# Scaled down LEF created by ScaleLEFMacro.pl
# Original LEF: 16nm/HD_1024X96M8B2.lef
# Don't forget to change metal layer LEF separately!

# Copyright (c) 1993 - 2021 ARM Limited. All Rights Reserved.
# Use of this Software is subject to the terms and conditions of the
# applicable license agreement with ARM Limited.

# PhyVGen V 8.22.0
# ARM Version r3p2
# Creation Date: Thu Sep  9 16:14:09 2021


# Memory Configuration:
# ~~~~~~~~~~~~~~~~~~~~~
#  -activity_factor 50 -atf off -back_biasing off -bits 96 -bmux on
# -bus_notation on -check_instname on -compiler_type sp -diodes on -drive 6
# -ema on -flexible_banking 2 -frequency 1000 -instname HD_1024X96M8B2
# -left_bus_delim "[" -lren_bankmask off -metal_stack 2Xa1Xd -mux 8 -mvt LP
# -name_case upper -pipeline off -power_gating off -power_type otc -prefix ""
# -pwr_gnd_rename vddpe:VDDPE,vddce:VDDCE,vsse:VSSE -rcols 2 -redundancy off
# -retention on -right_bus_delim "]" -rows_p_bl 256 -rrows 0 -scan on -ser none
# -site_def off -top_layer m5-m10 -vmin_assist on -words 1024 -write_mask on
# -write_thru off -corners tt_0p80v_0p80v_25c
# 

VERSION 5.7 ;
BUSBITCHARS "[]" ;
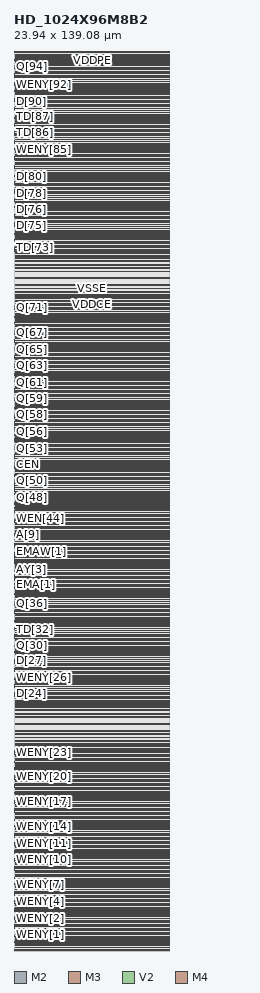
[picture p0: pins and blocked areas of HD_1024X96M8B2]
MACRO HD_1024X96M8B2
	FOREIGN HD_1024X96M8B2 0 0 ;
	SYMMETRY X Y ;
	SIZE 23.94 BY 139.08 ;
	CLASS BLOCK ;
	PIN AY[0]
		USE SIGNAL ;
		DIRECTION OUTPUT ;
		SHAPE ABUTMENT ;
		PORT
			 LAYER M2 ;
			RECT 0.0714 74.6227 0.1097 74.6604 ;
			 LAYER M3 ;
			RECT 0.0714 74.56 0.1097 74.6604 ;
			 LAYER V2 ;
			RECT 0.0831 74.6357 0.098 74.6482 ;
		END

		ANTENNADIFFAREA 0.00194719 ;
		ANTENNAPARTIALMETALAREA 0.00195671 ;
	END AY[0]

	PIN AY[1]
		USE SIGNAL ;
		DIRECTION OUTPUT ;
		SHAPE ABUTMENT ;
		PORT
			 LAYER M2 ;
			RECT 0.0098 73.3553 0.0481 73.3929 ;
			 LAYER M3 ;
			RECT 0.0098 73.3553 0.0481 73.4557 ;
			 LAYER V2 ;
			RECT 0.0215 73.3682 0.0364 73.3808 ;
		END

		ANTENNADIFFAREA 0.00194719 ;
		ANTENNAPARTIALMETALAREA 0.00195671 ;
	END AY[1]

	PIN AY[2]
		USE SIGNAL ;
		DIRECTION OUTPUT ;
		SHAPE ABUTMENT ;
		PORT
			 LAYER M2 ;
			RECT 0.0714 72.2886 0.1097 72.3263 ;
			 LAYER M3 ;
			RECT 0.0714 72.2259 0.1097 72.3263 ;
			 LAYER V2 ;
			RECT 0.0831 72.3016 0.098 72.3141 ;
		END

		ANTENNADIFFAREA 0.00194719 ;
		ANTENNAPARTIALMETALAREA 0.00195671 ;
	END AY[2]

	PIN AY[3]
		USE SIGNAL ;
		DIRECTION OUTPUT ;
		SHAPE ABUTMENT ;
		PORT
			 LAYER M2 ;
			RECT 0.0714 58.9114 0.1097 58.949 ;
			 LAYER M3 ;
			RECT 0.0714 58.9114 0.1097 59.0118 ;
			 LAYER V2 ;
			RECT 0.0831 58.9235 0.098 58.9361 ;
		END

		ANTENNADIFFAREA 0.00194719 ;
		ANTENNAPARTIALMETALAREA 0.00195671 ;
	END AY[3]

	PIN AY[4]
		USE SIGNAL ;
		DIRECTION OUTPUT ;
		SHAPE ABUTMENT ;
		PORT
			 LAYER M2 ;
			RECT 0.0098 68.2353 0.0481 68.2729 ;
			 LAYER M3 ;
			RECT 0.0098 68.1725 0.0481 68.2729 ;
			 LAYER V2 ;
			RECT 0.0215 68.2475 0.0364 68.26 ;
		END

		ANTENNADIFFAREA 0.00194719 ;
		ANTENNAPARTIALMETALAREA 0.00195671 ;
	END AY[4]

	PIN AY[5]
		USE SIGNAL ;
		DIRECTION OUTPUT ;
		SHAPE ABUTMENT ;
		PORT
			 LAYER M2 ;
			RECT 0.0098 61.8478 0.0481 61.9482 ;
			 LAYER M3 ;
			RECT 0.0098 61.8478 0.0481 61.9482 ;
			 LAYER V2 ;
			RECT 0.021 61.8608 0.0359 61.8733 ;
		END

		ANTENNADIFFAREA 0.00194719 ;
		ANTENNAPARTIALMETALAREA 0.00195671 ;
	END AY[5]

	PIN AY[6]
		USE SIGNAL ;
		DIRECTION OUTPUT ;
		SHAPE ABUTMENT ;
		PORT
			 LAYER M2 ;
			RECT 0.0714 59.3631 0.1097 59.4008 ;
			 LAYER M3 ;
			RECT 0.0714 59.3631 0.1097 59.4635 ;
			 LAYER V2 ;
			RECT 0.0831 59.3753 0.098 59.3878 ;
		END

		ANTENNADIFFAREA 0.00194719 ;
		ANTENNAPARTIALMETALAREA 0.00195671 ;
	END AY[6]

	PIN AY[7]
		USE SIGNAL ;
		DIRECTION OUTPUT ;
		SHAPE ABUTMENT ;
		PORT
			 LAYER M2 ;
			RECT 0.0098 60.4925 0.0481 60.5929 ;
			 LAYER M3 ;
			RECT 0.0098 60.4925 0.0481 60.5929 ;
			 LAYER V2 ;
			RECT 0.021 60.5675 0.0359 60.58 ;
		END

		ANTENNADIFFAREA 0.00194719 ;
		ANTENNAPARTIALMETALAREA 0.00195671 ;
	END AY[7]

	PIN AY[8]
		USE SIGNAL ;
		DIRECTION OUTPUT ;
		SHAPE ABUTMENT ;
		PORT
			 LAYER M2 ;
			RECT 0.0098 63.1153 0.0481 63.1529 ;
			 LAYER M3 ;
			RECT 0.0098 63.0525 0.0481 63.1529 ;
			 LAYER V2 ;
			RECT 0.0215 63.1275 0.0364 63.14 ;
		END

		ANTENNADIFFAREA 0.00194719 ;
		ANTENNAPARTIALMETALAREA 0.00195671 ;
	END AY[8]

	PIN AY[9]
		USE SIGNAL ;
		DIRECTION OUTPUT ;
		SHAPE ABUTMENT ;
		PORT
			 LAYER M2 ;
			RECT 0.0714 64.4078 0.1097 64.4455 ;
			 LAYER M3 ;
			RECT 0.0714 64.4078 0.1097 64.5082 ;
			 LAYER V2 ;
			RECT 0.0831 64.42 0.098 64.4325 ;
		END

		ANTENNADIFFAREA 0.00194719 ;
		ANTENNAPARTIALMETALAREA 0.00195671 ;
	END AY[9]

	PIN A[0]
		USE SIGNAL ;
		DIRECTION INPUT ;
		SHAPE ABUTMENT ;
		PORT
			 LAYER M2 ;
			RECT 0.0098 74.7106 0.0481 74.7482 ;
			 LAYER M3 ;
			RECT 0.0098 74.7106 0.0481 74.811 ;
			 LAYER V2 ;
			RECT 0.0215 74.7235 0.0364 74.7361 ;
		END

		ANTENNAGATEAREA 0.00027817 ;
		ANTENNADIFFAREA 0.00194719 ;
		ANTENNAPARTIALMETALAREA 0.00195671 ;
	END A[0]

	PIN A[1]
		USE SIGNAL ;
		DIRECTION INPUT ;
		SHAPE ABUTMENT ;
		PORT
			 LAYER M2 ;
			RECT 0.0714 73.418 0.1097 73.4557 ;
			 LAYER M3 ;
			RECT 0.0714 73.3553 0.1097 73.4557 ;
			 LAYER V2 ;
			RECT 0.0831 73.431 0.098 73.4435 ;
		END

		ANTENNAGATEAREA 0.00027817 ;
		ANTENNADIFFAREA 0.00194719 ;
		ANTENNAPARTIALMETALAREA 0.00195671 ;
	END A[1]

	PIN A[2]
		USE SIGNAL ;
		DIRECTION INPUT ;
		SHAPE ABUTMENT ;
		PORT
			 LAYER M2 ;
			RECT 0.0098 71.7741 0.0481 71.8745 ;
			 LAYER M3 ;
			RECT 0.0098 71.7741 0.0481 71.8745 ;
			 LAYER V2 ;
			RECT 0.021 71.849 0.0359 71.8616 ;
		END

		ANTENNAGATEAREA 0.00027817 ;
		ANTENNADIFFAREA 0.00194719 ;
		ANTENNAPARTIALMETALAREA 0.00195671 ;
	END A[2]

	PIN A[3]
		USE SIGNAL ;
		DIRECTION INPUT ;
		SHAPE ABUTMENT ;
		PORT
			 LAYER M2 ;
			RECT 0.0098 59.1247 0.0481 59.1624 ;
			 LAYER M3 ;
			RECT 0.0098 59.062 0.0481 59.1624 ;
			 LAYER V2 ;
			RECT 0.0215 59.1369 0.0364 59.1494 ;
		END

		ANTENNAGATEAREA 0.00027817 ;
		ANTENNADIFFAREA 0.00194719 ;
		ANTENNAPARTIALMETALAREA 0.00195671 ;
	END A[3]

	PIN A[4]
		USE SIGNAL ;
		DIRECTION INPUT ;
		SHAPE ABUTMENT ;
		PORT
			 LAYER M2 ;
			RECT 0.0098 68.4612 0.0481 68.4988 ;
			 LAYER M3 ;
			RECT 0.0098 68.3984 0.0481 68.4988 ;
			 LAYER V2 ;
			RECT 0.0215 68.4733 0.0364 68.4859 ;
		END

		ANTENNAGATEAREA 0.00027817 ;
		ANTENNADIFFAREA 0.00194719 ;
		ANTENNAPARTIALMETALAREA 0.00195671 ;
	END A[4]

	PIN A[5]
		USE SIGNAL ;
		DIRECTION INPUT ;
		SHAPE ABUTMENT ;
		PORT
			 LAYER M2 ;
			RECT 0.0098 60.1035 0.0481 60.1412 ;
			 LAYER M3 ;
			RECT 0.0098 60.0408 0.0481 60.1412 ;
			 LAYER V2 ;
			RECT 0.0215 60.1157 0.0364 60.1282 ;
		END

		ANTENNAGATEAREA 0.00027817 ;
		ANTENNADIFFAREA 0.00194719 ;
		ANTENNAPARTIALMETALAREA 0.00195671 ;
	END A[5]

	PIN A[6]
		USE SIGNAL ;
		DIRECTION INPUT ;
		SHAPE ABUTMENT ;
		PORT
			 LAYER M2 ;
			RECT 0.0098 59.4259 0.0481 59.4635 ;
			 LAYER M3 ;
			RECT 0.0098 59.3631 0.0481 59.4635 ;
			 LAYER V2 ;
			RECT 0.0215 59.438 0.0364 59.4506 ;
		END

		ANTENNAGATEAREA 0.00027817 ;
		ANTENNADIFFAREA 0.00194719 ;
		ANTENNAPARTIALMETALAREA 0.00195671 ;
	END A[6]

	PIN A[7]
		USE SIGNAL ;
		DIRECTION INPUT ;
		SHAPE ABUTMENT ;
		PORT
			 LAYER M2 ;
			RECT 0.0714 60.342 0.1097 60.3796 ;
			 LAYER M3 ;
			RECT 0.0714 60.342 0.1097 60.4424 ;
			 LAYER V2 ;
			RECT 0.0831 60.3541 0.098 60.3667 ;
		END

		ANTENNAGATEAREA 0.00027817 ;
		ANTENNADIFFAREA 0.00194719 ;
		ANTENNAPARTIALMETALAREA 0.00195671 ;
	END A[7]

	PIN A[8]
		USE SIGNAL ;
		DIRECTION INPUT ;
		SHAPE ABUTMENT ;
		PORT
			 LAYER M2 ;
			RECT 0.0098 62.7388 0.0481 62.7765 ;
			 LAYER M3 ;
			RECT 0.0098 62.6761 0.0481 62.7765 ;
			 LAYER V2 ;
			RECT 0.0215 62.751 0.0364 62.7635 ;
		END

		ANTENNAGATEAREA 0.00027817 ;
		ANTENNADIFFAREA 0.00194719 ;
		ANTENNAPARTIALMETALAREA 0.00195671 ;
	END A[8]

	PIN A[9]
		USE SIGNAL ;
		DIRECTION INPUT ;
		SHAPE ABUTMENT ;
		PORT
			 LAYER M2 ;
			RECT 0.0098 64.32 0.0481 64.3576 ;
			 LAYER M3 ;
			RECT 0.0098 64.2573 0.0481 64.3576 ;
			 LAYER V2 ;
			RECT 0.0215 64.3322 0.0364 64.3447 ;
		END

		ANTENNAGATEAREA 0.00027817 ;
		ANTENNADIFFAREA 0.00194719 ;
		ANTENNAPARTIALMETALAREA 0.00195671 ;
	END A[9]

	PIN CEN
		USE SIGNAL ;
		DIRECTION INPUT ;
		SHAPE ABUTMENT ;
		PORT
			 LAYER M2 ;
			RECT 0.0098 75.1624 0.0481 75.2 ;
			 LAYER M3 ;
			RECT 0.0098 75.1624 0.0481 75.2627 ;
			 LAYER V2 ;
			RECT 0.0215 75.1753 0.0364 75.1878 ;
		END

		ANTENNAGATEAREA 0.00027817 ;
		ANTENNADIFFAREA 0.00194719 ;
		ANTENNAPARTIALMETALAREA 0.00195671 ;
	END CEN

	PIN CENY
		USE SIGNAL ;
		DIRECTION OUTPUT ;
		SHAPE ABUTMENT ;
		PORT
			 LAYER M2 ;
			RECT 0.0098 75.0118 0.0481 75.0494 ;
			 LAYER M3 ;
			RECT 0.0098 75.0118 0.0481 75.1122 ;
			 LAYER V2 ;
			RECT 0.0215 75.0247 0.0364 75.0373 ;
		END

		ANTENNADIFFAREA 0.00194719 ;
		ANTENNAPARTIALMETALAREA 0.00195671 ;
	END CENY

	PIN CLK
		USE SIGNAL ;
		DIRECTION INPUT ;
		SHAPE ABUTMENT ;
		PORT
			 LAYER M2 ;
			RECT 0.0098 77.2706 0.0481 77.371 ;
			 LAYER M3 ;
			RECT 0.0098 77.2706 0.0481 77.371 ;
			 LAYER V2 ;
			RECT 0.021 77.3455 0.0359 77.358 ;
		END

		ANTENNAGATEAREA 0.00027817 ;
		ANTENNADIFFAREA 0.00194719 ;
		ANTENNAPARTIALMETALAREA 0.00195671 ;
	END CLK

	PIN DFTRAMBYP
		USE SIGNAL ;
		DIRECTION INPUT ;
		SHAPE ABUTMENT ;
		PORT
			 LAYER M2 ;
			RECT 0.0098 82.3153 0.0481 82.3529 ;
			 LAYER M3 ;
			RECT 0.0098 82.3153 0.0481 82.4157 ;
			 LAYER V2 ;
			RECT 0.0215 82.3282 0.0364 82.3408 ;
		END

		ANTENNAGATEAREA 0.00027817 ;
		ANTENNADIFFAREA 0.00194719 ;
		ANTENNAPARTIALMETALAREA 0.00195671 ;
	END DFTRAMBYP

	PIN D[0]
		USE SIGNAL ;
		DIRECTION INPUT ;
		SHAPE ABUTMENT ;
		PORT
			 LAYER M2 ;
			RECT 0.0098 1.3678 0.0481 1.4055 ;
			 LAYER M3 ;
			RECT 0.0098 1.3678 0.0481 1.4682 ;
			 LAYER V2 ;
			RECT 0.0215 1.3808 0.0364 1.3933 ;
		END

		ANTENNAGATEAREA 0.00027817 ;
		ANTENNADIFFAREA 0.00194719 ;
		ANTENNAPARTIALMETALAREA 0.00195671 ;
	END D[0]

	PIN D[10]
		USE SIGNAL ;
		DIRECTION INPUT ;
		SHAPE ABUTMENT ;
		PORT
			 LAYER M2 ;
			RECT 0.0098 14.1678 0.0481 14.2055 ;
			 LAYER M3 ;
			RECT 0.0098 14.1678 0.0481 14.2682 ;
			 LAYER V2 ;
			RECT 0.0215 14.1808 0.0364 14.1933 ;
		END

		ANTENNAGATEAREA 0.00027817 ;
		ANTENNADIFFAREA 0.00194719 ;
		ANTENNAPARTIALMETALAREA 0.00195671 ;
	END D[10]

	PIN D[11]
		USE SIGNAL ;
		DIRECTION INPUT ;
		SHAPE ABUTMENT ;
		PORT
			 LAYER M2 ;
			RECT 0.0098 15.4478 0.0481 15.4855 ;
			 LAYER M3 ;
			RECT 0.0098 15.4478 0.0481 15.5482 ;
			 LAYER V2 ;
			RECT 0.0215 15.4608 0.0364 15.4733 ;
		END

		ANTENNAGATEAREA 0.00027817 ;
		ANTENNADIFFAREA 0.00194719 ;
		ANTENNAPARTIALMETALAREA 0.00195671 ;
	END D[11]

	PIN D[12]
		USE SIGNAL ;
		DIRECTION INPUT ;
		SHAPE ABUTMENT ;
		PORT
			 LAYER M2 ;
			RECT 0.0098 16.7278 0.0481 16.7655 ;
			 LAYER M3 ;
			RECT 0.0098 16.7278 0.0481 16.8282 ;
			 LAYER V2 ;
			RECT 0.0215 16.7408 0.0364 16.7533 ;
		END

		ANTENNAGATEAREA 0.00027817 ;
		ANTENNADIFFAREA 0.00194719 ;
		ANTENNAPARTIALMETALAREA 0.00195671 ;
	END D[12]

	PIN D[13]
		USE SIGNAL ;
		DIRECTION INPUT ;
		SHAPE ABUTMENT ;
		PORT
			 LAYER M2 ;
			RECT 0.0098 18.0078 0.0481 18.0455 ;
			 LAYER M3 ;
			RECT 0.0098 18.0078 0.0481 18.1082 ;
			 LAYER V2 ;
			RECT 0.0215 18.0208 0.0364 18.0333 ;
		END

		ANTENNAGATEAREA 0.00027817 ;
		ANTENNADIFFAREA 0.00194719 ;
		ANTENNAPARTIALMETALAREA 0.00195671 ;
	END D[13]

	PIN D[14]
		USE SIGNAL ;
		DIRECTION INPUT ;
		SHAPE ABUTMENT ;
		PORT
			 LAYER M2 ;
			RECT 0.0098 19.2878 0.0481 19.3255 ;
			 LAYER M3 ;
			RECT 0.0098 19.2878 0.0481 19.3882 ;
			 LAYER V2 ;
			RECT 0.0215 19.3008 0.0364 19.3133 ;
		END

		ANTENNAGATEAREA 0.00027817 ;
		ANTENNADIFFAREA 0.00194719 ;
		ANTENNAPARTIALMETALAREA 0.00195671 ;
	END D[14]

	PIN D[15]
		USE SIGNAL ;
		DIRECTION INPUT ;
		SHAPE ABUTMENT ;
		PORT
			 LAYER M2 ;
			RECT 0.0098 20.5678 0.0481 20.6055 ;
			 LAYER M3 ;
			RECT 0.0098 20.5678 0.0481 20.6682 ;
			 LAYER V2 ;
			RECT 0.0215 20.5808 0.0364 20.5933 ;
		END

		ANTENNAGATEAREA 0.00027817 ;
		ANTENNADIFFAREA 0.00194719 ;
		ANTENNAPARTIALMETALAREA 0.00195671 ;
	END D[15]

	PIN D[16]
		USE SIGNAL ;
		DIRECTION INPUT ;
		SHAPE ABUTMENT ;
		PORT
			 LAYER M2 ;
			RECT 0.0098 21.8478 0.0481 21.8855 ;
			 LAYER M3 ;
			RECT 0.0098 21.8478 0.0481 21.9482 ;
			 LAYER V2 ;
			RECT 0.0215 21.8608 0.0364 21.8733 ;
		END

		ANTENNAGATEAREA 0.00027817 ;
		ANTENNADIFFAREA 0.00194719 ;
		ANTENNAPARTIALMETALAREA 0.00195671 ;
	END D[16]

	PIN D[17]
		USE SIGNAL ;
		DIRECTION INPUT ;
		SHAPE ABUTMENT ;
		PORT
			 LAYER M2 ;
			RECT 0.0098 23.1278 0.0481 23.1655 ;
			 LAYER M3 ;
			RECT 0.0098 23.1278 0.0481 23.2282 ;
			 LAYER V2 ;
			RECT 0.0215 23.1408 0.0364 23.1533 ;
		END

		ANTENNAGATEAREA 0.00027817 ;
		ANTENNADIFFAREA 0.00194719 ;
		ANTENNAPARTIALMETALAREA 0.00195671 ;
	END D[17]

	PIN D[18]
		USE SIGNAL ;
		DIRECTION INPUT ;
		SHAPE ABUTMENT ;
		PORT
			 LAYER M2 ;
			RECT 0.0098 24.4078 0.0481 24.4455 ;
			 LAYER M3 ;
			RECT 0.0098 24.4078 0.0481 24.5082 ;
			 LAYER V2 ;
			RECT 0.0215 24.4208 0.0364 24.4333 ;
		END

		ANTENNAGATEAREA 0.00027817 ;
		ANTENNADIFFAREA 0.00194719 ;
		ANTENNAPARTIALMETALAREA 0.00195671 ;
	END D[18]

	PIN D[19]
		USE SIGNAL ;
		DIRECTION INPUT ;
		SHAPE ABUTMENT ;
		PORT
			 LAYER M2 ;
			RECT 0.0098 25.6878 0.0481 25.7255 ;
			 LAYER M3 ;
			RECT 0.0098 25.6878 0.0481 25.7882 ;
			 LAYER V2 ;
			RECT 0.0215 25.7008 0.0364 25.7133 ;
		END

		ANTENNAGATEAREA 0.00027817 ;
		ANTENNADIFFAREA 0.00194719 ;
		ANTENNAPARTIALMETALAREA 0.00195671 ;
	END D[19]

	PIN D[1]
		USE SIGNAL ;
		DIRECTION INPUT ;
		SHAPE ABUTMENT ;
		PORT
			 LAYER M2 ;
			RECT 0.0098 2.6478 0.0481 2.6855 ;
			 LAYER M3 ;
			RECT 0.0098 2.6478 0.0481 2.7482 ;
			 LAYER V2 ;
			RECT 0.0215 2.6608 0.0364 2.6733 ;
		END

		ANTENNAGATEAREA 0.00027817 ;
		ANTENNADIFFAREA 0.00194719 ;
		ANTENNAPARTIALMETALAREA 0.00195671 ;
	END D[1]

	PIN D[20]
		USE SIGNAL ;
		DIRECTION INPUT ;
		SHAPE ABUTMENT ;
		PORT
			 LAYER M2 ;
			RECT 0.0098 26.9678 0.0481 27.0055 ;
			 LAYER M3 ;
			RECT 0.0098 26.9678 0.0481 27.0682 ;
			 LAYER V2 ;
			RECT 0.0215 26.9808 0.0364 26.9933 ;
		END

		ANTENNAGATEAREA 0.00027817 ;
		ANTENNADIFFAREA 0.00194719 ;
		ANTENNAPARTIALMETALAREA 0.00195671 ;
	END D[20]

	PIN D[21]
		USE SIGNAL ;
		DIRECTION INPUT ;
		SHAPE ABUTMENT ;
		PORT
			 LAYER M2 ;
			RECT 0.0098 28.2478 0.0481 28.2855 ;
			 LAYER M3 ;
			RECT 0.0098 28.2478 0.0481 28.3482 ;
			 LAYER V2 ;
			RECT 0.0215 28.2608 0.0364 28.2733 ;
		END

		ANTENNAGATEAREA 0.00027817 ;
		ANTENNADIFFAREA 0.00194719 ;
		ANTENNAPARTIALMETALAREA 0.00195671 ;
	END D[21]

	PIN D[22]
		USE SIGNAL ;
		DIRECTION INPUT ;
		SHAPE ABUTMENT ;
		PORT
			 LAYER M2 ;
			RECT 0.0098 29.5278 0.0481 29.5655 ;
			 LAYER M3 ;
			RECT 0.0098 29.5278 0.0481 29.6282 ;
			 LAYER V2 ;
			RECT 0.0215 29.5408 0.0364 29.5533 ;
		END

		ANTENNAGATEAREA 0.00027817 ;
		ANTENNADIFFAREA 0.00194719 ;
		ANTENNAPARTIALMETALAREA 0.00195671 ;
	END D[22]

	PIN D[23]
		USE SIGNAL ;
		DIRECTION INPUT ;
		SHAPE ABUTMENT ;
		PORT
			 LAYER M2 ;
			RECT 0.0098 30.8078 0.0481 30.8455 ;
			 LAYER M3 ;
			RECT 0.0098 30.8078 0.0481 30.9082 ;
			 LAYER V2 ;
			RECT 0.0215 30.8208 0.0364 30.8333 ;
		END

		ANTENNAGATEAREA 0.00027817 ;
		ANTENNADIFFAREA 0.00194719 ;
		ANTENNAPARTIALMETALAREA 0.00195671 ;
	END D[23]

	PIN D[24]
		USE SIGNAL ;
		DIRECTION INPUT ;
		SHAPE ABUTMENT ;
		PORT
			 LAYER M2 ;
			RECT 0.0098 39.7867 0.0481 39.8243 ;
			 LAYER M3 ;
			RECT 0.0098 39.7867 0.0481 39.8871 ;
			 LAYER V2 ;
			RECT 0.0215 39.7996 0.0364 39.8122 ;
		END

		ANTENNAGATEAREA 0.00027817 ;
		ANTENNADIFFAREA 0.00194719 ;
		ANTENNAPARTIALMETALAREA 0.00195671 ;
	END D[24]

	PIN D[25]
		USE SIGNAL ;
		DIRECTION INPUT ;
		SHAPE ABUTMENT ;
		PORT
			 LAYER M2 ;
			RECT 0.0098 41.0667 0.0481 41.1043 ;
			 LAYER M3 ;
			RECT 0.0098 41.0667 0.0481 41.1671 ;
			 LAYER V2 ;
			RECT 0.0215 41.0796 0.0364 41.0922 ;
		END

		ANTENNAGATEAREA 0.00027817 ;
		ANTENNADIFFAREA 0.00194719 ;
		ANTENNAPARTIALMETALAREA 0.00195671 ;
	END D[25]

	PIN D[26]
		USE SIGNAL ;
		DIRECTION INPUT ;
		SHAPE ABUTMENT ;
		PORT
			 LAYER M2 ;
			RECT 0.0098 42.3467 0.0481 42.3843 ;
			 LAYER M3 ;
			RECT 0.0098 42.3467 0.0481 42.4471 ;
			 LAYER V2 ;
			RECT 0.0215 42.3596 0.0364 42.3722 ;
		END

		ANTENNAGATEAREA 0.00027817 ;
		ANTENNADIFFAREA 0.00194719 ;
		ANTENNAPARTIALMETALAREA 0.00195671 ;
	END D[26]

	PIN D[27]
		USE SIGNAL ;
		DIRECTION INPUT ;
		SHAPE ABUTMENT ;
		PORT
			 LAYER M2 ;
			RECT 0.0098 43.6267 0.0481 43.6643 ;
			 LAYER M3 ;
			RECT 0.0098 43.6267 0.0481 43.7271 ;
			 LAYER V2 ;
			RECT 0.0215 43.6396 0.0364 43.6522 ;
		END

		ANTENNAGATEAREA 0.00027817 ;
		ANTENNADIFFAREA 0.00194719 ;
		ANTENNAPARTIALMETALAREA 0.00195671 ;
	END D[27]

	PIN D[28]
		USE SIGNAL ;
		DIRECTION INPUT ;
		SHAPE ABUTMENT ;
		PORT
			 LAYER M2 ;
			RECT 0.0098 44.9067 0.0481 44.9443 ;
			 LAYER M3 ;
			RECT 0.0098 44.9067 0.0481 45.0071 ;
			 LAYER V2 ;
			RECT 0.0215 44.9196 0.0364 44.9322 ;
		END

		ANTENNAGATEAREA 0.00027817 ;
		ANTENNADIFFAREA 0.00194719 ;
		ANTENNAPARTIALMETALAREA 0.00195671 ;
	END D[28]

	PIN D[29]
		USE SIGNAL ;
		DIRECTION INPUT ;
		SHAPE ABUTMENT ;
		PORT
			 LAYER M2 ;
			RECT 0.0098 46.1867 0.0481 46.2243 ;
			 LAYER M3 ;
			RECT 0.0098 46.1867 0.0481 46.2871 ;
			 LAYER V2 ;
			RECT 0.0215 46.1996 0.0364 46.2122 ;
		END

		ANTENNAGATEAREA 0.00027817 ;
		ANTENNADIFFAREA 0.00194719 ;
		ANTENNAPARTIALMETALAREA 0.00195671 ;
	END D[29]

	PIN D[2]
		USE SIGNAL ;
		DIRECTION INPUT ;
		SHAPE ABUTMENT ;
		PORT
			 LAYER M2 ;
			RECT 0.0098 3.9278 0.0481 3.9655 ;
			 LAYER M3 ;
			RECT 0.0098 3.9278 0.0481 4.0282 ;
			 LAYER V2 ;
			RECT 0.0215 3.9408 0.0364 3.9533 ;
		END

		ANTENNAGATEAREA 0.00027817 ;
		ANTENNADIFFAREA 0.00194719 ;
		ANTENNAPARTIALMETALAREA 0.00195671 ;
	END D[2]

	PIN D[30]
		USE SIGNAL ;
		DIRECTION INPUT ;
		SHAPE ABUTMENT ;
		PORT
			 LAYER M2 ;
			RECT 0.0098 47.4667 0.0481 47.5043 ;
			 LAYER M3 ;
			RECT 0.0098 47.4667 0.0481 47.5671 ;
			 LAYER V2 ;
			RECT 0.0215 47.4796 0.0364 47.4922 ;
		END

		ANTENNAGATEAREA 0.00027817 ;
		ANTENNADIFFAREA 0.00194719 ;
		ANTENNAPARTIALMETALAREA 0.00195671 ;
	END D[30]

	PIN D[31]
		USE SIGNAL ;
		DIRECTION INPUT ;
		SHAPE ABUTMENT ;
		PORT
			 LAYER M2 ;
			RECT 0.0098 48.7467 0.0481 48.7843 ;
			 LAYER M3 ;
			RECT 0.0098 48.7467 0.0481 48.8471 ;
			 LAYER V2 ;
			RECT 0.0215 48.7596 0.0364 48.7722 ;
		END

		ANTENNAGATEAREA 0.00027817 ;
		ANTENNADIFFAREA 0.00194719 ;
		ANTENNAPARTIALMETALAREA 0.00195671 ;
	END D[31]

	PIN D[32]
		USE SIGNAL ;
		DIRECTION INPUT ;
		SHAPE ABUTMENT ;
		PORT
			 LAYER M2 ;
			RECT 0.0098 50.0267 0.0481 50.0643 ;
			 LAYER M3 ;
			RECT 0.0098 50.0267 0.0481 50.1271 ;
			 LAYER V2 ;
			RECT 0.0215 50.0396 0.0364 50.0522 ;
		END

		ANTENNAGATEAREA 0.00027817 ;
		ANTENNADIFFAREA 0.00194719 ;
		ANTENNAPARTIALMETALAREA 0.00195671 ;
	END D[32]

	PIN D[33]
		USE SIGNAL ;
		DIRECTION INPUT ;
		SHAPE ABUTMENT ;
		PORT
			 LAYER M2 ;
			RECT 0.0098 51.3067 0.0481 51.3443 ;
			 LAYER M3 ;
			RECT 0.0098 51.3067 0.0481 51.4071 ;
			 LAYER V2 ;
			RECT 0.0215 51.3196 0.0364 51.3322 ;
		END

		ANTENNAGATEAREA 0.00027817 ;
		ANTENNADIFFAREA 0.00194719 ;
		ANTENNAPARTIALMETALAREA 0.00195671 ;
	END D[33]

	PIN D[34]
		USE SIGNAL ;
		DIRECTION INPUT ;
		SHAPE ABUTMENT ;
		PORT
			 LAYER M2 ;
			RECT 0.0098 52.5867 0.0481 52.6243 ;
			 LAYER M3 ;
			RECT 0.0098 52.5867 0.0481 52.6871 ;
			 LAYER V2 ;
			RECT 0.0215 52.5996 0.0364 52.6122 ;
		END

		ANTENNAGATEAREA 0.00027817 ;
		ANTENNADIFFAREA 0.00194719 ;
		ANTENNAPARTIALMETALAREA 0.00195671 ;
	END D[34]

	PIN D[35]
		USE SIGNAL ;
		DIRECTION INPUT ;
		SHAPE ABUTMENT ;
		PORT
			 LAYER M2 ;
			RECT 0.0098 53.8667 0.0481 53.9043 ;
			 LAYER M3 ;
			RECT 0.0098 53.8667 0.0481 53.9671 ;
			 LAYER V2 ;
			RECT 0.0215 53.8796 0.0364 53.8922 ;
		END

		ANTENNAGATEAREA 0.00027817 ;
		ANTENNADIFFAREA 0.00194719 ;
		ANTENNAPARTIALMETALAREA 0.00195671 ;
	END D[35]

	PIN D[36]
		USE SIGNAL ;
		DIRECTION INPUT ;
		SHAPE ABUTMENT ;
		PORT
			 LAYER M2 ;
			RECT 0.0098 55.1467 0.0481 55.1843 ;
			 LAYER M3 ;
			RECT 0.0098 55.1467 0.0481 55.2471 ;
			 LAYER V2 ;
			RECT 0.0215 55.1596 0.0364 55.1722 ;
		END

		ANTENNAGATEAREA 0.00027817 ;
		ANTENNADIFFAREA 0.00194719 ;
		ANTENNAPARTIALMETALAREA 0.00195671 ;
	END D[36]

	PIN D[37]
		USE SIGNAL ;
		DIRECTION INPUT ;
		SHAPE ABUTMENT ;
		PORT
			 LAYER M2 ;
			RECT 0.0098 56.4267 0.0481 56.4643 ;
			 LAYER M3 ;
			RECT 0.0098 56.4267 0.0481 56.5271 ;
			 LAYER V2 ;
			RECT 0.0215 56.4396 0.0364 56.4522 ;
		END

		ANTENNAGATEAREA 0.00027817 ;
		ANTENNADIFFAREA 0.00194719 ;
		ANTENNAPARTIALMETALAREA 0.00195671 ;
	END D[37]

	PIN D[38]
		USE SIGNAL ;
		DIRECTION INPUT ;
		SHAPE ABUTMENT ;
		PORT
			 LAYER M2 ;
			RECT 0.0098 57.3176 0.0481 57.3553 ;
			 LAYER M3 ;
			RECT 0.0098 57.2549 0.0481 57.3553 ;
			 LAYER V2 ;
			RECT 0.0215 57.3298 0.0364 57.3424 ;
		END

		ANTENNAGATEAREA 0.00027817 ;
		ANTENNADIFFAREA 0.00194719 ;
		ANTENNAPARTIALMETALAREA 0.00195671 ;
	END D[38]

	PIN D[39]
		USE SIGNAL ;
		DIRECTION INPUT ;
		SHAPE ABUTMENT ;
		PORT
			 LAYER M2 ;
			RECT 0.0098 58.5976 0.0481 58.6353 ;
			 LAYER M3 ;
			RECT 0.0098 58.5349 0.0481 58.6353 ;
			 LAYER V2 ;
			RECT 0.0215 58.6098 0.0364 58.6224 ;
		END

		ANTENNAGATEAREA 0.00027817 ;
		ANTENNADIFFAREA 0.00194719 ;
		ANTENNAPARTIALMETALAREA 0.00195671 ;
	END D[39]

	PIN D[3]
		USE SIGNAL ;
		DIRECTION INPUT ;
		SHAPE ABUTMENT ;
		PORT
			 LAYER M2 ;
			RECT 0.0098 5.2078 0.0481 5.2455 ;
			 LAYER M3 ;
			RECT 0.0098 5.2078 0.0481 5.3082 ;
			 LAYER V2 ;
			RECT 0.0215 5.2208 0.0364 5.2333 ;
		END

		ANTENNAGATEAREA 0.00027817 ;
		ANTENNADIFFAREA 0.00194719 ;
		ANTENNAPARTIALMETALAREA 0.00195671 ;
	END D[3]

	PIN D[40]
		USE SIGNAL ;
		DIRECTION INPUT ;
		SHAPE ABUTMENT ;
		PORT
			 LAYER M2 ;
			RECT 0.0098 59.7271 0.0481 59.7647 ;
			 LAYER M3 ;
			RECT 0.0098 59.6643 0.0481 59.7647 ;
			 LAYER V2 ;
			RECT 0.0215 59.7392 0.0364 59.7518 ;
		END

		ANTENNAGATEAREA 0.00027817 ;
		ANTENNADIFFAREA 0.00194719 ;
		ANTENNAPARTIALMETALAREA 0.00195671 ;
	END D[40]

	PIN D[41]
		USE SIGNAL ;
		DIRECTION INPUT ;
		SHAPE ABUTMENT ;
		PORT
			 LAYER M2 ;
			RECT 0.0098 61.1576 0.0481 61.1953 ;
			 LAYER M3 ;
			RECT 0.0098 61.0949 0.0481 61.1953 ;
			 LAYER V2 ;
			RECT 0.0215 61.1698 0.0364 61.1824 ;
		END

		ANTENNAGATEAREA 0.00027817 ;
		ANTENNADIFFAREA 0.00194719 ;
		ANTENNAPARTIALMETALAREA 0.00195671 ;
	END D[41]

	PIN D[42]
		USE SIGNAL ;
		DIRECTION INPUT ;
		SHAPE ABUTMENT ;
		PORT
			 LAYER M2 ;
			RECT 0.0098 62.4376 0.0481 62.4753 ;
			 LAYER M3 ;
			RECT 0.0098 62.3749 0.0481 62.4753 ;
			 LAYER V2 ;
			RECT 0.0215 62.4498 0.0364 62.4624 ;
		END

		ANTENNAGATEAREA 0.00027817 ;
		ANTENNADIFFAREA 0.00194719 ;
		ANTENNAPARTIALMETALAREA 0.00195671 ;
	END D[42]

	PIN D[43]
		USE SIGNAL ;
		DIRECTION INPUT ;
		SHAPE ABUTMENT ;
		PORT
			 LAYER M2 ;
			RECT 0.0098 63.7176 0.0481 63.7553 ;
			 LAYER M3 ;
			RECT 0.0098 63.6549 0.0481 63.7553 ;
			 LAYER V2 ;
			RECT 0.0215 63.7298 0.0364 63.7424 ;
		END

		ANTENNAGATEAREA 0.00027817 ;
		ANTENNADIFFAREA 0.00194719 ;
		ANTENNAPARTIALMETALAREA 0.00195671 ;
	END D[43]

	PIN D[44]
		USE SIGNAL ;
		DIRECTION INPUT ;
		SHAPE ABUTMENT ;
		PORT
			 LAYER M2 ;
			RECT 0.0098 64.9976 0.0481 65.0353 ;
			 LAYER M3 ;
			RECT 0.0098 64.9349 0.0481 65.0353 ;
			 LAYER V2 ;
			RECT 0.0215 65.0098 0.0364 65.0224 ;
		END

		ANTENNAGATEAREA 0.00027817 ;
		ANTENNADIFFAREA 0.00194719 ;
		ANTENNAPARTIALMETALAREA 0.00195671 ;
	END D[44]

	PIN D[45]
		USE SIGNAL ;
		DIRECTION INPUT ;
		SHAPE ABUTMENT ;
		PORT
			 LAYER M2 ;
			RECT 0.0098 66.2776 0.0481 66.3153 ;
			 LAYER M3 ;
			RECT 0.0098 66.2149 0.0481 66.3153 ;
			 LAYER V2 ;
			RECT 0.0215 66.2898 0.0364 66.3024 ;
		END

		ANTENNAGATEAREA 0.00027817 ;
		ANTENNADIFFAREA 0.00194719 ;
		ANTENNAPARTIALMETALAREA 0.00195671 ;
	END D[45]

	PIN D[46]
		USE SIGNAL ;
		DIRECTION INPUT ;
		SHAPE ABUTMENT ;
		PORT
			 LAYER M2 ;
			RECT 0.0098 67.5576 0.0481 67.5953 ;
			 LAYER M3 ;
			RECT 0.0098 67.4949 0.0481 67.5953 ;
			 LAYER V2 ;
			RECT 0.0215 67.5698 0.0364 67.5824 ;
		END

		ANTENNAGATEAREA 0.00027817 ;
		ANTENNADIFFAREA 0.00194719 ;
		ANTENNAPARTIALMETALAREA 0.00195671 ;
	END D[46]

	PIN D[47]
		USE SIGNAL ;
		DIRECTION INPUT ;
		SHAPE ABUTMENT ;
		PORT
			 LAYER M2 ;
			RECT 0.0098 68.8376 0.0481 68.8753 ;
			 LAYER M3 ;
			RECT 0.0098 68.7749 0.0481 68.8753 ;
			 LAYER V2 ;
			RECT 0.0215 68.8498 0.0364 68.8624 ;
		END

		ANTENNAGATEAREA 0.00027817 ;
		ANTENNADIFFAREA 0.00194719 ;
		ANTENNAPARTIALMETALAREA 0.00195671 ;
	END D[47]

	PIN D[48]
		USE SIGNAL ;
		DIRECTION INPUT ;
		SHAPE ABUTMENT ;
		PORT
			 LAYER M2 ;
			RECT 0.0098 70.1929 0.0481 70.2306 ;
			 LAYER M3 ;
			RECT 0.0098 70.1929 0.0481 70.2933 ;
			 LAYER V2 ;
			RECT 0.0215 70.2059 0.0364 70.2184 ;
		END

		ANTENNAGATEAREA 0.00027817 ;
		ANTENNADIFFAREA 0.00194719 ;
		ANTENNAPARTIALMETALAREA 0.00195671 ;
	END D[48]

	PIN D[49]
		USE SIGNAL ;
		DIRECTION INPUT ;
		SHAPE ABUTMENT ;
		PORT
			 LAYER M2 ;
			RECT 0.0098 71.4729 0.0481 71.5106 ;
			 LAYER M3 ;
			RECT 0.0098 71.4729 0.0481 71.5733 ;
			 LAYER V2 ;
			RECT 0.0215 71.4859 0.0364 71.4984 ;
		END

		ANTENNAGATEAREA 0.00027817 ;
		ANTENNADIFFAREA 0.00194719 ;
		ANTENNAPARTIALMETALAREA 0.00195671 ;
	END D[49]

	PIN D[4]
		USE SIGNAL ;
		DIRECTION INPUT ;
		SHAPE ABUTMENT ;
		PORT
			 LAYER M2 ;
			RECT 0.0098 6.4878 0.0481 6.5255 ;
			 LAYER M3 ;
			RECT 0.0098 6.4878 0.0481 6.5882 ;
			 LAYER V2 ;
			RECT 0.0215 6.5008 0.0364 6.5133 ;
		END

		ANTENNAGATEAREA 0.00027817 ;
		ANTENNADIFFAREA 0.00194719 ;
		ANTENNAPARTIALMETALAREA 0.00195671 ;
	END D[4]

	PIN D[50]
		USE SIGNAL ;
		DIRECTION INPUT ;
		SHAPE ABUTMENT ;
		PORT
			 LAYER M2 ;
			RECT 0.0098 72.7529 0.0481 72.7906 ;
			 LAYER M3 ;
			RECT 0.0098 72.7529 0.0481 72.8533 ;
			 LAYER V2 ;
			RECT 0.0215 72.7659 0.0364 72.7784 ;
		END

		ANTENNAGATEAREA 0.00027817 ;
		ANTENNADIFFAREA 0.00194719 ;
		ANTENNAPARTIALMETALAREA 0.00195671 ;
	END D[50]

	PIN D[51]
		USE SIGNAL ;
		DIRECTION INPUT ;
		SHAPE ABUTMENT ;
		PORT
			 LAYER M2 ;
			RECT 0.0098 74.0329 0.0481 74.0706 ;
			 LAYER M3 ;
			RECT 0.0098 74.0329 0.0481 74.1333 ;
			 LAYER V2 ;
			RECT 0.0215 74.0459 0.0364 74.0584 ;
		END

		ANTENNAGATEAREA 0.00027817 ;
		ANTENNADIFFAREA 0.00194719 ;
		ANTENNAPARTIALMETALAREA 0.00195671 ;
	END D[51]

	PIN D[52]
		USE SIGNAL ;
		DIRECTION INPUT ;
		SHAPE ABUTMENT ;
		PORT
			 LAYER M2 ;
			RECT 0.0098 75.3129 0.0481 75.3506 ;
			 LAYER M3 ;
			RECT 0.0098 75.3129 0.0481 75.4133 ;
			 LAYER V2 ;
			RECT 0.0215 75.3259 0.0364 75.3384 ;
		END

		ANTENNAGATEAREA 0.00027817 ;
		ANTENNADIFFAREA 0.00194719 ;
		ANTENNAPARTIALMETALAREA 0.00195671 ;
	END D[52]

	PIN D[53]
		USE SIGNAL ;
		DIRECTION INPUT ;
		SHAPE ABUTMENT ;
		PORT
			 LAYER M2 ;
			RECT 0.0098 76.5929 0.0481 76.6306 ;
			 LAYER M3 ;
			RECT 0.0098 76.5929 0.0481 76.6933 ;
			 LAYER V2 ;
			RECT 0.0215 76.6059 0.0364 76.6184 ;
		END

		ANTENNAGATEAREA 0.00027817 ;
		ANTENNADIFFAREA 0.00194719 ;
		ANTENNAPARTIALMETALAREA 0.00195671 ;
	END D[53]

	PIN D[54]
		USE SIGNAL ;
		DIRECTION INPUT ;
		SHAPE ABUTMENT ;
		PORT
			 LAYER M2 ;
			RECT 0.0098 77.8729 0.0481 77.9106 ;
			 LAYER M3 ;
			RECT 0.0098 77.8729 0.0481 77.9733 ;
			 LAYER V2 ;
			RECT 0.0215 77.8859 0.0364 77.8984 ;
		END

		ANTENNAGATEAREA 0.00027817 ;
		ANTENNADIFFAREA 0.00194719 ;
		ANTENNAPARTIALMETALAREA 0.00195671 ;
	END D[54]

	PIN D[55]
		USE SIGNAL ;
		DIRECTION INPUT ;
		SHAPE ABUTMENT ;
		PORT
			 LAYER M2 ;
			RECT 0.0098 79.3035 0.0481 79.3412 ;
			 LAYER M3 ;
			RECT 0.0098 79.3035 0.0481 79.4039 ;
			 LAYER V2 ;
			RECT 0.0215 79.3165 0.0364 79.329 ;
		END

		ANTENNAGATEAREA 0.00027817 ;
		ANTENNADIFFAREA 0.00194719 ;
		ANTENNAPARTIALMETALAREA 0.00195671 ;
	END D[55]

	PIN D[56]
		USE SIGNAL ;
		DIRECTION INPUT ;
		SHAPE ABUTMENT ;
		PORT
			 LAYER M2 ;
			RECT 0.0098 80.4329 0.0481 80.4706 ;
			 LAYER M3 ;
			RECT 0.0098 80.4329 0.0481 80.5333 ;
			 LAYER V2 ;
			RECT 0.0215 80.4459 0.0364 80.4584 ;
		END

		ANTENNAGATEAREA 0.00027817 ;
		ANTENNADIFFAREA 0.00194719 ;
		ANTENNAPARTIALMETALAREA 0.00195671 ;
	END D[56]

	PIN D[57]
		USE SIGNAL ;
		DIRECTION INPUT ;
		SHAPE ABUTMENT ;
		PORT
			 LAYER M2 ;
			RECT 0.0098 81.4118 0.0481 81.4494 ;
			 LAYER M3 ;
			RECT 0.0098 81.4118 0.0481 81.5122 ;
			 LAYER V2 ;
			RECT 0.0215 81.4247 0.0364 81.4373 ;
		END

		ANTENNAGATEAREA 0.00027817 ;
		ANTENNADIFFAREA 0.00194719 ;
		ANTENNAPARTIALMETALAREA 0.00195671 ;
	END D[57]

	PIN D[58]
		USE SIGNAL ;
		DIRECTION INPUT ;
		SHAPE ABUTMENT ;
		PORT
			 LAYER M2 ;
			RECT 0.0098 82.6039 0.0481 82.6416 ;
			 LAYER M3 ;
			RECT 0.0098 82.5412 0.0481 82.6416 ;
			 LAYER V2 ;
			RECT 0.0215 82.6161 0.0364 82.6286 ;
		END

		ANTENNAGATEAREA 0.00027817 ;
		ANTENNADIFFAREA 0.00194719 ;
		ANTENNAPARTIALMETALAREA 0.00195671 ;
	END D[58]

	PIN D[59]
		USE SIGNAL ;
		DIRECTION INPUT ;
		SHAPE ABUTMENT ;
		PORT
			 LAYER M2 ;
			RECT 0.0098 83.8839 0.0481 83.9216 ;
			 LAYER M3 ;
			RECT 0.0098 83.8212 0.0481 83.9216 ;
			 LAYER V2 ;
			RECT 0.0215 83.8961 0.0364 83.9086 ;
		END

		ANTENNAGATEAREA 0.00027817 ;
		ANTENNADIFFAREA 0.00194719 ;
		ANTENNAPARTIALMETALAREA 0.00195671 ;
	END D[59]

	PIN D[5]
		USE SIGNAL ;
		DIRECTION INPUT ;
		SHAPE ABUTMENT ;
		PORT
			 LAYER M2 ;
			RECT 0.0098 7.7678 0.0481 7.8055 ;
			 LAYER M3 ;
			RECT 0.0098 7.7678 0.0481 7.8682 ;
			 LAYER V2 ;
			RECT 0.0215 7.7808 0.0364 7.7933 ;
		END

		ANTENNAGATEAREA 0.00027817 ;
		ANTENNADIFFAREA 0.00194719 ;
		ANTENNAPARTIALMETALAREA 0.00195671 ;
	END D[5]

	PIN D[60]
		USE SIGNAL ;
		DIRECTION INPUT ;
		SHAPE ABUTMENT ;
		PORT
			 LAYER M2 ;
			RECT 0.0098 85.1639 0.0481 85.2016 ;
			 LAYER M3 ;
			RECT 0.0098 85.1012 0.0481 85.2016 ;
			 LAYER V2 ;
			RECT 0.0215 85.1761 0.0364 85.1886 ;
		END

		ANTENNAGATEAREA 0.00027817 ;
		ANTENNADIFFAREA 0.00194719 ;
		ANTENNAPARTIALMETALAREA 0.00195671 ;
	END D[60]

	PIN D[61]
		USE SIGNAL ;
		DIRECTION INPUT ;
		SHAPE ABUTMENT ;
		PORT
			 LAYER M2 ;
			RECT 0.0098 86.4439 0.0481 86.4816 ;
			 LAYER M3 ;
			RECT 0.0098 86.3812 0.0481 86.4816 ;
			 LAYER V2 ;
			RECT 0.0215 86.4561 0.0364 86.4686 ;
		END

		ANTENNAGATEAREA 0.00027817 ;
		ANTENNADIFFAREA 0.00194719 ;
		ANTENNAPARTIALMETALAREA 0.00195671 ;
	END D[61]

	PIN D[62]
		USE SIGNAL ;
		DIRECTION INPUT ;
		SHAPE ABUTMENT ;
		PORT
			 LAYER M2 ;
			RECT 0.0098 87.7239 0.0481 87.7616 ;
			 LAYER M3 ;
			RECT 0.0098 87.6612 0.0481 87.7616 ;
			 LAYER V2 ;
			RECT 0.0215 87.7361 0.0364 87.7486 ;
		END

		ANTENNAGATEAREA 0.00027817 ;
		ANTENNADIFFAREA 0.00194719 ;
		ANTENNAPARTIALMETALAREA 0.00195671 ;
	END D[62]

	PIN D[63]
		USE SIGNAL ;
		DIRECTION INPUT ;
		SHAPE ABUTMENT ;
		PORT
			 LAYER M2 ;
			RECT 0.0098 89.0039 0.0481 89.0416 ;
			 LAYER M3 ;
			RECT 0.0098 88.9412 0.0481 89.0416 ;
			 LAYER V2 ;
			RECT 0.0215 89.0161 0.0364 89.0286 ;
		END

		ANTENNAGATEAREA 0.00027817 ;
		ANTENNADIFFAREA 0.00194719 ;
		ANTENNAPARTIALMETALAREA 0.00195671 ;
	END D[63]

	PIN D[64]
		USE SIGNAL ;
		DIRECTION INPUT ;
		SHAPE ABUTMENT ;
		PORT
			 LAYER M2 ;
			RECT 0.0098 90.2839 0.0481 90.3216 ;
			 LAYER M3 ;
			RECT 0.0098 90.2212 0.0481 90.3216 ;
			 LAYER V2 ;
			RECT 0.0215 90.2961 0.0364 90.3086 ;
		END

		ANTENNAGATEAREA 0.00027817 ;
		ANTENNADIFFAREA 0.00194719 ;
		ANTENNAPARTIALMETALAREA 0.00195671 ;
	END D[64]

	PIN D[65]
		USE SIGNAL ;
		DIRECTION INPUT ;
		SHAPE ABUTMENT ;
		PORT
			 LAYER M2 ;
			RECT 0.0098 91.5639 0.0481 91.6016 ;
			 LAYER M3 ;
			RECT 0.0098 91.5012 0.0481 91.6016 ;
			 LAYER V2 ;
			RECT 0.0215 91.5761 0.0364 91.5886 ;
		END

		ANTENNAGATEAREA 0.00027817 ;
		ANTENNADIFFAREA 0.00194719 ;
		ANTENNAPARTIALMETALAREA 0.00195671 ;
	END D[65]

	PIN D[66]
		USE SIGNAL ;
		DIRECTION INPUT ;
		SHAPE ABUTMENT ;
		PORT
			 LAYER M2 ;
			RECT 0.0098 92.8439 0.0481 92.8816 ;
			 LAYER M3 ;
			RECT 0.0098 92.7812 0.0481 92.8816 ;
			 LAYER V2 ;
			RECT 0.0215 92.8561 0.0364 92.8686 ;
		END

		ANTENNAGATEAREA 0.00027817 ;
		ANTENNADIFFAREA 0.00194719 ;
		ANTENNAPARTIALMETALAREA 0.00195671 ;
	END D[66]

	PIN D[67]
		USE SIGNAL ;
		DIRECTION INPUT ;
		SHAPE ABUTMENT ;
		PORT
			 LAYER M2 ;
			RECT 0.0098 94.1239 0.0481 94.1616 ;
			 LAYER M3 ;
			RECT 0.0098 94.0612 0.0481 94.1616 ;
			 LAYER V2 ;
			RECT 0.0215 94.1361 0.0364 94.1486 ;
		END

		ANTENNAGATEAREA 0.00027817 ;
		ANTENNADIFFAREA 0.00194719 ;
		ANTENNAPARTIALMETALAREA 0.00195671 ;
	END D[67]

	PIN D[68]
		USE SIGNAL ;
		DIRECTION INPUT ;
		SHAPE ABUTMENT ;
		PORT
			 LAYER M2 ;
			RECT 0.0098 95.4039 0.0481 95.4416 ;
			 LAYER M3 ;
			RECT 0.0098 95.3412 0.0481 95.4416 ;
			 LAYER V2 ;
			RECT 0.0215 95.4161 0.0364 95.4286 ;
		END

		ANTENNAGATEAREA 0.00027817 ;
		ANTENNADIFFAREA 0.00194719 ;
		ANTENNAPARTIALMETALAREA 0.00195671 ;
	END D[68]

	PIN D[69]
		USE SIGNAL ;
		DIRECTION INPUT ;
		SHAPE ABUTMENT ;
		PORT
			 LAYER M2 ;
			RECT 0.0098 96.6839 0.0481 96.7216 ;
			 LAYER M3 ;
			RECT 0.0098 96.6212 0.0481 96.7216 ;
			 LAYER V2 ;
			RECT 0.0215 96.6961 0.0364 96.7086 ;
		END

		ANTENNAGATEAREA 0.00027817 ;
		ANTENNADIFFAREA 0.00194719 ;
		ANTENNAPARTIALMETALAREA 0.00195671 ;
	END D[69]

	PIN D[6]
		USE SIGNAL ;
		DIRECTION INPUT ;
		SHAPE ABUTMENT ;
		PORT
			 LAYER M2 ;
			RECT 0.0098 9.0478 0.0481 9.0855 ;
			 LAYER M3 ;
			RECT 0.0098 9.0478 0.0481 9.1482 ;
			 LAYER V2 ;
			RECT 0.0215 9.0608 0.0364 9.0733 ;
		END

		ANTENNAGATEAREA 0.00027817 ;
		ANTENNADIFFAREA 0.00194719 ;
		ANTENNAPARTIALMETALAREA 0.00195671 ;
	END D[6]

	PIN D[70]
		USE SIGNAL ;
		DIRECTION INPUT ;
		SHAPE ABUTMENT ;
		PORT
			 LAYER M2 ;
			RECT 0.0098 97.9639 0.0481 98.0016 ;
			 LAYER M3 ;
			RECT 0.0098 97.9012 0.0481 98.0016 ;
			 LAYER V2 ;
			RECT 0.0215 97.9761 0.0364 97.9886 ;
		END

		ANTENNAGATEAREA 0.00027817 ;
		ANTENNADIFFAREA 0.00194719 ;
		ANTENNAPARTIALMETALAREA 0.00195671 ;
	END D[70]

	PIN D[71]
		USE SIGNAL ;
		DIRECTION INPUT ;
		SHAPE ABUTMENT ;
		PORT
			 LAYER M2 ;
			RECT 0.0098 99.2439 0.0481 99.2816 ;
			 LAYER M3 ;
			RECT 0.0098 99.1812 0.0481 99.2816 ;
			 LAYER V2 ;
			RECT 0.0215 99.2561 0.0364 99.2686 ;
		END

		ANTENNAGATEAREA 0.00027817 ;
		ANTENNADIFFAREA 0.00194719 ;
		ANTENNAPARTIALMETALAREA 0.00195671 ;
	END D[71]

	PIN D[72]
		USE SIGNAL ;
		DIRECTION INPUT ;
		SHAPE ABUTMENT ;
		PORT
			 LAYER M2 ;
			RECT 0.0098 108.2227 0.0481 108.2604 ;
			 LAYER M3 ;
			RECT 0.0098 108.16 0.0481 108.2604 ;
			 LAYER V2 ;
			RECT 0.0215 108.2349 0.0364 108.2475 ;
		END

		ANTENNAGATEAREA 0.00027817 ;
		ANTENNADIFFAREA 0.00194719 ;
		ANTENNAPARTIALMETALAREA 0.00195671 ;
	END D[72]

	PIN D[73]
		USE SIGNAL ;
		DIRECTION INPUT ;
		SHAPE ABUTMENT ;
		PORT
			 LAYER M2 ;
			RECT 0.0098 109.5027 0.0481 109.5404 ;
			 LAYER M3 ;
			RECT 0.0098 109.44 0.0481 109.5404 ;
			 LAYER V2 ;
			RECT 0.0215 109.5149 0.0364 109.5275 ;
		END

		ANTENNAGATEAREA 0.00027817 ;
		ANTENNADIFFAREA 0.00194719 ;
		ANTENNAPARTIALMETALAREA 0.00195671 ;
	END D[73]

	PIN D[74]
		USE SIGNAL ;
		DIRECTION INPUT ;
		SHAPE ABUTMENT ;
		PORT
			 LAYER M2 ;
			RECT 0.0098 110.7827 0.0481 110.8204 ;
			 LAYER M3 ;
			RECT 0.0098 110.72 0.0481 110.8204 ;
			 LAYER V2 ;
			RECT 0.0215 110.7949 0.0364 110.8075 ;
		END

		ANTENNAGATEAREA 0.00027817 ;
		ANTENNADIFFAREA 0.00194719 ;
		ANTENNAPARTIALMETALAREA 0.00195671 ;
	END D[74]

	PIN D[75]
		USE SIGNAL ;
		DIRECTION INPUT ;
		SHAPE ABUTMENT ;
		PORT
			 LAYER M2 ;
			RECT 0.0098 112.0627 0.0481 112.1004 ;
			 LAYER M3 ;
			RECT 0.0098 112 0.0481 112.1004 ;
			 LAYER V2 ;
			RECT 0.0215 112.0749 0.0364 112.0875 ;
		END

		ANTENNAGATEAREA 0.00027817 ;
		ANTENNADIFFAREA 0.00194719 ;
		ANTENNAPARTIALMETALAREA 0.00195671 ;
	END D[75]

	PIN D[76]
		USE SIGNAL ;
		DIRECTION INPUT ;
		SHAPE ABUTMENT ;
		PORT
			 LAYER M2 ;
			RECT 0.0098 113.3427 0.0481 113.3804 ;
			 LAYER M3 ;
			RECT 0.0098 113.28 0.0481 113.3804 ;
			 LAYER V2 ;
			RECT 0.0215 113.3549 0.0364 113.3675 ;
		END

		ANTENNAGATEAREA 0.00027817 ;
		ANTENNADIFFAREA 0.00194719 ;
		ANTENNAPARTIALMETALAREA 0.00195671 ;
	END D[76]

	PIN D[77]
		USE SIGNAL ;
		DIRECTION INPUT ;
		SHAPE ABUTMENT ;
		PORT
			 LAYER M2 ;
			RECT 0.0098 114.6227 0.0481 114.6604 ;
			 LAYER M3 ;
			RECT 0.0098 114.56 0.0481 114.6604 ;
			 LAYER V2 ;
			RECT 0.0215 114.6349 0.0364 114.6475 ;
		END

		ANTENNAGATEAREA 0.00027817 ;
		ANTENNADIFFAREA 0.00194719 ;
		ANTENNAPARTIALMETALAREA 0.00195671 ;
	END D[77]

	PIN D[78]
		USE SIGNAL ;
		DIRECTION INPUT ;
		SHAPE ABUTMENT ;
		PORT
			 LAYER M2 ;
			RECT 0.0098 115.9027 0.0481 115.9404 ;
			 LAYER M3 ;
			RECT 0.0098 115.84 0.0481 115.9404 ;
			 LAYER V2 ;
			RECT 0.0215 115.9149 0.0364 115.9275 ;
		END

		ANTENNAGATEAREA 0.00027817 ;
		ANTENNADIFFAREA 0.00194719 ;
		ANTENNAPARTIALMETALAREA 0.00195671 ;
	END D[78]

	PIN D[79]
		USE SIGNAL ;
		DIRECTION INPUT ;
		SHAPE ABUTMENT ;
		PORT
			 LAYER M2 ;
			RECT 0.0098 117.1827 0.0481 117.2204 ;
			 LAYER M3 ;
			RECT 0.0098 117.12 0.0481 117.2204 ;
			 LAYER V2 ;
			RECT 0.0215 117.1949 0.0364 117.2075 ;
		END

		ANTENNAGATEAREA 0.00027817 ;
		ANTENNADIFFAREA 0.00194719 ;
		ANTENNAPARTIALMETALAREA 0.00195671 ;
	END D[79]

	PIN D[7]
		USE SIGNAL ;
		DIRECTION INPUT ;
		SHAPE ABUTMENT ;
		PORT
			 LAYER M2 ;
			RECT 0.0098 10.3278 0.0481 10.3655 ;
			 LAYER M3 ;
			RECT 0.0098 10.3278 0.0481 10.4282 ;
			 LAYER V2 ;
			RECT 0.0215 10.3408 0.0364 10.3533 ;
		END

		ANTENNAGATEAREA 0.00027817 ;
		ANTENNADIFFAREA 0.00194719 ;
		ANTENNAPARTIALMETALAREA 0.00195671 ;
	END D[7]

	PIN D[80]
		USE SIGNAL ;
		DIRECTION INPUT ;
		SHAPE ABUTMENT ;
		PORT
			 LAYER M2 ;
			RECT 0.0098 118.4627 0.0481 118.5004 ;
			 LAYER M3 ;
			RECT 0.0098 118.4 0.0481 118.5004 ;
			 LAYER V2 ;
			RECT 0.0215 118.4749 0.0364 118.4875 ;
		END

		ANTENNAGATEAREA 0.00027817 ;
		ANTENNADIFFAREA 0.00194719 ;
		ANTENNAPARTIALMETALAREA 0.00195671 ;
	END D[80]

	PIN D[81]
		USE SIGNAL ;
		DIRECTION INPUT ;
		SHAPE ABUTMENT ;
		PORT
			 LAYER M2 ;
			RECT 0.0098 119.7427 0.0481 119.7804 ;
			 LAYER M3 ;
			RECT 0.0098 119.68 0.0481 119.7804 ;
			 LAYER V2 ;
			RECT 0.0215 119.7549 0.0364 119.7675 ;
		END

		ANTENNAGATEAREA 0.00027817 ;
		ANTENNADIFFAREA 0.00194719 ;
		ANTENNAPARTIALMETALAREA 0.00195671 ;
	END D[81]

	PIN D[82]
		USE SIGNAL ;
		DIRECTION INPUT ;
		SHAPE ABUTMENT ;
		PORT
			 LAYER M2 ;
			RECT 0.0098 121.0227 0.0481 121.0604 ;
			 LAYER M3 ;
			RECT 0.0098 120.96 0.0481 121.0604 ;
			 LAYER V2 ;
			RECT 0.0215 121.0349 0.0364 121.0475 ;
		END

		ANTENNAGATEAREA 0.00027817 ;
		ANTENNADIFFAREA 0.00194719 ;
		ANTENNAPARTIALMETALAREA 0.00195671 ;
	END D[82]

	PIN D[83]
		USE SIGNAL ;
		DIRECTION INPUT ;
		SHAPE ABUTMENT ;
		PORT
			 LAYER M2 ;
			RECT 0.0098 122.3027 0.0481 122.3404 ;
			 LAYER M3 ;
			RECT 0.0098 122.24 0.0481 122.3404 ;
			 LAYER V2 ;
			RECT 0.0215 122.3149 0.0364 122.3275 ;
		END

		ANTENNAGATEAREA 0.00027817 ;
		ANTENNADIFFAREA 0.00194719 ;
		ANTENNAPARTIALMETALAREA 0.00195671 ;
	END D[83]

	PIN D[84]
		USE SIGNAL ;
		DIRECTION INPUT ;
		SHAPE ABUTMENT ;
		PORT
			 LAYER M2 ;
			RECT 0.0098 123.5827 0.0481 123.6204 ;
			 LAYER M3 ;
			RECT 0.0098 123.52 0.0481 123.6204 ;
			 LAYER V2 ;
			RECT 0.0215 123.5949 0.0364 123.6075 ;
		END

		ANTENNAGATEAREA 0.00027817 ;
		ANTENNADIFFAREA 0.00194719 ;
		ANTENNAPARTIALMETALAREA 0.00195671 ;
	END D[84]

	PIN D[85]
		USE SIGNAL ;
		DIRECTION INPUT ;
		SHAPE ABUTMENT ;
		PORT
			 LAYER M2 ;
			RECT 0.0098 124.8627 0.0481 124.9004 ;
			 LAYER M3 ;
			RECT 0.0098 124.8 0.0481 124.9004 ;
			 LAYER V2 ;
			RECT 0.0215 124.8749 0.0364 124.8875 ;
		END

		ANTENNAGATEAREA 0.00027817 ;
		ANTENNADIFFAREA 0.00194719 ;
		ANTENNAPARTIALMETALAREA 0.00195671 ;
	END D[85]

	PIN D[86]
		USE SIGNAL ;
		DIRECTION INPUT ;
		SHAPE ABUTMENT ;
		PORT
			 LAYER M2 ;
			RECT 0.0098 126.1427 0.0481 126.1804 ;
			 LAYER M3 ;
			RECT 0.0098 126.08 0.0481 126.1804 ;
			 LAYER V2 ;
			RECT 0.0215 126.1549 0.0364 126.1675 ;
		END

		ANTENNAGATEAREA 0.00027817 ;
		ANTENNADIFFAREA 0.00194719 ;
		ANTENNAPARTIALMETALAREA 0.00195671 ;
	END D[86]

	PIN D[87]
		USE SIGNAL ;
		DIRECTION INPUT ;
		SHAPE ABUTMENT ;
		PORT
			 LAYER M2 ;
			RECT 0.0098 127.4227 0.0481 127.4604 ;
			 LAYER M3 ;
			RECT 0.0098 127.36 0.0481 127.4604 ;
			 LAYER V2 ;
			RECT 0.0215 127.4349 0.0364 127.4475 ;
		END

		ANTENNAGATEAREA 0.00027817 ;
		ANTENNADIFFAREA 0.00194719 ;
		ANTENNAPARTIALMETALAREA 0.00195671 ;
	END D[87]

	PIN D[88]
		USE SIGNAL ;
		DIRECTION INPUT ;
		SHAPE ABUTMENT ;
		PORT
			 LAYER M2 ;
			RECT 0.0098 128.7027 0.0481 128.7404 ;
			 LAYER M3 ;
			RECT 0.0098 128.64 0.0481 128.7404 ;
			 LAYER V2 ;
			RECT 0.0215 128.7149 0.0364 128.7275 ;
		END

		ANTENNAGATEAREA 0.00027817 ;
		ANTENNADIFFAREA 0.00194719 ;
		ANTENNAPARTIALMETALAREA 0.00195671 ;
	END D[88]

	PIN D[89]
		USE SIGNAL ;
		DIRECTION INPUT ;
		SHAPE ABUTMENT ;
		PORT
			 LAYER M2 ;
			RECT 0.0098 129.9827 0.0481 130.0204 ;
			 LAYER M3 ;
			RECT 0.0098 129.92 0.0481 130.0204 ;
			 LAYER V2 ;
			RECT 0.0215 129.9949 0.0364 130.0075 ;
		END

		ANTENNAGATEAREA 0.00027817 ;
		ANTENNADIFFAREA 0.00194719 ;
		ANTENNAPARTIALMETALAREA 0.00195671 ;
	END D[89]

	PIN D[8]
		USE SIGNAL ;
		DIRECTION INPUT ;
		SHAPE ABUTMENT ;
		PORT
			 LAYER M2 ;
			RECT 0.0098 11.6078 0.0481 11.6455 ;
			 LAYER M3 ;
			RECT 0.0098 11.6078 0.0481 11.7082 ;
			 LAYER V2 ;
			RECT 0.0215 11.6208 0.0364 11.6333 ;
		END

		ANTENNAGATEAREA 0.00027817 ;
		ANTENNADIFFAREA 0.00194719 ;
		ANTENNAPARTIALMETALAREA 0.00195671 ;
	END D[8]

	PIN D[90]
		USE SIGNAL ;
		DIRECTION INPUT ;
		SHAPE ABUTMENT ;
		PORT
			 LAYER M2 ;
			RECT 0.0098 131.2627 0.0481 131.3004 ;
			 LAYER M3 ;
			RECT 0.0098 131.2 0.0481 131.3004 ;
			 LAYER V2 ;
			RECT 0.0215 131.2749 0.0364 131.2875 ;
		END

		ANTENNAGATEAREA 0.00027817 ;
		ANTENNADIFFAREA 0.00194719 ;
		ANTENNAPARTIALMETALAREA 0.00195671 ;
	END D[90]

	PIN D[91]
		USE SIGNAL ;
		DIRECTION INPUT ;
		SHAPE ABUTMENT ;
		PORT
			 LAYER M2 ;
			RECT 0.0098 132.5427 0.0481 132.5804 ;
			 LAYER M3 ;
			RECT 0.0098 132.48 0.0481 132.5804 ;
			 LAYER V2 ;
			RECT 0.0215 132.5549 0.0364 132.5675 ;
		END

		ANTENNAGATEAREA 0.00027817 ;
		ANTENNADIFFAREA 0.00194719 ;
		ANTENNAPARTIALMETALAREA 0.00195671 ;
	END D[91]

	PIN D[92]
		USE SIGNAL ;
		DIRECTION INPUT ;
		SHAPE ABUTMENT ;
		PORT
			 LAYER M2 ;
			RECT 0.0098 133.8227 0.0481 133.8604 ;
			 LAYER M3 ;
			RECT 0.0098 133.76 0.0481 133.8604 ;
			 LAYER V2 ;
			RECT 0.0215 133.8349 0.0364 133.8475 ;
		END

		ANTENNAGATEAREA 0.00027817 ;
		ANTENNADIFFAREA 0.00194719 ;
		ANTENNAPARTIALMETALAREA 0.00195671 ;
	END D[92]

	PIN D[93]
		USE SIGNAL ;
		DIRECTION INPUT ;
		SHAPE ABUTMENT ;
		PORT
			 LAYER M2 ;
			RECT 0.0098 135.1027 0.0481 135.1404 ;
			 LAYER M3 ;
			RECT 0.0098 135.04 0.0481 135.1404 ;
			 LAYER V2 ;
			RECT 0.0215 135.1149 0.0364 135.1275 ;
		END

		ANTENNAGATEAREA 0.00027817 ;
		ANTENNADIFFAREA 0.00194719 ;
		ANTENNAPARTIALMETALAREA 0.00195671 ;
	END D[93]

	PIN D[94]
		USE SIGNAL ;
		DIRECTION INPUT ;
		SHAPE ABUTMENT ;
		PORT
			 LAYER M2 ;
			RECT 0.0098 136.3827 0.0481 136.4204 ;
			 LAYER M3 ;
			RECT 0.0098 136.32 0.0481 136.4204 ;
			 LAYER V2 ;
			RECT 0.0215 136.3949 0.0364 136.4075 ;
		END

		ANTENNAGATEAREA 0.00027817 ;
		ANTENNADIFFAREA 0.00194719 ;
		ANTENNAPARTIALMETALAREA 0.00195671 ;
	END D[94]

	PIN D[95]
		USE SIGNAL ;
		DIRECTION INPUT ;
		SHAPE ABUTMENT ;
		PORT
			 LAYER M2 ;
			RECT 0.0098 137.6627 0.0481 137.7004 ;
			 LAYER M3 ;
			RECT 0.0098 137.6 0.0481 137.7004 ;
			 LAYER V2 ;
			RECT 0.0215 137.6749 0.0364 137.6875 ;
		END

		ANTENNAGATEAREA 0.00027817 ;
		ANTENNADIFFAREA 0.00194719 ;
		ANTENNAPARTIALMETALAREA 0.00195671 ;
	END D[95]

	PIN D[9]
		USE SIGNAL ;
		DIRECTION INPUT ;
		SHAPE ABUTMENT ;
		PORT
			 LAYER M2 ;
			RECT 0.0098 12.8878 0.0481 12.9255 ;
			 LAYER M3 ;
			RECT 0.0098 12.8878 0.0481 12.9882 ;
			 LAYER V2 ;
			RECT 0.0215 12.9008 0.0364 12.9133 ;
		END

		ANTENNAGATEAREA 0.00027817 ;
		ANTENNADIFFAREA 0.00194719 ;
		ANTENNAPARTIALMETALAREA 0.00195671 ;
	END D[9]

	PIN EMAS
		USE SIGNAL ;
		DIRECTION INPUT ;
		SHAPE ABUTMENT ;
		PORT
			 LAYER M2 ;
			RECT 0.0714 62.6761 0.1097 62.7137 ;
			 LAYER M3 ;
			RECT 0.0714 62.6761 0.1097 62.7765 ;
			 LAYER V2 ;
			RECT 0.0831 62.6882 0.098 62.7008 ;
		END

		ANTENNAGATEAREA 0.00027817 ;
		ANTENNADIFFAREA 0.00194719 ;
		ANTENNAPARTIALMETALAREA 0.00195671 ;
	END EMAS

	PIN EMAW[0]
		USE SIGNAL ;
		DIRECTION INPUT ;
		SHAPE ABUTMENT ;
		PORT
			 LAYER M2 ;
			RECT 0.0098 59.9529 0.0481 59.9906 ;
			 LAYER M3 ;
			RECT 0.0098 59.8902 0.0481 59.9906 ;
			 LAYER V2 ;
			RECT 0.0215 59.9651 0.0364 59.9776 ;
		END

		ANTENNAGATEAREA 0.00027817 ;
		ANTENNADIFFAREA 0.00194719 ;
		ANTENNAPARTIALMETALAREA 0.00195671 ;
	END EMAW[0]

	PIN EMAW[1]
		USE SIGNAL ;
		DIRECTION INPUT ;
		SHAPE ABUTMENT ;
		PORT
			 LAYER M2 ;
			RECT 0.0714 61.6973 0.1097 61.7349 ;
			 LAYER M3 ;
			RECT 0.0714 61.6973 0.1097 61.7976 ;
			 LAYER V2 ;
			RECT 0.0831 61.7094 0.098 61.722 ;
		END

		ANTENNAGATEAREA 0.00027817 ;
		ANTENNADIFFAREA 0.00194719 ;
		ANTENNAPARTIALMETALAREA 0.00195671 ;
	END EMAW[1]

	PIN EMA[0]
		USE SIGNAL ;
		DIRECTION INPUT ;
		SHAPE ABUTMENT ;
		PORT
			 LAYER M2 ;
			RECT 0.0098 58.0831 0.0481 58.1835 ;
			 LAYER M3 ;
			RECT 0.0098 58.0831 0.0481 58.1835 ;
			 LAYER V2 ;
			RECT 0.021 58.158 0.0359 58.1706 ;
		END

		ANTENNAGATEAREA 0.00027817 ;
		ANTENNADIFFAREA 0.00194719 ;
		ANTENNAPARTIALMETALAREA 0.00195671 ;
	END EMA[0]

	PIN EMA[1]
		USE SIGNAL ;
		DIRECTION INPUT ;
		SHAPE ABUTMENT ;
		PORT
			 LAYER M2 ;
			RECT 0.0098 56.7153 0.0481 56.7529 ;
			 LAYER M3 ;
			RECT 0.0098 56.6525 0.0481 56.7529 ;
			 LAYER V2 ;
			RECT 0.0215 56.7275 0.0364 56.74 ;
		END

		ANTENNAGATEAREA 0.00027817 ;
		ANTENNADIFFAREA 0.00194719 ;
		ANTENNAPARTIALMETALAREA 0.00195671 ;
	END EMA[1]

	PIN EMA[2]
		USE SIGNAL ;
		DIRECTION INPUT ;
		SHAPE ABUTMENT ;
		PORT
			 LAYER M2 ;
			RECT 0.0714 56.6525 0.1097 56.6902 ;
			 LAYER M3 ;
			RECT 0.0714 56.6525 0.1097 56.7529 ;
			 LAYER V2 ;
			RECT 0.0831 56.6647 0.098 56.6773 ;
		END

		ANTENNAGATEAREA 0.00027817 ;
		ANTENNADIFFAREA 0.00194719 ;
		ANTENNAPARTIALMETALAREA 0.00195671 ;
	END EMA[2]

	PIN GWEN
		USE SIGNAL ;
		DIRECTION INPUT ;
		SHAPE ABUTMENT ;
		PORT
			 LAYER M2 ;
			RECT 0.0098 76.2918 0.0481 76.3922 ;
			 LAYER M3 ;
			RECT 0.0098 76.2918 0.0481 76.3922 ;
			 LAYER V2 ;
			RECT 0.021 76.3667 0.0359 76.3792 ;
		END

		ANTENNAGATEAREA 0.00027817 ;
		ANTENNADIFFAREA 0.00194719 ;
		ANTENNAPARTIALMETALAREA 0.00195671 ;
	END GWEN

	PIN GWENY
		USE SIGNAL ;
		DIRECTION OUTPUT ;
		SHAPE ABUTMENT ;
		PORT
			 LAYER M2 ;
			RECT 0.0098 75.9153 0.0481 75.9529 ;
			 LAYER M3 ;
			RECT 0.0098 75.9153 0.0481 76.0157 ;
			 LAYER V2 ;
			RECT 0.0215 75.9282 0.0364 75.9408 ;
		END

		ANTENNADIFFAREA 0.00194719 ;
		ANTENNAPARTIALMETALAREA 0.00195671 ;
	END GWENY

	PIN Q[0]
		USE SIGNAL ;
		DIRECTION OUTPUT ;
		SHAPE ABUTMENT ;
		PORT
			 LAYER M2 ;
			RECT 0.0098 1.0918 0.0481 1.1922 ;
			 LAYER M3 ;
			RECT 0.0098 1.0918 0.0481 1.1922 ;
			 LAYER V2 ;
			RECT 0.021 1.1667 0.0359 1.1792 ;
		END

		ANTENNADIFFAREA 0.00194719 ;
		ANTENNAPARTIALMETALAREA 0.00195671 ;
	END Q[0]

	PIN Q[10]
		USE SIGNAL ;
		DIRECTION OUTPUT ;
		SHAPE ABUTMENT ;
		PORT
			 LAYER M2 ;
			RECT 0.0098 13.8918 0.0481 13.9922 ;
			 LAYER M3 ;
			RECT 0.0098 13.8918 0.0481 13.9922 ;
			 LAYER V2 ;
			RECT 0.021 13.9667 0.0359 13.9792 ;
		END

		ANTENNADIFFAREA 0.00194719 ;
		ANTENNAPARTIALMETALAREA 0.00195671 ;
	END Q[10]

	PIN Q[11]
		USE SIGNAL ;
		DIRECTION OUTPUT ;
		SHAPE ABUTMENT ;
		PORT
			 LAYER M2 ;
			RECT 0.0098 15.1718 0.0481 15.2722 ;
			 LAYER M3 ;
			RECT 0.0098 15.1718 0.0481 15.2722 ;
			 LAYER V2 ;
			RECT 0.021 15.2467 0.0359 15.2592 ;
		END

		ANTENNADIFFAREA 0.00194719 ;
		ANTENNAPARTIALMETALAREA 0.00195671 ;
	END Q[11]

	PIN Q[12]
		USE SIGNAL ;
		DIRECTION OUTPUT ;
		SHAPE ABUTMENT ;
		PORT
			 LAYER M2 ;
			RECT 0.0098 16.4518 0.0481 16.5522 ;
			 LAYER M3 ;
			RECT 0.0098 16.4518 0.0481 16.5522 ;
			 LAYER V2 ;
			RECT 0.021 16.5267 0.0359 16.5392 ;
		END

		ANTENNADIFFAREA 0.00194719 ;
		ANTENNAPARTIALMETALAREA 0.00195671 ;
	END Q[12]

	PIN Q[13]
		USE SIGNAL ;
		DIRECTION OUTPUT ;
		SHAPE ABUTMENT ;
		PORT
			 LAYER M2 ;
			RECT 0.0098 17.7318 0.0481 17.8322 ;
			 LAYER M3 ;
			RECT 0.0098 17.7318 0.0481 17.8322 ;
			 LAYER V2 ;
			RECT 0.021 17.8067 0.0359 17.8192 ;
		END

		ANTENNADIFFAREA 0.00194719 ;
		ANTENNAPARTIALMETALAREA 0.00195671 ;
	END Q[13]

	PIN Q[14]
		USE SIGNAL ;
		DIRECTION OUTPUT ;
		SHAPE ABUTMENT ;
		PORT
			 LAYER M2 ;
			RECT 0.0098 19.0118 0.0481 19.1122 ;
			 LAYER M3 ;
			RECT 0.0098 19.0118 0.0481 19.1122 ;
			 LAYER V2 ;
			RECT 0.021 19.0867 0.0359 19.0992 ;
		END

		ANTENNADIFFAREA 0.00194719 ;
		ANTENNAPARTIALMETALAREA 0.00195671 ;
	END Q[14]

	PIN Q[15]
		USE SIGNAL ;
		DIRECTION OUTPUT ;
		SHAPE ABUTMENT ;
		PORT
			 LAYER M2 ;
			RECT 0.0098 20.2918 0.0481 20.3922 ;
			 LAYER M3 ;
			RECT 0.0098 20.2918 0.0481 20.3922 ;
			 LAYER V2 ;
			RECT 0.021 20.3667 0.0359 20.3792 ;
		END

		ANTENNADIFFAREA 0.00194719 ;
		ANTENNAPARTIALMETALAREA 0.00195671 ;
	END Q[15]

	PIN Q[16]
		USE SIGNAL ;
		DIRECTION OUTPUT ;
		SHAPE ABUTMENT ;
		PORT
			 LAYER M2 ;
			RECT 0.0098 21.5718 0.0481 21.6722 ;
			 LAYER M3 ;
			RECT 0.0098 21.5718 0.0481 21.6722 ;
			 LAYER V2 ;
			RECT 0.021 21.6467 0.0359 21.6592 ;
		END

		ANTENNADIFFAREA 0.00194719 ;
		ANTENNAPARTIALMETALAREA 0.00195671 ;
	END Q[16]

	PIN Q[17]
		USE SIGNAL ;
		DIRECTION OUTPUT ;
		SHAPE ABUTMENT ;
		PORT
			 LAYER M2 ;
			RECT 0.0098 22.8518 0.0481 22.9522 ;
			 LAYER M3 ;
			RECT 0.0098 22.8518 0.0481 22.9522 ;
			 LAYER V2 ;
			RECT 0.021 22.9267 0.0359 22.9392 ;
		END

		ANTENNADIFFAREA 0.00194719 ;
		ANTENNAPARTIALMETALAREA 0.00195671 ;
	END Q[17]

	PIN Q[18]
		USE SIGNAL ;
		DIRECTION OUTPUT ;
		SHAPE ABUTMENT ;
		PORT
			 LAYER M2 ;
			RECT 0.0098 24.1318 0.0481 24.2322 ;
			 LAYER M3 ;
			RECT 0.0098 24.1318 0.0481 24.2322 ;
			 LAYER V2 ;
			RECT 0.021 24.2067 0.0359 24.2192 ;
		END

		ANTENNADIFFAREA 0.00194719 ;
		ANTENNAPARTIALMETALAREA 0.00195671 ;
	END Q[18]

	PIN Q[19]
		USE SIGNAL ;
		DIRECTION OUTPUT ;
		SHAPE ABUTMENT ;
		PORT
			 LAYER M2 ;
			RECT 0.0098 25.4118 0.0481 25.5122 ;
			 LAYER M3 ;
			RECT 0.0098 25.4118 0.0481 25.5122 ;
			 LAYER V2 ;
			RECT 0.021 25.4867 0.0359 25.4992 ;
		END

		ANTENNADIFFAREA 0.00194719 ;
		ANTENNAPARTIALMETALAREA 0.00195671 ;
	END Q[19]

	PIN Q[1]
		USE SIGNAL ;
		DIRECTION OUTPUT ;
		SHAPE ABUTMENT ;
		PORT
			 LAYER M2 ;
			RECT 0.0098 2.3718 0.0481 2.4722 ;
			 LAYER M3 ;
			RECT 0.0098 2.3718 0.0481 2.4722 ;
			 LAYER V2 ;
			RECT 0.021 2.4467 0.0359 2.4592 ;
		END

		ANTENNADIFFAREA 0.00194719 ;
		ANTENNAPARTIALMETALAREA 0.00195671 ;
	END Q[1]

	PIN Q[20]
		USE SIGNAL ;
		DIRECTION OUTPUT ;
		SHAPE ABUTMENT ;
		PORT
			 LAYER M2 ;
			RECT 0.0098 26.6918 0.0481 26.7922 ;
			 LAYER M3 ;
			RECT 0.0098 26.6918 0.0481 26.7922 ;
			 LAYER V2 ;
			RECT 0.021 26.7667 0.0359 26.7792 ;
		END

		ANTENNADIFFAREA 0.00194719 ;
		ANTENNAPARTIALMETALAREA 0.00195671 ;
	END Q[20]

	PIN Q[21]
		USE SIGNAL ;
		DIRECTION OUTPUT ;
		SHAPE ABUTMENT ;
		PORT
			 LAYER M2 ;
			RECT 0.0098 27.9718 0.0481 28.0722 ;
			 LAYER M3 ;
			RECT 0.0098 27.9718 0.0481 28.0722 ;
			 LAYER V2 ;
			RECT 0.021 28.0467 0.0359 28.0592 ;
		END

		ANTENNADIFFAREA 0.00194719 ;
		ANTENNAPARTIALMETALAREA 0.00195671 ;
	END Q[21]

	PIN Q[22]
		USE SIGNAL ;
		DIRECTION OUTPUT ;
		SHAPE ABUTMENT ;
		PORT
			 LAYER M2 ;
			RECT 0.0098 29.2518 0.0481 29.3522 ;
			 LAYER M3 ;
			RECT 0.0098 29.2518 0.0481 29.3522 ;
			 LAYER V2 ;
			RECT 0.021 29.3267 0.0359 29.3392 ;
		END

		ANTENNADIFFAREA 0.00194719 ;
		ANTENNAPARTIALMETALAREA 0.00195671 ;
	END Q[22]

	PIN Q[23]
		USE SIGNAL ;
		DIRECTION OUTPUT ;
		SHAPE ABUTMENT ;
		PORT
			 LAYER M2 ;
			RECT 0.0098 30.5318 0.0481 30.6322 ;
			 LAYER M3 ;
			RECT 0.0098 30.5318 0.0481 30.6322 ;
			 LAYER V2 ;
			RECT 0.021 30.6067 0.0359 30.6192 ;
		END

		ANTENNADIFFAREA 0.00194719 ;
		ANTENNAPARTIALMETALAREA 0.00195671 ;
	END Q[23]

	PIN Q[24]
		USE SIGNAL ;
		DIRECTION OUTPUT ;
		SHAPE ABUTMENT ;
		PORT
			 LAYER M2 ;
			RECT 0.0098 39.5106 0.0481 39.611 ;
			 LAYER M3 ;
			RECT 0.0098 39.5106 0.0481 39.611 ;
			 LAYER V2 ;
			RECT 0.021 39.5855 0.0359 39.598 ;
		END

		ANTENNADIFFAREA 0.00194719 ;
		ANTENNAPARTIALMETALAREA 0.00195671 ;
	END Q[24]

	PIN Q[25]
		USE SIGNAL ;
		DIRECTION OUTPUT ;
		SHAPE ABUTMENT ;
		PORT
			 LAYER M2 ;
			RECT 0.0098 40.7906 0.0481 40.891 ;
			 LAYER M3 ;
			RECT 0.0098 40.7906 0.0481 40.891 ;
			 LAYER V2 ;
			RECT 0.021 40.8655 0.0359 40.878 ;
		END

		ANTENNADIFFAREA 0.00194719 ;
		ANTENNAPARTIALMETALAREA 0.00195671 ;
	END Q[25]

	PIN Q[26]
		USE SIGNAL ;
		DIRECTION OUTPUT ;
		SHAPE ABUTMENT ;
		PORT
			 LAYER M2 ;
			RECT 0.0098 42.0706 0.0481 42.171 ;
			 LAYER M3 ;
			RECT 0.0098 42.0706 0.0481 42.171 ;
			 LAYER V2 ;
			RECT 0.021 42.1455 0.0359 42.158 ;
		END

		ANTENNADIFFAREA 0.00194719 ;
		ANTENNAPARTIALMETALAREA 0.00195671 ;
	END Q[26]

	PIN Q[27]
		USE SIGNAL ;
		DIRECTION OUTPUT ;
		SHAPE ABUTMENT ;
		PORT
			 LAYER M2 ;
			RECT 0.0098 43.3506 0.0481 43.451 ;
			 LAYER M3 ;
			RECT 0.0098 43.3506 0.0481 43.451 ;
			 LAYER V2 ;
			RECT 0.021 43.4255 0.0359 43.438 ;
		END

		ANTENNADIFFAREA 0.00194719 ;
		ANTENNAPARTIALMETALAREA 0.00195671 ;
	END Q[27]

	PIN Q[28]
		USE SIGNAL ;
		DIRECTION OUTPUT ;
		SHAPE ABUTMENT ;
		PORT
			 LAYER M2 ;
			RECT 0.0098 44.6306 0.0481 44.731 ;
			 LAYER M3 ;
			RECT 0.0098 44.6306 0.0481 44.731 ;
			 LAYER V2 ;
			RECT 0.021 44.7055 0.0359 44.718 ;
		END

		ANTENNADIFFAREA 0.00194719 ;
		ANTENNAPARTIALMETALAREA 0.00195671 ;
	END Q[28]

	PIN Q[29]
		USE SIGNAL ;
		DIRECTION OUTPUT ;
		SHAPE ABUTMENT ;
		PORT
			 LAYER M2 ;
			RECT 0.0098 45.9106 0.0481 46.011 ;
			 LAYER M3 ;
			RECT 0.0098 45.9106 0.0481 46.011 ;
			 LAYER V2 ;
			RECT 0.021 45.9855 0.0359 45.998 ;
		END

		ANTENNADIFFAREA 0.00194719 ;
		ANTENNAPARTIALMETALAREA 0.00195671 ;
	END Q[29]

	PIN Q[2]
		USE SIGNAL ;
		DIRECTION OUTPUT ;
		SHAPE ABUTMENT ;
		PORT
			 LAYER M2 ;
			RECT 0.0098 3.6518 0.0481 3.7522 ;
			 LAYER M3 ;
			RECT 0.0098 3.6518 0.0481 3.7522 ;
			 LAYER V2 ;
			RECT 0.021 3.7267 0.0359 3.7392 ;
		END

		ANTENNADIFFAREA 0.00194719 ;
		ANTENNAPARTIALMETALAREA 0.00195671 ;
	END Q[2]

	PIN Q[30]
		USE SIGNAL ;
		DIRECTION OUTPUT ;
		SHAPE ABUTMENT ;
		PORT
			 LAYER M2 ;
			RECT 0.0098 47.1906 0.0481 47.291 ;
			 LAYER M3 ;
			RECT 0.0098 47.1906 0.0481 47.291 ;
			 LAYER V2 ;
			RECT 0.021 47.2655 0.0359 47.278 ;
		END

		ANTENNADIFFAREA 0.00194719 ;
		ANTENNAPARTIALMETALAREA 0.00195671 ;
	END Q[30]

	PIN Q[31]
		USE SIGNAL ;
		DIRECTION OUTPUT ;
		SHAPE ABUTMENT ;
		PORT
			 LAYER M2 ;
			RECT 0.0098 48.4706 0.0481 48.571 ;
			 LAYER M3 ;
			RECT 0.0098 48.4706 0.0481 48.571 ;
			 LAYER V2 ;
			RECT 0.021 48.5455 0.0359 48.558 ;
		END

		ANTENNADIFFAREA 0.00194719 ;
		ANTENNAPARTIALMETALAREA 0.00195671 ;
	END Q[31]

	PIN Q[32]
		USE SIGNAL ;
		DIRECTION OUTPUT ;
		SHAPE ABUTMENT ;
		PORT
			 LAYER M2 ;
			RECT 0.0098 49.7506 0.0481 49.851 ;
			 LAYER M3 ;
			RECT 0.0098 49.7506 0.0481 49.851 ;
			 LAYER V2 ;
			RECT 0.021 49.8255 0.0359 49.838 ;
		END

		ANTENNADIFFAREA 0.00194719 ;
		ANTENNAPARTIALMETALAREA 0.00195671 ;
	END Q[32]

	PIN Q[33]
		USE SIGNAL ;
		DIRECTION OUTPUT ;
		SHAPE ABUTMENT ;
		PORT
			 LAYER M2 ;
			RECT 0.0098 51.0306 0.0481 51.131 ;
			 LAYER M3 ;
			RECT 0.0098 51.0306 0.0481 51.131 ;
			 LAYER V2 ;
			RECT 0.021 51.1055 0.0359 51.118 ;
		END

		ANTENNADIFFAREA 0.00194719 ;
		ANTENNAPARTIALMETALAREA 0.00195671 ;
	END Q[33]

	PIN Q[34]
		USE SIGNAL ;
		DIRECTION OUTPUT ;
		SHAPE ABUTMENT ;
		PORT
			 LAYER M2 ;
			RECT 0.0098 52.3106 0.0481 52.411 ;
			 LAYER M3 ;
			RECT 0.0098 52.3106 0.0481 52.411 ;
			 LAYER V2 ;
			RECT 0.021 52.3855 0.0359 52.398 ;
		END

		ANTENNADIFFAREA 0.00194719 ;
		ANTENNAPARTIALMETALAREA 0.00195671 ;
	END Q[34]

	PIN Q[35]
		USE SIGNAL ;
		DIRECTION OUTPUT ;
		SHAPE ABUTMENT ;
		PORT
			 LAYER M2 ;
			RECT 0.0098 53.5906 0.0481 53.691 ;
			 LAYER M3 ;
			RECT 0.0098 53.5906 0.0481 53.691 ;
			 LAYER V2 ;
			RECT 0.021 53.6655 0.0359 53.678 ;
		END

		ANTENNADIFFAREA 0.00194719 ;
		ANTENNAPARTIALMETALAREA 0.00195671 ;
	END Q[35]

	PIN Q[36]
		USE SIGNAL ;
		DIRECTION OUTPUT ;
		SHAPE ABUTMENT ;
		PORT
			 LAYER M2 ;
			RECT 0.0098 54.8706 0.0481 54.971 ;
			 LAYER M3 ;
			RECT 0.0098 54.8706 0.0481 54.971 ;
			 LAYER V2 ;
			RECT 0.021 54.9455 0.0359 54.958 ;
		END

		ANTENNADIFFAREA 0.00194719 ;
		ANTENNAPARTIALMETALAREA 0.00195671 ;
	END Q[36]

	PIN Q[37]
		USE SIGNAL ;
		DIRECTION OUTPUT ;
		SHAPE ABUTMENT ;
		PORT
			 LAYER M2 ;
			RECT 0.0098 56.1506 0.0481 56.251 ;
			 LAYER M3 ;
			RECT 0.0098 56.1506 0.0481 56.251 ;
			 LAYER V2 ;
			RECT 0.021 56.2255 0.0359 56.238 ;
		END

		ANTENNADIFFAREA 0.00194719 ;
		ANTENNAPARTIALMETALAREA 0.00195671 ;
	END Q[37]

	PIN Q[38]
		USE SIGNAL ;
		DIRECTION OUTPUT ;
		SHAPE ABUTMENT ;
		PORT
			 LAYER M2 ;
			RECT 0.0714 57.4055 0.1097 57.4431 ;
			 LAYER M3 ;
			RECT 0.0714 57.4055 0.1097 57.5059 ;
			 LAYER V2 ;
			RECT 0.0831 57.4176 0.098 57.4302 ;
		END

		ANTENNADIFFAREA 0.00194719 ;
		ANTENNAPARTIALMETALAREA 0.00195671 ;
	END Q[38]

	PIN Q[39]
		USE SIGNAL ;
		DIRECTION OUTPUT ;
		SHAPE ABUTMENT ;
		PORT
			 LAYER M2 ;
			RECT 0.0714 58.6855 0.1097 58.7231 ;
			 LAYER M3 ;
			RECT 0.0714 58.6855 0.1097 58.7859 ;
			 LAYER V2 ;
			RECT 0.0831 58.6976 0.098 58.7102 ;
		END

		ANTENNADIFFAREA 0.00194719 ;
		ANTENNAPARTIALMETALAREA 0.00195671 ;
	END Q[39]

	PIN Q[3]
		USE SIGNAL ;
		DIRECTION OUTPUT ;
		SHAPE ABUTMENT ;
		PORT
			 LAYER M2 ;
			RECT 0.0098 4.9318 0.0481 5.0322 ;
			 LAYER M3 ;
			RECT 0.0098 4.9318 0.0481 5.0322 ;
			 LAYER V2 ;
			RECT 0.021 5.0067 0.0359 5.0192 ;
		END

		ANTENNADIFFAREA 0.00194719 ;
		ANTENNAPARTIALMETALAREA 0.00195671 ;
	END Q[3]

	PIN Q[40]
		USE SIGNAL ;
		DIRECTION OUTPUT ;
		SHAPE ABUTMENT ;
		PORT
			 LAYER M2 ;
			RECT 0.0714 59.8902 0.1097 59.9278 ;
			 LAYER M3 ;
			RECT 0.0714 59.8902 0.1097 59.9906 ;
			 LAYER V2 ;
			RECT 0.0831 59.9024 0.098 59.9149 ;
		END

		ANTENNADIFFAREA 0.00194719 ;
		ANTENNAPARTIALMETALAREA 0.00195671 ;
	END Q[40]

	PIN Q[41]
		USE SIGNAL ;
		DIRECTION OUTPUT ;
		SHAPE ABUTMENT ;
		PORT
			 LAYER M2 ;
			RECT 0.0714 61.2455 0.1097 61.2831 ;
			 LAYER M3 ;
			RECT 0.0714 61.2455 0.1097 61.3459 ;
			 LAYER V2 ;
			RECT 0.0831 61.2576 0.098 61.2702 ;
		END

		ANTENNADIFFAREA 0.00194719 ;
		ANTENNAPARTIALMETALAREA 0.00195671 ;
	END Q[41]

	PIN Q[42]
		USE SIGNAL ;
		DIRECTION OUTPUT ;
		SHAPE ABUTMENT ;
		PORT
			 LAYER M2 ;
			RECT 0.0714 62.5255 0.1097 62.5631 ;
			 LAYER M3 ;
			RECT 0.0714 62.5255 0.1097 62.6259 ;
			 LAYER V2 ;
			RECT 0.0831 62.5376 0.098 62.5502 ;
		END

		ANTENNADIFFAREA 0.00194719 ;
		ANTENNAPARTIALMETALAREA 0.00195671 ;
	END Q[42]

	PIN Q[43]
		USE SIGNAL ;
		DIRECTION OUTPUT ;
		SHAPE ABUTMENT ;
		PORT
			 LAYER M2 ;
			RECT 0.0714 63.8055 0.1097 63.8431 ;
			 LAYER M3 ;
			RECT 0.0714 63.8055 0.1097 63.9059 ;
			 LAYER V2 ;
			RECT 0.0831 63.8176 0.098 63.8302 ;
		END

		ANTENNADIFFAREA 0.00194719 ;
		ANTENNAPARTIALMETALAREA 0.00195671 ;
	END Q[43]

	PIN Q[44]
		USE SIGNAL ;
		DIRECTION OUTPUT ;
		SHAPE ABUTMENT ;
		PORT
			 LAYER M2 ;
			RECT 0.0714 65.0855 0.1097 65.1231 ;
			 LAYER M3 ;
			RECT 0.0714 65.0855 0.1097 65.1859 ;
			 LAYER V2 ;
			RECT 0.0831 65.0976 0.098 65.1102 ;
		END

		ANTENNADIFFAREA 0.00194719 ;
		ANTENNAPARTIALMETALAREA 0.00195671 ;
	END Q[44]

	PIN Q[45]
		USE SIGNAL ;
		DIRECTION OUTPUT ;
		SHAPE ABUTMENT ;
		PORT
			 LAYER M2 ;
			RECT 0.0714 66.3655 0.1097 66.4031 ;
			 LAYER M3 ;
			RECT 0.0714 66.3655 0.1097 66.4659 ;
			 LAYER V2 ;
			RECT 0.0831 66.3776 0.098 66.3902 ;
		END

		ANTENNADIFFAREA 0.00194719 ;
		ANTENNAPARTIALMETALAREA 0.00195671 ;
	END Q[45]

	PIN Q[46]
		USE SIGNAL ;
		DIRECTION OUTPUT ;
		SHAPE ABUTMENT ;
		PORT
			 LAYER M2 ;
			RECT 0.0714 67.6455 0.1097 67.6831 ;
			 LAYER M3 ;
			RECT 0.0714 67.6455 0.1097 67.7459 ;
			 LAYER V2 ;
			RECT 0.0831 67.6576 0.098 67.6702 ;
		END

		ANTENNADIFFAREA 0.00194719 ;
		ANTENNAPARTIALMETALAREA 0.00195671 ;
	END Q[46]

	PIN Q[47]
		USE SIGNAL ;
		DIRECTION OUTPUT ;
		SHAPE ABUTMENT ;
		PORT
			 LAYER M2 ;
			RECT 0.0714 68.9255 0.1097 68.9631 ;
			 LAYER M3 ;
			RECT 0.0714 68.9255 0.1097 69.0259 ;
			 LAYER V2 ;
			RECT 0.0831 68.9376 0.098 68.9502 ;
		END

		ANTENNADIFFAREA 0.00194719 ;
		ANTENNAPARTIALMETALAREA 0.00195671 ;
	END Q[47]

	PIN Q[48]
		USE SIGNAL ;
		DIRECTION OUTPUT ;
		SHAPE ABUTMENT ;
		PORT
			 LAYER M2 ;
			RECT 0.0714 70.1051 0.1097 70.1427 ;
			 LAYER M3 ;
			RECT 0.0714 70.0424 0.1097 70.1427 ;
			 LAYER V2 ;
			RECT 0.0831 70.118 0.098 70.1306 ;
		END

		ANTENNADIFFAREA 0.00194719 ;
		ANTENNAPARTIALMETALAREA 0.00195671 ;
	END Q[48]

	PIN Q[49]
		USE SIGNAL ;
		DIRECTION OUTPUT ;
		SHAPE ABUTMENT ;
		PORT
			 LAYER M2 ;
			RECT 0.0714 71.3851 0.1097 71.4227 ;
			 LAYER M3 ;
			RECT 0.0714 71.3224 0.1097 71.4227 ;
			 LAYER V2 ;
			RECT 0.0831 71.398 0.098 71.4106 ;
		END

		ANTENNADIFFAREA 0.00194719 ;
		ANTENNAPARTIALMETALAREA 0.00195671 ;
	END Q[49]

	PIN Q[4]
		USE SIGNAL ;
		DIRECTION OUTPUT ;
		SHAPE ABUTMENT ;
		PORT
			 LAYER M2 ;
			RECT 0.0098 6.2118 0.0481 6.3122 ;
			 LAYER M3 ;
			RECT 0.0098 6.2118 0.0481 6.3122 ;
			 LAYER V2 ;
			RECT 0.021 6.2867 0.0359 6.2992 ;
		END

		ANTENNADIFFAREA 0.00194719 ;
		ANTENNAPARTIALMETALAREA 0.00195671 ;
	END Q[4]

	PIN Q[50]
		USE SIGNAL ;
		DIRECTION OUTPUT ;
		SHAPE ABUTMENT ;
		PORT
			 LAYER M2 ;
			RECT 0.0714 72.6651 0.1097 72.7027 ;
			 LAYER M3 ;
			RECT 0.0714 72.6024 0.1097 72.7027 ;
			 LAYER V2 ;
			RECT 0.0831 72.678 0.098 72.6906 ;
		END

		ANTENNADIFFAREA 0.00194719 ;
		ANTENNAPARTIALMETALAREA 0.00195671 ;
	END Q[50]

	PIN Q[51]
		USE SIGNAL ;
		DIRECTION OUTPUT ;
		SHAPE ABUTMENT ;
		PORT
			 LAYER M2 ;
			RECT 0.0098 73.8824 0.0481 73.9827 ;
			 LAYER M3 ;
			RECT 0.0098 73.8824 0.0481 73.9827 ;
			 LAYER V2 ;
			RECT 0.021 73.9573 0.0359 73.9698 ;
		END

		ANTENNADIFFAREA 0.00194719 ;
		ANTENNAPARTIALMETALAREA 0.00195671 ;
	END Q[51]

	PIN Q[52]
		USE SIGNAL ;
		DIRECTION OUTPUT ;
		SHAPE ABUTMENT ;
		PORT
			 LAYER M2 ;
			RECT 0.0714 75.2251 0.1097 75.2627 ;
			 LAYER M3 ;
			RECT 0.0714 75.1624 0.1097 75.2627 ;
			 LAYER V2 ;
			RECT 0.0831 75.238 0.098 75.2506 ;
		END

		ANTENNADIFFAREA 0.00194719 ;
		ANTENNAPARTIALMETALAREA 0.00195671 ;
	END Q[52]

	PIN Q[53]
		USE SIGNAL ;
		DIRECTION OUTPUT ;
		SHAPE ABUTMENT ;
		PORT
			 LAYER M2 ;
			RECT 0.0714 76.5051 0.1097 76.5427 ;
			 LAYER M3 ;
			RECT 0.0714 76.4424 0.1097 76.5427 ;
			 LAYER V2 ;
			RECT 0.0831 76.518 0.098 76.5306 ;
		END

		ANTENNADIFFAREA 0.00194719 ;
		ANTENNAPARTIALMETALAREA 0.00195671 ;
	END Q[53]

	PIN Q[54]
		USE SIGNAL ;
		DIRECTION OUTPUT ;
		SHAPE ABUTMENT ;
		PORT
			 LAYER M2 ;
			RECT 0.0714 77.7851 0.1097 77.8227 ;
			 LAYER M3 ;
			RECT 0.0714 77.7224 0.1097 77.8227 ;
			 LAYER V2 ;
			RECT 0.0831 77.798 0.098 77.8106 ;
		END

		ANTENNADIFFAREA 0.00194719 ;
		ANTENNAPARTIALMETALAREA 0.00195671 ;
	END Q[54]

	PIN Q[55]
		USE SIGNAL ;
		DIRECTION OUTPUT ;
		SHAPE ABUTMENT ;
		PORT
			 LAYER M2 ;
			RECT 0.0714 79.1404 0.1097 79.178 ;
			 LAYER M3 ;
			RECT 0.0714 79.0776 0.1097 79.178 ;
			 LAYER V2 ;
			RECT 0.0831 79.1533 0.098 79.1659 ;
		END

		ANTENNADIFFAREA 0.00194719 ;
		ANTENNAPARTIALMETALAREA 0.00195671 ;
	END Q[55]

	PIN Q[56]
		USE SIGNAL ;
		DIRECTION OUTPUT ;
		SHAPE ABUTMENT ;
		PORT
			 LAYER M2 ;
			RECT 0.0714 80.3451 0.1097 80.3827 ;
			 LAYER M3 ;
			RECT 0.0714 80.2824 0.1097 80.3827 ;
			 LAYER V2 ;
			RECT 0.0831 80.358 0.098 80.3706 ;
		END

		ANTENNADIFFAREA 0.00194719 ;
		ANTENNAPARTIALMETALAREA 0.00195671 ;
	END Q[56]

	PIN Q[57]
		USE SIGNAL ;
		DIRECTION OUTPUT ;
		SHAPE ABUTMENT ;
		PORT
			 LAYER M2 ;
			RECT 0.0714 81.6251 0.1097 81.6627 ;
			 LAYER M3 ;
			RECT 0.0714 81.5624 0.1097 81.6627 ;
			 LAYER V2 ;
			RECT 0.0831 81.638 0.098 81.6506 ;
		END

		ANTENNADIFFAREA 0.00194719 ;
		ANTENNAPARTIALMETALAREA 0.00195671 ;
	END Q[57]

	PIN Q[58]
		USE SIGNAL ;
		DIRECTION OUTPUT ;
		SHAPE ABUTMENT ;
		PORT
			 LAYER M2 ;
			RECT 0.0098 82.8173 0.0481 82.9176 ;
			 LAYER M3 ;
			RECT 0.0098 82.8173 0.0481 82.9176 ;
			 LAYER V2 ;
			RECT 0.021 82.8302 0.0359 82.8427 ;
		END

		ANTENNADIFFAREA 0.00194719 ;
		ANTENNAPARTIALMETALAREA 0.00195671 ;
	END Q[58]

	PIN Q[59]
		USE SIGNAL ;
		DIRECTION OUTPUT ;
		SHAPE ABUTMENT ;
		PORT
			 LAYER M2 ;
			RECT 0.0098 84.0973 0.0481 84.1976 ;
			 LAYER M3 ;
			RECT 0.0098 84.0973 0.0481 84.1976 ;
			 LAYER V2 ;
			RECT 0.021 84.1102 0.0359 84.1227 ;
		END

		ANTENNADIFFAREA 0.00194719 ;
		ANTENNAPARTIALMETALAREA 0.00195671 ;
	END Q[59]

	PIN Q[5]
		USE SIGNAL ;
		DIRECTION OUTPUT ;
		SHAPE ABUTMENT ;
		PORT
			 LAYER M2 ;
			RECT 0.0098 7.4918 0.0481 7.5922 ;
			 LAYER M3 ;
			RECT 0.0098 7.4918 0.0481 7.5922 ;
			 LAYER V2 ;
			RECT 0.021 7.5667 0.0359 7.5792 ;
		END

		ANTENNADIFFAREA 0.00194719 ;
		ANTENNAPARTIALMETALAREA 0.00195671 ;
	END Q[5]

	PIN Q[60]
		USE SIGNAL ;
		DIRECTION OUTPUT ;
		SHAPE ABUTMENT ;
		PORT
			 LAYER M2 ;
			RECT 0.0098 85.3773 0.0481 85.4776 ;
			 LAYER M3 ;
			RECT 0.0098 85.3773 0.0481 85.4776 ;
			 LAYER V2 ;
			RECT 0.021 85.3902 0.0359 85.4027 ;
		END

		ANTENNADIFFAREA 0.00194719 ;
		ANTENNAPARTIALMETALAREA 0.00195671 ;
	END Q[60]

	PIN Q[61]
		USE SIGNAL ;
		DIRECTION OUTPUT ;
		SHAPE ABUTMENT ;
		PORT
			 LAYER M2 ;
			RECT 0.0098 86.6573 0.0481 86.7576 ;
			 LAYER M3 ;
			RECT 0.0098 86.6573 0.0481 86.7576 ;
			 LAYER V2 ;
			RECT 0.021 86.6702 0.0359 86.6827 ;
		END

		ANTENNADIFFAREA 0.00194719 ;
		ANTENNAPARTIALMETALAREA 0.00195671 ;
	END Q[61]

	PIN Q[62]
		USE SIGNAL ;
		DIRECTION OUTPUT ;
		SHAPE ABUTMENT ;
		PORT
			 LAYER M2 ;
			RECT 0.0098 87.9373 0.0481 88.0376 ;
			 LAYER M3 ;
			RECT 0.0098 87.9373 0.0481 88.0376 ;
			 LAYER V2 ;
			RECT 0.021 87.9502 0.0359 87.9627 ;
		END

		ANTENNADIFFAREA 0.00194719 ;
		ANTENNAPARTIALMETALAREA 0.00195671 ;
	END Q[62]

	PIN Q[63]
		USE SIGNAL ;
		DIRECTION OUTPUT ;
		SHAPE ABUTMENT ;
		PORT
			 LAYER M2 ;
			RECT 0.0098 89.2173 0.0481 89.3176 ;
			 LAYER M3 ;
			RECT 0.0098 89.2173 0.0481 89.3176 ;
			 LAYER V2 ;
			RECT 0.021 89.2302 0.0359 89.2427 ;
		END

		ANTENNADIFFAREA 0.00194719 ;
		ANTENNAPARTIALMETALAREA 0.00195671 ;
	END Q[63]

	PIN Q[64]
		USE SIGNAL ;
		DIRECTION OUTPUT ;
		SHAPE ABUTMENT ;
		PORT
			 LAYER M2 ;
			RECT 0.0098 90.4973 0.0481 90.5976 ;
			 LAYER M3 ;
			RECT 0.0098 90.4973 0.0481 90.5976 ;
			 LAYER V2 ;
			RECT 0.021 90.5102 0.0359 90.5227 ;
		END

		ANTENNADIFFAREA 0.00194719 ;
		ANTENNAPARTIALMETALAREA 0.00195671 ;
	END Q[64]

	PIN Q[65]
		USE SIGNAL ;
		DIRECTION OUTPUT ;
		SHAPE ABUTMENT ;
		PORT
			 LAYER M2 ;
			RECT 0.0098 91.7773 0.0481 91.8776 ;
			 LAYER M3 ;
			RECT 0.0098 91.7773 0.0481 91.8776 ;
			 LAYER V2 ;
			RECT 0.021 91.7902 0.0359 91.8027 ;
		END

		ANTENNADIFFAREA 0.00194719 ;
		ANTENNAPARTIALMETALAREA 0.00195671 ;
	END Q[65]

	PIN Q[66]
		USE SIGNAL ;
		DIRECTION OUTPUT ;
		SHAPE ABUTMENT ;
		PORT
			 LAYER M2 ;
			RECT 0.0098 93.0573 0.0481 93.1576 ;
			 LAYER M3 ;
			RECT 0.0098 93.0573 0.0481 93.1576 ;
			 LAYER V2 ;
			RECT 0.021 93.0702 0.0359 93.0827 ;
		END

		ANTENNADIFFAREA 0.00194719 ;
		ANTENNAPARTIALMETALAREA 0.00195671 ;
	END Q[66]

	PIN Q[67]
		USE SIGNAL ;
		DIRECTION OUTPUT ;
		SHAPE ABUTMENT ;
		PORT
			 LAYER M2 ;
			RECT 0.0098 94.3373 0.0481 94.4376 ;
			 LAYER M3 ;
			RECT 0.0098 94.3373 0.0481 94.4376 ;
			 LAYER V2 ;
			RECT 0.021 94.3502 0.0359 94.3627 ;
		END

		ANTENNADIFFAREA 0.00194719 ;
		ANTENNAPARTIALMETALAREA 0.00195671 ;
	END Q[67]

	PIN Q[68]
		USE SIGNAL ;
		DIRECTION OUTPUT ;
		SHAPE ABUTMENT ;
		PORT
			 LAYER M2 ;
			RECT 0.0098 95.6173 0.0481 95.7176 ;
			 LAYER M3 ;
			RECT 0.0098 95.6173 0.0481 95.7176 ;
			 LAYER V2 ;
			RECT 0.021 95.6302 0.0359 95.6427 ;
		END

		ANTENNADIFFAREA 0.00194719 ;
		ANTENNAPARTIALMETALAREA 0.00195671 ;
	END Q[68]

	PIN Q[69]
		USE SIGNAL ;
		DIRECTION OUTPUT ;
		SHAPE ABUTMENT ;
		PORT
			 LAYER M2 ;
			RECT 0.0098 96.8973 0.0481 96.9976 ;
			 LAYER M3 ;
			RECT 0.0098 96.8973 0.0481 96.9976 ;
			 LAYER V2 ;
			RECT 0.021 96.9102 0.0359 96.9227 ;
		END

		ANTENNADIFFAREA 0.00194719 ;
		ANTENNAPARTIALMETALAREA 0.00195671 ;
	END Q[69]

	PIN Q[6]
		USE SIGNAL ;
		DIRECTION OUTPUT ;
		SHAPE ABUTMENT ;
		PORT
			 LAYER M2 ;
			RECT 0.0098 8.7718 0.0481 8.8722 ;
			 LAYER M3 ;
			RECT 0.0098 8.7718 0.0481 8.8722 ;
			 LAYER V2 ;
			RECT 0.021 8.8467 0.0359 8.8592 ;
		END

		ANTENNADIFFAREA 0.00194719 ;
		ANTENNAPARTIALMETALAREA 0.00195671 ;
	END Q[6]

	PIN Q[70]
		USE SIGNAL ;
		DIRECTION OUTPUT ;
		SHAPE ABUTMENT ;
		PORT
			 LAYER M2 ;
			RECT 0.0098 98.1773 0.0481 98.2776 ;
			 LAYER M3 ;
			RECT 0.0098 98.1773 0.0481 98.2776 ;
			 LAYER V2 ;
			RECT 0.021 98.1902 0.0359 98.2027 ;
		END

		ANTENNADIFFAREA 0.00194719 ;
		ANTENNAPARTIALMETALAREA 0.00195671 ;
	END Q[70]

	PIN Q[71]
		USE SIGNAL ;
		DIRECTION OUTPUT ;
		SHAPE ABUTMENT ;
		PORT
			 LAYER M2 ;
			RECT 0.0098 99.4573 0.0481 99.5576 ;
			 LAYER M3 ;
			RECT 0.0098 99.4573 0.0481 99.5576 ;
			 LAYER V2 ;
			RECT 0.021 99.4702 0.0359 99.4827 ;
		END

		ANTENNADIFFAREA 0.00194719 ;
		ANTENNAPARTIALMETALAREA 0.00195671 ;
	END Q[71]

	PIN Q[72]
		USE SIGNAL ;
		DIRECTION OUTPUT ;
		SHAPE ABUTMENT ;
		PORT
			 LAYER M2 ;
			RECT 0.0098 108.4361 0.0481 108.5365 ;
			 LAYER M3 ;
			RECT 0.0098 108.4361 0.0481 108.5365 ;
			 LAYER V2 ;
			RECT 0.021 108.449 0.0359 108.4616 ;
		END

		ANTENNADIFFAREA 0.00194719 ;
		ANTENNAPARTIALMETALAREA 0.00195671 ;
	END Q[72]

	PIN Q[73]
		USE SIGNAL ;
		DIRECTION OUTPUT ;
		SHAPE ABUTMENT ;
		PORT
			 LAYER M2 ;
			RECT 0.0098 109.7161 0.0481 109.8165 ;
			 LAYER M3 ;
			RECT 0.0098 109.7161 0.0481 109.8165 ;
			 LAYER V2 ;
			RECT 0.021 109.729 0.0359 109.7416 ;
		END

		ANTENNADIFFAREA 0.00194719 ;
		ANTENNAPARTIALMETALAREA 0.00195671 ;
	END Q[73]

	PIN Q[74]
		USE SIGNAL ;
		DIRECTION OUTPUT ;
		SHAPE ABUTMENT ;
		PORT
			 LAYER M2 ;
			RECT 0.0098 110.9961 0.0481 111.0965 ;
			 LAYER M3 ;
			RECT 0.0098 110.9961 0.0481 111.0965 ;
			 LAYER V2 ;
			RECT 0.021 111.009 0.0359 111.0216 ;
		END

		ANTENNADIFFAREA 0.00194719 ;
		ANTENNAPARTIALMETALAREA 0.00195671 ;
	END Q[74]

	PIN Q[75]
		USE SIGNAL ;
		DIRECTION OUTPUT ;
		SHAPE ABUTMENT ;
		PORT
			 LAYER M2 ;
			RECT 0.0098 112.2761 0.0481 112.3765 ;
			 LAYER M3 ;
			RECT 0.0098 112.2761 0.0481 112.3765 ;
			 LAYER V2 ;
			RECT 0.021 112.289 0.0359 112.3016 ;
		END

		ANTENNADIFFAREA 0.00194719 ;
		ANTENNAPARTIALMETALAREA 0.00195671 ;
	END Q[75]

	PIN Q[76]
		USE SIGNAL ;
		DIRECTION OUTPUT ;
		SHAPE ABUTMENT ;
		PORT
			 LAYER M2 ;
			RECT 0.0098 113.5561 0.0481 113.6565 ;
			 LAYER M3 ;
			RECT 0.0098 113.5561 0.0481 113.6565 ;
			 LAYER V2 ;
			RECT 0.021 113.569 0.0359 113.5816 ;
		END

		ANTENNADIFFAREA 0.00194719 ;
		ANTENNAPARTIALMETALAREA 0.00195671 ;
	END Q[76]

	PIN Q[77]
		USE SIGNAL ;
		DIRECTION OUTPUT ;
		SHAPE ABUTMENT ;
		PORT
			 LAYER M2 ;
			RECT 0.0098 114.8361 0.0481 114.9365 ;
			 LAYER M3 ;
			RECT 0.0098 114.8361 0.0481 114.9365 ;
			 LAYER V2 ;
			RECT 0.021 114.849 0.0359 114.8616 ;
		END

		ANTENNADIFFAREA 0.00194719 ;
		ANTENNAPARTIALMETALAREA 0.00195671 ;
	END Q[77]

	PIN Q[78]
		USE SIGNAL ;
		DIRECTION OUTPUT ;
		SHAPE ABUTMENT ;
		PORT
			 LAYER M2 ;
			RECT 0.0098 116.1161 0.0481 116.2165 ;
			 LAYER M3 ;
			RECT 0.0098 116.1161 0.0481 116.2165 ;
			 LAYER V2 ;
			RECT 0.021 116.129 0.0359 116.1416 ;
		END

		ANTENNADIFFAREA 0.00194719 ;
		ANTENNAPARTIALMETALAREA 0.00195671 ;
	END Q[78]

	PIN Q[79]
		USE SIGNAL ;
		DIRECTION OUTPUT ;
		SHAPE ABUTMENT ;
		PORT
			 LAYER M2 ;
			RECT 0.0098 117.3961 0.0481 117.4965 ;
			 LAYER M3 ;
			RECT 0.0098 117.3961 0.0481 117.4965 ;
			 LAYER V2 ;
			RECT 0.021 117.409 0.0359 117.4216 ;
		END

		ANTENNADIFFAREA 0.00194719 ;
		ANTENNAPARTIALMETALAREA 0.00195671 ;
	END Q[79]

	PIN Q[7]
		USE SIGNAL ;
		DIRECTION OUTPUT ;
		SHAPE ABUTMENT ;
		PORT
			 LAYER M2 ;
			RECT 0.0098 10.0518 0.0481 10.1522 ;
			 LAYER M3 ;
			RECT 0.0098 10.0518 0.0481 10.1522 ;
			 LAYER V2 ;
			RECT 0.021 10.1267 0.0359 10.1392 ;
		END

		ANTENNADIFFAREA 0.00194719 ;
		ANTENNAPARTIALMETALAREA 0.00195671 ;
	END Q[7]

	PIN Q[80]
		USE SIGNAL ;
		DIRECTION OUTPUT ;
		SHAPE ABUTMENT ;
		PORT
			 LAYER M2 ;
			RECT 0.0098 118.6761 0.0481 118.7765 ;
			 LAYER M3 ;
			RECT 0.0098 118.6761 0.0481 118.7765 ;
			 LAYER V2 ;
			RECT 0.021 118.689 0.0359 118.7016 ;
		END

		ANTENNADIFFAREA 0.00194719 ;
		ANTENNAPARTIALMETALAREA 0.00195671 ;
	END Q[80]

	PIN Q[81]
		USE SIGNAL ;
		DIRECTION OUTPUT ;
		SHAPE ABUTMENT ;
		PORT
			 LAYER M2 ;
			RECT 0.0098 119.9561 0.0481 120.0565 ;
			 LAYER M3 ;
			RECT 0.0098 119.9561 0.0481 120.0565 ;
			 LAYER V2 ;
			RECT 0.021 119.969 0.0359 119.9816 ;
		END

		ANTENNADIFFAREA 0.00194719 ;
		ANTENNAPARTIALMETALAREA 0.00195671 ;
	END Q[81]

	PIN Q[82]
		USE SIGNAL ;
		DIRECTION OUTPUT ;
		SHAPE ABUTMENT ;
		PORT
			 LAYER M2 ;
			RECT 0.0098 121.2361 0.0481 121.3365 ;
			 LAYER M3 ;
			RECT 0.0098 121.2361 0.0481 121.3365 ;
			 LAYER V2 ;
			RECT 0.021 121.249 0.0359 121.2616 ;
		END

		ANTENNADIFFAREA 0.00194719 ;
		ANTENNAPARTIALMETALAREA 0.00195671 ;
	END Q[82]

	PIN Q[83]
		USE SIGNAL ;
		DIRECTION OUTPUT ;
		SHAPE ABUTMENT ;
		PORT
			 LAYER M2 ;
			RECT 0.0098 122.5161 0.0481 122.6165 ;
			 LAYER M3 ;
			RECT 0.0098 122.5161 0.0481 122.6165 ;
			 LAYER V2 ;
			RECT 0.021 122.529 0.0359 122.5416 ;
		END

		ANTENNADIFFAREA 0.00194719 ;
		ANTENNAPARTIALMETALAREA 0.00195671 ;
	END Q[83]

	PIN Q[84]
		USE SIGNAL ;
		DIRECTION OUTPUT ;
		SHAPE ABUTMENT ;
		PORT
			 LAYER M2 ;
			RECT 0.0098 123.7961 0.0481 123.8965 ;
			 LAYER M3 ;
			RECT 0.0098 123.7961 0.0481 123.8965 ;
			 LAYER V2 ;
			RECT 0.021 123.809 0.0359 123.8216 ;
		END

		ANTENNADIFFAREA 0.00194719 ;
		ANTENNAPARTIALMETALAREA 0.00195671 ;
	END Q[84]

	PIN Q[85]
		USE SIGNAL ;
		DIRECTION OUTPUT ;
		SHAPE ABUTMENT ;
		PORT
			 LAYER M2 ;
			RECT 0.0098 125.0761 0.0481 125.1765 ;
			 LAYER M3 ;
			RECT 0.0098 125.0761 0.0481 125.1765 ;
			 LAYER V2 ;
			RECT 0.021 125.089 0.0359 125.1016 ;
		END

		ANTENNADIFFAREA 0.00194719 ;
		ANTENNAPARTIALMETALAREA 0.00195671 ;
	END Q[85]

	PIN Q[86]
		USE SIGNAL ;
		DIRECTION OUTPUT ;
		SHAPE ABUTMENT ;
		PORT
			 LAYER M2 ;
			RECT 0.0098 126.3561 0.0481 126.4565 ;
			 LAYER M3 ;
			RECT 0.0098 126.3561 0.0481 126.4565 ;
			 LAYER V2 ;
			RECT 0.021 126.369 0.0359 126.3816 ;
		END

		ANTENNADIFFAREA 0.00194719 ;
		ANTENNAPARTIALMETALAREA 0.00195671 ;
	END Q[86]

	PIN Q[87]
		USE SIGNAL ;
		DIRECTION OUTPUT ;
		SHAPE ABUTMENT ;
		PORT
			 LAYER M2 ;
			RECT 0.0098 127.6361 0.0481 127.7365 ;
			 LAYER M3 ;
			RECT 0.0098 127.6361 0.0481 127.7365 ;
			 LAYER V2 ;
			RECT 0.021 127.649 0.0359 127.6616 ;
		END

		ANTENNADIFFAREA 0.00194719 ;
		ANTENNAPARTIALMETALAREA 0.00195671 ;
	END Q[87]

	PIN Q[88]
		USE SIGNAL ;
		DIRECTION OUTPUT ;
		SHAPE ABUTMENT ;
		PORT
			 LAYER M2 ;
			RECT 0.0098 128.9161 0.0481 129.0165 ;
			 LAYER M3 ;
			RECT 0.0098 128.9161 0.0481 129.0165 ;
			 LAYER V2 ;
			RECT 0.021 128.929 0.0359 128.9416 ;
		END

		ANTENNADIFFAREA 0.00194719 ;
		ANTENNAPARTIALMETALAREA 0.00195671 ;
	END Q[88]

	PIN Q[89]
		USE SIGNAL ;
		DIRECTION OUTPUT ;
		SHAPE ABUTMENT ;
		PORT
			 LAYER M2 ;
			RECT 0.0098 130.1961 0.0481 130.2965 ;
			 LAYER M3 ;
			RECT 0.0098 130.1961 0.0481 130.2965 ;
			 LAYER V2 ;
			RECT 0.021 130.209 0.0359 130.2216 ;
		END

		ANTENNADIFFAREA 0.00194719 ;
		ANTENNAPARTIALMETALAREA 0.00195671 ;
	END Q[89]

	PIN Q[8]
		USE SIGNAL ;
		DIRECTION OUTPUT ;
		SHAPE ABUTMENT ;
		PORT
			 LAYER M2 ;
			RECT 0.0098 11.3318 0.0481 11.4322 ;
			 LAYER M3 ;
			RECT 0.0098 11.3318 0.0481 11.4322 ;
			 LAYER V2 ;
			RECT 0.021 11.4067 0.0359 11.4192 ;
		END

		ANTENNADIFFAREA 0.00194719 ;
		ANTENNAPARTIALMETALAREA 0.00195671 ;
	END Q[8]

	PIN Q[90]
		USE SIGNAL ;
		DIRECTION OUTPUT ;
		SHAPE ABUTMENT ;
		PORT
			 LAYER M2 ;
			RECT 0.0098 131.4761 0.0481 131.5765 ;
			 LAYER M3 ;
			RECT 0.0098 131.4761 0.0481 131.5765 ;
			 LAYER V2 ;
			RECT 0.021 131.489 0.0359 131.5016 ;
		END

		ANTENNADIFFAREA 0.00194719 ;
		ANTENNAPARTIALMETALAREA 0.00195671 ;
	END Q[90]

	PIN Q[91]
		USE SIGNAL ;
		DIRECTION OUTPUT ;
		SHAPE ABUTMENT ;
		PORT
			 LAYER M2 ;
			RECT 0.0098 132.7561 0.0481 132.8565 ;
			 LAYER M3 ;
			RECT 0.0098 132.7561 0.0481 132.8565 ;
			 LAYER V2 ;
			RECT 0.021 132.769 0.0359 132.7816 ;
		END

		ANTENNADIFFAREA 0.00194719 ;
		ANTENNAPARTIALMETALAREA 0.00195671 ;
	END Q[91]

	PIN Q[92]
		USE SIGNAL ;
		DIRECTION OUTPUT ;
		SHAPE ABUTMENT ;
		PORT
			 LAYER M2 ;
			RECT 0.0098 134.0361 0.0481 134.1365 ;
			 LAYER M3 ;
			RECT 0.0098 134.0361 0.0481 134.1365 ;
			 LAYER V2 ;
			RECT 0.021 134.049 0.0359 134.0616 ;
		END

		ANTENNADIFFAREA 0.00194719 ;
		ANTENNAPARTIALMETALAREA 0.00195671 ;
	END Q[92]

	PIN Q[93]
		USE SIGNAL ;
		DIRECTION OUTPUT ;
		SHAPE ABUTMENT ;
		PORT
			 LAYER M2 ;
			RECT 0.0098 135.3161 0.0481 135.4165 ;
			 LAYER M3 ;
			RECT 0.0098 135.3161 0.0481 135.4165 ;
			 LAYER V2 ;
			RECT 0.021 135.329 0.0359 135.3416 ;
		END

		ANTENNADIFFAREA 0.00194719 ;
		ANTENNAPARTIALMETALAREA 0.00195671 ;
	END Q[93]

	PIN Q[94]
		USE SIGNAL ;
		DIRECTION OUTPUT ;
		SHAPE ABUTMENT ;
		PORT
			 LAYER M2 ;
			RECT 0.0098 136.5961 0.0481 136.6965 ;
			 LAYER M3 ;
			RECT 0.0098 136.5961 0.0481 136.6965 ;
			 LAYER V2 ;
			RECT 0.021 136.609 0.0359 136.6216 ;
		END

		ANTENNADIFFAREA 0.00194719 ;
		ANTENNAPARTIALMETALAREA 0.00195671 ;
	END Q[94]

	PIN Q[95]
		USE SIGNAL ;
		DIRECTION OUTPUT ;
		SHAPE ABUTMENT ;
		PORT
			 LAYER M2 ;
			RECT 0.0098 137.8761 0.0481 137.9765 ;
			 LAYER M3 ;
			RECT 0.0098 137.8761 0.0481 137.9765 ;
			 LAYER V2 ;
			RECT 0.021 137.889 0.0359 137.9016 ;
		END

		ANTENNADIFFAREA 0.00194719 ;
		ANTENNAPARTIALMETALAREA 0.00195671 ;
	END Q[95]

	PIN Q[9]
		USE SIGNAL ;
		DIRECTION OUTPUT ;
		SHAPE ABUTMENT ;
		PORT
			 LAYER M2 ;
			RECT 0.0098 12.6118 0.0481 12.7122 ;
			 LAYER M3 ;
			RECT 0.0098 12.6118 0.0481 12.7122 ;
			 LAYER V2 ;
			RECT 0.021 12.6867 0.0359 12.6992 ;
		END

		ANTENNADIFFAREA 0.00194719 ;
		ANTENNAPARTIALMETALAREA 0.00195671 ;
	END Q[9]

	PIN RAWL
		USE SIGNAL ;
		DIRECTION INPUT ;
		SHAPE ABUTMENT ;
		PORT
			 LAYER M2 ;
			RECT 0.0714 70.858 0.1097 70.8957 ;
			 LAYER M3 ;
			RECT 0.0714 70.7953 0.1097 70.8957 ;
			 LAYER V2 ;
			RECT 0.0831 70.871 0.098 70.8835 ;
		END

		ANTENNAGATEAREA 0.00027817 ;
		ANTENNADIFFAREA 0.00194719 ;
		ANTENNAPARTIALMETALAREA 0.00195671 ;
	END RAWL

	PIN RAWLM[0]
		USE SIGNAL ;
		DIRECTION INPUT ;
		SHAPE ABUTMENT ;
		PORT
			 LAYER M2 ;
			RECT 0.0714 70.6322 0.1097 70.6698 ;
			 LAYER M3 ;
			RECT 0.0714 70.5694 0.1097 70.6698 ;
			 LAYER V2 ;
			RECT 0.0831 70.6451 0.098 70.6576 ;
		END

		ANTENNAGATEAREA 0.00027817 ;
		ANTENNADIFFAREA 0.00194719 ;
		ANTENNAPARTIALMETALAREA 0.00195671 ;
	END RAWLM[0]

	PIN RAWLM[1]
		USE SIGNAL ;
		DIRECTION INPUT ;
		SHAPE ABUTMENT ;
		PORT
			 LAYER M2 ;
			RECT 0.0098 70.0424 0.0481 70.08 ;
			 LAYER M3 ;
			RECT 0.0098 70.0424 0.0481 70.1427 ;
			 LAYER V2 ;
			RECT 0.0215 70.0553 0.0364 70.0678 ;
		END

		ANTENNAGATEAREA 0.00027817 ;
		ANTENNADIFFAREA 0.00194719 ;
		ANTENNAPARTIALMETALAREA 0.00195671 ;
	END RAWLM[1]

	PIN RET1N
		USE SIGNAL ;
		DIRECTION INPUT ;
		SHAPE ABUTMENT ;
		PORT
			 LAYER M2 ;
			RECT 0.0098 81.7129 0.0481 81.7506 ;
			 LAYER M3 ;
			RECT 0.0098 81.7129 0.0481 81.8133 ;
			 LAYER V2 ;
			RECT 0.0215 81.7259 0.0364 81.7384 ;
		END

		ANTENNAGATEAREA 0.00027817 ;
		ANTENNADIFFAREA 0.00194719 ;
		ANTENNAPARTIALMETALAREA 0.00195671 ;
	END RET1N

	PIN SE
		USE SIGNAL ;
		DIRECTION INPUT ;
		SHAPE ABUTMENT ;
		PORT
			 LAYER M2 ;
			RECT 0.0098 79.0776 0.0481 79.1153 ;
			 LAYER M3 ;
			RECT 0.0098 79.0776 0.0481 79.178 ;
			 LAYER V2 ;
			RECT 0.0215 79.0906 0.0364 79.1031 ;
		END

		ANTENNAGATEAREA 0.00027817 ;
		ANTENNADIFFAREA 0.00194719 ;
		ANTENNAPARTIALMETALAREA 0.00195671 ;
	END SE

	PIN SI[0]
		USE SIGNAL ;
		DIRECTION INPUT ;
		SHAPE ABUTMENT ;
		PORT
			 LAYER M2 ;
			RECT 0.0714 0.0627 0.1097 0.1004 ;
			 LAYER M3 ;
			RECT 0.0714 0.0627 0.1097 0.1631 ;
			 LAYER V2 ;
			RECT 0.0831 0.0749 0.098 0.0875 ;
		END

		ANTENNAGATEAREA 0.00027817 ;
		ANTENNADIFFAREA 0.00194719 ;
		ANTENNAPARTIALMETALAREA 0.00195671 ;
	END SI[0]

	PIN SI[1]
		USE SIGNAL ;
		DIRECTION INPUT ;
		SHAPE ABUTMENT ;
		PORT
			 LAYER M2 ;
			RECT 0.0714 138.9678 0.1097 139.0055 ;
			 LAYER M3 ;
			RECT 0.0714 138.9051 0.1097 139.0055 ;
			 LAYER V2 ;
			RECT 0.0831 138.9808 0.098 138.9933 ;
		END

		ANTENNAGATEAREA 0.00027817 ;
		ANTENNADIFFAREA 0.00194719 ;
		ANTENNAPARTIALMETALAREA 0.00195671 ;
	END SI[1]

	PIN SO[0]
		USE SIGNAL ;
		DIRECTION OUTPUT ;
		SHAPE ABUTMENT ;
		PORT
			 LAYER M2 ;
			RECT 0.0098 69.2894 0.0481 69.3271 ;
			 LAYER M3 ;
			RECT 0.0098 69.2267 0.0481 69.3271 ;
			 LAYER V2 ;
			RECT 0.0215 69.3016 0.0364 69.3141 ;
		END

		ANTENNADIFFAREA 0.00194719 ;
		ANTENNAPARTIALMETALAREA 0.00195671 ;
	END SO[0]

	PIN SO[1]
		USE SIGNAL ;
		DIRECTION OUTPUT ;
		SHAPE ABUTMENT ;
		PORT
			 LAYER M2 ;
			RECT 0.0098 69.7412 0.0481 69.7788 ;
			 LAYER M3 ;
			RECT 0.0098 69.7412 0.0481 69.8416 ;
			 LAYER V2 ;
			RECT 0.0215 69.7541 0.0364 69.7667 ;
		END

		ANTENNADIFFAREA 0.00194719 ;
		ANTENNAPARTIALMETALAREA 0.00195671 ;
	END SO[1]

	PIN STOV
		USE SIGNAL ;
		DIRECTION INPUT ;
		SHAPE ABUTMENT ;
		PORT
			 LAYER M2 ;
			RECT 0.0714 80.8722 0.1097 80.9098 ;
			 LAYER M3 ;
			RECT 0.0714 80.8094 0.1097 80.9098 ;
			 LAYER V2 ;
			RECT 0.0831 80.8851 0.098 80.8976 ;
		END

		ANTENNAGATEAREA 0.00027817 ;
		ANTENNADIFFAREA 0.00194719 ;
		ANTENNAPARTIALMETALAREA 0.00195671 ;
	END STOV

	PIN TA[0]
		USE SIGNAL ;
		DIRECTION INPUT ;
		SHAPE ABUTMENT ;
		PORT
			 LAYER M2 ;
			RECT 0.0098 74.56 0.0481 74.5976 ;
			 LAYER M3 ;
			RECT 0.0098 74.56 0.0481 74.6604 ;
			 LAYER V2 ;
			RECT 0.0215 74.5729 0.0364 74.5855 ;
		END

		ANTENNAGATEAREA 0.00027817 ;
		ANTENNADIFFAREA 0.00194719 ;
		ANTENNAPARTIALMETALAREA 0.00195671 ;
	END TA[0]

	PIN TA[1]
		USE SIGNAL ;
		DIRECTION INPUT ;
		SHAPE ABUTMENT ;
		PORT
			 LAYER M2 ;
			RECT 0.0098 73.1294 0.0481 73.2298 ;
			 LAYER M3 ;
			RECT 0.0098 73.1294 0.0481 73.2298 ;
			 LAYER V2 ;
			RECT 0.021 73.2043 0.0359 73.2169 ;
		END

		ANTENNAGATEAREA 0.00027817 ;
		ANTENNADIFFAREA 0.00194719 ;
		ANTENNAPARTIALMETALAREA 0.00195671 ;
	END TA[1]

	PIN TA[2]
		USE SIGNAL ;
		DIRECTION INPUT ;
		SHAPE ABUTMENT ;
		PORT
			 LAYER M2 ;
			RECT 0.0098 72.0753 0.0481 72.1757 ;
			 LAYER M3 ;
			RECT 0.0098 72.0753 0.0481 72.1757 ;
			 LAYER V2 ;
			RECT 0.021 72.1502 0.0359 72.1627 ;
		END

		ANTENNAGATEAREA 0.00027817 ;
		ANTENNADIFFAREA 0.00194719 ;
		ANTENNAPARTIALMETALAREA 0.00195671 ;
	END TA[2]

	PIN TA[3]
		USE SIGNAL ;
		DIRECTION INPUT ;
		SHAPE ABUTMENT ;
		PORT
			 LAYER M2 ;
			RECT 0.0098 58.9741 0.0481 59.0118 ;
			 LAYER M3 ;
			RECT 0.0098 58.9114 0.0481 59.0118 ;
			 LAYER V2 ;
			RECT 0.0215 58.9863 0.0364 58.9988 ;
		END

		ANTENNAGATEAREA 0.00027817 ;
		ANTENNADIFFAREA 0.00194719 ;
		ANTENNAPARTIALMETALAREA 0.00195671 ;
	END TA[3]

	PIN TA[4]
		USE SIGNAL ;
		DIRECTION INPUT ;
		SHAPE ABUTMENT ;
		PORT
			 LAYER M2 ;
			RECT 0.0098 68.6243 0.0481 68.7247 ;
			 LAYER M3 ;
			RECT 0.0098 68.6243 0.0481 68.7247 ;
			 LAYER V2 ;
			RECT 0.021 68.6373 0.0359 68.6498 ;
		END

		ANTENNAGATEAREA 0.00027817 ;
		ANTENNADIFFAREA 0.00194719 ;
		ANTENNAPARTIALMETALAREA 0.00195671 ;
	END TA[4]

	PIN TA[5]
		USE SIGNAL ;
		DIRECTION INPUT ;
		SHAPE ABUTMENT ;
		PORT
			 LAYER M2 ;
			RECT 0.0098 61.76 0.0481 61.7976 ;
			 LAYER M3 ;
			RECT 0.0098 61.6973 0.0481 61.7976 ;
			 LAYER V2 ;
			RECT 0.0215 61.7722 0.0364 61.7847 ;
		END

		ANTENNAGATEAREA 0.00027817 ;
		ANTENNADIFFAREA 0.00194719 ;
		ANTENNAPARTIALMETALAREA 0.00195671 ;
	END TA[5]

	PIN TA[6]
		USE SIGNAL ;
		DIRECTION INPUT ;
		SHAPE ABUTMENT ;
		PORT
			 LAYER M2 ;
			RECT 0.0714 59.2125 0.1097 59.2502 ;
			 LAYER M3 ;
			RECT 0.0714 59.2125 0.1097 59.3129 ;
			 LAYER V2 ;
			RECT 0.0831 59.2247 0.098 59.2373 ;
		END

		ANTENNAGATEAREA 0.00027817 ;
		ANTENNADIFFAREA 0.00194719 ;
		ANTENNAPARTIALMETALAREA 0.00195671 ;
	END TA[6]

	PIN TA[7]
		USE SIGNAL ;
		DIRECTION INPUT ;
		SHAPE ABUTMENT ;
		PORT
			 LAYER M2 ;
			RECT 0.0098 60.869 0.0481 60.9694 ;
			 LAYER M3 ;
			RECT 0.0098 60.869 0.0481 60.9694 ;
			 LAYER V2 ;
			RECT 0.021 60.9439 0.0359 60.9565 ;
		END

		ANTENNAGATEAREA 0.00027817 ;
		ANTENNADIFFAREA 0.00194719 ;
		ANTENNAPARTIALMETALAREA 0.00195671 ;
	END TA[7]

	PIN TA[8]
		USE SIGNAL ;
		DIRECTION INPUT ;
		SHAPE ABUTMENT ;
		PORT
			 LAYER M2 ;
			RECT 0.0714 63.0525 0.1097 63.0902 ;
			 LAYER M3 ;
			RECT 0.0714 63.0525 0.1097 63.1529 ;
			 LAYER V2 ;
			RECT 0.0831 63.0647 0.098 63.0773 ;
		END

		ANTENNAGATEAREA 0.00027817 ;
		ANTENNADIFFAREA 0.00194719 ;
		ANTENNAPARTIALMETALAREA 0.00195671 ;
	END TA[8]

	PIN TA[9]
		USE SIGNAL ;
		DIRECTION INPUT ;
		SHAPE ABUTMENT ;
		PORT
			 LAYER M2 ;
			RECT 0.0098 64.4706 0.0481 64.5082 ;
			 LAYER M3 ;
			RECT 0.0098 64.4078 0.0481 64.5082 ;
			 LAYER V2 ;
			RECT 0.0215 64.4827 0.0364 64.4953 ;
		END

		ANTENNAGATEAREA 0.00027817 ;
		ANTENNADIFFAREA 0.00194719 ;
		ANTENNAPARTIALMETALAREA 0.00195671 ;
	END TA[9]

	PIN TCEN
		USE SIGNAL ;
		DIRECTION INPUT ;
		SHAPE ABUTMENT ;
		PORT
			 LAYER M2 ;
			RECT 0.0714 74.9239 0.1097 74.9616 ;
			 LAYER M3 ;
			RECT 0.0714 74.8612 0.1097 74.9616 ;
			 LAYER V2 ;
			RECT 0.0831 74.9369 0.098 74.9494 ;
		END

		ANTENNAGATEAREA 0.00027817 ;
		ANTENNADIFFAREA 0.00194719 ;
		ANTENNAPARTIALMETALAREA 0.00195671 ;
	END TCEN

	PIN TD[0]
		USE SIGNAL ;
		DIRECTION INPUT ;
		SHAPE ABUTMENT ;
		PORT
			 LAYER M2 ;
			RECT 0.0098 0.9663 0.0481 1.0039 ;
			 LAYER M3 ;
			RECT 0.0098 0.9663 0.0481 1.0667 ;
			 LAYER V2 ;
			RECT 0.0215 0.9792 0.0364 0.9918 ;
		END

		ANTENNAGATEAREA 0.00027817 ;
		ANTENNADIFFAREA 0.00194719 ;
		ANTENNAPARTIALMETALAREA 0.00195671 ;
	END TD[0]

	PIN TD[10]
		USE SIGNAL ;
		DIRECTION INPUT ;
		SHAPE ABUTMENT ;
		PORT
			 LAYER M2 ;
			RECT 0.0098 13.7663 0.0481 13.8039 ;
			 LAYER M3 ;
			RECT 0.0098 13.7663 0.0481 13.8667 ;
			 LAYER V2 ;
			RECT 0.0215 13.7792 0.0364 13.7918 ;
		END

		ANTENNAGATEAREA 0.00027817 ;
		ANTENNADIFFAREA 0.00194719 ;
		ANTENNAPARTIALMETALAREA 0.00195671 ;
	END TD[10]

	PIN TD[11]
		USE SIGNAL ;
		DIRECTION INPUT ;
		SHAPE ABUTMENT ;
		PORT
			 LAYER M2 ;
			RECT 0.0098 15.0463 0.0481 15.0839 ;
			 LAYER M3 ;
			RECT 0.0098 15.0463 0.0481 15.1467 ;
			 LAYER V2 ;
			RECT 0.0215 15.0592 0.0364 15.0718 ;
		END

		ANTENNAGATEAREA 0.00027817 ;
		ANTENNADIFFAREA 0.00194719 ;
		ANTENNAPARTIALMETALAREA 0.00195671 ;
	END TD[11]

	PIN TD[12]
		USE SIGNAL ;
		DIRECTION INPUT ;
		SHAPE ABUTMENT ;
		PORT
			 LAYER M2 ;
			RECT 0.0098 16.3263 0.0481 16.3639 ;
			 LAYER M3 ;
			RECT 0.0098 16.3263 0.0481 16.4267 ;
			 LAYER V2 ;
			RECT 0.0215 16.3392 0.0364 16.3518 ;
		END

		ANTENNAGATEAREA 0.00027817 ;
		ANTENNADIFFAREA 0.00194719 ;
		ANTENNAPARTIALMETALAREA 0.00195671 ;
	END TD[12]

	PIN TD[13]
		USE SIGNAL ;
		DIRECTION INPUT ;
		SHAPE ABUTMENT ;
		PORT
			 LAYER M2 ;
			RECT 0.0098 17.6063 0.0481 17.6439 ;
			 LAYER M3 ;
			RECT 0.0098 17.6063 0.0481 17.7067 ;
			 LAYER V2 ;
			RECT 0.0215 17.6192 0.0364 17.6318 ;
		END

		ANTENNAGATEAREA 0.00027817 ;
		ANTENNADIFFAREA 0.00194719 ;
		ANTENNAPARTIALMETALAREA 0.00195671 ;
	END TD[13]

	PIN TD[14]
		USE SIGNAL ;
		DIRECTION INPUT ;
		SHAPE ABUTMENT ;
		PORT
			 LAYER M2 ;
			RECT 0.0098 18.8863 0.0481 18.9239 ;
			 LAYER M3 ;
			RECT 0.0098 18.8863 0.0481 18.9867 ;
			 LAYER V2 ;
			RECT 0.0215 18.8992 0.0364 18.9118 ;
		END

		ANTENNAGATEAREA 0.00027817 ;
		ANTENNADIFFAREA 0.00194719 ;
		ANTENNAPARTIALMETALAREA 0.00195671 ;
	END TD[14]

	PIN TD[15]
		USE SIGNAL ;
		DIRECTION INPUT ;
		SHAPE ABUTMENT ;
		PORT
			 LAYER M2 ;
			RECT 0.0098 20.1663 0.0481 20.2039 ;
			 LAYER M3 ;
			RECT 0.0098 20.1663 0.0481 20.2667 ;
			 LAYER V2 ;
			RECT 0.0215 20.1792 0.0364 20.1918 ;
		END

		ANTENNAGATEAREA 0.00027817 ;
		ANTENNADIFFAREA 0.00194719 ;
		ANTENNAPARTIALMETALAREA 0.00195671 ;
	END TD[15]

	PIN TD[16]
		USE SIGNAL ;
		DIRECTION INPUT ;
		SHAPE ABUTMENT ;
		PORT
			 LAYER M2 ;
			RECT 0.0098 21.4463 0.0481 21.4839 ;
			 LAYER M3 ;
			RECT 0.0098 21.4463 0.0481 21.5467 ;
			 LAYER V2 ;
			RECT 0.0215 21.4592 0.0364 21.4718 ;
		END

		ANTENNAGATEAREA 0.00027817 ;
		ANTENNADIFFAREA 0.00194719 ;
		ANTENNAPARTIALMETALAREA 0.00195671 ;
	END TD[16]

	PIN TD[17]
		USE SIGNAL ;
		DIRECTION INPUT ;
		SHAPE ABUTMENT ;
		PORT
			 LAYER M2 ;
			RECT 0.0098 22.7263 0.0481 22.7639 ;
			 LAYER M3 ;
			RECT 0.0098 22.7263 0.0481 22.8267 ;
			 LAYER V2 ;
			RECT 0.0215 22.7392 0.0364 22.7518 ;
		END

		ANTENNAGATEAREA 0.00027817 ;
		ANTENNADIFFAREA 0.00194719 ;
		ANTENNAPARTIALMETALAREA 0.00195671 ;
	END TD[17]

	PIN TD[18]
		USE SIGNAL ;
		DIRECTION INPUT ;
		SHAPE ABUTMENT ;
		PORT
			 LAYER M2 ;
			RECT 0.0098 24.0063 0.0481 24.0439 ;
			 LAYER M3 ;
			RECT 0.0098 24.0063 0.0481 24.1067 ;
			 LAYER V2 ;
			RECT 0.0215 24.0192 0.0364 24.0318 ;
		END

		ANTENNAGATEAREA 0.00027817 ;
		ANTENNADIFFAREA 0.00194719 ;
		ANTENNAPARTIALMETALAREA 0.00195671 ;
	END TD[18]

	PIN TD[19]
		USE SIGNAL ;
		DIRECTION INPUT ;
		SHAPE ABUTMENT ;
		PORT
			 LAYER M2 ;
			RECT 0.0098 25.2863 0.0481 25.3239 ;
			 LAYER M3 ;
			RECT 0.0098 25.2863 0.0481 25.3867 ;
			 LAYER V2 ;
			RECT 0.0215 25.2992 0.0364 25.3118 ;
		END

		ANTENNAGATEAREA 0.00027817 ;
		ANTENNADIFFAREA 0.00194719 ;
		ANTENNAPARTIALMETALAREA 0.00195671 ;
	END TD[19]

	PIN TD[1]
		USE SIGNAL ;
		DIRECTION INPUT ;
		SHAPE ABUTMENT ;
		PORT
			 LAYER M2 ;
			RECT 0.0098 2.2463 0.0481 2.2839 ;
			 LAYER M3 ;
			RECT 0.0098 2.2463 0.0481 2.3467 ;
			 LAYER V2 ;
			RECT 0.0215 2.2592 0.0364 2.2718 ;
		END

		ANTENNAGATEAREA 0.00027817 ;
		ANTENNADIFFAREA 0.00194719 ;
		ANTENNAPARTIALMETALAREA 0.00195671 ;
	END TD[1]

	PIN TD[20]
		USE SIGNAL ;
		DIRECTION INPUT ;
		SHAPE ABUTMENT ;
		PORT
			 LAYER M2 ;
			RECT 0.0098 26.5663 0.0481 26.6039 ;
			 LAYER M3 ;
			RECT 0.0098 26.5663 0.0481 26.6667 ;
			 LAYER V2 ;
			RECT 0.0215 26.5792 0.0364 26.5918 ;
		END

		ANTENNAGATEAREA 0.00027817 ;
		ANTENNADIFFAREA 0.00194719 ;
		ANTENNAPARTIALMETALAREA 0.00195671 ;
	END TD[20]

	PIN TD[21]
		USE SIGNAL ;
		DIRECTION INPUT ;
		SHAPE ABUTMENT ;
		PORT
			 LAYER M2 ;
			RECT 0.0098 27.8463 0.0481 27.8839 ;
			 LAYER M3 ;
			RECT 0.0098 27.8463 0.0481 27.9467 ;
			 LAYER V2 ;
			RECT 0.0215 27.8592 0.0364 27.8718 ;
		END

		ANTENNAGATEAREA 0.00027817 ;
		ANTENNADIFFAREA 0.00194719 ;
		ANTENNAPARTIALMETALAREA 0.00195671 ;
	END TD[21]

	PIN TD[22]
		USE SIGNAL ;
		DIRECTION INPUT ;
		SHAPE ABUTMENT ;
		PORT
			 LAYER M2 ;
			RECT 0.0098 29.1263 0.0481 29.1639 ;
			 LAYER M3 ;
			RECT 0.0098 29.1263 0.0481 29.2267 ;
			 LAYER V2 ;
			RECT 0.0215 29.1392 0.0364 29.1518 ;
		END

		ANTENNAGATEAREA 0.00027817 ;
		ANTENNADIFFAREA 0.00194719 ;
		ANTENNAPARTIALMETALAREA 0.00195671 ;
	END TD[22]

	PIN TD[23]
		USE SIGNAL ;
		DIRECTION INPUT ;
		SHAPE ABUTMENT ;
		PORT
			 LAYER M2 ;
			RECT 0.0098 30.4063 0.0481 30.4439 ;
			 LAYER M3 ;
			RECT 0.0098 30.4063 0.0481 30.5067 ;
			 LAYER V2 ;
			RECT 0.0215 30.4192 0.0364 30.4318 ;
		END

		ANTENNAGATEAREA 0.00027817 ;
		ANTENNADIFFAREA 0.00194719 ;
		ANTENNAPARTIALMETALAREA 0.00195671 ;
	END TD[23]

	PIN TD[24]
		USE SIGNAL ;
		DIRECTION INPUT ;
		SHAPE ABUTMENT ;
		PORT
			 LAYER M2 ;
			RECT 0.0098 39.3851 0.0481 39.4227 ;
			 LAYER M3 ;
			RECT 0.0098 39.3851 0.0481 39.4855 ;
			 LAYER V2 ;
			RECT 0.0215 39.398 0.0364 39.4106 ;
		END

		ANTENNAGATEAREA 0.00027817 ;
		ANTENNADIFFAREA 0.00194719 ;
		ANTENNAPARTIALMETALAREA 0.00195671 ;
	END TD[24]

	PIN TD[25]
		USE SIGNAL ;
		DIRECTION INPUT ;
		SHAPE ABUTMENT ;
		PORT
			 LAYER M2 ;
			RECT 0.0098 40.6651 0.0481 40.7027 ;
			 LAYER M3 ;
			RECT 0.0098 40.6651 0.0481 40.7655 ;
			 LAYER V2 ;
			RECT 0.0215 40.678 0.0364 40.6906 ;
		END

		ANTENNAGATEAREA 0.00027817 ;
		ANTENNADIFFAREA 0.00194719 ;
		ANTENNAPARTIALMETALAREA 0.00195671 ;
	END TD[25]

	PIN TD[26]
		USE SIGNAL ;
		DIRECTION INPUT ;
		SHAPE ABUTMENT ;
		PORT
			 LAYER M2 ;
			RECT 0.0098 41.9451 0.0481 41.9827 ;
			 LAYER M3 ;
			RECT 0.0098 41.9451 0.0481 42.0455 ;
			 LAYER V2 ;
			RECT 0.0215 41.958 0.0364 41.9706 ;
		END

		ANTENNAGATEAREA 0.00027817 ;
		ANTENNADIFFAREA 0.00194719 ;
		ANTENNAPARTIALMETALAREA 0.00195671 ;
	END TD[26]

	PIN TD[27]
		USE SIGNAL ;
		DIRECTION INPUT ;
		SHAPE ABUTMENT ;
		PORT
			 LAYER M2 ;
			RECT 0.0098 43.2251 0.0481 43.2627 ;
			 LAYER M3 ;
			RECT 0.0098 43.2251 0.0481 43.3255 ;
			 LAYER V2 ;
			RECT 0.0215 43.238 0.0364 43.2506 ;
		END

		ANTENNAGATEAREA 0.00027817 ;
		ANTENNADIFFAREA 0.00194719 ;
		ANTENNAPARTIALMETALAREA 0.00195671 ;
	END TD[27]

	PIN TD[28]
		USE SIGNAL ;
		DIRECTION INPUT ;
		SHAPE ABUTMENT ;
		PORT
			 LAYER M2 ;
			RECT 0.0098 44.5051 0.0481 44.5427 ;
			 LAYER M3 ;
			RECT 0.0098 44.5051 0.0481 44.6055 ;
			 LAYER V2 ;
			RECT 0.0215 44.518 0.0364 44.5306 ;
		END

		ANTENNAGATEAREA 0.00027817 ;
		ANTENNADIFFAREA 0.00194719 ;
		ANTENNAPARTIALMETALAREA 0.00195671 ;
	END TD[28]

	PIN TD[29]
		USE SIGNAL ;
		DIRECTION INPUT ;
		SHAPE ABUTMENT ;
		PORT
			 LAYER M2 ;
			RECT 0.0098 45.7851 0.0481 45.8227 ;
			 LAYER M3 ;
			RECT 0.0098 45.7851 0.0481 45.8855 ;
			 LAYER V2 ;
			RECT 0.0215 45.798 0.0364 45.8106 ;
		END

		ANTENNAGATEAREA 0.00027817 ;
		ANTENNADIFFAREA 0.00194719 ;
		ANTENNAPARTIALMETALAREA 0.00195671 ;
	END TD[29]

	PIN TD[2]
		USE SIGNAL ;
		DIRECTION INPUT ;
		SHAPE ABUTMENT ;
		PORT
			 LAYER M2 ;
			RECT 0.0098 3.5263 0.0481 3.5639 ;
			 LAYER M3 ;
			RECT 0.0098 3.5263 0.0481 3.6267 ;
			 LAYER V2 ;
			RECT 0.0215 3.5392 0.0364 3.5518 ;
		END

		ANTENNAGATEAREA 0.00027817 ;
		ANTENNADIFFAREA 0.00194719 ;
		ANTENNAPARTIALMETALAREA 0.00195671 ;
	END TD[2]

	PIN TD[30]
		USE SIGNAL ;
		DIRECTION INPUT ;
		SHAPE ABUTMENT ;
		PORT
			 LAYER M2 ;
			RECT 0.0098 47.0651 0.0481 47.1027 ;
			 LAYER M3 ;
			RECT 0.0098 47.0651 0.0481 47.1655 ;
			 LAYER V2 ;
			RECT 0.0215 47.078 0.0364 47.0906 ;
		END

		ANTENNAGATEAREA 0.00027817 ;
		ANTENNADIFFAREA 0.00194719 ;
		ANTENNAPARTIALMETALAREA 0.00195671 ;
	END TD[30]

	PIN TD[31]
		USE SIGNAL ;
		DIRECTION INPUT ;
		SHAPE ABUTMENT ;
		PORT
			 LAYER M2 ;
			RECT 0.0098 48.3451 0.0481 48.3827 ;
			 LAYER M3 ;
			RECT 0.0098 48.3451 0.0481 48.4455 ;
			 LAYER V2 ;
			RECT 0.0215 48.358 0.0364 48.3706 ;
		END

		ANTENNAGATEAREA 0.00027817 ;
		ANTENNADIFFAREA 0.00194719 ;
		ANTENNAPARTIALMETALAREA 0.00195671 ;
	END TD[31]

	PIN TD[32]
		USE SIGNAL ;
		DIRECTION INPUT ;
		SHAPE ABUTMENT ;
		PORT
			 LAYER M2 ;
			RECT 0.0098 49.6251 0.0481 49.6627 ;
			 LAYER M3 ;
			RECT 0.0098 49.6251 0.0481 49.7255 ;
			 LAYER V2 ;
			RECT 0.0215 49.638 0.0364 49.6506 ;
		END

		ANTENNAGATEAREA 0.00027817 ;
		ANTENNADIFFAREA 0.00194719 ;
		ANTENNAPARTIALMETALAREA 0.00195671 ;
	END TD[32]

	PIN TD[33]
		USE SIGNAL ;
		DIRECTION INPUT ;
		SHAPE ABUTMENT ;
		PORT
			 LAYER M2 ;
			RECT 0.0098 50.9051 0.0481 50.9427 ;
			 LAYER M3 ;
			RECT 0.0098 50.9051 0.0481 51.0055 ;
			 LAYER V2 ;
			RECT 0.0215 50.918 0.0364 50.9306 ;
		END

		ANTENNAGATEAREA 0.00027817 ;
		ANTENNADIFFAREA 0.00194719 ;
		ANTENNAPARTIALMETALAREA 0.00195671 ;
	END TD[33]

	PIN TD[34]
		USE SIGNAL ;
		DIRECTION INPUT ;
		SHAPE ABUTMENT ;
		PORT
			 LAYER M2 ;
			RECT 0.0098 52.1851 0.0481 52.2227 ;
			 LAYER M3 ;
			RECT 0.0098 52.1851 0.0481 52.2855 ;
			 LAYER V2 ;
			RECT 0.0215 52.198 0.0364 52.2106 ;
		END

		ANTENNAGATEAREA 0.00027817 ;
		ANTENNADIFFAREA 0.00194719 ;
		ANTENNAPARTIALMETALAREA 0.00195671 ;
	END TD[34]

	PIN TD[35]
		USE SIGNAL ;
		DIRECTION INPUT ;
		SHAPE ABUTMENT ;
		PORT
			 LAYER M2 ;
			RECT 0.0098 53.4651 0.0481 53.5027 ;
			 LAYER M3 ;
			RECT 0.0098 53.4651 0.0481 53.5655 ;
			 LAYER V2 ;
			RECT 0.0215 53.478 0.0364 53.4906 ;
		END

		ANTENNAGATEAREA 0.00027817 ;
		ANTENNADIFFAREA 0.00194719 ;
		ANTENNAPARTIALMETALAREA 0.00195671 ;
	END TD[35]

	PIN TD[36]
		USE SIGNAL ;
		DIRECTION INPUT ;
		SHAPE ABUTMENT ;
		PORT
			 LAYER M2 ;
			RECT 0.0098 54.7451 0.0481 54.7827 ;
			 LAYER M3 ;
			RECT 0.0098 54.7451 0.0481 54.8455 ;
			 LAYER V2 ;
			RECT 0.0215 54.758 0.0364 54.7706 ;
		END

		ANTENNAGATEAREA 0.00027817 ;
		ANTENNADIFFAREA 0.00194719 ;
		ANTENNAPARTIALMETALAREA 0.00195671 ;
	END TD[36]

	PIN TD[37]
		USE SIGNAL ;
		DIRECTION INPUT ;
		SHAPE ABUTMENT ;
		PORT
			 LAYER M2 ;
			RECT 0.0098 56.0251 0.0481 56.0627 ;
			 LAYER M3 ;
			RECT 0.0098 56.0251 0.0481 56.1255 ;
			 LAYER V2 ;
			RECT 0.0215 56.038 0.0364 56.0506 ;
		END

		ANTENNAGATEAREA 0.00027817 ;
		ANTENNADIFFAREA 0.00194719 ;
		ANTENNAPARTIALMETALAREA 0.00195671 ;
	END TD[37]

	PIN TD[38]
		USE SIGNAL ;
		DIRECTION INPUT ;
		SHAPE ABUTMENT ;
		PORT
			 LAYER M2 ;
			RECT 0.0098 57.7694 0.0481 57.8071 ;
			RECT 0.0098 57.7694 0.0481 57.8071 ;
			 LAYER M3 ;
			RECT 0.0098 57.7067 0.0481 57.8071 ;
			RECT 0.0098 57.7067 0.0481 57.8071 ;
			 LAYER V2 ;
			RECT 0.0215 57.7816 0.0364 57.7941 ;
		END

		ANTENNAGATEAREA 0.00027817 ;
		ANTENNADIFFAREA 0.00194719 ;
		ANTENNAPARTIALMETALAREA 0.00195671 ;
	END TD[38]

	PIN TD[39]
		USE SIGNAL ;
		DIRECTION INPUT ;
		SHAPE ABUTMENT ;
		PORT
			 LAYER M2 ;
			RECT 0.0714 59.062 0.1097 59.0996 ;
			 LAYER M3 ;
			RECT 0.0714 59.062 0.1097 59.1624 ;
			 LAYER V2 ;
			RECT 0.0831 59.0741 0.098 59.0867 ;
		END

		ANTENNAGATEAREA 0.00027817 ;
		ANTENNADIFFAREA 0.00194719 ;
		ANTENNAPARTIALMETALAREA 0.00195671 ;
	END TD[39]

	PIN TD[3]
		USE SIGNAL ;
		DIRECTION INPUT ;
		SHAPE ABUTMENT ;
		PORT
			 LAYER M2 ;
			RECT 0.0098 4.8063 0.0481 4.8439 ;
			 LAYER M3 ;
			RECT 0.0098 4.8063 0.0481 4.9067 ;
			 LAYER V2 ;
			RECT 0.0215 4.8192 0.0364 4.8318 ;
		END

		ANTENNAGATEAREA 0.00027817 ;
		ANTENNADIFFAREA 0.00194719 ;
		ANTENNAPARTIALMETALAREA 0.00195671 ;
	END TD[3]

	PIN TD[40]
		USE SIGNAL ;
		DIRECTION INPUT ;
		SHAPE ABUTMENT ;
		PORT
			 LAYER M2 ;
			RECT 0.0098 60.2541 0.0481 60.2918 ;
			 LAYER M3 ;
			RECT 0.0098 60.1914 0.0481 60.2918 ;
			 LAYER V2 ;
			RECT 0.0215 60.2663 0.0364 60.2788 ;
		END

		ANTENNAGATEAREA 0.00027817 ;
		ANTENNADIFFAREA 0.00194719 ;
		ANTENNAPARTIALMETALAREA 0.00195671 ;
	END TD[40]

	PIN TD[41]
		USE SIGNAL ;
		DIRECTION INPUT ;
		SHAPE ABUTMENT ;
		PORT
			 LAYER M2 ;
			RECT 0.0098 61.5341 0.0481 61.5718 ;
			 LAYER M3 ;
			RECT 0.0098 61.4714 0.0481 61.5718 ;
			 LAYER V2 ;
			RECT 0.0215 61.5463 0.0364 61.5588 ;
		END

		ANTENNAGATEAREA 0.00027817 ;
		ANTENNADIFFAREA 0.00194719 ;
		ANTENNAPARTIALMETALAREA 0.00195671 ;
	END TD[41]

	PIN TD[42]
		USE SIGNAL ;
		DIRECTION INPUT ;
		SHAPE ABUTMENT ;
		PORT
			 LAYER M2 ;
			RECT 0.0098 62.8894 0.0481 62.9271 ;
			 LAYER M3 ;
			RECT 0.0098 62.8267 0.0481 62.9271 ;
			 LAYER V2 ;
			RECT 0.0215 62.9016 0.0364 62.9141 ;
		END

		ANTENNAGATEAREA 0.00027817 ;
		ANTENNADIFFAREA 0.00194719 ;
		ANTENNAPARTIALMETALAREA 0.00195671 ;
	END TD[42]

	PIN TD[43]
		USE SIGNAL ;
		DIRECTION INPUT ;
		SHAPE ABUTMENT ;
		PORT
			 LAYER M2 ;
			RECT 0.0098 64.1694 0.0481 64.2071 ;
			 LAYER M3 ;
			RECT 0.0098 64.1067 0.0481 64.2071 ;
			 LAYER V2 ;
			RECT 0.0215 64.1816 0.0364 64.1941 ;
		END

		ANTENNAGATEAREA 0.00027817 ;
		ANTENNADIFFAREA 0.00194719 ;
		ANTENNAPARTIALMETALAREA 0.00195671 ;
	END TD[43]

	PIN TD[44]
		USE SIGNAL ;
		DIRECTION INPUT ;
		SHAPE ABUTMENT ;
		PORT
			 LAYER M2 ;
			RECT 0.0098 65.4494 0.0481 65.4871 ;
			 LAYER M3 ;
			RECT 0.0098 65.3867 0.0481 65.4871 ;
			 LAYER V2 ;
			RECT 0.0215 65.4616 0.0364 65.4741 ;
		END

		ANTENNAGATEAREA 0.00027817 ;
		ANTENNADIFFAREA 0.00194719 ;
		ANTENNAPARTIALMETALAREA 0.00195671 ;
	END TD[44]

	PIN TD[45]
		USE SIGNAL ;
		DIRECTION INPUT ;
		SHAPE ABUTMENT ;
		PORT
			 LAYER M2 ;
			RECT 0.0098 66.6541 0.0481 66.6918 ;
			 LAYER M3 ;
			RECT 0.0098 66.5914 0.0481 66.6918 ;
			 LAYER V2 ;
			RECT 0.0215 66.6663 0.0364 66.6788 ;
		END

		ANTENNAGATEAREA 0.00027817 ;
		ANTENNADIFFAREA 0.00194719 ;
		ANTENNAPARTIALMETALAREA 0.00195671 ;
	END TD[45]

	PIN TD[46]
		USE SIGNAL ;
		DIRECTION INPUT ;
		SHAPE ABUTMENT ;
		PORT
			 LAYER M2 ;
			RECT 0.0098 68.0094 0.0481 68.0471 ;
			 LAYER M3 ;
			RECT 0.0098 67.9467 0.0481 68.0471 ;
			 LAYER V2 ;
			RECT 0.0215 68.0216 0.0364 68.0341 ;
		END

		ANTENNAGATEAREA 0.00027817 ;
		ANTENNADIFFAREA 0.00194719 ;
		ANTENNAPARTIALMETALAREA 0.00195671 ;
	END TD[46]

	PIN TD[47]
		USE SIGNAL ;
		DIRECTION INPUT ;
		SHAPE ABUTMENT ;
		PORT
			 LAYER M2 ;
			RECT 0.0714 69.2267 0.1097 69.2643 ;
			 LAYER M3 ;
			RECT 0.0714 69.2267 0.1097 69.3271 ;
			 LAYER V2 ;
			RECT 0.0831 69.2388 0.098 69.2514 ;
		END

		ANTENNAGATEAREA 0.00027817 ;
		ANTENNADIFFAREA 0.00194719 ;
		ANTENNAPARTIALMETALAREA 0.00195671 ;
	END TD[47]

	PIN TD[48]
		USE SIGNAL ;
		DIRECTION INPUT ;
		SHAPE ABUTMENT ;
		PORT
			 LAYER M2 ;
			RECT 0.0714 69.8039 0.1097 69.8416 ;
			 LAYER M3 ;
			RECT 0.0714 69.7412 0.1097 69.8416 ;
			 LAYER V2 ;
			RECT 0.0831 69.8169 0.098 69.8294 ;
		END

		ANTENNAGATEAREA 0.00027817 ;
		ANTENNADIFFAREA 0.00194719 ;
		ANTENNAPARTIALMETALAREA 0.00195671 ;
	END TD[48]

	PIN TD[49]
		USE SIGNAL ;
		DIRECTION INPUT ;
		SHAPE ABUTMENT ;
		PORT
			 LAYER M2 ;
			RECT 0.0098 71.0212 0.0481 71.0588 ;
			 LAYER M3 ;
			RECT 0.0098 71.0212 0.0481 71.1216 ;
			 LAYER V2 ;
			RECT 0.0215 71.0341 0.0364 71.0467 ;
		END

		ANTENNAGATEAREA 0.00027817 ;
		ANTENNADIFFAREA 0.00194719 ;
		ANTENNAPARTIALMETALAREA 0.00195671 ;
	END TD[49]

	PIN TD[4]
		USE SIGNAL ;
		DIRECTION INPUT ;
		SHAPE ABUTMENT ;
		PORT
			 LAYER M2 ;
			RECT 0.0098 6.0863 0.0481 6.1239 ;
			 LAYER M3 ;
			RECT 0.0098 6.0863 0.0481 6.1867 ;
			 LAYER V2 ;
			RECT 0.0215 6.0992 0.0364 6.1118 ;
		END

		ANTENNAGATEAREA 0.00027817 ;
		ANTENNADIFFAREA 0.00194719 ;
		ANTENNAPARTIALMETALAREA 0.00195671 ;
	END TD[4]

	PIN TD[50]
		USE SIGNAL ;
		DIRECTION INPUT ;
		SHAPE ABUTMENT ;
		PORT
			 LAYER M2 ;
			RECT 0.0098 72.3765 0.0481 72.4141 ;
			 LAYER M3 ;
			RECT 0.0098 72.3765 0.0481 72.4769 ;
			 LAYER V2 ;
			RECT 0.0215 72.3894 0.0364 72.402 ;
		END

		ANTENNAGATEAREA 0.00027817 ;
		ANTENNADIFFAREA 0.00194719 ;
		ANTENNAPARTIALMETALAREA 0.00195671 ;
	END TD[50]

	PIN TD[51]
		USE SIGNAL ;
		DIRECTION INPUT ;
		SHAPE ABUTMENT ;
		PORT
			 LAYER M2 ;
			RECT 0.0714 73.5686 0.1097 73.6063 ;
			 LAYER M3 ;
			RECT 0.0714 73.5059 0.1097 73.6063 ;
			 LAYER V2 ;
			RECT 0.0831 73.5816 0.098 73.5941 ;
		END

		ANTENNAGATEAREA 0.00027817 ;
		ANTENNADIFFAREA 0.00194719 ;
		ANTENNAPARTIALMETALAREA 0.00195671 ;
	END TD[51]

	PIN TD[52]
		USE SIGNAL ;
		DIRECTION INPUT ;
		SHAPE ABUTMENT ;
		PORT
			 LAYER M2 ;
			RECT 0.0098 74.8612 0.0481 74.8988 ;
			 LAYER M3 ;
			RECT 0.0098 74.8612 0.0481 74.9616 ;
			 LAYER V2 ;
			RECT 0.0215 74.8741 0.0364 74.8867 ;
		END

		ANTENNAGATEAREA 0.00027817 ;
		ANTENNADIFFAREA 0.00194719 ;
		ANTENNAPARTIALMETALAREA 0.00195671 ;
	END TD[52]

	PIN TD[53]
		USE SIGNAL ;
		DIRECTION INPUT ;
		SHAPE ABUTMENT ;
		PORT
			 LAYER M2 ;
			RECT 0.0098 76.1412 0.0481 76.1788 ;
			 LAYER M3 ;
			RECT 0.0098 76.1412 0.0481 76.2416 ;
			 LAYER V2 ;
			RECT 0.0215 76.1541 0.0364 76.1667 ;
		END

		ANTENNAGATEAREA 0.00027817 ;
		ANTENNADIFFAREA 0.00194719 ;
		ANTENNAPARTIALMETALAREA 0.00195671 ;
	END TD[53]

	PIN TD[54]
		USE SIGNAL ;
		DIRECTION INPUT ;
		SHAPE ABUTMENT ;
		PORT
			 LAYER M2 ;
			RECT 0.0098 77.4965 0.0481 77.5341 ;
			 LAYER M3 ;
			RECT 0.0098 77.4965 0.0481 77.5969 ;
			 LAYER V2 ;
			RECT 0.0215 77.5094 0.0364 77.522 ;
		END

		ANTENNAGATEAREA 0.00027817 ;
		ANTENNADIFFAREA 0.00194719 ;
		ANTENNAPARTIALMETALAREA 0.00195671 ;
	END TD[54]

	PIN TD[55]
		USE SIGNAL ;
		DIRECTION INPUT ;
		SHAPE ABUTMENT ;
		PORT
			 LAYER M2 ;
			RECT 0.0098 78.7765 0.0481 78.8141 ;
			 LAYER M3 ;
			RECT 0.0098 78.7765 0.0481 78.8769 ;
			 LAYER V2 ;
			RECT 0.0215 78.7894 0.0364 78.802 ;
		END

		ANTENNAGATEAREA 0.00027817 ;
		ANTENNADIFFAREA 0.00194719 ;
		ANTENNAPARTIALMETALAREA 0.00195671 ;
	END TD[55]

	PIN TD[56]
		USE SIGNAL ;
		DIRECTION INPUT ;
		SHAPE ABUTMENT ;
		PORT
			 LAYER M2 ;
			RECT 0.0098 79.9059 0.0481 80.0063 ;
			 LAYER M3 ;
			RECT 0.0098 79.9059 0.0481 80.0063 ;
			 LAYER V2 ;
			RECT 0.021 79.9808 0.0359 79.9933 ;
		END

		ANTENNAGATEAREA 0.00027817 ;
		ANTENNADIFFAREA 0.00194719 ;
		ANTENNAPARTIALMETALAREA 0.00195671 ;
	END TD[56]

	PIN TD[57]
		USE SIGNAL ;
		DIRECTION INPUT ;
		SHAPE ABUTMENT ;
		PORT
			 LAYER M2 ;
			RECT 0.0098 81.2612 0.0481 81.2988 ;
			 LAYER M3 ;
			RECT 0.0098 81.2612 0.0481 81.3616 ;
			 LAYER V2 ;
			RECT 0.0215 81.2741 0.0364 81.2867 ;
		END

		ANTENNAGATEAREA 0.00027817 ;
		ANTENNADIFFAREA 0.00194719 ;
		ANTENNAPARTIALMETALAREA 0.00195671 ;
	END TD[57]

	PIN TD[58]
		USE SIGNAL ;
		DIRECTION INPUT ;
		SHAPE ABUTMENT ;
		PORT
			 LAYER M2 ;
			RECT 0.0098 83.0055 0.0481 83.0431 ;
			 LAYER M3 ;
			RECT 0.0098 82.9427 0.0481 83.0431 ;
			 LAYER V2 ;
			RECT 0.0215 83.0176 0.0364 83.0302 ;
		END

		ANTENNAGATEAREA 0.00027817 ;
		ANTENNADIFFAREA 0.00194719 ;
		ANTENNAPARTIALMETALAREA 0.00195671 ;
	END TD[58]

	PIN TD[59]
		USE SIGNAL ;
		DIRECTION INPUT ;
		SHAPE ABUTMENT ;
		PORT
			 LAYER M2 ;
			RECT 0.0098 84.2855 0.0481 84.3231 ;
			 LAYER M3 ;
			RECT 0.0098 84.2227 0.0481 84.3231 ;
			 LAYER V2 ;
			RECT 0.0215 84.2976 0.0364 84.3102 ;
		END

		ANTENNAGATEAREA 0.00027817 ;
		ANTENNADIFFAREA 0.00194719 ;
		ANTENNAPARTIALMETALAREA 0.00195671 ;
	END TD[59]

	PIN TD[5]
		USE SIGNAL ;
		DIRECTION INPUT ;
		SHAPE ABUTMENT ;
		PORT
			 LAYER M2 ;
			RECT 0.0098 7.3663 0.0481 7.4039 ;
			 LAYER M3 ;
			RECT 0.0098 7.3663 0.0481 7.4667 ;
			 LAYER V2 ;
			RECT 0.0215 7.3792 0.0364 7.3918 ;
		END

		ANTENNAGATEAREA 0.00027817 ;
		ANTENNADIFFAREA 0.00194719 ;
		ANTENNAPARTIALMETALAREA 0.00195671 ;
	END TD[5]

	PIN TD[60]
		USE SIGNAL ;
		DIRECTION INPUT ;
		SHAPE ABUTMENT ;
		PORT
			 LAYER M2 ;
			RECT 0.0098 85.5655 0.0481 85.6031 ;
			 LAYER M3 ;
			RECT 0.0098 85.5027 0.0481 85.6031 ;
			 LAYER V2 ;
			RECT 0.0215 85.5776 0.0364 85.5902 ;
		END

		ANTENNAGATEAREA 0.00027817 ;
		ANTENNADIFFAREA 0.00194719 ;
		ANTENNAPARTIALMETALAREA 0.00195671 ;
	END TD[60]

	PIN TD[61]
		USE SIGNAL ;
		DIRECTION INPUT ;
		SHAPE ABUTMENT ;
		PORT
			 LAYER M2 ;
			RECT 0.0098 86.8455 0.0481 86.8831 ;
			 LAYER M3 ;
			RECT 0.0098 86.7827 0.0481 86.8831 ;
			 LAYER V2 ;
			RECT 0.0215 86.8576 0.0364 86.8702 ;
		END

		ANTENNAGATEAREA 0.00027817 ;
		ANTENNADIFFAREA 0.00194719 ;
		ANTENNAPARTIALMETALAREA 0.00195671 ;
	END TD[61]

	PIN TD[62]
		USE SIGNAL ;
		DIRECTION INPUT ;
		SHAPE ABUTMENT ;
		PORT
			 LAYER M2 ;
			RECT 0.0098 88.1255 0.0481 88.1631 ;
			 LAYER M3 ;
			RECT 0.0098 88.0627 0.0481 88.1631 ;
			 LAYER V2 ;
			RECT 0.0215 88.1376 0.0364 88.1502 ;
		END

		ANTENNAGATEAREA 0.00027817 ;
		ANTENNADIFFAREA 0.00194719 ;
		ANTENNAPARTIALMETALAREA 0.00195671 ;
	END TD[62]

	PIN TD[63]
		USE SIGNAL ;
		DIRECTION INPUT ;
		SHAPE ABUTMENT ;
		PORT
			 LAYER M2 ;
			RECT 0.0098 89.4055 0.0481 89.4431 ;
			 LAYER M3 ;
			RECT 0.0098 89.3427 0.0481 89.4431 ;
			 LAYER V2 ;
			RECT 0.0215 89.4176 0.0364 89.4302 ;
		END

		ANTENNAGATEAREA 0.00027817 ;
		ANTENNADIFFAREA 0.00194719 ;
		ANTENNAPARTIALMETALAREA 0.00195671 ;
	END TD[63]

	PIN TD[64]
		USE SIGNAL ;
		DIRECTION INPUT ;
		SHAPE ABUTMENT ;
		PORT
			 LAYER M2 ;
			RECT 0.0098 90.6855 0.0481 90.7231 ;
			 LAYER M3 ;
			RECT 0.0098 90.6227 0.0481 90.7231 ;
			 LAYER V2 ;
			RECT 0.0215 90.6976 0.0364 90.7102 ;
		END

		ANTENNAGATEAREA 0.00027817 ;
		ANTENNADIFFAREA 0.00194719 ;
		ANTENNAPARTIALMETALAREA 0.00195671 ;
	END TD[64]

	PIN TD[65]
		USE SIGNAL ;
		DIRECTION INPUT ;
		SHAPE ABUTMENT ;
		PORT
			 LAYER M2 ;
			RECT 0.0098 91.9655 0.0481 92.0031 ;
			 LAYER M3 ;
			RECT 0.0098 91.9027 0.0481 92.0031 ;
			 LAYER V2 ;
			RECT 0.0215 91.9776 0.0364 91.9902 ;
		END

		ANTENNAGATEAREA 0.00027817 ;
		ANTENNADIFFAREA 0.00194719 ;
		ANTENNAPARTIALMETALAREA 0.00195671 ;
	END TD[65]

	PIN TD[66]
		USE SIGNAL ;
		DIRECTION INPUT ;
		SHAPE ABUTMENT ;
		PORT
			 LAYER M2 ;
			RECT 0.0098 93.2455 0.0481 93.2831 ;
			 LAYER M3 ;
			RECT 0.0098 93.1827 0.0481 93.2831 ;
			 LAYER V2 ;
			RECT 0.0215 93.2576 0.0364 93.2702 ;
		END

		ANTENNAGATEAREA 0.00027817 ;
		ANTENNADIFFAREA 0.00194719 ;
		ANTENNAPARTIALMETALAREA 0.00195671 ;
	END TD[66]

	PIN TD[67]
		USE SIGNAL ;
		DIRECTION INPUT ;
		SHAPE ABUTMENT ;
		PORT
			 LAYER M2 ;
			RECT 0.0098 94.5255 0.0481 94.5631 ;
			 LAYER M3 ;
			RECT 0.0098 94.4627 0.0481 94.5631 ;
			 LAYER V2 ;
			RECT 0.0215 94.5376 0.0364 94.5502 ;
		END

		ANTENNAGATEAREA 0.00027817 ;
		ANTENNADIFFAREA 0.00194719 ;
		ANTENNAPARTIALMETALAREA 0.00195671 ;
	END TD[67]

	PIN TD[68]
		USE SIGNAL ;
		DIRECTION INPUT ;
		SHAPE ABUTMENT ;
		PORT
			 LAYER M2 ;
			RECT 0.0098 95.8055 0.0481 95.8431 ;
			 LAYER M3 ;
			RECT 0.0098 95.7427 0.0481 95.8431 ;
			 LAYER V2 ;
			RECT 0.0215 95.8176 0.0364 95.8302 ;
		END

		ANTENNAGATEAREA 0.00027817 ;
		ANTENNADIFFAREA 0.00194719 ;
		ANTENNAPARTIALMETALAREA 0.00195671 ;
	END TD[68]

	PIN TD[69]
		USE SIGNAL ;
		DIRECTION INPUT ;
		SHAPE ABUTMENT ;
		PORT
			 LAYER M2 ;
			RECT 0.0098 97.0855 0.0481 97.1231 ;
			 LAYER M3 ;
			RECT 0.0098 97.0227 0.0481 97.1231 ;
			 LAYER V2 ;
			RECT 0.0215 97.0976 0.0364 97.1102 ;
		END

		ANTENNAGATEAREA 0.00027817 ;
		ANTENNADIFFAREA 0.00194719 ;
		ANTENNAPARTIALMETALAREA 0.00195671 ;
	END TD[69]

	PIN TD[6]
		USE SIGNAL ;
		DIRECTION INPUT ;
		SHAPE ABUTMENT ;
		PORT
			 LAYER M2 ;
			RECT 0.0098 8.6463 0.0481 8.6839 ;
			 LAYER M3 ;
			RECT 0.0098 8.6463 0.0481 8.7467 ;
			 LAYER V2 ;
			RECT 0.0215 8.6592 0.0364 8.6718 ;
		END

		ANTENNAGATEAREA 0.00027817 ;
		ANTENNADIFFAREA 0.00194719 ;
		ANTENNAPARTIALMETALAREA 0.00195671 ;
	END TD[6]

	PIN TD[70]
		USE SIGNAL ;
		DIRECTION INPUT ;
		SHAPE ABUTMENT ;
		PORT
			 LAYER M2 ;
			RECT 0.0098 98.3655 0.0481 98.4031 ;
			 LAYER M3 ;
			RECT 0.0098 98.3027 0.0481 98.4031 ;
			 LAYER V2 ;
			RECT 0.0215 98.3776 0.0364 98.3902 ;
		END

		ANTENNAGATEAREA 0.00027817 ;
		ANTENNADIFFAREA 0.00194719 ;
		ANTENNAPARTIALMETALAREA 0.00195671 ;
	END TD[70]

	PIN TD[71]
		USE SIGNAL ;
		DIRECTION INPUT ;
		SHAPE ABUTMENT ;
		PORT
			 LAYER M2 ;
			RECT 0.0098 99.6455 0.0481 99.6831 ;
			 LAYER M3 ;
			RECT 0.0098 99.5827 0.0481 99.6831 ;
			 LAYER V2 ;
			RECT 0.0215 99.6576 0.0364 99.6702 ;
		END

		ANTENNAGATEAREA 0.00027817 ;
		ANTENNADIFFAREA 0.00194719 ;
		ANTENNAPARTIALMETALAREA 0.00195671 ;
	END TD[71]

	PIN TD[72]
		USE SIGNAL ;
		DIRECTION INPUT ;
		SHAPE ABUTMENT ;
		PORT
			 LAYER M2 ;
			RECT 0.0098 108.6243 0.0481 108.662 ;
			 LAYER M3 ;
			RECT 0.0098 108.5616 0.0481 108.662 ;
			 LAYER V2 ;
			RECT 0.0215 108.6365 0.0364 108.649 ;
		END

		ANTENNAGATEAREA 0.00027817 ;
		ANTENNADIFFAREA 0.00194719 ;
		ANTENNAPARTIALMETALAREA 0.00195671 ;
	END TD[72]

	PIN TD[73]
		USE SIGNAL ;
		DIRECTION INPUT ;
		SHAPE ABUTMENT ;
		PORT
			 LAYER M2 ;
			RECT 0.0098 109.9043 0.0481 109.942 ;
			 LAYER M3 ;
			RECT 0.0098 109.8416 0.0481 109.942 ;
			 LAYER V2 ;
			RECT 0.0215 109.9165 0.0364 109.929 ;
		END

		ANTENNAGATEAREA 0.00027817 ;
		ANTENNADIFFAREA 0.00194719 ;
		ANTENNAPARTIALMETALAREA 0.00195671 ;
	END TD[73]

	PIN TD[74]
		USE SIGNAL ;
		DIRECTION INPUT ;
		SHAPE ABUTMENT ;
		PORT
			 LAYER M2 ;
			RECT 0.0098 111.1843 0.0481 111.222 ;
			 LAYER M3 ;
			RECT 0.0098 111.1216 0.0481 111.222 ;
			 LAYER V2 ;
			RECT 0.0215 111.1965 0.0364 111.209 ;
		END

		ANTENNAGATEAREA 0.00027817 ;
		ANTENNADIFFAREA 0.00194719 ;
		ANTENNAPARTIALMETALAREA 0.00195671 ;
	END TD[74]

	PIN TD[75]
		USE SIGNAL ;
		DIRECTION INPUT ;
		SHAPE ABUTMENT ;
		PORT
			 LAYER M2 ;
			RECT 0.0098 112.4643 0.0481 112.502 ;
			 LAYER M3 ;
			RECT 0.0098 112.4016 0.0481 112.502 ;
			 LAYER V2 ;
			RECT 0.0215 112.4765 0.0364 112.489 ;
		END

		ANTENNAGATEAREA 0.00027817 ;
		ANTENNADIFFAREA 0.00194719 ;
		ANTENNAPARTIALMETALAREA 0.00195671 ;
	END TD[75]

	PIN TD[76]
		USE SIGNAL ;
		DIRECTION INPUT ;
		SHAPE ABUTMENT ;
		PORT
			 LAYER M2 ;
			RECT 0.0098 113.7443 0.0481 113.782 ;
			 LAYER M3 ;
			RECT 0.0098 113.6816 0.0481 113.782 ;
			 LAYER V2 ;
			RECT 0.0215 113.7565 0.0364 113.769 ;
		END

		ANTENNAGATEAREA 0.00027817 ;
		ANTENNADIFFAREA 0.00194719 ;
		ANTENNAPARTIALMETALAREA 0.00195671 ;
	END TD[76]

	PIN TD[77]
		USE SIGNAL ;
		DIRECTION INPUT ;
		SHAPE ABUTMENT ;
		PORT
			 LAYER M2 ;
			RECT 0.0098 115.0243 0.0481 115.062 ;
			 LAYER M3 ;
			RECT 0.0098 114.9616 0.0481 115.062 ;
			 LAYER V2 ;
			RECT 0.0215 115.0365 0.0364 115.049 ;
		END

		ANTENNAGATEAREA 0.00027817 ;
		ANTENNADIFFAREA 0.00194719 ;
		ANTENNAPARTIALMETALAREA 0.00195671 ;
	END TD[77]

	PIN TD[78]
		USE SIGNAL ;
		DIRECTION INPUT ;
		SHAPE ABUTMENT ;
		PORT
			 LAYER M2 ;
			RECT 0.0098 116.3043 0.0481 116.342 ;
			 LAYER M3 ;
			RECT 0.0098 116.2416 0.0481 116.342 ;
			 LAYER V2 ;
			RECT 0.0215 116.3165 0.0364 116.329 ;
		END

		ANTENNAGATEAREA 0.00027817 ;
		ANTENNADIFFAREA 0.00194719 ;
		ANTENNAPARTIALMETALAREA 0.00195671 ;
	END TD[78]

	PIN TD[79]
		USE SIGNAL ;
		DIRECTION INPUT ;
		SHAPE ABUTMENT ;
		PORT
			 LAYER M2 ;
			RECT 0.0098 117.5843 0.0481 117.622 ;
			 LAYER M3 ;
			RECT 0.0098 117.5216 0.0481 117.622 ;
			 LAYER V2 ;
			RECT 0.0215 117.5965 0.0364 117.609 ;
		END

		ANTENNAGATEAREA 0.00027817 ;
		ANTENNADIFFAREA 0.00194719 ;
		ANTENNAPARTIALMETALAREA 0.00195671 ;
	END TD[79]

	PIN TD[7]
		USE SIGNAL ;
		DIRECTION INPUT ;
		SHAPE ABUTMENT ;
		PORT
			 LAYER M2 ;
			RECT 0.0098 9.9263 0.0481 9.9639 ;
			 LAYER M3 ;
			RECT 0.0098 9.9263 0.0481 10.0267 ;
			 LAYER V2 ;
			RECT 0.0215 9.9392 0.0364 9.9518 ;
		END

		ANTENNAGATEAREA 0.00027817 ;
		ANTENNADIFFAREA 0.00194719 ;
		ANTENNAPARTIALMETALAREA 0.00195671 ;
	END TD[7]

	PIN TD[80]
		USE SIGNAL ;
		DIRECTION INPUT ;
		SHAPE ABUTMENT ;
		PORT
			 LAYER M2 ;
			RECT 0.0098 118.8643 0.0481 118.902 ;
			 LAYER M3 ;
			RECT 0.0098 118.8016 0.0481 118.902 ;
			 LAYER V2 ;
			RECT 0.0215 118.8765 0.0364 118.889 ;
		END

		ANTENNAGATEAREA 0.00027817 ;
		ANTENNADIFFAREA 0.00194719 ;
		ANTENNAPARTIALMETALAREA 0.00195671 ;
	END TD[80]

	PIN TD[81]
		USE SIGNAL ;
		DIRECTION INPUT ;
		SHAPE ABUTMENT ;
		PORT
			 LAYER M2 ;
			RECT 0.0098 120.1443 0.0481 120.182 ;
			 LAYER M3 ;
			RECT 0.0098 120.0816 0.0481 120.182 ;
			 LAYER V2 ;
			RECT 0.0215 120.1565 0.0364 120.169 ;
		END

		ANTENNAGATEAREA 0.00027817 ;
		ANTENNADIFFAREA 0.00194719 ;
		ANTENNAPARTIALMETALAREA 0.00195671 ;
	END TD[81]

	PIN TD[82]
		USE SIGNAL ;
		DIRECTION INPUT ;
		SHAPE ABUTMENT ;
		PORT
			 LAYER M2 ;
			RECT 0.0098 121.4243 0.0481 121.462 ;
			 LAYER M3 ;
			RECT 0.0098 121.3616 0.0481 121.462 ;
			 LAYER V2 ;
			RECT 0.0215 121.4365 0.0364 121.449 ;
		END

		ANTENNAGATEAREA 0.00027817 ;
		ANTENNADIFFAREA 0.00194719 ;
		ANTENNAPARTIALMETALAREA 0.00195671 ;
	END TD[82]

	PIN TD[83]
		USE SIGNAL ;
		DIRECTION INPUT ;
		SHAPE ABUTMENT ;
		PORT
			 LAYER M2 ;
			RECT 0.0098 122.7043 0.0481 122.742 ;
			 LAYER M3 ;
			RECT 0.0098 122.6416 0.0481 122.742 ;
			 LAYER V2 ;
			RECT 0.0215 122.7165 0.0364 122.729 ;
		END

		ANTENNAGATEAREA 0.00027817 ;
		ANTENNADIFFAREA 0.00194719 ;
		ANTENNAPARTIALMETALAREA 0.00195671 ;
	END TD[83]

	PIN TD[84]
		USE SIGNAL ;
		DIRECTION INPUT ;
		SHAPE ABUTMENT ;
		PORT
			 LAYER M2 ;
			RECT 0.0098 123.9843 0.0481 124.022 ;
			 LAYER M3 ;
			RECT 0.0098 123.9216 0.0481 124.022 ;
			 LAYER V2 ;
			RECT 0.0215 123.9965 0.0364 124.009 ;
		END

		ANTENNAGATEAREA 0.00027817 ;
		ANTENNADIFFAREA 0.00194719 ;
		ANTENNAPARTIALMETALAREA 0.00195671 ;
	END TD[84]

	PIN TD[85]
		USE SIGNAL ;
		DIRECTION INPUT ;
		SHAPE ABUTMENT ;
		PORT
			 LAYER M2 ;
			RECT 0.0098 125.2643 0.0481 125.302 ;
			 LAYER M3 ;
			RECT 0.0098 125.2016 0.0481 125.302 ;
			 LAYER V2 ;
			RECT 0.0215 125.2765 0.0364 125.289 ;
		END

		ANTENNAGATEAREA 0.00027817 ;
		ANTENNADIFFAREA 0.00194719 ;
		ANTENNAPARTIALMETALAREA 0.00195671 ;
	END TD[85]

	PIN TD[86]
		USE SIGNAL ;
		DIRECTION INPUT ;
		SHAPE ABUTMENT ;
		PORT
			 LAYER M2 ;
			RECT 0.0098 126.5443 0.0481 126.582 ;
			 LAYER M3 ;
			RECT 0.0098 126.4816 0.0481 126.582 ;
			 LAYER V2 ;
			RECT 0.0215 126.5565 0.0364 126.569 ;
		END

		ANTENNAGATEAREA 0.00027817 ;
		ANTENNADIFFAREA 0.00194719 ;
		ANTENNAPARTIALMETALAREA 0.00195671 ;
	END TD[86]

	PIN TD[87]
		USE SIGNAL ;
		DIRECTION INPUT ;
		SHAPE ABUTMENT ;
		PORT
			 LAYER M2 ;
			RECT 0.0098 127.8243 0.0481 127.862 ;
			 LAYER M3 ;
			RECT 0.0098 127.7616 0.0481 127.862 ;
			 LAYER V2 ;
			RECT 0.0215 127.8365 0.0364 127.849 ;
		END

		ANTENNAGATEAREA 0.00027817 ;
		ANTENNADIFFAREA 0.00194719 ;
		ANTENNAPARTIALMETALAREA 0.00195671 ;
	END TD[87]

	PIN TD[88]
		USE SIGNAL ;
		DIRECTION INPUT ;
		SHAPE ABUTMENT ;
		PORT
			 LAYER M2 ;
			RECT 0.0098 129.1043 0.0481 129.142 ;
			 LAYER M3 ;
			RECT 0.0098 129.0416 0.0481 129.142 ;
			 LAYER V2 ;
			RECT 0.0215 129.1165 0.0364 129.129 ;
		END

		ANTENNAGATEAREA 0.00027817 ;
		ANTENNADIFFAREA 0.00194719 ;
		ANTENNAPARTIALMETALAREA 0.00195671 ;
	END TD[88]

	PIN TD[89]
		USE SIGNAL ;
		DIRECTION INPUT ;
		SHAPE ABUTMENT ;
		PORT
			 LAYER M2 ;
			RECT 0.0098 130.3843 0.0481 130.422 ;
			 LAYER M3 ;
			RECT 0.0098 130.3216 0.0481 130.422 ;
			 LAYER V2 ;
			RECT 0.0215 130.3965 0.0364 130.409 ;
		END

		ANTENNAGATEAREA 0.00027817 ;
		ANTENNADIFFAREA 0.00194719 ;
		ANTENNAPARTIALMETALAREA 0.00195671 ;
	END TD[89]

	PIN TD[8]
		USE SIGNAL ;
		DIRECTION INPUT ;
		SHAPE ABUTMENT ;
		PORT
			 LAYER M2 ;
			RECT 0.0098 11.2063 0.0481 11.2439 ;
			 LAYER M3 ;
			RECT 0.0098 11.2063 0.0481 11.3067 ;
			 LAYER V2 ;
			RECT 0.0215 11.2192 0.0364 11.2318 ;
		END

		ANTENNAGATEAREA 0.00027817 ;
		ANTENNADIFFAREA 0.00194719 ;
		ANTENNAPARTIALMETALAREA 0.00195671 ;
	END TD[8]

	PIN TD[90]
		USE SIGNAL ;
		DIRECTION INPUT ;
		SHAPE ABUTMENT ;
		PORT
			 LAYER M2 ;
			RECT 0.0098 131.6643 0.0481 131.702 ;
			 LAYER M3 ;
			RECT 0.0098 131.6016 0.0481 131.702 ;
			 LAYER V2 ;
			RECT 0.0215 131.6765 0.0364 131.689 ;
		END

		ANTENNAGATEAREA 0.00027817 ;
		ANTENNADIFFAREA 0.00194719 ;
		ANTENNAPARTIALMETALAREA 0.00195671 ;
	END TD[90]

	PIN TD[91]
		USE SIGNAL ;
		DIRECTION INPUT ;
		SHAPE ABUTMENT ;
		PORT
			 LAYER M2 ;
			RECT 0.0098 132.9443 0.0481 132.982 ;
			 LAYER M3 ;
			RECT 0.0098 132.8816 0.0481 132.982 ;
			 LAYER V2 ;
			RECT 0.0215 132.9565 0.0364 132.969 ;
		END

		ANTENNAGATEAREA 0.00027817 ;
		ANTENNADIFFAREA 0.00194719 ;
		ANTENNAPARTIALMETALAREA 0.00195671 ;
	END TD[91]

	PIN TD[92]
		USE SIGNAL ;
		DIRECTION INPUT ;
		SHAPE ABUTMENT ;
		PORT
			 LAYER M2 ;
			RECT 0.0098 134.2243 0.0481 134.262 ;
			 LAYER M3 ;
			RECT 0.0098 134.1616 0.0481 134.262 ;
			 LAYER V2 ;
			RECT 0.0215 134.2365 0.0364 134.249 ;
		END

		ANTENNAGATEAREA 0.00027817 ;
		ANTENNADIFFAREA 0.00194719 ;
		ANTENNAPARTIALMETALAREA 0.00195671 ;
	END TD[92]

	PIN TD[93]
		USE SIGNAL ;
		DIRECTION INPUT ;
		SHAPE ABUTMENT ;
		PORT
			 LAYER M2 ;
			RECT 0.0098 135.5043 0.0481 135.542 ;
			 LAYER M3 ;
			RECT 0.0098 135.4416 0.0481 135.542 ;
			 LAYER V2 ;
			RECT 0.0215 135.5165 0.0364 135.529 ;
		END

		ANTENNAGATEAREA 0.00027817 ;
		ANTENNADIFFAREA 0.00194719 ;
		ANTENNAPARTIALMETALAREA 0.00195671 ;
	END TD[93]

	PIN TD[94]
		USE SIGNAL ;
		DIRECTION INPUT ;
		SHAPE ABUTMENT ;
		PORT
			 LAYER M2 ;
			RECT 0.0098 136.7843 0.0481 136.822 ;
			 LAYER M3 ;
			RECT 0.0098 136.7216 0.0481 136.822 ;
			 LAYER V2 ;
			RECT 0.0215 136.7965 0.0364 136.809 ;
		END

		ANTENNAGATEAREA 0.00027817 ;
		ANTENNADIFFAREA 0.00194719 ;
		ANTENNAPARTIALMETALAREA 0.00195671 ;
	END TD[94]

	PIN TD[95]
		USE SIGNAL ;
		DIRECTION INPUT ;
		SHAPE ABUTMENT ;
		PORT
			 LAYER M2 ;
			RECT 0.0098 138.0643 0.0481 138.102 ;
			 LAYER M3 ;
			RECT 0.0098 138.0016 0.0481 138.102 ;
			 LAYER V2 ;
			RECT 0.0215 138.0765 0.0364 138.089 ;
		END

		ANTENNAGATEAREA 0.00027817 ;
		ANTENNADIFFAREA 0.00194719 ;
		ANTENNAPARTIALMETALAREA 0.00195671 ;
	END TD[95]

	PIN TD[9]
		USE SIGNAL ;
		DIRECTION INPUT ;
		SHAPE ABUTMENT ;
		PORT
			 LAYER M2 ;
			RECT 0.0098 12.4863 0.0481 12.5239 ;
			 LAYER M3 ;
			RECT 0.0098 12.4863 0.0481 12.5867 ;
			 LAYER V2 ;
			RECT 0.0215 12.4992 0.0364 12.5118 ;
		END

		ANTENNAGATEAREA 0.00027817 ;
		ANTENNADIFFAREA 0.00194719 ;
		ANTENNAPARTIALMETALAREA 0.00195671 ;
	END TD[9]

	PIN TEN
		USE SIGNAL ;
		DIRECTION INPUT ;
		SHAPE ABUTMENT ;
		PORT
			 LAYER M2 ;
			RECT 0.0714 82.378 0.1097 82.4157 ;
			 LAYER M3 ;
			RECT 0.0714 82.3153 0.1097 82.4157 ;
			 LAYER V2 ;
			RECT 0.0831 82.391 0.098 82.4035 ;
		END

		ANTENNAGATEAREA 0.00027817 ;
		ANTENNADIFFAREA 0.00194719 ;
		ANTENNAPARTIALMETALAREA 0.00195671 ;
	END TEN

	PIN TGWEN
		USE SIGNAL ;
		DIRECTION INPUT ;
		SHAPE ABUTMENT ;
		PORT
			 LAYER M2 ;
			RECT 0.0714 75.978 0.1097 76.0157 ;
			 LAYER M3 ;
			RECT 0.0714 75.9153 0.1097 76.0157 ;
			 LAYER V2 ;
			RECT 0.0831 75.991 0.098 76.0035 ;
		END

		ANTENNAGATEAREA 0.00027817 ;
		ANTENNADIFFAREA 0.00194719 ;
		ANTENNAPARTIALMETALAREA 0.00195671 ;
	END TGWEN

	PIN TWEN[0]
		USE SIGNAL ;
		DIRECTION INPUT ;
		SHAPE ABUTMENT ;
		PORT
			 LAYER M2 ;
			RECT 0.0714 1.4306 0.1097 1.4682 ;
			 LAYER M3 ;
			RECT 0.0714 1.3678 0.1097 1.4682 ;
			 LAYER V2 ;
			RECT 0.0831 1.4435 0.098 1.4561 ;
		END

		ANTENNAGATEAREA 0.00027817 ;
		ANTENNADIFFAREA 0.00194719 ;
		ANTENNAPARTIALMETALAREA 0.00195671 ;
	END TWEN[0]

	PIN TWEN[10]
		USE SIGNAL ;
		DIRECTION INPUT ;
		SHAPE ABUTMENT ;
		PORT
			 LAYER M2 ;
			RECT 0.0714 14.2306 0.1097 14.2682 ;
			 LAYER M3 ;
			RECT 0.0714 14.1678 0.1097 14.2682 ;
			 LAYER V2 ;
			RECT 0.0831 14.2435 0.098 14.2561 ;
		END

		ANTENNAGATEAREA 0.00027817 ;
		ANTENNADIFFAREA 0.00194719 ;
		ANTENNAPARTIALMETALAREA 0.00195671 ;
	END TWEN[10]

	PIN TWEN[11]
		USE SIGNAL ;
		DIRECTION INPUT ;
		SHAPE ABUTMENT ;
		PORT
			 LAYER M2 ;
			RECT 0.0714 15.5106 0.1097 15.5482 ;
			 LAYER M3 ;
			RECT 0.0714 15.4478 0.1097 15.5482 ;
			 LAYER V2 ;
			RECT 0.0831 15.5235 0.098 15.5361 ;
		END

		ANTENNAGATEAREA 0.00027817 ;
		ANTENNADIFFAREA 0.00194719 ;
		ANTENNAPARTIALMETALAREA 0.00195671 ;
	END TWEN[11]

	PIN TWEN[12]
		USE SIGNAL ;
		DIRECTION INPUT ;
		SHAPE ABUTMENT ;
		PORT
			 LAYER M2 ;
			RECT 0.0714 16.7906 0.1097 16.8282 ;
			 LAYER M3 ;
			RECT 0.0714 16.7278 0.1097 16.8282 ;
			 LAYER V2 ;
			RECT 0.0831 16.8035 0.098 16.8161 ;
		END

		ANTENNAGATEAREA 0.00027817 ;
		ANTENNADIFFAREA 0.00194719 ;
		ANTENNAPARTIALMETALAREA 0.00195671 ;
	END TWEN[12]

	PIN TWEN[13]
		USE SIGNAL ;
		DIRECTION INPUT ;
		SHAPE ABUTMENT ;
		PORT
			 LAYER M2 ;
			RECT 0.0714 18.0706 0.1097 18.1082 ;
			 LAYER M3 ;
			RECT 0.0714 18.0078 0.1097 18.1082 ;
			 LAYER V2 ;
			RECT 0.0831 18.0835 0.098 18.0961 ;
		END

		ANTENNAGATEAREA 0.00027817 ;
		ANTENNADIFFAREA 0.00194719 ;
		ANTENNAPARTIALMETALAREA 0.00195671 ;
	END TWEN[13]

	PIN TWEN[14]
		USE SIGNAL ;
		DIRECTION INPUT ;
		SHAPE ABUTMENT ;
		PORT
			 LAYER M2 ;
			RECT 0.0714 19.3506 0.1097 19.3882 ;
			 LAYER M3 ;
			RECT 0.0714 19.2878 0.1097 19.3882 ;
			 LAYER V2 ;
			RECT 0.0831 19.3635 0.098 19.3761 ;
		END

		ANTENNAGATEAREA 0.00027817 ;
		ANTENNADIFFAREA 0.00194719 ;
		ANTENNAPARTIALMETALAREA 0.00195671 ;
	END TWEN[14]

	PIN TWEN[15]
		USE SIGNAL ;
		DIRECTION INPUT ;
		SHAPE ABUTMENT ;
		PORT
			 LAYER M2 ;
			RECT 0.0714 20.6306 0.1097 20.6682 ;
			 LAYER M3 ;
			RECT 0.0714 20.5678 0.1097 20.6682 ;
			 LAYER V2 ;
			RECT 0.0831 20.6435 0.098 20.6561 ;
		END

		ANTENNAGATEAREA 0.00027817 ;
		ANTENNADIFFAREA 0.00194719 ;
		ANTENNAPARTIALMETALAREA 0.00195671 ;
	END TWEN[15]

	PIN TWEN[16]
		USE SIGNAL ;
		DIRECTION INPUT ;
		SHAPE ABUTMENT ;
		PORT
			 LAYER M2 ;
			RECT 0.0714 21.9106 0.1097 21.9482 ;
			 LAYER M3 ;
			RECT 0.0714 21.8478 0.1097 21.9482 ;
			 LAYER V2 ;
			RECT 0.0831 21.9235 0.098 21.9361 ;
		END

		ANTENNAGATEAREA 0.00027817 ;
		ANTENNADIFFAREA 0.00194719 ;
		ANTENNAPARTIALMETALAREA 0.00195671 ;
	END TWEN[16]

	PIN TWEN[17]
		USE SIGNAL ;
		DIRECTION INPUT ;
		SHAPE ABUTMENT ;
		PORT
			 LAYER M2 ;
			RECT 0.0714 23.1906 0.1097 23.2282 ;
			 LAYER M3 ;
			RECT 0.0714 23.1278 0.1097 23.2282 ;
			 LAYER V2 ;
			RECT 0.0831 23.2035 0.098 23.2161 ;
		END

		ANTENNAGATEAREA 0.00027817 ;
		ANTENNADIFFAREA 0.00194719 ;
		ANTENNAPARTIALMETALAREA 0.00195671 ;
	END TWEN[17]

	PIN TWEN[18]
		USE SIGNAL ;
		DIRECTION INPUT ;
		SHAPE ABUTMENT ;
		PORT
			 LAYER M2 ;
			RECT 0.0714 24.4706 0.1097 24.5082 ;
			 LAYER M3 ;
			RECT 0.0714 24.4078 0.1097 24.5082 ;
			 LAYER V2 ;
			RECT 0.0831 24.4835 0.098 24.4961 ;
		END

		ANTENNAGATEAREA 0.00027817 ;
		ANTENNADIFFAREA 0.00194719 ;
		ANTENNAPARTIALMETALAREA 0.00195671 ;
	END TWEN[18]

	PIN TWEN[19]
		USE SIGNAL ;
		DIRECTION INPUT ;
		SHAPE ABUTMENT ;
		PORT
			 LAYER M2 ;
			RECT 0.0714 25.7506 0.1097 25.7882 ;
			 LAYER M3 ;
			RECT 0.0714 25.6878 0.1097 25.7882 ;
			 LAYER V2 ;
			RECT 0.0831 25.7635 0.098 25.7761 ;
		END

		ANTENNAGATEAREA 0.00027817 ;
		ANTENNADIFFAREA 0.00194719 ;
		ANTENNAPARTIALMETALAREA 0.00195671 ;
	END TWEN[19]

	PIN TWEN[1]
		USE SIGNAL ;
		DIRECTION INPUT ;
		SHAPE ABUTMENT ;
		PORT
			 LAYER M2 ;
			RECT 0.0714 2.7106 0.1097 2.7482 ;
			 LAYER M3 ;
			RECT 0.0714 2.6478 0.1097 2.7482 ;
			 LAYER V2 ;
			RECT 0.0831 2.7235 0.098 2.7361 ;
		END

		ANTENNAGATEAREA 0.00027817 ;
		ANTENNADIFFAREA 0.00194719 ;
		ANTENNAPARTIALMETALAREA 0.00195671 ;
	END TWEN[1]

	PIN TWEN[20]
		USE SIGNAL ;
		DIRECTION INPUT ;
		SHAPE ABUTMENT ;
		PORT
			 LAYER M2 ;
			RECT 0.0714 27.0306 0.1097 27.0682 ;
			 LAYER M3 ;
			RECT 0.0714 26.9678 0.1097 27.0682 ;
			 LAYER V2 ;
			RECT 0.0831 27.0435 0.098 27.0561 ;
		END

		ANTENNAGATEAREA 0.00027817 ;
		ANTENNADIFFAREA 0.00194719 ;
		ANTENNAPARTIALMETALAREA 0.00195671 ;
	END TWEN[20]

	PIN TWEN[21]
		USE SIGNAL ;
		DIRECTION INPUT ;
		SHAPE ABUTMENT ;
		PORT
			 LAYER M2 ;
			RECT 0.0714 28.3106 0.1097 28.3482 ;
			 LAYER M3 ;
			RECT 0.0714 28.2478 0.1097 28.3482 ;
			 LAYER V2 ;
			RECT 0.0831 28.3235 0.098 28.3361 ;
		END

		ANTENNAGATEAREA 0.00027817 ;
		ANTENNADIFFAREA 0.00194719 ;
		ANTENNAPARTIALMETALAREA 0.00195671 ;
	END TWEN[21]

	PIN TWEN[22]
		USE SIGNAL ;
		DIRECTION INPUT ;
		SHAPE ABUTMENT ;
		PORT
			 LAYER M2 ;
			RECT 0.0714 29.5906 0.1097 29.6282 ;
			 LAYER M3 ;
			RECT 0.0714 29.5278 0.1097 29.6282 ;
			 LAYER V2 ;
			RECT 0.0831 29.6035 0.098 29.6161 ;
		END

		ANTENNAGATEAREA 0.00027817 ;
		ANTENNADIFFAREA 0.00194719 ;
		ANTENNAPARTIALMETALAREA 0.00195671 ;
	END TWEN[22]

	PIN TWEN[23]
		USE SIGNAL ;
		DIRECTION INPUT ;
		SHAPE ABUTMENT ;
		PORT
			 LAYER M2 ;
			RECT 0.0714 30.8706 0.1097 30.9082 ;
			 LAYER M3 ;
			RECT 0.0714 30.8078 0.1097 30.9082 ;
			 LAYER V2 ;
			RECT 0.0831 30.8835 0.098 30.8961 ;
		END

		ANTENNAGATEAREA 0.00027817 ;
		ANTENNADIFFAREA 0.00194719 ;
		ANTENNAPARTIALMETALAREA 0.00195671 ;
	END TWEN[23]

	PIN TWEN[24]
		USE SIGNAL ;
		DIRECTION INPUT ;
		SHAPE ABUTMENT ;
		PORT
			 LAYER M2 ;
			RECT 0.0714 39.8494 0.1097 39.8871 ;
			 LAYER M3 ;
			RECT 0.0714 39.7867 0.1097 39.8871 ;
			 LAYER V2 ;
			RECT 0.0831 39.8624 0.098 39.8749 ;
		END

		ANTENNAGATEAREA 0.00027817 ;
		ANTENNADIFFAREA 0.00194719 ;
		ANTENNAPARTIALMETALAREA 0.00195671 ;
	END TWEN[24]

	PIN TWEN[25]
		USE SIGNAL ;
		DIRECTION INPUT ;
		SHAPE ABUTMENT ;
		PORT
			 LAYER M2 ;
			RECT 0.0714 41.1294 0.1097 41.1671 ;
			 LAYER M3 ;
			RECT 0.0714 41.0667 0.1097 41.1671 ;
			 LAYER V2 ;
			RECT 0.0831 41.1424 0.098 41.1549 ;
		END

		ANTENNAGATEAREA 0.00027817 ;
		ANTENNADIFFAREA 0.00194719 ;
		ANTENNAPARTIALMETALAREA 0.00195671 ;
	END TWEN[25]

	PIN TWEN[26]
		USE SIGNAL ;
		DIRECTION INPUT ;
		SHAPE ABUTMENT ;
		PORT
			 LAYER M2 ;
			RECT 0.0714 42.4094 0.1097 42.4471 ;
			 LAYER M3 ;
			RECT 0.0714 42.3467 0.1097 42.4471 ;
			 LAYER V2 ;
			RECT 0.0831 42.4224 0.098 42.4349 ;
		END

		ANTENNAGATEAREA 0.00027817 ;
		ANTENNADIFFAREA 0.00194719 ;
		ANTENNAPARTIALMETALAREA 0.00195671 ;
	END TWEN[26]

	PIN TWEN[27]
		USE SIGNAL ;
		DIRECTION INPUT ;
		SHAPE ABUTMENT ;
		PORT
			 LAYER M2 ;
			RECT 0.0714 43.6894 0.1097 43.7271 ;
			 LAYER M3 ;
			RECT 0.0714 43.6267 0.1097 43.7271 ;
			 LAYER V2 ;
			RECT 0.0831 43.7024 0.098 43.7149 ;
		END

		ANTENNAGATEAREA 0.00027817 ;
		ANTENNADIFFAREA 0.00194719 ;
		ANTENNAPARTIALMETALAREA 0.00195671 ;
	END TWEN[27]

	PIN TWEN[28]
		USE SIGNAL ;
		DIRECTION INPUT ;
		SHAPE ABUTMENT ;
		PORT
			 LAYER M2 ;
			RECT 0.0714 44.9694 0.1097 45.0071 ;
			 LAYER M3 ;
			RECT 0.0714 44.9067 0.1097 45.0071 ;
			 LAYER V2 ;
			RECT 0.0831 44.9824 0.098 44.9949 ;
		END

		ANTENNAGATEAREA 0.00027817 ;
		ANTENNADIFFAREA 0.00194719 ;
		ANTENNAPARTIALMETALAREA 0.00195671 ;
	END TWEN[28]

	PIN TWEN[29]
		USE SIGNAL ;
		DIRECTION INPUT ;
		SHAPE ABUTMENT ;
		PORT
			 LAYER M2 ;
			RECT 0.0714 46.2494 0.1097 46.2871 ;
			 LAYER M3 ;
			RECT 0.0714 46.1867 0.1097 46.2871 ;
			 LAYER V2 ;
			RECT 0.0831 46.2624 0.098 46.2749 ;
		END

		ANTENNAGATEAREA 0.00027817 ;
		ANTENNADIFFAREA 0.00194719 ;
		ANTENNAPARTIALMETALAREA 0.00195671 ;
	END TWEN[29]

	PIN TWEN[2]
		USE SIGNAL ;
		DIRECTION INPUT ;
		SHAPE ABUTMENT ;
		PORT
			 LAYER M2 ;
			RECT 0.0714 3.9906 0.1097 4.0282 ;
			 LAYER M3 ;
			RECT 0.0714 3.9278 0.1097 4.0282 ;
			 LAYER V2 ;
			RECT 0.0831 4.0035 0.098 4.0161 ;
		END

		ANTENNAGATEAREA 0.00027817 ;
		ANTENNADIFFAREA 0.00194719 ;
		ANTENNAPARTIALMETALAREA 0.00195671 ;
	END TWEN[2]

	PIN TWEN[30]
		USE SIGNAL ;
		DIRECTION INPUT ;
		SHAPE ABUTMENT ;
		PORT
			 LAYER M2 ;
			RECT 0.0714 47.5294 0.1097 47.5671 ;
			 LAYER M3 ;
			RECT 0.0714 47.4667 0.1097 47.5671 ;
			 LAYER V2 ;
			RECT 0.0831 47.5424 0.098 47.5549 ;
		END

		ANTENNAGATEAREA 0.00027817 ;
		ANTENNADIFFAREA 0.00194719 ;
		ANTENNAPARTIALMETALAREA 0.00195671 ;
	END TWEN[30]

	PIN TWEN[31]
		USE SIGNAL ;
		DIRECTION INPUT ;
		SHAPE ABUTMENT ;
		PORT
			 LAYER M2 ;
			RECT 0.0714 48.8094 0.1097 48.8471 ;
			 LAYER M3 ;
			RECT 0.0714 48.7467 0.1097 48.8471 ;
			 LAYER V2 ;
			RECT 0.0831 48.8224 0.098 48.8349 ;
		END

		ANTENNAGATEAREA 0.00027817 ;
		ANTENNADIFFAREA 0.00194719 ;
		ANTENNAPARTIALMETALAREA 0.00195671 ;
	END TWEN[31]

	PIN TWEN[32]
		USE SIGNAL ;
		DIRECTION INPUT ;
		SHAPE ABUTMENT ;
		PORT
			 LAYER M2 ;
			RECT 0.0714 50.0894 0.1097 50.1271 ;
			 LAYER M3 ;
			RECT 0.0714 50.0267 0.1097 50.1271 ;
			 LAYER V2 ;
			RECT 0.0831 50.1024 0.098 50.1149 ;
		END

		ANTENNAGATEAREA 0.00027817 ;
		ANTENNADIFFAREA 0.00194719 ;
		ANTENNAPARTIALMETALAREA 0.00195671 ;
	END TWEN[32]

	PIN TWEN[33]
		USE SIGNAL ;
		DIRECTION INPUT ;
		SHAPE ABUTMENT ;
		PORT
			 LAYER M2 ;
			RECT 0.0714 51.3694 0.1097 51.4071 ;
			 LAYER M3 ;
			RECT 0.0714 51.3067 0.1097 51.4071 ;
			 LAYER V2 ;
			RECT 0.0831 51.3824 0.098 51.3949 ;
		END

		ANTENNAGATEAREA 0.00027817 ;
		ANTENNADIFFAREA 0.00194719 ;
		ANTENNAPARTIALMETALAREA 0.00195671 ;
	END TWEN[33]

	PIN TWEN[34]
		USE SIGNAL ;
		DIRECTION INPUT ;
		SHAPE ABUTMENT ;
		PORT
			 LAYER M2 ;
			RECT 0.0714 52.6494 0.1097 52.6871 ;
			 LAYER M3 ;
			RECT 0.0714 52.5867 0.1097 52.6871 ;
			 LAYER V2 ;
			RECT 0.0831 52.6624 0.098 52.6749 ;
		END

		ANTENNAGATEAREA 0.00027817 ;
		ANTENNADIFFAREA 0.00194719 ;
		ANTENNAPARTIALMETALAREA 0.00195671 ;
	END TWEN[34]

	PIN TWEN[35]
		USE SIGNAL ;
		DIRECTION INPUT ;
		SHAPE ABUTMENT ;
		PORT
			 LAYER M2 ;
			RECT 0.0714 53.9294 0.1097 53.9671 ;
			 LAYER M3 ;
			RECT 0.0714 53.8667 0.1097 53.9671 ;
			 LAYER V2 ;
			RECT 0.0831 53.9424 0.098 53.9549 ;
		END

		ANTENNAGATEAREA 0.00027817 ;
		ANTENNADIFFAREA 0.00194719 ;
		ANTENNAPARTIALMETALAREA 0.00195671 ;
	END TWEN[35]

	PIN TWEN[36]
		USE SIGNAL ;
		DIRECTION INPUT ;
		SHAPE ABUTMENT ;
		PORT
			 LAYER M2 ;
			RECT 0.0714 55.2094 0.1097 55.2471 ;
			 LAYER M3 ;
			RECT 0.0714 55.1467 0.1097 55.2471 ;
			 LAYER V2 ;
			RECT 0.0831 55.2224 0.098 55.2349 ;
		END

		ANTENNAGATEAREA 0.00027817 ;
		ANTENNADIFFAREA 0.00194719 ;
		ANTENNAPARTIALMETALAREA 0.00195671 ;
	END TWEN[36]

	PIN TWEN[37]
		USE SIGNAL ;
		DIRECTION INPUT ;
		SHAPE ABUTMENT ;
		PORT
			 LAYER M2 ;
			RECT 0.0714 56.4894 0.1097 56.5271 ;
			 LAYER M3 ;
			RECT 0.0714 56.4267 0.1097 56.5271 ;
			 LAYER V2 ;
			RECT 0.0831 56.5024 0.098 56.5149 ;
		END

		ANTENNAGATEAREA 0.00027817 ;
		ANTENNADIFFAREA 0.00194719 ;
		ANTENNAPARTIALMETALAREA 0.00195671 ;
	END TWEN[37]

	PIN TWEN[38]
		USE SIGNAL ;
		DIRECTION INPUT ;
		SHAPE ABUTMENT ;
		PORT
			 LAYER M2 ;
			RECT 0.0714 57.2549 0.1097 57.2925 ;
			 LAYER M3 ;
			RECT 0.0714 57.2549 0.1097 57.3553 ;
			 LAYER V2 ;
			RECT 0.0831 57.2671 0.098 57.2796 ;
		END

		ANTENNAGATEAREA 0.00027817 ;
		ANTENNADIFFAREA 0.00194719 ;
		ANTENNAPARTIALMETALAREA 0.00195671 ;
	END TWEN[38]

	PIN TWEN[39]
		USE SIGNAL ;
		DIRECTION INPUT ;
		SHAPE ABUTMENT ;
		PORT
			 LAYER M2 ;
			RECT 0.0714 58.5349 0.1097 58.5725 ;
			 LAYER M3 ;
			RECT 0.0714 58.5349 0.1097 58.6353 ;
			 LAYER V2 ;
			RECT 0.0831 58.5471 0.098 58.5596 ;
		END

		ANTENNAGATEAREA 0.00027817 ;
		ANTENNADIFFAREA 0.00194719 ;
		ANTENNAPARTIALMETALAREA 0.00195671 ;
	END TWEN[39]

	PIN TWEN[3]
		USE SIGNAL ;
		DIRECTION INPUT ;
		SHAPE ABUTMENT ;
		PORT
			 LAYER M2 ;
			RECT 0.0714 5.2706 0.1097 5.3082 ;
			 LAYER M3 ;
			RECT 0.0714 5.2078 0.1097 5.3082 ;
			 LAYER V2 ;
			RECT 0.0831 5.2835 0.098 5.2961 ;
		END

		ANTENNAGATEAREA 0.00027817 ;
		ANTENNADIFFAREA 0.00194719 ;
		ANTENNAPARTIALMETALAREA 0.00195671 ;
	END TWEN[3]

	PIN TWEN[40]
		USE SIGNAL ;
		DIRECTION INPUT ;
		SHAPE ABUTMENT ;
		PORT
			 LAYER M2 ;
			RECT 0.0714 59.6643 0.1097 59.702 ;
			 LAYER M3 ;
			RECT 0.0714 59.6643 0.1097 59.7647 ;
			 LAYER V2 ;
			RECT 0.0831 59.6765 0.098 59.689 ;
		END

		ANTENNAGATEAREA 0.00027817 ;
		ANTENNADIFFAREA 0.00194719 ;
		ANTENNAPARTIALMETALAREA 0.00195671 ;
	END TWEN[40]

	PIN TWEN[41]
		USE SIGNAL ;
		DIRECTION INPUT ;
		SHAPE ABUTMENT ;
		PORT
			 LAYER M2 ;
			RECT 0.0714 61.0949 0.1097 61.1325 ;
			 LAYER M3 ;
			RECT 0.0714 61.0949 0.1097 61.1953 ;
			 LAYER V2 ;
			RECT 0.0831 61.1071 0.098 61.1196 ;
		END

		ANTENNAGATEAREA 0.00027817 ;
		ANTENNADIFFAREA 0.00194719 ;
		ANTENNAPARTIALMETALAREA 0.00195671 ;
	END TWEN[41]

	PIN TWEN[42]
		USE SIGNAL ;
		DIRECTION INPUT ;
		SHAPE ABUTMENT ;
		PORT
			 LAYER M2 ;
			RECT 0.0714 62.3749 0.1097 62.4125 ;
			 LAYER M3 ;
			RECT 0.0714 62.3749 0.1097 62.4753 ;
			 LAYER V2 ;
			RECT 0.0831 62.3871 0.098 62.3996 ;
		END

		ANTENNAGATEAREA 0.00027817 ;
		ANTENNADIFFAREA 0.00194719 ;
		ANTENNAPARTIALMETALAREA 0.00195671 ;
	END TWEN[42]

	PIN TWEN[43]
		USE SIGNAL ;
		DIRECTION INPUT ;
		SHAPE ABUTMENT ;
		PORT
			 LAYER M2 ;
			RECT 0.0714 63.6549 0.1097 63.6925 ;
			 LAYER M3 ;
			RECT 0.0714 63.6549 0.1097 63.7553 ;
			 LAYER V2 ;
			RECT 0.0831 63.6671 0.098 63.6796 ;
		END

		ANTENNAGATEAREA 0.00027817 ;
		ANTENNADIFFAREA 0.00194719 ;
		ANTENNAPARTIALMETALAREA 0.00195671 ;
	END TWEN[43]

	PIN TWEN[44]
		USE SIGNAL ;
		DIRECTION INPUT ;
		SHAPE ABUTMENT ;
		PORT
			 LAYER M2 ;
			RECT 0.0714 64.9349 0.1097 64.9725 ;
			 LAYER M3 ;
			RECT 0.0714 64.9349 0.1097 65.0353 ;
			 LAYER V2 ;
			RECT 0.0831 64.9471 0.098 64.9596 ;
		END

		ANTENNAGATEAREA 0.00027817 ;
		ANTENNADIFFAREA 0.00194719 ;
		ANTENNAPARTIALMETALAREA 0.00195671 ;
	END TWEN[44]

	PIN TWEN[45]
		USE SIGNAL ;
		DIRECTION INPUT ;
		SHAPE ABUTMENT ;
		PORT
			 LAYER M2 ;
			RECT 0.0714 66.2149 0.1097 66.2525 ;
			 LAYER M3 ;
			RECT 0.0714 66.2149 0.1097 66.3153 ;
			 LAYER V2 ;
			RECT 0.0831 66.2271 0.098 66.2396 ;
		END

		ANTENNAGATEAREA 0.00027817 ;
		ANTENNADIFFAREA 0.00194719 ;
		ANTENNAPARTIALMETALAREA 0.00195671 ;
	END TWEN[45]

	PIN TWEN[46]
		USE SIGNAL ;
		DIRECTION INPUT ;
		SHAPE ABUTMENT ;
		PORT
			 LAYER M2 ;
			RECT 0.0714 67.4949 0.1097 67.5325 ;
			 LAYER M3 ;
			RECT 0.0714 67.4949 0.1097 67.5953 ;
			 LAYER V2 ;
			RECT 0.0831 67.5071 0.098 67.5196 ;
		END

		ANTENNAGATEAREA 0.00027817 ;
		ANTENNADIFFAREA 0.00194719 ;
		ANTENNAPARTIALMETALAREA 0.00195671 ;
	END TWEN[46]

	PIN TWEN[47]
		USE SIGNAL ;
		DIRECTION INPUT ;
		SHAPE ABUTMENT ;
		PORT
			 LAYER M2 ;
			RECT 0.0714 68.7749 0.1097 68.8125 ;
			 LAYER M3 ;
			RECT 0.0714 68.7749 0.1097 68.8753 ;
			 LAYER V2 ;
			RECT 0.0831 68.7871 0.098 68.7996 ;
		END

		ANTENNAGATEAREA 0.00027817 ;
		ANTENNADIFFAREA 0.00194719 ;
		ANTENNAPARTIALMETALAREA 0.00195671 ;
	END TWEN[47]

	PIN TWEN[48]
		USE SIGNAL ;
		DIRECTION INPUT ;
		SHAPE ABUTMENT ;
		PORT
			 LAYER M2 ;
			RECT 0.0714 70.2557 0.1097 70.2933 ;
			 LAYER M3 ;
			RECT 0.0714 70.1929 0.1097 70.2933 ;
			 LAYER V2 ;
			RECT 0.0831 70.2686 0.098 70.2812 ;
		END

		ANTENNAGATEAREA 0.00027817 ;
		ANTENNADIFFAREA 0.00194719 ;
		ANTENNAPARTIALMETALAREA 0.00195671 ;
	END TWEN[48]

	PIN TWEN[49]
		USE SIGNAL ;
		DIRECTION INPUT ;
		SHAPE ABUTMENT ;
		PORT
			 LAYER M2 ;
			RECT 0.0714 71.5357 0.1097 71.5733 ;
			 LAYER M3 ;
			RECT 0.0714 71.4729 0.1097 71.5733 ;
			 LAYER V2 ;
			RECT 0.0831 71.5486 0.098 71.5612 ;
		END

		ANTENNAGATEAREA 0.00027817 ;
		ANTENNADIFFAREA 0.00194719 ;
		ANTENNAPARTIALMETALAREA 0.00195671 ;
	END TWEN[49]

	PIN TWEN[4]
		USE SIGNAL ;
		DIRECTION INPUT ;
		SHAPE ABUTMENT ;
		PORT
			 LAYER M2 ;
			RECT 0.0714 6.5506 0.1097 6.5882 ;
			 LAYER M3 ;
			RECT 0.0714 6.4878 0.1097 6.5882 ;
			 LAYER V2 ;
			RECT 0.0831 6.5635 0.098 6.5761 ;
		END

		ANTENNAGATEAREA 0.00027817 ;
		ANTENNADIFFAREA 0.00194719 ;
		ANTENNAPARTIALMETALAREA 0.00195671 ;
	END TWEN[4]

	PIN TWEN[50]
		USE SIGNAL ;
		DIRECTION INPUT ;
		SHAPE ABUTMENT ;
		PORT
			 LAYER M2 ;
			RECT 0.0714 72.8157 0.1097 72.8533 ;
			 LAYER M3 ;
			RECT 0.0714 72.7529 0.1097 72.8533 ;
			 LAYER V2 ;
			RECT 0.0831 72.8286 0.098 72.8412 ;
		END

		ANTENNAGATEAREA 0.00027817 ;
		ANTENNADIFFAREA 0.00194719 ;
		ANTENNAPARTIALMETALAREA 0.00195671 ;
	END TWEN[50]

	PIN TWEN[51]
		USE SIGNAL ;
		DIRECTION INPUT ;
		SHAPE ABUTMENT ;
		PORT
			 LAYER M2 ;
			RECT 0.0714 74.0957 0.1097 74.1333 ;
			 LAYER M3 ;
			RECT 0.0714 74.0329 0.1097 74.1333 ;
			 LAYER V2 ;
			RECT 0.0831 74.1086 0.098 74.1212 ;
		END

		ANTENNAGATEAREA 0.00027817 ;
		ANTENNADIFFAREA 0.00194719 ;
		ANTENNAPARTIALMETALAREA 0.00195671 ;
	END TWEN[51]

	PIN TWEN[52]
		USE SIGNAL ;
		DIRECTION INPUT ;
		SHAPE ABUTMENT ;
		PORT
			 LAYER M2 ;
			RECT 0.0714 75.3757 0.1097 75.4133 ;
			 LAYER M3 ;
			RECT 0.0714 75.3129 0.1097 75.4133 ;
			 LAYER V2 ;
			RECT 0.0831 75.3886 0.098 75.4012 ;
		END

		ANTENNAGATEAREA 0.00027817 ;
		ANTENNADIFFAREA 0.00194719 ;
		ANTENNAPARTIALMETALAREA 0.00195671 ;
	END TWEN[52]

	PIN TWEN[53]
		USE SIGNAL ;
		DIRECTION INPUT ;
		SHAPE ABUTMENT ;
		PORT
			 LAYER M2 ;
			RECT 0.0714 76.6557 0.1097 76.6933 ;
			 LAYER M3 ;
			RECT 0.0714 76.5929 0.1097 76.6933 ;
			 LAYER V2 ;
			RECT 0.0831 76.6686 0.098 76.6812 ;
		END

		ANTENNAGATEAREA 0.00027817 ;
		ANTENNADIFFAREA 0.00194719 ;
		ANTENNAPARTIALMETALAREA 0.00195671 ;
	END TWEN[53]

	PIN TWEN[54]
		USE SIGNAL ;
		DIRECTION INPUT ;
		SHAPE ABUTMENT ;
		PORT
			 LAYER M2 ;
			RECT 0.0714 77.9357 0.1097 77.9733 ;
			 LAYER M3 ;
			RECT 0.0714 77.8729 0.1097 77.9733 ;
			 LAYER V2 ;
			RECT 0.0831 77.9486 0.098 77.9612 ;
		END

		ANTENNAGATEAREA 0.00027817 ;
		ANTENNADIFFAREA 0.00194719 ;
		ANTENNAPARTIALMETALAREA 0.00195671 ;
	END TWEN[54]

	PIN TWEN[55]
		USE SIGNAL ;
		DIRECTION INPUT ;
		SHAPE ABUTMENT ;
		PORT
			 LAYER M2 ;
			RECT 0.0714 79.3663 0.1097 79.4039 ;
			 LAYER M3 ;
			RECT 0.0714 79.3035 0.1097 79.4039 ;
			 LAYER V2 ;
			RECT 0.0831 79.3792 0.098 79.3918 ;
		END

		ANTENNAGATEAREA 0.00027817 ;
		ANTENNADIFFAREA 0.00194719 ;
		ANTENNAPARTIALMETALAREA 0.00195671 ;
	END TWEN[55]

	PIN TWEN[56]
		USE SIGNAL ;
		DIRECTION INPUT ;
		SHAPE ABUTMENT ;
		PORT
			 LAYER M2 ;
			RECT 0.0714 80.4957 0.1097 80.5333 ;
			 LAYER M3 ;
			RECT 0.0714 80.4329 0.1097 80.5333 ;
			 LAYER V2 ;
			RECT 0.0831 80.5086 0.098 80.5212 ;
		END

		ANTENNAGATEAREA 0.00027817 ;
		ANTENNADIFFAREA 0.00194719 ;
		ANTENNAPARTIALMETALAREA 0.00195671 ;
	END TWEN[56]

	PIN TWEN[57]
		USE SIGNAL ;
		DIRECTION INPUT ;
		SHAPE ABUTMENT ;
		PORT
			 LAYER M2 ;
			RECT 0.0714 81.7757 0.1097 81.8133 ;
			 LAYER M3 ;
			RECT 0.0714 81.7129 0.1097 81.8133 ;
			 LAYER V2 ;
			RECT 0.0831 81.7886 0.098 81.8012 ;
		END

		ANTENNAGATEAREA 0.00027817 ;
		ANTENNADIFFAREA 0.00194719 ;
		ANTENNAPARTIALMETALAREA 0.00195671 ;
	END TWEN[57]

	PIN TWEN[58]
		USE SIGNAL ;
		DIRECTION INPUT ;
		SHAPE ABUTMENT ;
		PORT
			 LAYER M2 ;
			RECT 0.0714 82.5412 0.1097 82.5788 ;
			 LAYER M3 ;
			RECT 0.0714 82.5412 0.1097 82.6416 ;
			 LAYER V2 ;
			RECT 0.0831 82.5533 0.098 82.5659 ;
		END

		ANTENNAGATEAREA 0.00027817 ;
		ANTENNADIFFAREA 0.00194719 ;
		ANTENNAPARTIALMETALAREA 0.00195671 ;
	END TWEN[58]

	PIN TWEN[59]
		USE SIGNAL ;
		DIRECTION INPUT ;
		SHAPE ABUTMENT ;
		PORT
			 LAYER M2 ;
			RECT 0.0714 83.8212 0.1097 83.8588 ;
			 LAYER M3 ;
			RECT 0.0714 83.8212 0.1097 83.9216 ;
			 LAYER V2 ;
			RECT 0.0831 83.8333 0.098 83.8459 ;
		END

		ANTENNAGATEAREA 0.00027817 ;
		ANTENNADIFFAREA 0.00194719 ;
		ANTENNAPARTIALMETALAREA 0.00195671 ;
	END TWEN[59]

	PIN TWEN[5]
		USE SIGNAL ;
		DIRECTION INPUT ;
		SHAPE ABUTMENT ;
		PORT
			 LAYER M2 ;
			RECT 0.0714 7.8306 0.1097 7.8682 ;
			 LAYER M3 ;
			RECT 0.0714 7.7678 0.1097 7.8682 ;
			 LAYER V2 ;
			RECT 0.0831 7.8435 0.098 7.8561 ;
		END

		ANTENNAGATEAREA 0.00027817 ;
		ANTENNADIFFAREA 0.00194719 ;
		ANTENNAPARTIALMETALAREA 0.00195671 ;
	END TWEN[5]

	PIN TWEN[60]
		USE SIGNAL ;
		DIRECTION INPUT ;
		SHAPE ABUTMENT ;
		PORT
			 LAYER M2 ;
			RECT 0.0714 85.1012 0.1097 85.1388 ;
			 LAYER M3 ;
			RECT 0.0714 85.1012 0.1097 85.2016 ;
			 LAYER V2 ;
			RECT 0.0831 85.1133 0.098 85.1259 ;
		END

		ANTENNAGATEAREA 0.00027817 ;
		ANTENNADIFFAREA 0.00194719 ;
		ANTENNAPARTIALMETALAREA 0.00195671 ;
	END TWEN[60]

	PIN TWEN[61]
		USE SIGNAL ;
		DIRECTION INPUT ;
		SHAPE ABUTMENT ;
		PORT
			 LAYER M2 ;
			RECT 0.0714 86.3812 0.1097 86.4188 ;
			 LAYER M3 ;
			RECT 0.0714 86.3812 0.1097 86.4816 ;
			 LAYER V2 ;
			RECT 0.0831 86.3933 0.098 86.4059 ;
		END

		ANTENNAGATEAREA 0.00027817 ;
		ANTENNADIFFAREA 0.00194719 ;
		ANTENNAPARTIALMETALAREA 0.00195671 ;
	END TWEN[61]

	PIN TWEN[62]
		USE SIGNAL ;
		DIRECTION INPUT ;
		SHAPE ABUTMENT ;
		PORT
			 LAYER M2 ;
			RECT 0.0714 87.6612 0.1097 87.6988 ;
			 LAYER M3 ;
			RECT 0.0714 87.6612 0.1097 87.7616 ;
			 LAYER V2 ;
			RECT 0.0831 87.6733 0.098 87.6859 ;
		END

		ANTENNAGATEAREA 0.00027817 ;
		ANTENNADIFFAREA 0.00194719 ;
		ANTENNAPARTIALMETALAREA 0.00195671 ;
	END TWEN[62]

	PIN TWEN[63]
		USE SIGNAL ;
		DIRECTION INPUT ;
		SHAPE ABUTMENT ;
		PORT
			 LAYER M2 ;
			RECT 0.0714 88.9412 0.1097 88.9788 ;
			 LAYER M3 ;
			RECT 0.0714 88.9412 0.1097 89.0416 ;
			 LAYER V2 ;
			RECT 0.0831 88.9533 0.098 88.9659 ;
		END

		ANTENNAGATEAREA 0.00027817 ;
		ANTENNADIFFAREA 0.00194719 ;
		ANTENNAPARTIALMETALAREA 0.00195671 ;
	END TWEN[63]

	PIN TWEN[64]
		USE SIGNAL ;
		DIRECTION INPUT ;
		SHAPE ABUTMENT ;
		PORT
			 LAYER M2 ;
			RECT 0.0714 90.2212 0.1097 90.2588 ;
			 LAYER M3 ;
			RECT 0.0714 90.2212 0.1097 90.3216 ;
			 LAYER V2 ;
			RECT 0.0831 90.2333 0.098 90.2459 ;
		END

		ANTENNAGATEAREA 0.00027817 ;
		ANTENNADIFFAREA 0.00194719 ;
		ANTENNAPARTIALMETALAREA 0.00195671 ;
	END TWEN[64]

	PIN TWEN[65]
		USE SIGNAL ;
		DIRECTION INPUT ;
		SHAPE ABUTMENT ;
		PORT
			 LAYER M2 ;
			RECT 0.0714 91.5012 0.1097 91.5388 ;
			 LAYER M3 ;
			RECT 0.0714 91.5012 0.1097 91.6016 ;
			 LAYER V2 ;
			RECT 0.0831 91.5133 0.098 91.5259 ;
		END

		ANTENNAGATEAREA 0.00027817 ;
		ANTENNADIFFAREA 0.00194719 ;
		ANTENNAPARTIALMETALAREA 0.00195671 ;
	END TWEN[65]

	PIN TWEN[66]
		USE SIGNAL ;
		DIRECTION INPUT ;
		SHAPE ABUTMENT ;
		PORT
			 LAYER M2 ;
			RECT 0.0714 92.7812 0.1097 92.8188 ;
			 LAYER M3 ;
			RECT 0.0714 92.7812 0.1097 92.8816 ;
			 LAYER V2 ;
			RECT 0.0831 92.7933 0.098 92.8059 ;
		END

		ANTENNAGATEAREA 0.00027817 ;
		ANTENNADIFFAREA 0.00194719 ;
		ANTENNAPARTIALMETALAREA 0.00195671 ;
	END TWEN[66]

	PIN TWEN[67]
		USE SIGNAL ;
		DIRECTION INPUT ;
		SHAPE ABUTMENT ;
		PORT
			 LAYER M2 ;
			RECT 0.0714 94.0612 0.1097 94.0988 ;
			 LAYER M3 ;
			RECT 0.0714 94.0612 0.1097 94.1616 ;
			 LAYER V2 ;
			RECT 0.0831 94.0733 0.098 94.0859 ;
		END

		ANTENNAGATEAREA 0.00027817 ;
		ANTENNADIFFAREA 0.00194719 ;
		ANTENNAPARTIALMETALAREA 0.00195671 ;
	END TWEN[67]

	PIN TWEN[68]
		USE SIGNAL ;
		DIRECTION INPUT ;
		SHAPE ABUTMENT ;
		PORT
			 LAYER M2 ;
			RECT 0.0714 95.3412 0.1097 95.3788 ;
			 LAYER M3 ;
			RECT 0.0714 95.3412 0.1097 95.4416 ;
			 LAYER V2 ;
			RECT 0.0831 95.3533 0.098 95.3659 ;
		END

		ANTENNAGATEAREA 0.00027817 ;
		ANTENNADIFFAREA 0.00194719 ;
		ANTENNAPARTIALMETALAREA 0.00195671 ;
	END TWEN[68]

	PIN TWEN[69]
		USE SIGNAL ;
		DIRECTION INPUT ;
		SHAPE ABUTMENT ;
		PORT
			 LAYER M2 ;
			RECT 0.0714 96.6212 0.1097 96.6588 ;
			 LAYER M3 ;
			RECT 0.0714 96.6212 0.1097 96.7216 ;
			 LAYER V2 ;
			RECT 0.0831 96.6333 0.098 96.6459 ;
		END

		ANTENNAGATEAREA 0.00027817 ;
		ANTENNADIFFAREA 0.00194719 ;
		ANTENNAPARTIALMETALAREA 0.00195671 ;
	END TWEN[69]

	PIN TWEN[6]
		USE SIGNAL ;
		DIRECTION INPUT ;
		SHAPE ABUTMENT ;
		PORT
			 LAYER M2 ;
			RECT 0.0714 9.1106 0.1097 9.1482 ;
			 LAYER M3 ;
			RECT 0.0714 9.0478 0.1097 9.1482 ;
			 LAYER V2 ;
			RECT 0.0831 9.1235 0.098 9.1361 ;
		END

		ANTENNAGATEAREA 0.00027817 ;
		ANTENNADIFFAREA 0.00194719 ;
		ANTENNAPARTIALMETALAREA 0.00195671 ;
	END TWEN[6]

	PIN TWEN[70]
		USE SIGNAL ;
		DIRECTION INPUT ;
		SHAPE ABUTMENT ;
		PORT
			 LAYER M2 ;
			RECT 0.0714 97.9012 0.1097 97.9388 ;
			 LAYER M3 ;
			RECT 0.0714 97.9012 0.1097 98.0016 ;
			 LAYER V2 ;
			RECT 0.0831 97.9133 0.098 97.9259 ;
		END

		ANTENNAGATEAREA 0.00027817 ;
		ANTENNADIFFAREA 0.00194719 ;
		ANTENNAPARTIALMETALAREA 0.00195671 ;
	END TWEN[70]

	PIN TWEN[71]
		USE SIGNAL ;
		DIRECTION INPUT ;
		SHAPE ABUTMENT ;
		PORT
			 LAYER M2 ;
			RECT 0.0714 99.1812 0.1097 99.2188 ;
			 LAYER M3 ;
			RECT 0.0714 99.1812 0.1097 99.2816 ;
			 LAYER V2 ;
			RECT 0.0831 99.1933 0.098 99.2059 ;
		END

		ANTENNAGATEAREA 0.00027817 ;
		ANTENNADIFFAREA 0.00194719 ;
		ANTENNAPARTIALMETALAREA 0.00195671 ;
	END TWEN[71]

	PIN TWEN[72]
		USE SIGNAL ;
		DIRECTION INPUT ;
		SHAPE ABUTMENT ;
		PORT
			 LAYER M2 ;
			RECT 0.0714 108.16 0.1097 108.1976 ;
			 LAYER M3 ;
			RECT 0.0714 108.16 0.1097 108.2604 ;
			 LAYER V2 ;
			RECT 0.0831 108.1722 0.098 108.1847 ;
		END

		ANTENNAGATEAREA 0.00027817 ;
		ANTENNADIFFAREA 0.00194719 ;
		ANTENNAPARTIALMETALAREA 0.00195671 ;
	END TWEN[72]

	PIN TWEN[73]
		USE SIGNAL ;
		DIRECTION INPUT ;
		SHAPE ABUTMENT ;
		PORT
			 LAYER M2 ;
			RECT 0.0714 109.44 0.1097 109.4776 ;
			 LAYER M3 ;
			RECT 0.0714 109.44 0.1097 109.5404 ;
			 LAYER V2 ;
			RECT 0.0831 109.4522 0.098 109.4647 ;
		END

		ANTENNAGATEAREA 0.00027817 ;
		ANTENNADIFFAREA 0.00194719 ;
		ANTENNAPARTIALMETALAREA 0.00195671 ;
	END TWEN[73]

	PIN TWEN[74]
		USE SIGNAL ;
		DIRECTION INPUT ;
		SHAPE ABUTMENT ;
		PORT
			 LAYER M2 ;
			RECT 0.0714 110.72 0.1097 110.7576 ;
			 LAYER M3 ;
			RECT 0.0714 110.72 0.1097 110.8204 ;
			 LAYER V2 ;
			RECT 0.0831 110.7322 0.098 110.7447 ;
		END

		ANTENNAGATEAREA 0.00027817 ;
		ANTENNADIFFAREA 0.00194719 ;
		ANTENNAPARTIALMETALAREA 0.00195671 ;
	END TWEN[74]

	PIN TWEN[75]
		USE SIGNAL ;
		DIRECTION INPUT ;
		SHAPE ABUTMENT ;
		PORT
			 LAYER M2 ;
			RECT 0.0714 112 0.1097 112.0376 ;
			 LAYER M3 ;
			RECT 0.0714 112 0.1097 112.1004 ;
			 LAYER V2 ;
			RECT 0.0831 112.0122 0.098 112.0247 ;
		END

		ANTENNAGATEAREA 0.00027817 ;
		ANTENNADIFFAREA 0.00194719 ;
		ANTENNAPARTIALMETALAREA 0.00195671 ;
	END TWEN[75]

	PIN TWEN[76]
		USE SIGNAL ;
		DIRECTION INPUT ;
		SHAPE ABUTMENT ;
		PORT
			 LAYER M2 ;
			RECT 0.0714 113.28 0.1097 113.3176 ;
			 LAYER M3 ;
			RECT 0.0714 113.28 0.1097 113.3804 ;
			 LAYER V2 ;
			RECT 0.0831 113.2922 0.098 113.3047 ;
		END

		ANTENNAGATEAREA 0.00027817 ;
		ANTENNADIFFAREA 0.00194719 ;
		ANTENNAPARTIALMETALAREA 0.00195671 ;
	END TWEN[76]

	PIN TWEN[77]
		USE SIGNAL ;
		DIRECTION INPUT ;
		SHAPE ABUTMENT ;
		PORT
			 LAYER M2 ;
			RECT 0.0714 114.56 0.1097 114.5976 ;
			 LAYER M3 ;
			RECT 0.0714 114.56 0.1097 114.6604 ;
			 LAYER V2 ;
			RECT 0.0831 114.5722 0.098 114.5847 ;
		END

		ANTENNAGATEAREA 0.00027817 ;
		ANTENNADIFFAREA 0.00194719 ;
		ANTENNAPARTIALMETALAREA 0.00195671 ;
	END TWEN[77]

	PIN TWEN[78]
		USE SIGNAL ;
		DIRECTION INPUT ;
		SHAPE ABUTMENT ;
		PORT
			 LAYER M2 ;
			RECT 0.0714 115.84 0.1097 115.8776 ;
			 LAYER M3 ;
			RECT 0.0714 115.84 0.1097 115.9404 ;
			 LAYER V2 ;
			RECT 0.0831 115.8522 0.098 115.8647 ;
		END

		ANTENNAGATEAREA 0.00027817 ;
		ANTENNADIFFAREA 0.00194719 ;
		ANTENNAPARTIALMETALAREA 0.00195671 ;
	END TWEN[78]

	PIN TWEN[79]
		USE SIGNAL ;
		DIRECTION INPUT ;
		SHAPE ABUTMENT ;
		PORT
			 LAYER M2 ;
			RECT 0.0714 117.12 0.1097 117.1576 ;
			 LAYER M3 ;
			RECT 0.0714 117.12 0.1097 117.2204 ;
			 LAYER V2 ;
			RECT 0.0831 117.1322 0.098 117.1447 ;
		END

		ANTENNAGATEAREA 0.00027817 ;
		ANTENNADIFFAREA 0.00194719 ;
		ANTENNAPARTIALMETALAREA 0.00195671 ;
	END TWEN[79]

	PIN TWEN[7]
		USE SIGNAL ;
		DIRECTION INPUT ;
		SHAPE ABUTMENT ;
		PORT
			 LAYER M2 ;
			RECT 0.0714 10.3906 0.1097 10.4282 ;
			 LAYER M3 ;
			RECT 0.0714 10.3278 0.1097 10.4282 ;
			 LAYER V2 ;
			RECT 0.0831 10.4035 0.098 10.4161 ;
		END

		ANTENNAGATEAREA 0.00027817 ;
		ANTENNADIFFAREA 0.00194719 ;
		ANTENNAPARTIALMETALAREA 0.00195671 ;
	END TWEN[7]

	PIN TWEN[80]
		USE SIGNAL ;
		DIRECTION INPUT ;
		SHAPE ABUTMENT ;
		PORT
			 LAYER M2 ;
			RECT 0.0714 118.4 0.1097 118.4376 ;
			 LAYER M3 ;
			RECT 0.0714 118.4 0.1097 118.5004 ;
			 LAYER V2 ;
			RECT 0.0831 118.4122 0.098 118.4247 ;
		END

		ANTENNAGATEAREA 0.00027817 ;
		ANTENNADIFFAREA 0.00194719 ;
		ANTENNAPARTIALMETALAREA 0.00195671 ;
	END TWEN[80]

	PIN TWEN[81]
		USE SIGNAL ;
		DIRECTION INPUT ;
		SHAPE ABUTMENT ;
		PORT
			 LAYER M2 ;
			RECT 0.0714 119.68 0.1097 119.7176 ;
			 LAYER M3 ;
			RECT 0.0714 119.68 0.1097 119.7804 ;
			 LAYER V2 ;
			RECT 0.0831 119.6922 0.098 119.7047 ;
		END

		ANTENNAGATEAREA 0.00027817 ;
		ANTENNADIFFAREA 0.00194719 ;
		ANTENNAPARTIALMETALAREA 0.00195671 ;
	END TWEN[81]

	PIN TWEN[82]
		USE SIGNAL ;
		DIRECTION INPUT ;
		SHAPE ABUTMENT ;
		PORT
			 LAYER M2 ;
			RECT 0.0714 120.96 0.1097 120.9976 ;
			 LAYER M3 ;
			RECT 0.0714 120.96 0.1097 121.0604 ;
			 LAYER V2 ;
			RECT 0.0831 120.9722 0.098 120.9847 ;
		END

		ANTENNAGATEAREA 0.00027817 ;
		ANTENNADIFFAREA 0.00194719 ;
		ANTENNAPARTIALMETALAREA 0.00195671 ;
	END TWEN[82]

	PIN TWEN[83]
		USE SIGNAL ;
		DIRECTION INPUT ;
		SHAPE ABUTMENT ;
		PORT
			 LAYER M2 ;
			RECT 0.0714 122.24 0.1097 122.2776 ;
			 LAYER M3 ;
			RECT 0.0714 122.24 0.1097 122.3404 ;
			 LAYER V2 ;
			RECT 0.0831 122.2522 0.098 122.2647 ;
		END

		ANTENNAGATEAREA 0.00027817 ;
		ANTENNADIFFAREA 0.00194719 ;
		ANTENNAPARTIALMETALAREA 0.00195671 ;
	END TWEN[83]

	PIN TWEN[84]
		USE SIGNAL ;
		DIRECTION INPUT ;
		SHAPE ABUTMENT ;
		PORT
			 LAYER M2 ;
			RECT 0.0714 123.52 0.1097 123.5576 ;
			 LAYER M3 ;
			RECT 0.0714 123.52 0.1097 123.6204 ;
			 LAYER V2 ;
			RECT 0.0831 123.5322 0.098 123.5447 ;
		END

		ANTENNAGATEAREA 0.00027817 ;
		ANTENNADIFFAREA 0.00194719 ;
		ANTENNAPARTIALMETALAREA 0.00195671 ;
	END TWEN[84]

	PIN TWEN[85]
		USE SIGNAL ;
		DIRECTION INPUT ;
		SHAPE ABUTMENT ;
		PORT
			 LAYER M2 ;
			RECT 0.0714 124.8 0.1097 124.8376 ;
			 LAYER M3 ;
			RECT 0.0714 124.8 0.1097 124.9004 ;
			 LAYER V2 ;
			RECT 0.0831 124.8122 0.098 124.8247 ;
		END

		ANTENNAGATEAREA 0.00027817 ;
		ANTENNADIFFAREA 0.00194719 ;
		ANTENNAPARTIALMETALAREA 0.00195671 ;
	END TWEN[85]

	PIN TWEN[86]
		USE SIGNAL ;
		DIRECTION INPUT ;
		SHAPE ABUTMENT ;
		PORT
			 LAYER M2 ;
			RECT 0.0714 126.08 0.1097 126.1176 ;
			 LAYER M3 ;
			RECT 0.0714 126.08 0.1097 126.1804 ;
			 LAYER V2 ;
			RECT 0.0831 126.0922 0.098 126.1047 ;
		END

		ANTENNAGATEAREA 0.00027817 ;
		ANTENNADIFFAREA 0.00194719 ;
		ANTENNAPARTIALMETALAREA 0.00195671 ;
	END TWEN[86]

	PIN TWEN[87]
		USE SIGNAL ;
		DIRECTION INPUT ;
		SHAPE ABUTMENT ;
		PORT
			 LAYER M2 ;
			RECT 0.0714 127.36 0.1097 127.3976 ;
			 LAYER M3 ;
			RECT 0.0714 127.36 0.1097 127.4604 ;
			 LAYER V2 ;
			RECT 0.0831 127.3722 0.098 127.3847 ;
		END

		ANTENNAGATEAREA 0.00027817 ;
		ANTENNADIFFAREA 0.00194719 ;
		ANTENNAPARTIALMETALAREA 0.00195671 ;
	END TWEN[87]

	PIN TWEN[88]
		USE SIGNAL ;
		DIRECTION INPUT ;
		SHAPE ABUTMENT ;
		PORT
			 LAYER M2 ;
			RECT 0.0714 128.64 0.1097 128.6776 ;
			 LAYER M3 ;
			RECT 0.0714 128.64 0.1097 128.7404 ;
			 LAYER V2 ;
			RECT 0.0831 128.6522 0.098 128.6647 ;
		END

		ANTENNAGATEAREA 0.00027817 ;
		ANTENNADIFFAREA 0.00194719 ;
		ANTENNAPARTIALMETALAREA 0.00195671 ;
	END TWEN[88]

	PIN TWEN[89]
		USE SIGNAL ;
		DIRECTION INPUT ;
		SHAPE ABUTMENT ;
		PORT
			 LAYER M2 ;
			RECT 0.0714 129.92 0.1097 129.9576 ;
			 LAYER M3 ;
			RECT 0.0714 129.92 0.1097 130.0204 ;
			 LAYER V2 ;
			RECT 0.0831 129.9322 0.098 129.9447 ;
		END

		ANTENNAGATEAREA 0.00027817 ;
		ANTENNADIFFAREA 0.00194719 ;
		ANTENNAPARTIALMETALAREA 0.00195671 ;
	END TWEN[89]

	PIN TWEN[8]
		USE SIGNAL ;
		DIRECTION INPUT ;
		SHAPE ABUTMENT ;
		PORT
			 LAYER M2 ;
			RECT 0.0714 11.6706 0.1097 11.7082 ;
			 LAYER M3 ;
			RECT 0.0714 11.6078 0.1097 11.7082 ;
			 LAYER V2 ;
			RECT 0.0831 11.6835 0.098 11.6961 ;
		END

		ANTENNAGATEAREA 0.00027817 ;
		ANTENNADIFFAREA 0.00194719 ;
		ANTENNAPARTIALMETALAREA 0.00195671 ;
	END TWEN[8]

	PIN TWEN[90]
		USE SIGNAL ;
		DIRECTION INPUT ;
		SHAPE ABUTMENT ;
		PORT
			 LAYER M2 ;
			RECT 0.0714 131.2 0.1097 131.2376 ;
			 LAYER M3 ;
			RECT 0.0714 131.2 0.1097 131.3004 ;
			 LAYER V2 ;
			RECT 0.0831 131.2122 0.098 131.2247 ;
		END

		ANTENNAGATEAREA 0.00027817 ;
		ANTENNADIFFAREA 0.00194719 ;
		ANTENNAPARTIALMETALAREA 0.00195671 ;
	END TWEN[90]

	PIN TWEN[91]
		USE SIGNAL ;
		DIRECTION INPUT ;
		SHAPE ABUTMENT ;
		PORT
			 LAYER M2 ;
			RECT 0.0714 132.48 0.1097 132.5176 ;
			 LAYER M3 ;
			RECT 0.0714 132.48 0.1097 132.5804 ;
			 LAYER V2 ;
			RECT 0.0831 132.4922 0.098 132.5047 ;
		END

		ANTENNAGATEAREA 0.00027817 ;
		ANTENNADIFFAREA 0.00194719 ;
		ANTENNAPARTIALMETALAREA 0.00195671 ;
	END TWEN[91]

	PIN TWEN[92]
		USE SIGNAL ;
		DIRECTION INPUT ;
		SHAPE ABUTMENT ;
		PORT
			 LAYER M2 ;
			RECT 0.0714 133.76 0.1097 133.7976 ;
			 LAYER M3 ;
			RECT 0.0714 133.76 0.1097 133.8604 ;
			 LAYER V2 ;
			RECT 0.0831 133.7722 0.098 133.7847 ;
		END

		ANTENNAGATEAREA 0.00027817 ;
		ANTENNADIFFAREA 0.00194719 ;
		ANTENNAPARTIALMETALAREA 0.00195671 ;
	END TWEN[92]

	PIN TWEN[93]
		USE SIGNAL ;
		DIRECTION INPUT ;
		SHAPE ABUTMENT ;
		PORT
			 LAYER M2 ;
			RECT 0.0714 135.04 0.1097 135.0776 ;
			 LAYER M3 ;
			RECT 0.0714 135.04 0.1097 135.1404 ;
			 LAYER V2 ;
			RECT 0.0831 135.0522 0.098 135.0647 ;
		END

		ANTENNAGATEAREA 0.00027817 ;
		ANTENNADIFFAREA 0.00194719 ;
		ANTENNAPARTIALMETALAREA 0.00195671 ;
	END TWEN[93]

	PIN TWEN[94]
		USE SIGNAL ;
		DIRECTION INPUT ;
		SHAPE ABUTMENT ;
		PORT
			 LAYER M2 ;
			RECT 0.0714 136.32 0.1097 136.3576 ;
			 LAYER M3 ;
			RECT 0.0714 136.32 0.1097 136.4204 ;
			 LAYER V2 ;
			RECT 0.0831 136.3322 0.098 136.3447 ;
		END

		ANTENNAGATEAREA 0.00027817 ;
		ANTENNADIFFAREA 0.00194719 ;
		ANTENNAPARTIALMETALAREA 0.00195671 ;
	END TWEN[94]

	PIN TWEN[95]
		USE SIGNAL ;
		DIRECTION INPUT ;
		SHAPE ABUTMENT ;
		PORT
			 LAYER M2 ;
			RECT 0.0714 137.6 0.1097 137.6376 ;
			 LAYER M3 ;
			RECT 0.0714 137.6 0.1097 137.7004 ;
			 LAYER V2 ;
			RECT 0.0831 137.6122 0.098 137.6247 ;
		END

		ANTENNAGATEAREA 0.00027817 ;
		ANTENNADIFFAREA 0.00194719 ;
		ANTENNAPARTIALMETALAREA 0.00195671 ;
	END TWEN[95]

	PIN TWEN[9]
		USE SIGNAL ;
		DIRECTION INPUT ;
		SHAPE ABUTMENT ;
		PORT
			 LAYER M2 ;
			RECT 0.0714 12.9506 0.1097 12.9882 ;
			 LAYER M3 ;
			RECT 0.0714 12.8878 0.1097 12.9882 ;
			 LAYER V2 ;
			RECT 0.0831 12.9635 0.098 12.9761 ;
		END

		ANTENNAGATEAREA 0.00027817 ;
		ANTENNADIFFAREA 0.00194719 ;
		ANTENNAPARTIALMETALAREA 0.00195671 ;
	END TWEN[9]

	PIN VDDCE
		USE POWER ;
		DIRECTION INOUT ;
		PORT
			 LAYER M4 ;
			RECT 0.2105 138.2267 23.961 138.2737 ;
		END

		PORT
			 LAYER M4 ;
			RECT 0.2105 117.7467 23.961 117.7937 ;
		END

		PORT
			 LAYER M4 ;
			RECT 0.2105 117.1067 23.961 117.1537 ;
		END

		PORT
			 LAYER M4 ;
			RECT 0.2105 116.4667 23.961 116.5137 ;
		END

		PORT
			 LAYER M4 ;
			RECT 0.2105 136.9467 23.961 136.9937 ;
		END

		PORT
			 LAYER M4 ;
			RECT 0.2105 115.8267 23.961 115.8737 ;
		END

		PORT
			 LAYER M4 ;
			RECT 0.2105 115.1867 23.961 115.2337 ;
		END

		PORT
			 LAYER M4 ;
			RECT 0.2105 114.5467 23.961 114.5937 ;
		END

		PORT
			 LAYER M4 ;
			RECT 0.2105 113.9067 23.961 113.9537 ;
		END

		PORT
			 LAYER M4 ;
			RECT 0.2105 113.2667 23.961 113.3137 ;
		END

		PORT
			 LAYER M4 ;
			RECT 0.2105 112.6267 23.961 112.6737 ;
		END

		PORT
			 LAYER M4 ;
			RECT 0.2105 111.9867 23.961 112.0337 ;
		END

		PORT
			 LAYER M4 ;
			RECT 0.2105 111.3467 23.961 111.3937 ;
		END

		PORT
			 LAYER M4 ;
			RECT 0.2105 110.7067 23.961 110.7537 ;
		END

		PORT
			 LAYER M4 ;
			RECT 0.2105 110.0667 23.961 110.1137 ;
		END

		PORT
			 LAYER M4 ;
			RECT 0.2105 136.3067 23.961 136.3537 ;
		END

		PORT
			 LAYER M4 ;
			RECT 0.2105 109.4267 23.961 109.4737 ;
		END

		PORT
			 LAYER M4 ;
			RECT 0.2105 108.7867 23.961 108.8337 ;
		END

		PORT
			 LAYER M4 ;
			RECT 0.2105 108.1467 23.961 108.1937 ;
		END

		PORT
			 LAYER M4 ;
			RECT 0.2105 135.6667 23.961 135.7137 ;
		END

		PORT
			 LAYER M4 ;
			RECT 0.2105 99.8078 23.961 99.8549 ;
		END

		PORT
			 LAYER M4 ;
			RECT 0.2105 99.1678 23.961 99.2149 ;
		END

		PORT
			 LAYER M4 ;
			RECT 0.2105 98.5278 23.961 98.5749 ;
		END

		PORT
			 LAYER M4 ;
			RECT 0.2105 97.8878 23.961 97.9349 ;
		END

		PORT
			 LAYER M4 ;
			RECT 0.2105 97.2478 23.961 97.2949 ;
		END

		PORT
			 LAYER M4 ;
			RECT 0.2105 96.6078 23.961 96.6549 ;
		END

		PORT
			 LAYER M4 ;
			RECT 0.2105 135.0267 23.961 135.0737 ;
		END

		PORT
			 LAYER M4 ;
			RECT 0.2105 95.9678 23.961 96.0149 ;
		END

		PORT
			 LAYER M4 ;
			RECT 0.2105 95.3278 23.961 95.3749 ;
		END

		PORT
			 LAYER M4 ;
			RECT 0.2105 94.6878 23.961 94.7349 ;
		END

		PORT
			 LAYER M4 ;
			RECT 0.2105 94.0478 23.961 94.0949 ;
		END

		PORT
			 LAYER M4 ;
			RECT 0.2105 93.4078 23.961 93.4549 ;
		END

		PORT
			 LAYER M4 ;
			RECT 0.2105 92.7678 23.961 92.8149 ;
		END

		PORT
			 LAYER M4 ;
			RECT 0.2105 92.1278 23.961 92.1749 ;
		END

		PORT
			 LAYER M4 ;
			RECT 0.2105 91.4878 23.961 91.5349 ;
		END

		PORT
			 LAYER M4 ;
			RECT 0.2105 90.8478 23.961 90.8949 ;
		END

		PORT
			 LAYER M4 ;
			RECT 0.2105 90.2078 23.961 90.2549 ;
		END

		PORT
			 LAYER M4 ;
			RECT 0.2105 134.3867 23.961 134.4337 ;
		END

		PORT
			 LAYER M4 ;
			RECT 0.2105 89.5678 23.961 89.6149 ;
		END

		PORT
			 LAYER M4 ;
			RECT 0.2105 88.9278 23.961 88.9749 ;
		END

		PORT
			 LAYER M4 ;
			RECT 0.2105 88.2878 23.961 88.3349 ;
		END

		PORT
			 LAYER M4 ;
			RECT 0.2105 87.6478 23.961 87.6949 ;
		END

		PORT
			 LAYER M4 ;
			RECT 0.2105 87.0078 23.961 87.0549 ;
		END

		PORT
			 LAYER M4 ;
			RECT 0.2105 86.3678 23.961 86.4149 ;
		END

		PORT
			 LAYER M4 ;
			RECT 0.2105 85.7278 23.961 85.7749 ;
		END

		PORT
			 LAYER M4 ;
			RECT 0.2105 85.0878 23.961 85.1349 ;
		END

		PORT
			 LAYER M4 ;
			RECT 0.2105 84.4478 23.961 84.4949 ;
		END

		PORT
			 LAYER M4 ;
			RECT 0.2105 83.8078 23.961 83.8549 ;
		END

		PORT
			 LAYER M4 ;
			RECT 0.2105 133.7467 23.961 133.7937 ;
		END

		PORT
			 LAYER M4 ;
			RECT 0.2105 83.1678 23.961 83.2149 ;
		END

		PORT
			 LAYER M4 ;
			RECT 0.2105 82.5278 23.961 82.5749 ;
		END

		PORT
			 LAYER M4 ;
			RECT 0.2105 81.8878 23.961 81.9349 ;
		END

		PORT
			 LAYER M4 ;
			RECT 0.2105 81.2478 23.961 81.2949 ;
		END

		PORT
			 LAYER M4 ;
			RECT 0.2105 80.6078 23.961 80.6549 ;
		END

		PORT
			 LAYER M4 ;
			RECT 0.2105 79.9678 23.961 80.0149 ;
		END

		PORT
			 LAYER M4 ;
			RECT 0.2105 79.3278 23.961 79.3749 ;
		END

		PORT
			 LAYER M4 ;
			RECT 0.2105 78.6878 23.961 78.7349 ;
		END

		PORT
			 LAYER M4 ;
			RECT 0.2105 78.0478 23.961 78.0949 ;
		END

		PORT
			 LAYER M4 ;
			RECT 0.2105 77.4078 23.961 77.4549 ;
		END

		PORT
			 LAYER M4 ;
			RECT 0.2105 133.1067 23.961 133.1537 ;
		END

		PORT
			 LAYER M4 ;
			RECT 0.2105 76.7678 23.961 76.8149 ;
		END

		PORT
			 LAYER M4 ;
			RECT 0.2105 76.1278 23.961 76.1749 ;
		END

		PORT
			 LAYER M4 ;
			RECT 0.2105 75.4878 23.961 75.5349 ;
		END

		PORT
			 LAYER M4 ;
			RECT 0.2105 74.8478 23.961 74.8949 ;
		END

		PORT
			 LAYER M4 ;
			RECT 0.2105 74.2078 23.961 74.2549 ;
		END

		PORT
			 LAYER M4 ;
			RECT 0.2105 73.5678 23.961 73.6149 ;
		END

		PORT
			 LAYER M4 ;
			RECT 0.2105 72.9278 23.961 72.9749 ;
		END

		PORT
			 LAYER M4 ;
			RECT 0.2105 72.2878 23.961 72.3349 ;
		END

		PORT
			 LAYER M4 ;
			RECT 0.2105 71.6478 23.961 71.6949 ;
		END

		PORT
			 LAYER M4 ;
			RECT 0.2105 71.0078 23.961 71.0549 ;
		END

		PORT
			 LAYER M4 ;
			RECT 0.2105 132.4667 23.961 132.5137 ;
		END

		PORT
			 LAYER M4 ;
			RECT 0.2105 70.3678 23.961 70.4149 ;
		END

		PORT
			 LAYER M4 ;
			RECT 0.2105 69.7278 23.961 69.7749 ;
		END

		PORT
			 LAYER M4 ;
			RECT 0.2105 69.2933 23.961 69.3404 ;
		END

		PORT
			 LAYER M4 ;
			RECT 0.2105 68.6533 23.961 68.7004 ;
		END

		PORT
			 LAYER M4 ;
			RECT 0.2105 68.0133 23.961 68.0604 ;
		END

		PORT
			 LAYER M4 ;
			RECT 0.2105 67.3733 23.961 67.4204 ;
		END

		PORT
			 LAYER M4 ;
			RECT 0.2105 66.7333 23.961 66.7804 ;
		END

		PORT
			 LAYER M4 ;
			RECT 0.2105 66.0933 23.961 66.1404 ;
		END

		PORT
			 LAYER M4 ;
			RECT 0.2105 65.4533 23.961 65.5004 ;
		END

		PORT
			 LAYER M4 ;
			RECT 0.2105 131.8267 23.961 131.8737 ;
		END

		PORT
			 LAYER M4 ;
			RECT 0.2105 64.8133 23.961 64.8604 ;
		END

		PORT
			 LAYER M4 ;
			RECT 0.2105 64.1733 23.961 64.2204 ;
		END

		PORT
			 LAYER M4 ;
			RECT 0.2105 63.5333 23.961 63.5804 ;
		END

		PORT
			 LAYER M4 ;
			RECT 0.2105 62.8933 23.961 62.9404 ;
		END

		PORT
			 LAYER M4 ;
			RECT 0.2105 62.2533 23.961 62.3004 ;
		END

		PORT
			 LAYER M4 ;
			RECT 0.2105 61.6133 23.961 61.6604 ;
		END

		PORT
			 LAYER M4 ;
			RECT 0.2105 60.9733 23.961 61.0204 ;
		END

		PORT
			 LAYER M4 ;
			RECT 0.2105 60.3333 23.961 60.3804 ;
		END

		PORT
			 LAYER M4 ;
			RECT 0.2105 59.6933 23.961 59.7404 ;
		END

		PORT
			 LAYER M4 ;
			RECT 0.2105 59.0533 23.961 59.1004 ;
		END

		PORT
			 LAYER M4 ;
			RECT 0.2105 131.1867 23.961 131.2337 ;
		END

		PORT
			 LAYER M4 ;
			RECT 0.2105 58.4133 23.961 58.4604 ;
		END

		PORT
			 LAYER M4 ;
			RECT 0.2105 57.7733 23.961 57.8204 ;
		END

		PORT
			 LAYER M4 ;
			RECT 0.2105 57.1333 23.961 57.1804 ;
		END

		PORT
			 LAYER M4 ;
			RECT 0.2105 56.4933 23.961 56.5404 ;
		END

		PORT
			 LAYER M4 ;
			RECT 0.2105 55.8533 23.961 55.9004 ;
		END

		PORT
			 LAYER M4 ;
			RECT 0.2105 55.2133 23.961 55.2604 ;
		END

		PORT
			 LAYER M4 ;
			RECT 0.2105 54.5733 23.961 54.6204 ;
		END

		PORT
			 LAYER M4 ;
			RECT 0.2105 53.9333 23.961 53.9804 ;
		END

		PORT
			 LAYER M4 ;
			RECT 0.2105 53.2933 23.961 53.3404 ;
		END

		PORT
			 LAYER M4 ;
			RECT 0.2105 52.6533 23.961 52.7004 ;
		END

		PORT
			 LAYER M4 ;
			RECT 0.2105 130.5467 23.961 130.5937 ;
		END

		PORT
			 LAYER M4 ;
			RECT 0.2105 52.0133 23.961 52.0604 ;
		END

		PORT
			 LAYER M4 ;
			RECT 0.2105 51.3733 23.961 51.4204 ;
		END

		PORT
			 LAYER M4 ;
			RECT 0.2105 50.7333 23.961 50.7804 ;
		END

		PORT
			 LAYER M4 ;
			RECT 0.2105 50.0933 23.961 50.1404 ;
		END

		PORT
			 LAYER M4 ;
			RECT 0.2105 49.4533 23.961 49.5004 ;
		END

		PORT
			 LAYER M4 ;
			RECT 0.2105 48.8133 23.961 48.8604 ;
		END

		PORT
			 LAYER M4 ;
			RECT 0.2105 48.1733 23.961 48.2204 ;
		END

		PORT
			 LAYER M4 ;
			RECT 0.2105 47.5333 23.961 47.5804 ;
		END

		PORT
			 LAYER M4 ;
			RECT 0.2105 46.8933 23.961 46.9404 ;
		END

		PORT
			 LAYER M4 ;
			RECT 0.2105 46.2533 23.961 46.3004 ;
		END

		PORT
			 LAYER M4 ;
			RECT 0.2105 129.9067 23.961 129.9537 ;
		END

		PORT
			 LAYER M4 ;
			RECT 0.2105 45.6133 23.961 45.6604 ;
		END

		PORT
			 LAYER M4 ;
			RECT 0.2105 44.9733 23.961 45.0204 ;
		END

		PORT
			 LAYER M4 ;
			RECT 0.2105 44.3333 23.961 44.3804 ;
		END

		PORT
			 LAYER M4 ;
			RECT 0.2105 43.6933 23.961 43.7404 ;
		END

		PORT
			 LAYER M4 ;
			RECT 0.2105 43.0533 23.961 43.1004 ;
		END

		PORT
			 LAYER M4 ;
			RECT 0.2105 42.4133 23.961 42.4604 ;
		END

		PORT
			 LAYER M4 ;
			RECT 0.2105 41.7733 23.961 41.8204 ;
		END

		PORT
			 LAYER M4 ;
			RECT 0.2105 41.1333 23.961 41.1804 ;
		END

		PORT
			 LAYER M4 ;
			RECT 0.2105 40.4933 23.961 40.5404 ;
		END

		PORT
			 LAYER M4 ;
			RECT 0.2105 39.8533 23.961 39.9004 ;
		END

		PORT
			 LAYER M4 ;
			RECT 0.2105 129.2667 23.961 129.3137 ;
		END

		PORT
			 LAYER M4 ;
			RECT 0.2105 39.2133 23.961 39.2604 ;
		END

		PORT
			 LAYER M4 ;
			RECT 0.2105 128.6267 23.961 128.6737 ;
		END

		PORT
			 LAYER M4 ;
			RECT 0.2105 30.8745 23.961 30.9216 ;
		END

		PORT
			 LAYER M4 ;
			RECT 0.2105 30.2345 23.961 30.2816 ;
		END

		PORT
			 LAYER M4 ;
			RECT 0.2105 29.5945 23.961 29.6416 ;
		END

		PORT
			 LAYER M4 ;
			RECT 0.2105 28.9545 23.961 29.0016 ;
		END

		PORT
			 LAYER M4 ;
			RECT 0.2105 28.3145 23.961 28.3616 ;
		END

		PORT
			 LAYER M4 ;
			RECT 0.2105 27.6745 23.961 27.7216 ;
		END

		PORT
			 LAYER M4 ;
			RECT 0.2105 27.0345 23.961 27.0816 ;
		END

		PORT
			 LAYER M4 ;
			RECT 0.2105 127.9867 23.961 128.0337 ;
		END

		PORT
			 LAYER M4 ;
			RECT 0.2105 26.3945 23.961 26.4416 ;
		END

		PORT
			 LAYER M4 ;
			RECT 0.2105 25.7545 23.961 25.8016 ;
		END

		PORT
			 LAYER M4 ;
			RECT 0.2105 25.1145 23.961 25.1616 ;
		END

		PORT
			 LAYER M4 ;
			RECT 0.2105 24.4745 23.961 24.5216 ;
		END

		PORT
			 LAYER M4 ;
			RECT 0.2105 23.8345 23.961 23.8816 ;
		END

		PORT
			 LAYER M4 ;
			RECT 0.2105 23.1945 23.961 23.2416 ;
		END

		PORT
			 LAYER M4 ;
			RECT 0.2105 22.5545 23.961 22.6016 ;
		END

		PORT
			 LAYER M4 ;
			RECT 0.2105 21.9145 23.961 21.9616 ;
		END

		PORT
			 LAYER M4 ;
			RECT 0.2105 21.2745 23.961 21.3216 ;
		END

		PORT
			 LAYER M4 ;
			RECT 0.2105 20.6345 23.961 20.6816 ;
		END

		PORT
			 LAYER M4 ;
			RECT 0.2105 127.3467 23.961 127.3937 ;
		END

		PORT
			 LAYER M4 ;
			RECT 0.2105 19.9945 23.961 20.0416 ;
		END

		PORT
			 LAYER M4 ;
			RECT 0.2105 19.3545 23.961 19.4016 ;
		END

		PORT
			 LAYER M4 ;
			RECT 0.2105 18.7145 23.961 18.7616 ;
		END

		PORT
			 LAYER M4 ;
			RECT 0.2105 18.0745 23.961 18.1216 ;
		END

		PORT
			 LAYER M4 ;
			RECT 0.2105 17.4345 23.961 17.4816 ;
		END

		PORT
			 LAYER M4 ;
			RECT 0.2105 16.7945 23.961 16.8416 ;
		END

		PORT
			 LAYER M4 ;
			RECT 0.2105 16.1545 23.961 16.2016 ;
		END

		PORT
			 LAYER M4 ;
			RECT 0.2105 15.5145 23.961 15.5616 ;
		END

		PORT
			 LAYER M4 ;
			RECT 0.2105 14.8745 23.961 14.9216 ;
		END

		PORT
			 LAYER M4 ;
			RECT 0.2105 14.2345 23.961 14.2816 ;
		END

		PORT
			 LAYER M4 ;
			RECT 0.2105 126.7067 23.961 126.7537 ;
		END

		PORT
			 LAYER M4 ;
			RECT 0.2105 13.5945 23.961 13.6416 ;
		END

		PORT
			 LAYER M4 ;
			RECT 0.2105 12.9545 23.961 13.0016 ;
		END

		PORT
			 LAYER M4 ;
			RECT 0.2105 12.3145 23.961 12.3616 ;
		END

		PORT
			 LAYER M4 ;
			RECT 0.2105 11.6745 23.961 11.7216 ;
		END

		PORT
			 LAYER M4 ;
			RECT 0.2105 11.0345 23.961 11.0816 ;
		END

		PORT
			 LAYER M4 ;
			RECT 0.2105 10.3945 23.961 10.4416 ;
		END

		PORT
			 LAYER M4 ;
			RECT 0.2105 9.7545 23.961 9.8016 ;
		END

		PORT
			 LAYER M4 ;
			RECT 0.2105 9.1145 23.961 9.1616 ;
		END

		PORT
			 LAYER M4 ;
			RECT 0.2105 8.4745 23.961 8.5216 ;
		END

		PORT
			 LAYER M4 ;
			RECT 0.2105 7.8345 23.961 7.8816 ;
		END

		PORT
			 LAYER M4 ;
			RECT 0.2105 126.0667 23.961 126.1137 ;
		END

		PORT
			 LAYER M4 ;
			RECT 0.2105 7.1945 23.961 7.2416 ;
		END

		PORT
			 LAYER M4 ;
			RECT 0.2105 6.5545 23.961 6.6016 ;
		END

		PORT
			 LAYER M4 ;
			RECT 0.2105 5.9145 23.961 5.9616 ;
		END

		PORT
			 LAYER M4 ;
			RECT 0.2105 5.2745 23.961 5.3216 ;
		END

		PORT
			 LAYER M4 ;
			RECT 0.2105 4.6345 23.961 4.6816 ;
		END

		PORT
			 LAYER M4 ;
			RECT 0.2105 3.9945 23.961 4.0416 ;
		END

		PORT
			 LAYER M4 ;
			RECT 0.2105 3.3545 23.961 3.4016 ;
		END

		PORT
			 LAYER M4 ;
			RECT 0.2105 2.7145 23.961 2.7616 ;
		END

		PORT
			 LAYER M4 ;
			RECT 0.2105 2.0745 23.961 2.1216 ;
		END

		PORT
			 LAYER M4 ;
			RECT 0.2105 1.4345 23.961 1.4816 ;
		END

		PORT
			 LAYER M4 ;
			RECT 0.2105 125.4267 23.961 125.4737 ;
		END

		PORT
			 LAYER M4 ;
			RECT 0.2105 0.7945 23.961 0.8416 ;
		END

		PORT
			 LAYER M4 ;
			RECT 0.2105 124.7867 23.961 124.8337 ;
		END

		PORT
			 LAYER M4 ;
			RECT 0.2105 124.1467 23.961 124.1937 ;
		END

		PORT
			 LAYER M4 ;
			RECT 0.2105 123.5067 23.961 123.5537 ;
		END

		PORT
			 LAYER M4 ;
			RECT 0.2105 122.8667 23.961 122.9137 ;
		END

		PORT
			 LAYER M4 ;
			RECT 0.2105 137.5867 23.961 137.6337 ;
		END

		PORT
			 LAYER M4 ;
			RECT 0.2105 122.2267 23.961 122.2737 ;
		END

		PORT
			 LAYER M4 ;
			RECT 0.2105 121.5867 23.961 121.6337 ;
		END

		PORT
			 LAYER M4 ;
			RECT 0.2105 120.9467 23.961 120.9937 ;
		END

		PORT
			 LAYER M4 ;
			RECT 0.2105 120.3067 23.961 120.3537 ;
		END

		PORT
			 LAYER M4 ;
			RECT 0.2105 119.6667 23.961 119.7137 ;
		END

		PORT
			 LAYER M4 ;
			RECT 0.2105 119.0267 23.961 119.0737 ;
		END

		PORT
			 LAYER M4 ;
			RECT 0.2105 118.3867 23.961 118.4337 ;
		END

		PORT
			 LAYER M4 ;
			RECT 0.2105 138.9835 23.961 139.0149 ;
		END

		PORT
			 LAYER M4 ;
			RECT 0.2105 0.0533 23.961 0.0847 ;
		END

		PORT
			 LAYER M4 ;
			RECT 0.2105 107.4337 23.961 107.4808 ;
		END

		PORT
			 LAYER M4 ;
			RECT 0.2105 31.5875 23.961 31.6345 ;
		END

		PORT
			 LAYER M4 ;
			RECT 0.2105 107.142 23.961 107.189 ;
		END

		PORT
			 LAYER M4 ;
			RECT 0.2105 31.8792 23.961 31.9263 ;
		END

		PORT
			 LAYER M4 ;
			RECT 0.2105 101.1875 23.961 101.2345 ;
		END

		PORT
			 LAYER M4 ;
			RECT 0.2105 37.8337 23.961 37.8808 ;
		END

		PORT
			 LAYER M4 ;
			RECT 0.2105 100.8957 23.961 100.9427 ;
		END

		PORT
			 LAYER M4 ;
			RECT 0.2105 38.1255 23.961 38.1725 ;
		END

		PORT
			 LAYER M4 ;
			RECT 0.2105 108.0125 23.961 108.0439 ;
		END

		PORT
			 LAYER M4 ;
			RECT 0.2105 31.0243 23.961 31.0557 ;
		END

		PORT
			 LAYER M4 ;
			RECT 0.2105 100.4984 23.961 100.5298 ;
		END

		PORT
			 LAYER M4 ;
			RECT 0.2105 38.5384 23.961 38.5698 ;
		END

		PORT
			 LAYER M4 ;
			RECT 0.2105 69.6565 23.961 69.6878 ;
		END

		PORT
			 LAYER M4 ;
			RECT 0.2105 69.3804 23.961 69.4118 ;
		END

		PORT
			 LAYER M4 ;
			RECT 0.2105 138.858 23.961 138.8894 ;
		END

		PORT
			 LAYER M4 ;
			RECT 0.2105 0.1788 23.961 0.2102 ;
		END

	END VDDCE

	PIN VDDPE
		USE POWER ;
		DIRECTION INOUT ;
		PORT
			 LAYER M4 ;
			RECT 0.2105 138.4596 23.961 138.5067 ;
		END

		PORT
			 LAYER M4 ;
			RECT 0.2105 137.1796 23.961 137.2267 ;
		END

		PORT
			 LAYER M4 ;
			RECT 0.2105 117.9796 23.961 118.0267 ;
		END

		PORT
			 LAYER M4 ;
			RECT 0.2105 117.3396 23.961 117.3867 ;
		END

		PORT
			 LAYER M4 ;
			RECT 0.2105 116.6996 23.961 116.7467 ;
		END

		PORT
			 LAYER M4 ;
			RECT 0.2105 116.0596 23.961 116.1067 ;
		END

		PORT
			 LAYER M4 ;
			RECT 0.2105 115.4196 23.961 115.4667 ;
		END

		PORT
			 LAYER M4 ;
			RECT 0.2105 114.7796 23.961 114.8267 ;
		END

		PORT
			 LAYER M4 ;
			RECT 0.2105 114.1396 23.961 114.1867 ;
		END

		PORT
			 LAYER M4 ;
			RECT 0.2105 113.4996 23.961 113.5467 ;
		END

		PORT
			 LAYER M4 ;
			RECT 0.2105 112.8596 23.961 112.9067 ;
		END

		PORT
			 LAYER M4 ;
			RECT 0.2105 112.2196 23.961 112.2667 ;
		END

		PORT
			 LAYER M4 ;
			RECT 0.2105 136.5396 23.961 136.5867 ;
		END

		PORT
			 LAYER M4 ;
			RECT 0.2105 111.5796 23.961 111.6267 ;
		END

		PORT
			 LAYER M4 ;
			RECT 0.2105 110.9396 23.961 110.9867 ;
		END

		PORT
			 LAYER M4 ;
			RECT 0.2105 110.2996 23.961 110.3467 ;
		END

		PORT
			 LAYER M4 ;
			RECT 0.2105 109.6596 23.961 109.7067 ;
		END

		PORT
			 LAYER M4 ;
			RECT 0.2105 109.0196 23.961 109.0667 ;
		END

		PORT
			 LAYER M4 ;
			RECT 0.2105 108.3796 23.961 108.4267 ;
		END

		PORT
			 LAYER M4 ;
			RECT 0.2105 135.8996 23.961 135.9467 ;
		END

		PORT
			 LAYER M4 ;
			RECT 0.2105 100.0408 23.961 100.0878 ;
		END

		PORT
			 LAYER M4 ;
			RECT 0.2105 99.4008 23.961 99.4478 ;
		END

		PORT
			 LAYER M4 ;
			RECT 0.2105 98.7608 23.961 98.8078 ;
		END

		PORT
			 LAYER M4 ;
			RECT 0.2105 135.2596 23.961 135.3067 ;
		END

		PORT
			 LAYER M4 ;
			RECT 0.2105 98.1208 23.961 98.1678 ;
		END

		PORT
			 LAYER M4 ;
			RECT 0.2105 97.4808 23.961 97.5278 ;
		END

		PORT
			 LAYER M4 ;
			RECT 0.2105 96.8408 23.961 96.8878 ;
		END

		PORT
			 LAYER M4 ;
			RECT 0.2105 96.2008 23.961 96.2478 ;
		END

		PORT
			 LAYER M4 ;
			RECT 0.2105 95.5608 23.961 95.6078 ;
		END

		PORT
			 LAYER M4 ;
			RECT 0.2105 94.9208 23.961 94.9678 ;
		END

		PORT
			 LAYER M4 ;
			RECT 0.2105 94.2808 23.961 94.3278 ;
		END

		PORT
			 LAYER M4 ;
			RECT 0.2105 93.6408 23.961 93.6878 ;
		END

		PORT
			 LAYER M4 ;
			RECT 0.2105 93.0008 23.961 93.0478 ;
		END

		PORT
			 LAYER M4 ;
			RECT 0.2105 92.3608 23.961 92.4078 ;
		END

		PORT
			 LAYER M4 ;
			RECT 0.2105 134.6196 23.961 134.6667 ;
		END

		PORT
			 LAYER M4 ;
			RECT 0.2105 91.7208 23.961 91.7678 ;
		END

		PORT
			 LAYER M4 ;
			RECT 0.2105 91.0808 23.961 91.1278 ;
		END

		PORT
			 LAYER M4 ;
			RECT 0.2105 90.4408 23.961 90.4878 ;
		END

		PORT
			 LAYER M4 ;
			RECT 0.2105 89.8008 23.961 89.8478 ;
		END

		PORT
			 LAYER M4 ;
			RECT 0.2105 89.1608 23.961 89.2078 ;
		END

		PORT
			 LAYER M4 ;
			RECT 0.2105 88.5208 23.961 88.5678 ;
		END

		PORT
			 LAYER M4 ;
			RECT 0.2105 87.8808 23.961 87.9278 ;
		END

		PORT
			 LAYER M4 ;
			RECT 0.2105 87.2408 23.961 87.2878 ;
		END

		PORT
			 LAYER M4 ;
			RECT 0.2105 86.6008 23.961 86.6478 ;
		END

		PORT
			 LAYER M4 ;
			RECT 0.2105 85.9608 23.961 86.0078 ;
		END

		PORT
			 LAYER M4 ;
			RECT 0.2105 133.9796 23.961 134.0267 ;
		END

		PORT
			 LAYER M4 ;
			RECT 0.2105 85.3208 23.961 85.3678 ;
		END

		PORT
			 LAYER M4 ;
			RECT 0.2105 84.6808 23.961 84.7278 ;
		END

		PORT
			 LAYER M4 ;
			RECT 0.2105 84.0408 23.961 84.0878 ;
		END

		PORT
			 LAYER M4 ;
			RECT 0.2105 83.4008 23.961 83.4478 ;
		END

		PORT
			 LAYER M4 ;
			RECT 0.2105 82.7608 23.961 82.8078 ;
		END

		PORT
			 LAYER M4 ;
			RECT 0.2105 82.1208 23.961 82.1678 ;
		END

		PORT
			 LAYER M4 ;
			RECT 0.2105 81.4808 23.961 81.5278 ;
		END

		PORT
			 LAYER M4 ;
			RECT 0.2105 80.8408 23.961 80.8878 ;
		END

		PORT
			 LAYER M4 ;
			RECT 0.2105 80.2008 23.961 80.2478 ;
		END

		PORT
			 LAYER M4 ;
			RECT 0.2105 79.5608 23.961 79.6078 ;
		END

		PORT
			 LAYER M4 ;
			RECT 0.2105 133.3396 23.961 133.3867 ;
		END

		PORT
			 LAYER M4 ;
			RECT 0.2105 78.9208 23.961 78.9678 ;
		END

		PORT
			 LAYER M4 ;
			RECT 0.2105 78.2808 23.961 78.3278 ;
		END

		PORT
			 LAYER M4 ;
			RECT 0.2105 77.6408 23.961 77.6878 ;
		END

		PORT
			 LAYER M4 ;
			RECT 0.2105 77.0008 23.961 77.0478 ;
		END

		PORT
			 LAYER M4 ;
			RECT 0.2105 76.3608 23.961 76.4078 ;
		END

		PORT
			 LAYER M4 ;
			RECT 0.2105 75.7208 23.961 75.7678 ;
		END

		PORT
			 LAYER M4 ;
			RECT 0.2105 75.0808 23.961 75.1278 ;
		END

		PORT
			 LAYER M4 ;
			RECT 0.2105 74.4408 23.961 74.4878 ;
		END

		PORT
			 LAYER M4 ;
			RECT 0.2105 73.8008 23.961 73.8478 ;
		END

		PORT
			 LAYER M4 ;
			RECT 0.2105 73.1608 23.961 73.2078 ;
		END

		PORT
			 LAYER M4 ;
			RECT 0.2105 132.6996 23.961 132.7467 ;
		END

		PORT
			 LAYER M4 ;
			RECT 0.2105 72.5208 23.961 72.5678 ;
		END

		PORT
			 LAYER M4 ;
			RECT 0.2105 71.8808 23.961 71.9278 ;
		END

		PORT
			 LAYER M4 ;
			RECT 0.2105 71.2408 23.961 71.2878 ;
		END

		PORT
			 LAYER M4 ;
			RECT 0.2105 70.6008 23.961 70.6478 ;
		END

		PORT
			 LAYER M4 ;
			RECT 0.2105 69.9608 23.961 70.0078 ;
		END

		PORT
			 LAYER M4 ;
			RECT 0.2105 69.0604 23.961 69.1075 ;
		END

		PORT
			 LAYER M4 ;
			RECT 0.2105 68.4204 23.961 68.4675 ;
		END

		PORT
			 LAYER M4 ;
			RECT 0.2105 67.7804 23.961 67.8275 ;
		END

		PORT
			 LAYER M4 ;
			RECT 0.2105 132.0596 23.961 132.1067 ;
		END

		PORT
			 LAYER M4 ;
			RECT 0.2105 67.1404 23.961 67.1875 ;
		END

		PORT
			 LAYER M4 ;
			RECT 0.2105 66.5004 23.961 66.5475 ;
		END

		PORT
			 LAYER M4 ;
			RECT 0.2105 65.8604 23.961 65.9075 ;
		END

		PORT
			 LAYER M4 ;
			RECT 0.2105 65.2204 23.961 65.2675 ;
		END

		PORT
			 LAYER M4 ;
			RECT 0.2105 64.5804 23.961 64.6275 ;
		END

		PORT
			 LAYER M4 ;
			RECT 0.2105 63.9404 23.961 63.9875 ;
		END

		PORT
			 LAYER M4 ;
			RECT 0.2105 63.3004 23.961 63.3475 ;
		END

		PORT
			 LAYER M4 ;
			RECT 0.2105 62.6604 23.961 62.7075 ;
		END

		PORT
			 LAYER M4 ;
			RECT 0.2105 62.0204 23.961 62.0675 ;
		END

		PORT
			 LAYER M4 ;
			RECT 0.2105 61.3804 23.961 61.4275 ;
		END

		PORT
			 LAYER M4 ;
			RECT 0.2105 131.4196 23.961 131.4667 ;
		END

		PORT
			 LAYER M4 ;
			RECT 0.2105 60.7404 23.961 60.7875 ;
		END

		PORT
			 LAYER M4 ;
			RECT 0.2105 60.1004 23.961 60.1475 ;
		END

		PORT
			 LAYER M4 ;
			RECT 0.2105 59.4604 23.961 59.5075 ;
		END

		PORT
			 LAYER M4 ;
			RECT 0.2105 58.8204 23.961 58.8675 ;
		END

		PORT
			 LAYER M4 ;
			RECT 0.2105 58.1804 23.961 58.2275 ;
		END

		PORT
			 LAYER M4 ;
			RECT 0.2105 57.5404 23.961 57.5875 ;
		END

		PORT
			 LAYER M4 ;
			RECT 0.2105 56.9004 23.961 56.9475 ;
		END

		PORT
			 LAYER M4 ;
			RECT 0.2105 56.2604 23.961 56.3075 ;
		END

		PORT
			 LAYER M4 ;
			RECT 0.2105 55.6204 23.961 55.6675 ;
		END

		PORT
			 LAYER M4 ;
			RECT 0.2105 54.9804 23.961 55.0275 ;
		END

		PORT
			 LAYER M4 ;
			RECT 0.2105 130.7796 23.961 130.8267 ;
		END

		PORT
			 LAYER M4 ;
			RECT 0.2105 54.3404 23.961 54.3875 ;
		END

		PORT
			 LAYER M4 ;
			RECT 0.2105 53.7004 23.961 53.7475 ;
		END

		PORT
			 LAYER M4 ;
			RECT 0.2105 53.0604 23.961 53.1075 ;
		END

		PORT
			 LAYER M4 ;
			RECT 0.2105 52.4204 23.961 52.4675 ;
		END

		PORT
			 LAYER M4 ;
			RECT 0.2105 51.7804 23.961 51.8275 ;
		END

		PORT
			 LAYER M4 ;
			RECT 0.2105 51.1404 23.961 51.1875 ;
		END

		PORT
			 LAYER M4 ;
			RECT 0.2105 50.5004 23.961 50.5475 ;
		END

		PORT
			 LAYER M4 ;
			RECT 0.2105 49.8604 23.961 49.9075 ;
		END

		PORT
			 LAYER M4 ;
			RECT 0.2105 49.2204 23.961 49.2675 ;
		END

		PORT
			 LAYER M4 ;
			RECT 0.2105 48.5804 23.961 48.6275 ;
		END

		PORT
			 LAYER M4 ;
			RECT 0.2105 130.1396 23.961 130.1867 ;
		END

		PORT
			 LAYER M4 ;
			RECT 0.2105 47.9404 23.961 47.9875 ;
		END

		PORT
			 LAYER M4 ;
			RECT 0.2105 47.3004 23.961 47.3475 ;
		END

		PORT
			 LAYER M4 ;
			RECT 0.2105 46.6604 23.961 46.7075 ;
		END

		PORT
			 LAYER M4 ;
			RECT 0.2105 46.0204 23.961 46.0675 ;
		END

		PORT
			 LAYER M4 ;
			RECT 0.2105 45.3804 23.961 45.4275 ;
		END

		PORT
			 LAYER M4 ;
			RECT 0.2105 44.7404 23.961 44.7875 ;
		END

		PORT
			 LAYER M4 ;
			RECT 0.2105 44.1004 23.961 44.1475 ;
		END

		PORT
			 LAYER M4 ;
			RECT 0.2105 43.4604 23.961 43.5075 ;
		END

		PORT
			 LAYER M4 ;
			RECT 0.2105 42.8204 23.961 42.8675 ;
		END

		PORT
			 LAYER M4 ;
			RECT 0.2105 42.1804 23.961 42.2275 ;
		END

		PORT
			 LAYER M4 ;
			RECT 0.2105 129.4996 23.961 129.5467 ;
		END

		PORT
			 LAYER M4 ;
			RECT 0.2105 41.5404 23.961 41.5875 ;
		END

		PORT
			 LAYER M4 ;
			RECT 0.2105 40.9004 23.961 40.9475 ;
		END

		PORT
			 LAYER M4 ;
			RECT 0.2105 40.2604 23.961 40.3075 ;
		END

		PORT
			 LAYER M4 ;
			RECT 0.2105 39.6204 23.961 39.6675 ;
		END

		PORT
			 LAYER M4 ;
			RECT 0.2105 38.9804 23.961 39.0275 ;
		END

		PORT
			 LAYER M4 ;
			RECT 0.2105 128.8596 23.961 128.9067 ;
		END

		PORT
			 LAYER M4 ;
			RECT 0.2105 30.6416 23.961 30.6886 ;
		END

		PORT
			 LAYER M4 ;
			RECT 0.2105 30.0016 23.961 30.0486 ;
		END

		PORT
			 LAYER M4 ;
			RECT 0.2105 29.3616 23.961 29.4086 ;
		END

		PORT
			 LAYER M4 ;
			RECT 0.2105 128.2196 23.961 128.2667 ;
		END

		PORT
			 LAYER M4 ;
			RECT 0.2105 28.7216 23.961 28.7686 ;
		END

		PORT
			 LAYER M4 ;
			RECT 0.2105 28.0816 23.961 28.1286 ;
		END

		PORT
			 LAYER M4 ;
			RECT 0.2105 27.4416 23.961 27.4886 ;
		END

		PORT
			 LAYER M4 ;
			RECT 0.2105 26.8016 23.961 26.8486 ;
		END

		PORT
			 LAYER M4 ;
			RECT 0.2105 26.1616 23.961 26.2086 ;
		END

		PORT
			 LAYER M4 ;
			RECT 0.2105 25.5216 23.961 25.5686 ;
		END

		PORT
			 LAYER M4 ;
			RECT 0.2105 24.8816 23.961 24.9286 ;
		END

		PORT
			 LAYER M4 ;
			RECT 0.2105 24.2416 23.961 24.2886 ;
		END

		PORT
			 LAYER M4 ;
			RECT 0.2105 23.6016 23.961 23.6486 ;
		END

		PORT
			 LAYER M4 ;
			RECT 0.2105 22.9616 23.961 23.0086 ;
		END

		PORT
			 LAYER M4 ;
			RECT 0.2105 127.5796 23.961 127.6267 ;
		END

		PORT
			 LAYER M4 ;
			RECT 0.2105 22.3216 23.961 22.3686 ;
		END

		PORT
			 LAYER M4 ;
			RECT 0.2105 21.6816 23.961 21.7286 ;
		END

		PORT
			 LAYER M4 ;
			RECT 0.2105 21.0416 23.961 21.0886 ;
		END

		PORT
			 LAYER M4 ;
			RECT 0.2105 20.4016 23.961 20.4486 ;
		END

		PORT
			 LAYER M4 ;
			RECT 0.2105 19.7616 23.961 19.8086 ;
		END

		PORT
			 LAYER M4 ;
			RECT 0.2105 19.1216 23.961 19.1686 ;
		END

		PORT
			 LAYER M4 ;
			RECT 0.2105 18.4816 23.961 18.5286 ;
		END

		PORT
			 LAYER M4 ;
			RECT 0.2105 17.8416 23.961 17.8886 ;
		END

		PORT
			 LAYER M4 ;
			RECT 0.2105 17.2016 23.961 17.2486 ;
		END

		PORT
			 LAYER M4 ;
			RECT 0.2105 16.5616 23.961 16.6086 ;
		END

		PORT
			 LAYER M4 ;
			RECT 0.2105 126.9396 23.961 126.9867 ;
		END

		PORT
			 LAYER M4 ;
			RECT 0.2105 15.9216 23.961 15.9686 ;
		END

		PORT
			 LAYER M4 ;
			RECT 0.2105 15.2816 23.961 15.3286 ;
		END

		PORT
			 LAYER M4 ;
			RECT 0.2105 14.6416 23.961 14.6886 ;
		END

		PORT
			 LAYER M4 ;
			RECT 0.2105 14.0016 23.961 14.0486 ;
		END

		PORT
			 LAYER M4 ;
			RECT 0.2105 13.3616 23.961 13.4086 ;
		END

		PORT
			 LAYER M4 ;
			RECT 0.2105 12.7216 23.961 12.7686 ;
		END

		PORT
			 LAYER M4 ;
			RECT 0.2105 12.0816 23.961 12.1286 ;
		END

		PORT
			 LAYER M4 ;
			RECT 0.2105 11.4416 23.961 11.4886 ;
		END

		PORT
			 LAYER M4 ;
			RECT 0.2105 10.8016 23.961 10.8486 ;
		END

		PORT
			 LAYER M4 ;
			RECT 0.2105 10.1616 23.961 10.2086 ;
		END

		PORT
			 LAYER M4 ;
			RECT 0.2105 126.2996 23.961 126.3467 ;
		END

		PORT
			 LAYER M4 ;
			RECT 0.2105 9.5216 23.961 9.5686 ;
		END

		PORT
			 LAYER M4 ;
			RECT 0.2105 8.8816 23.961 8.9286 ;
		END

		PORT
			 LAYER M4 ;
			RECT 0.2105 8.2416 23.961 8.2886 ;
		END

		PORT
			 LAYER M4 ;
			RECT 0.2105 7.6016 23.961 7.6486 ;
		END

		PORT
			 LAYER M4 ;
			RECT 0.2105 6.9616 23.961 7.0086 ;
		END

		PORT
			 LAYER M4 ;
			RECT 0.2105 6.3216 23.961 6.3686 ;
		END

		PORT
			 LAYER M4 ;
			RECT 0.2105 5.6816 23.961 5.7286 ;
		END

		PORT
			 LAYER M4 ;
			RECT 0.2105 5.0416 23.961 5.0886 ;
		END

		PORT
			 LAYER M4 ;
			RECT 0.2105 4.4016 23.961 4.4486 ;
		END

		PORT
			 LAYER M4 ;
			RECT 0.2105 3.7616 23.961 3.8086 ;
		END

		PORT
			 LAYER M4 ;
			RECT 0.2105 125.6596 23.961 125.7067 ;
		END

		PORT
			 LAYER M4 ;
			RECT 0.2105 3.1216 23.961 3.1686 ;
		END

		PORT
			 LAYER M4 ;
			RECT 0.2105 2.4816 23.961 2.5286 ;
		END

		PORT
			 LAYER M4 ;
			RECT 0.2105 1.8416 23.961 1.8886 ;
		END

		PORT
			 LAYER M4 ;
			RECT 0.2105 1.2016 23.961 1.2486 ;
		END

		PORT
			 LAYER M4 ;
			RECT 0.2105 0.5616 23.961 0.6086 ;
		END

		PORT
			 LAYER M4 ;
			RECT 0.2105 125.0196 23.961 125.0667 ;
		END

		PORT
			 LAYER M4 ;
			RECT 0.2105 137.8196 23.961 137.8667 ;
		END

		PORT
			 LAYER M4 ;
			RECT 0.2105 124.3796 23.961 124.4267 ;
		END

		PORT
			 LAYER M4 ;
			RECT 0.2105 123.7396 23.961 123.7867 ;
		END

		PORT
			 LAYER M4 ;
			RECT 0.2105 123.0996 23.961 123.1467 ;
		END

		PORT
			 LAYER M4 ;
			RECT 0.2105 122.4596 23.961 122.5067 ;
		END

		PORT
			 LAYER M4 ;
			RECT 0.2105 121.8196 23.961 121.8667 ;
		END

		PORT
			 LAYER M4 ;
			RECT 0.2105 121.1796 23.961 121.2267 ;
		END

		PORT
			 LAYER M4 ;
			RECT 0.2105 120.5396 23.961 120.5867 ;
		END

		PORT
			 LAYER M4 ;
			RECT 0.2105 119.8996 23.961 119.9467 ;
		END

		PORT
			 LAYER M4 ;
			RECT 0.2105 119.2596 23.961 119.3067 ;
		END

		PORT
			 LAYER M4 ;
			RECT 0.2105 118.6196 23.961 118.6667 ;
		END

		PORT
			 LAYER M4 ;
			RECT 0.2105 107.7929 23.961 107.84 ;
		END

		PORT
			 LAYER M4 ;
			RECT 0.2105 31.2282 23.961 31.2753 ;
		END

		PORT
			 LAYER M4 ;
			RECT 0.2105 107.3553 23.961 107.4024 ;
		END

		PORT
			 LAYER M4 ;
			RECT 0.2105 31.6659 23.961 31.7129 ;
		END

		PORT
			 LAYER M4 ;
			RECT 0.2105 107.0635 23.961 107.1106 ;
		END

		PORT
			 LAYER M4 ;
			RECT 0.2105 31.9576 23.961 32.0047 ;
		END

		PORT
			 LAYER M4 ;
			RECT 0.2105 106.5365 23.961 106.5835 ;
		END

		PORT
			 LAYER M4 ;
			RECT 0.2105 32.4847 23.961 32.5318 ;
		END

		PORT
			 LAYER M4 ;
			RECT 0.2105 106.0094 23.961 106.0565 ;
		END

		PORT
			 LAYER M4 ;
			RECT 0.2105 33.0118 23.961 33.0588 ;
		END

		PORT
			 LAYER M4 ;
			RECT 0.2105 105.4824 23.961 105.5294 ;
		END

		PORT
			 LAYER M4 ;
			RECT 0.2105 33.5388 23.961 33.5859 ;
		END

		PORT
			 LAYER M4 ;
			RECT 0.2105 104.9553 23.961 105.0024 ;
		END

		PORT
			 LAYER M4 ;
			RECT 0.2105 34.0659 23.961 34.1129 ;
		END

		PORT
			 LAYER M4 ;
			RECT 0.2105 103.9012 23.961 103.9482 ;
		END

		PORT
			 LAYER M4 ;
			RECT 0.2105 35.12 23.961 35.1671 ;
		END

		PORT
			 LAYER M4 ;
			RECT 0.2105 102.8471 23.961 102.8941 ;
		END

		PORT
			 LAYER M4 ;
			RECT 0.2105 36.1741 23.961 36.2212 ;
		END

		PORT
			 LAYER M4 ;
			RECT 0.2105 102.32 23.961 102.3671 ;
		END

		PORT
			 LAYER M4 ;
			RECT 0.2105 36.7012 23.961 36.7482 ;
		END

		PORT
			 LAYER M4 ;
			RECT 0.2105 101.7929 23.961 101.84 ;
		END

		PORT
			 LAYER M4 ;
			RECT 0.2105 37.2282 23.961 37.2753 ;
		END

		PORT
			 LAYER M4 ;
			RECT 0.2105 101.2659 23.961 101.3129 ;
		END

		PORT
			 LAYER M4 ;
			RECT 0.2105 37.7553 23.961 37.8024 ;
		END

		PORT
			 LAYER M4 ;
			RECT 0.2105 100.9741 23.961 101.0212 ;
		END

		PORT
			 LAYER M4 ;
			RECT 0.2105 38.0471 23.961 38.0941 ;
		END

		PORT
			 LAYER M4 ;
			RECT 0.2105 107.9498 23.961 107.9812 ;
		END

		PORT
			 LAYER M4 ;
			RECT 0.2105 31.0871 23.961 31.1184 ;
		END

		PORT
			 LAYER M4 ;
			RECT 0.2105 100.5612 23.961 100.5925 ;
		END

		PORT
			 LAYER M4 ;
			RECT 0.2105 38.4757 23.961 38.5071 ;
		END

		PORT
			 LAYER M4 ;
			RECT 0.2105 69.5184 23.961 69.5498 ;
		END

	END VDDPE

	PIN VSSE
		USE GROUND ;
		DIRECTION INOUT ;
		PORT
			 LAYER M4 ;
			RECT 0.2105 108.0753 23.961 108.1067 ;
		END

		PORT
			 LAYER M4 ;
			RECT 0.2105 30.9616 23.961 30.9929 ;
		END

		PORT
			 LAYER M4 ;
			RECT 0.2105 100.4357 23.961 100.4671 ;
		END

		PORT
			 LAYER M4 ;
			RECT 0.2105 38.6012 23.961 38.6325 ;
		END

		PORT
			 LAYER M4 ;
			RECT 0.2105 138.9208 23.961 138.9522 ;
		END

		PORT
			 LAYER M4 ;
			RECT 0.2105 0.1161 23.961 0.1475 ;
		END

		PORT
			 LAYER M4 ;
			RECT 0.2105 69.5937 23.961 69.6251 ;
		END

		PORT
			 LAYER M4 ;
			RECT 0.2105 69.4431 23.961 69.4745 ;
		END

		PORT
			 LAYER M4 ;
			RECT 0.2105 101.109 23.961 101.1561 ;
		END

		PORT
			 LAYER M4 ;
			RECT 0.2105 37.9122 23.961 37.9592 ;
		END

		PORT
			 LAYER M4 ;
			RECT 0.2105 107.8714 23.961 107.9184 ;
		END

		PORT
			 LAYER M4 ;
			RECT 0.2105 31.1498 23.961 31.1969 ;
		END

		PORT
			 LAYER M4 ;
			RECT 0.2105 107.2204 23.961 107.2675 ;
		END

		PORT
			 LAYER M4 ;
			RECT 0.2105 31.8008 23.961 31.8478 ;
		END

		PORT
			 LAYER M4 ;
			RECT 0.2105 106.6149 23.961 106.662 ;
		END

		PORT
			 LAYER M4 ;
			RECT 0.2105 32.4063 23.961 32.4533 ;
		END

		PORT
			 LAYER M4 ;
			RECT 0.2105 106.0878 23.961 106.1349 ;
		END

		PORT
			 LAYER M4 ;
			RECT 0.2105 32.9333 23.961 32.9804 ;
		END

		PORT
			 LAYER M4 ;
			RECT 0.2105 105.5608 23.961 105.6078 ;
		END

		PORT
			 LAYER M4 ;
			RECT 0.2105 33.4604 23.961 33.5075 ;
		END

		PORT
			 LAYER M4 ;
			RECT 0.2105 105.0337 23.961 105.0808 ;
		END

		PORT
			 LAYER M4 ;
			RECT 0.2105 33.9875 23.961 34.0345 ;
		END

		PORT
			 LAYER M4 ;
			RECT 0.2105 103.9796 23.961 104.0267 ;
		END

		PORT
			 LAYER M4 ;
			RECT 0.2105 35.0416 23.961 35.0886 ;
		END

		PORT
			 LAYER M4 ;
			RECT 0.2105 102.9255 23.961 102.9725 ;
		END

		PORT
			 LAYER M4 ;
			RECT 0.2105 36.0957 23.961 36.1427 ;
		END

		PORT
			 LAYER M4 ;
			RECT 0.2105 102.3984 23.961 102.4455 ;
		END

		PORT
			 LAYER M4 ;
			RECT 0.2105 36.6227 23.961 36.6698 ;
		END

		PORT
			 LAYER M4 ;
			RECT 0.2105 101.8714 23.961 101.9184 ;
		END

		PORT
			 LAYER M4 ;
			RECT 0.2105 37.1498 23.961 37.1969 ;
		END

		PORT
			 LAYER M4 ;
			RECT 0.2105 101.3443 23.961 101.3914 ;
		END

		PORT
			 LAYER M4 ;
			RECT 0.2105 37.6769 23.961 37.7239 ;
		END

		PORT
			 LAYER M4 ;
			RECT 0.2105 138.771 23.961 138.818 ;
		END

		PORT
			 LAYER M4 ;
			RECT 0.2105 117.651 23.961 117.698 ;
		END

		PORT
			 LAYER M4 ;
			RECT 0.2105 117.011 23.961 117.058 ;
		END

		PORT
			 LAYER M4 ;
			RECT 0.2105 116.371 23.961 116.418 ;
		END

		PORT
			 LAYER M4 ;
			RECT 0.2105 115.731 23.961 115.778 ;
		END

		PORT
			 LAYER M4 ;
			RECT 0.2105 115.091 23.961 115.138 ;
		END

		PORT
			 LAYER M4 ;
			RECT 0.2105 114.451 23.961 114.498 ;
		END

		PORT
			 LAYER M4 ;
			RECT 0.2105 136.851 23.961 136.898 ;
		END

		PORT
			 LAYER M4 ;
			RECT 0.2105 113.811 23.961 113.858 ;
		END

		PORT
			 LAYER M4 ;
			RECT 0.2105 113.171 23.961 113.218 ;
		END

		PORT
			 LAYER M4 ;
			RECT 0.2105 112.531 23.961 112.578 ;
		END

		PORT
			 LAYER M4 ;
			RECT 0.2105 111.891 23.961 111.938 ;
		END

		PORT
			 LAYER M4 ;
			RECT 0.2105 111.251 23.961 111.298 ;
		END

		PORT
			 LAYER M4 ;
			RECT 0.2105 110.611 23.961 110.658 ;
		END

		PORT
			 LAYER M4 ;
			RECT 0.2105 109.971 23.961 110.018 ;
		END

		PORT
			 LAYER M4 ;
			RECT 0.2105 109.331 23.961 109.378 ;
		END

		PORT
			 LAYER M4 ;
			RECT 0.2105 108.691 23.961 108.738 ;
		END

		PORT
			 LAYER M4 ;
			RECT 0.2105 136.211 23.961 136.258 ;
		END

		PORT
			 LAYER M4 ;
			RECT 0.2105 135.571 23.961 135.618 ;
		END

		PORT
			 LAYER M4 ;
			RECT 0.2105 100.3522 23.961 100.3992 ;
		END

		PORT
			 LAYER M4 ;
			RECT 0.2105 99.7122 23.961 99.7592 ;
		END

		PORT
			 LAYER M4 ;
			RECT 0.2105 99.0722 23.961 99.1192 ;
		END

		PORT
			 LAYER M4 ;
			RECT 0.2105 98.4322 23.961 98.4792 ;
		END

		PORT
			 LAYER M4 ;
			RECT 0.2105 97.7922 23.961 97.8392 ;
		END

		PORT
			 LAYER M4 ;
			RECT 0.2105 97.1522 23.961 97.1992 ;
		END

		PORT
			 LAYER M4 ;
			RECT 0.2105 96.5122 23.961 96.5592 ;
		END

		PORT
			 LAYER M4 ;
			RECT 0.2105 95.8722 23.961 95.9192 ;
		END

		PORT
			 LAYER M4 ;
			RECT 0.2105 95.2322 23.961 95.2792 ;
		END

		PORT
			 LAYER M4 ;
			RECT 0.2105 94.5922 23.961 94.6392 ;
		END

		PORT
			 LAYER M4 ;
			RECT 0.2105 134.931 23.961 134.978 ;
		END

		PORT
			 LAYER M4 ;
			RECT 0.2105 93.9522 23.961 93.9992 ;
		END

		PORT
			 LAYER M4 ;
			RECT 0.2105 93.3122 23.961 93.3592 ;
		END

		PORT
			 LAYER M4 ;
			RECT 0.2105 92.6722 23.961 92.7192 ;
		END

		PORT
			 LAYER M4 ;
			RECT 0.2105 92.0322 23.961 92.0792 ;
		END

		PORT
			 LAYER M4 ;
			RECT 0.2105 91.3922 23.961 91.4392 ;
		END

		PORT
			 LAYER M4 ;
			RECT 0.2105 90.7522 23.961 90.7992 ;
		END

		PORT
			 LAYER M4 ;
			RECT 0.2105 90.1122 23.961 90.1592 ;
		END

		PORT
			 LAYER M4 ;
			RECT 0.2105 89.4722 23.961 89.5192 ;
		END

		PORT
			 LAYER M4 ;
			RECT 0.2105 88.8322 23.961 88.8792 ;
		END

		PORT
			 LAYER M4 ;
			RECT 0.2105 88.1922 23.961 88.2392 ;
		END

		PORT
			 LAYER M4 ;
			RECT 0.2105 134.291 23.961 134.338 ;
		END

		PORT
			 LAYER M4 ;
			RECT 0.2105 87.5522 23.961 87.5992 ;
		END

		PORT
			 LAYER M4 ;
			RECT 0.2105 86.9122 23.961 86.9592 ;
		END

		PORT
			 LAYER M4 ;
			RECT 0.2105 86.2722 23.961 86.3192 ;
		END

		PORT
			 LAYER M4 ;
			RECT 0.2105 85.6322 23.961 85.6792 ;
		END

		PORT
			 LAYER M4 ;
			RECT 0.2105 84.9922 23.961 85.0392 ;
		END

		PORT
			 LAYER M4 ;
			RECT 0.2105 84.3522 23.961 84.3992 ;
		END

		PORT
			 LAYER M4 ;
			RECT 0.2105 83.7122 23.961 83.7592 ;
		END

		PORT
			 LAYER M4 ;
			RECT 0.2105 83.0722 23.961 83.1192 ;
		END

		PORT
			 LAYER M4 ;
			RECT 0.2105 82.4322 23.961 82.4792 ;
		END

		PORT
			 LAYER M4 ;
			RECT 0.2105 81.7922 23.961 81.8392 ;
		END

		PORT
			 LAYER M4 ;
			RECT 0.2105 133.651 23.961 133.698 ;
		END

		PORT
			 LAYER M4 ;
			RECT 0.2105 81.1522 23.961 81.1992 ;
		END

		PORT
			 LAYER M4 ;
			RECT 0.2105 80.5122 23.961 80.5592 ;
		END

		PORT
			 LAYER M4 ;
			RECT 0.2105 79.8722 23.961 79.9192 ;
		END

		PORT
			 LAYER M4 ;
			RECT 0.2105 79.2322 23.961 79.2792 ;
		END

		PORT
			 LAYER M4 ;
			RECT 0.2105 78.5922 23.961 78.6392 ;
		END

		PORT
			 LAYER M4 ;
			RECT 0.2105 77.9522 23.961 77.9992 ;
		END

		PORT
			 LAYER M4 ;
			RECT 0.2105 77.3122 23.961 77.3592 ;
		END

		PORT
			 LAYER M4 ;
			RECT 0.2105 76.6722 23.961 76.7192 ;
		END

		PORT
			 LAYER M4 ;
			RECT 0.2105 76.0322 23.961 76.0792 ;
		END

		PORT
			 LAYER M4 ;
			RECT 0.2105 75.3922 23.961 75.4392 ;
		END

		PORT
			 LAYER M4 ;
			RECT 0.2105 133.011 23.961 133.058 ;
		END

		PORT
			 LAYER M4 ;
			RECT 0.2105 74.7522 23.961 74.7992 ;
		END

		PORT
			 LAYER M4 ;
			RECT 0.2105 74.1122 23.961 74.1592 ;
		END

		PORT
			 LAYER M4 ;
			RECT 0.2105 73.4722 23.961 73.5192 ;
		END

		PORT
			 LAYER M4 ;
			RECT 0.2105 72.8322 23.961 72.8792 ;
		END

		PORT
			 LAYER M4 ;
			RECT 0.2105 72.1922 23.961 72.2392 ;
		END

		PORT
			 LAYER M4 ;
			RECT 0.2105 71.5522 23.961 71.5992 ;
		END

		PORT
			 LAYER M4 ;
			RECT 0.2105 70.9122 23.961 70.9592 ;
		END

		PORT
			 LAYER M4 ;
			RECT 0.2105 70.2722 23.961 70.3192 ;
		END

		PORT
			 LAYER M4 ;
			RECT 0.2105 132.371 23.961 132.418 ;
		END

		PORT
			 LAYER M4 ;
			RECT 0.2105 68.749 23.961 68.7961 ;
		END

		PORT
			 LAYER M4 ;
			RECT 0.2105 68.109 23.961 68.1561 ;
		END

		PORT
			 LAYER M4 ;
			RECT 0.2105 67.469 23.961 67.5161 ;
		END

		PORT
			 LAYER M4 ;
			RECT 0.2105 66.829 23.961 66.8761 ;
		END

		PORT
			 LAYER M4 ;
			RECT 0.2105 66.189 23.961 66.2361 ;
		END

		PORT
			 LAYER M4 ;
			RECT 0.2105 65.549 23.961 65.5961 ;
		END

		PORT
			 LAYER M4 ;
			RECT 0.2105 64.909 23.961 64.9561 ;
		END

		PORT
			 LAYER M4 ;
			RECT 0.2105 64.269 23.961 64.3161 ;
		END

		PORT
			 LAYER M4 ;
			RECT 0.2105 63.629 23.961 63.6761 ;
		END

		PORT
			 LAYER M4 ;
			RECT 0.2105 131.731 23.961 131.778 ;
		END

		PORT
			 LAYER M4 ;
			RECT 0.2105 62.989 23.961 63.0361 ;
		END

		PORT
			 LAYER M4 ;
			RECT 0.2105 62.349 23.961 62.3961 ;
		END

		PORT
			 LAYER M4 ;
			RECT 0.2105 61.709 23.961 61.7561 ;
		END

		PORT
			 LAYER M4 ;
			RECT 0.2105 61.069 23.961 61.1161 ;
		END

		PORT
			 LAYER M4 ;
			RECT 0.2105 60.429 23.961 60.4761 ;
		END

		PORT
			 LAYER M4 ;
			RECT 0.2105 59.789 23.961 59.8361 ;
		END

		PORT
			 LAYER M4 ;
			RECT 0.2105 59.149 23.961 59.1961 ;
		END

		PORT
			 LAYER M4 ;
			RECT 0.2105 58.509 23.961 58.5561 ;
		END

		PORT
			 LAYER M4 ;
			RECT 0.2105 57.869 23.961 57.9161 ;
		END

		PORT
			 LAYER M4 ;
			RECT 0.2105 57.229 23.961 57.2761 ;
		END

		PORT
			 LAYER M4 ;
			RECT 0.2105 131.091 23.961 131.138 ;
		END

		PORT
			 LAYER M4 ;
			RECT 0.2105 56.589 23.961 56.6361 ;
		END

		PORT
			 LAYER M4 ;
			RECT 0.2105 55.949 23.961 55.9961 ;
		END

		PORT
			 LAYER M4 ;
			RECT 0.2105 55.309 23.961 55.3561 ;
		END

		PORT
			 LAYER M4 ;
			RECT 0.2105 54.669 23.961 54.7161 ;
		END

		PORT
			 LAYER M4 ;
			RECT 0.2105 54.029 23.961 54.0761 ;
		END

		PORT
			 LAYER M4 ;
			RECT 0.2105 53.389 23.961 53.4361 ;
		END

		PORT
			 LAYER M4 ;
			RECT 0.2105 52.749 23.961 52.7961 ;
		END

		PORT
			 LAYER M4 ;
			RECT 0.2105 52.109 23.961 52.1561 ;
		END

		PORT
			 LAYER M4 ;
			RECT 0.2105 51.469 23.961 51.5161 ;
		END

		PORT
			 LAYER M4 ;
			RECT 0.2105 50.829 23.961 50.8761 ;
		END

		PORT
			 LAYER M4 ;
			RECT 0.2105 130.451 23.961 130.498 ;
		END

		PORT
			 LAYER M4 ;
			RECT 0.2105 50.189 23.961 50.2361 ;
		END

		PORT
			 LAYER M4 ;
			RECT 0.2105 49.549 23.961 49.5961 ;
		END

		PORT
			 LAYER M4 ;
			RECT 0.2105 48.909 23.961 48.9561 ;
		END

		PORT
			 LAYER M4 ;
			RECT 0.2105 48.269 23.961 48.3161 ;
		END

		PORT
			 LAYER M4 ;
			RECT 0.2105 47.629 23.961 47.6761 ;
		END

		PORT
			 LAYER M4 ;
			RECT 0.2105 46.989 23.961 47.0361 ;
		END

		PORT
			 LAYER M4 ;
			RECT 0.2105 46.349 23.961 46.3961 ;
		END

		PORT
			 LAYER M4 ;
			RECT 0.2105 45.709 23.961 45.7561 ;
		END

		PORT
			 LAYER M4 ;
			RECT 0.2105 45.069 23.961 45.1161 ;
		END

		PORT
			 LAYER M4 ;
			RECT 0.2105 44.429 23.961 44.4761 ;
		END

		PORT
			 LAYER M4 ;
			RECT 0.2105 129.811 23.961 129.858 ;
		END

		PORT
			 LAYER M4 ;
			RECT 0.2105 43.789 23.961 43.8361 ;
		END

		PORT
			 LAYER M4 ;
			RECT 0.2105 43.149 23.961 43.1961 ;
		END

		PORT
			 LAYER M4 ;
			RECT 0.2105 42.509 23.961 42.5561 ;
		END

		PORT
			 LAYER M4 ;
			RECT 0.2105 41.869 23.961 41.9161 ;
		END

		PORT
			 LAYER M4 ;
			RECT 0.2105 41.229 23.961 41.2761 ;
		END

		PORT
			 LAYER M4 ;
			RECT 0.2105 40.589 23.961 40.6361 ;
		END

		PORT
			 LAYER M4 ;
			RECT 0.2105 39.949 23.961 39.9961 ;
		END

		PORT
			 LAYER M4 ;
			RECT 0.2105 39.309 23.961 39.3561 ;
		END

		PORT
			 LAYER M4 ;
			RECT 0.2105 38.669 23.961 38.7161 ;
		END

		PORT
			 LAYER M4 ;
			RECT 0.2105 129.171 23.961 129.218 ;
		END

		PORT
			 LAYER M4 ;
			RECT 0.2105 128.531 23.961 128.578 ;
		END

		PORT
			 LAYER M4 ;
			RECT 0.2105 30.3302 23.961 30.3773 ;
		END

		PORT
			 LAYER M4 ;
			RECT 0.2105 29.6902 23.961 29.7373 ;
		END

		PORT
			 LAYER M4 ;
			RECT 0.2105 29.0502 23.961 29.0973 ;
		END

		PORT
			 LAYER M4 ;
			RECT 0.2105 28.4102 23.961 28.4573 ;
		END

		PORT
			 LAYER M4 ;
			RECT 0.2105 27.7702 23.961 27.8173 ;
		END

		PORT
			 LAYER M4 ;
			RECT 0.2105 27.1302 23.961 27.1773 ;
		END

		PORT
			 LAYER M4 ;
			RECT 0.2105 26.4902 23.961 26.5373 ;
		END

		PORT
			 LAYER M4 ;
			RECT 0.2105 25.8502 23.961 25.8973 ;
		END

		PORT
			 LAYER M4 ;
			RECT 0.2105 25.2102 23.961 25.2573 ;
		END

		PORT
			 LAYER M4 ;
			RECT 0.2105 24.5702 23.961 24.6173 ;
		END

		PORT
			 LAYER M4 ;
			RECT 0.2105 127.891 23.961 127.938 ;
		END

		PORT
			 LAYER M4 ;
			RECT 0.2105 23.9302 23.961 23.9773 ;
		END

		PORT
			 LAYER M4 ;
			RECT 0.2105 23.2902 23.961 23.3373 ;
		END

		PORT
			 LAYER M4 ;
			RECT 0.2105 22.6502 23.961 22.6973 ;
		END

		PORT
			 LAYER M4 ;
			RECT 0.2105 22.0102 23.961 22.0573 ;
		END

		PORT
			 LAYER M4 ;
			RECT 0.2105 21.3702 23.961 21.4173 ;
		END

		PORT
			 LAYER M4 ;
			RECT 0.2105 20.7302 23.961 20.7773 ;
		END

		PORT
			 LAYER M4 ;
			RECT 0.2105 20.0902 23.961 20.1373 ;
		END

		PORT
			 LAYER M4 ;
			RECT 0.2105 19.4502 23.961 19.4973 ;
		END

		PORT
			 LAYER M4 ;
			RECT 0.2105 18.8102 23.961 18.8573 ;
		END

		PORT
			 LAYER M4 ;
			RECT 0.2105 18.1702 23.961 18.2173 ;
		END

		PORT
			 LAYER M4 ;
			RECT 0.2105 127.251 23.961 127.298 ;
		END

		PORT
			 LAYER M4 ;
			RECT 0.2105 17.5302 23.961 17.5773 ;
		END

		PORT
			 LAYER M4 ;
			RECT 0.2105 16.8902 23.961 16.9373 ;
		END

		PORT
			 LAYER M4 ;
			RECT 0.2105 16.2502 23.961 16.2973 ;
		END

		PORT
			 LAYER M4 ;
			RECT 0.2105 15.6102 23.961 15.6573 ;
		END

		PORT
			 LAYER M4 ;
			RECT 0.2105 14.9702 23.961 15.0173 ;
		END

		PORT
			 LAYER M4 ;
			RECT 0.2105 14.3302 23.961 14.3773 ;
		END

		PORT
			 LAYER M4 ;
			RECT 0.2105 13.6902 23.961 13.7373 ;
		END

		PORT
			 LAYER M4 ;
			RECT 0.2105 13.0502 23.961 13.0973 ;
		END

		PORT
			 LAYER M4 ;
			RECT 0.2105 12.4102 23.961 12.4573 ;
		END

		PORT
			 LAYER M4 ;
			RECT 0.2105 11.7702 23.961 11.8173 ;
		END

		PORT
			 LAYER M4 ;
			RECT 0.2105 138.131 23.961 138.178 ;
		END

		PORT
			 LAYER M4 ;
			RECT 0.2105 126.611 23.961 126.658 ;
		END

		PORT
			 LAYER M4 ;
			RECT 0.2105 11.1302 23.961 11.1773 ;
		END

		PORT
			 LAYER M4 ;
			RECT 0.2105 10.4902 23.961 10.5373 ;
		END

		PORT
			 LAYER M4 ;
			RECT 0.2105 9.8502 23.961 9.8973 ;
		END

		PORT
			 LAYER M4 ;
			RECT 0.2105 9.2102 23.961 9.2573 ;
		END

		PORT
			 LAYER M4 ;
			RECT 0.2105 8.5702 23.961 8.6173 ;
		END

		PORT
			 LAYER M4 ;
			RECT 0.2105 7.9302 23.961 7.9773 ;
		END

		PORT
			 LAYER M4 ;
			RECT 0.2105 7.2902 23.961 7.3373 ;
		END

		PORT
			 LAYER M4 ;
			RECT 0.2105 6.6502 23.961 6.6973 ;
		END

		PORT
			 LAYER M4 ;
			RECT 0.2105 6.0102 23.961 6.0573 ;
		END

		PORT
			 LAYER M4 ;
			RECT 0.2105 5.3702 23.961 5.4173 ;
		END

		PORT
			 LAYER M4 ;
			RECT 0.2105 125.971 23.961 126.018 ;
		END

		PORT
			 LAYER M4 ;
			RECT 0.2105 4.7302 23.961 4.7773 ;
		END

		PORT
			 LAYER M4 ;
			RECT 0.2105 4.0902 23.961 4.1373 ;
		END

		PORT
			 LAYER M4 ;
			RECT 0.2105 3.4502 23.961 3.4973 ;
		END

		PORT
			 LAYER M4 ;
			RECT 0.2105 2.8102 23.961 2.8573 ;
		END

		PORT
			 LAYER M4 ;
			RECT 0.2105 2.1702 23.961 2.2173 ;
		END

		PORT
			 LAYER M4 ;
			RECT 0.2105 1.5302 23.961 1.5773 ;
		END

		PORT
			 LAYER M4 ;
			RECT 0.2105 0.8902 23.961 0.9373 ;
		END

		PORT
			 LAYER M4 ;
			RECT 0.2105 0.2502 23.961 0.2973 ;
		END

		PORT
			 LAYER M4 ;
			RECT 0.2105 125.331 23.961 125.378 ;
		END

		PORT
			 LAYER M4 ;
			RECT 0.2105 124.691 23.961 124.738 ;
		END

		PORT
			 LAYER M4 ;
			RECT 0.2105 124.051 23.961 124.098 ;
		END

		PORT
			 LAYER M4 ;
			RECT 0.2105 123.411 23.961 123.458 ;
		END

		PORT
			 LAYER M4 ;
			RECT 0.2105 122.771 23.961 122.818 ;
		END

		PORT
			 LAYER M4 ;
			RECT 0.2105 122.131 23.961 122.178 ;
		END

		PORT
			 LAYER M4 ;
			RECT 0.2105 121.491 23.961 121.538 ;
		END

		PORT
			 LAYER M4 ;
			RECT 0.2105 120.851 23.961 120.898 ;
		END

		PORT
			 LAYER M4 ;
			RECT 0.2105 137.491 23.961 137.538 ;
		END

		PORT
			 LAYER M4 ;
			RECT 0.2105 120.211 23.961 120.258 ;
		END

		PORT
			 LAYER M4 ;
			RECT 0.2105 119.571 23.961 119.618 ;
		END

		PORT
			 LAYER M4 ;
			RECT 0.2105 118.931 23.961 118.978 ;
		END

		PORT
			 LAYER M4 ;
			RECT 0.2105 118.291 23.961 118.338 ;
		END

	END VSSE

	PIN WABL
		USE SIGNAL ;
		DIRECTION INPUT ;
		SHAPE ABUTMENT ;
		PORT
			 LAYER M2 ;
			RECT 0.0714 68.1725 0.1097 68.2102 ;
			 LAYER M3 ;
			RECT 0.0714 68.1725 0.1097 68.2729 ;
			 LAYER V2 ;
			RECT 0.0831 68.1847 0.098 68.1973 ;
		END

		ANTENNAGATEAREA 0.00027817 ;
		ANTENNADIFFAREA 0.00194719 ;
		ANTENNAPARTIALMETALAREA 0.00195671 ;
	END WABL

	PIN WABLM[0]
		USE SIGNAL ;
		DIRECTION INPUT ;
		SHAPE ABUTMENT ;
		PORT
			 LAYER M2 ;
			RECT 0.0714 68.3984 0.1097 68.4361 ;
			 LAYER M3 ;
			RECT 0.0714 68.3984 0.1097 68.4988 ;
			 LAYER V2 ;
			RECT 0.0831 68.4106 0.098 68.4231 ;
		END

		ANTENNAGATEAREA 0.00027817 ;
		ANTENNADIFFAREA 0.00194719 ;
		ANTENNAPARTIALMETALAREA 0.00195671 ;
	END WABLM[0]

	PIN WABLM[1]
		USE SIGNAL ;
		DIRECTION INPUT ;
		SHAPE ABUTMENT ;
		PORT
			 LAYER M2 ;
			RECT 0.0098 68.9882 0.0481 69.0259 ;
			 LAYER M3 ;
			RECT 0.0098 68.9255 0.0481 69.0259 ;
			 LAYER V2 ;
			RECT 0.0215 69.0004 0.0364 69.0129 ;
		END

		ANTENNAGATEAREA 0.00027817 ;
		ANTENNADIFFAREA 0.00194719 ;
		ANTENNAPARTIALMETALAREA 0.00195671 ;
	END WABLM[1]

	PIN WENY[0]
		USE SIGNAL ;
		DIRECTION OUTPUT ;
		SHAPE ABUTMENT ;
		PORT
			 LAYER M2 ;
			RECT 0.0098 1.2424 0.0481 1.3427 ;
			 LAYER M3 ;
			RECT 0.0098 1.2424 0.0481 1.3427 ;
			 LAYER V2 ;
			RECT 0.021 1.2553 0.0359 1.2678 ;
		END

		ANTENNADIFFAREA 0.00194719 ;
		ANTENNAPARTIALMETALAREA 0.00195671 ;
	END WENY[0]

	PIN WENY[10]
		USE SIGNAL ;
		DIRECTION OUTPUT ;
		SHAPE ABUTMENT ;
		PORT
			 LAYER M2 ;
			RECT 0.0098 14.0424 0.0481 14.1427 ;
			 LAYER M3 ;
			RECT 0.0098 14.0424 0.0481 14.1427 ;
			 LAYER V2 ;
			RECT 0.021 14.0553 0.0359 14.0678 ;
		END

		ANTENNADIFFAREA 0.00194719 ;
		ANTENNAPARTIALMETALAREA 0.00195671 ;
	END WENY[10]

	PIN WENY[11]
		USE SIGNAL ;
		DIRECTION OUTPUT ;
		SHAPE ABUTMENT ;
		PORT
			 LAYER M2 ;
			RECT 0.0098 15.3224 0.0481 15.4227 ;
			 LAYER M3 ;
			RECT 0.0098 15.3224 0.0481 15.4227 ;
			 LAYER V2 ;
			RECT 0.021 15.3353 0.0359 15.3478 ;
		END

		ANTENNADIFFAREA 0.00194719 ;
		ANTENNAPARTIALMETALAREA 0.00195671 ;
	END WENY[11]

	PIN WENY[12]
		USE SIGNAL ;
		DIRECTION OUTPUT ;
		SHAPE ABUTMENT ;
		PORT
			 LAYER M2 ;
			RECT 0.0098 16.6024 0.0481 16.7027 ;
			 LAYER M3 ;
			RECT 0.0098 16.6024 0.0481 16.7027 ;
			 LAYER V2 ;
			RECT 0.021 16.6153 0.0359 16.6278 ;
		END

		ANTENNADIFFAREA 0.00194719 ;
		ANTENNAPARTIALMETALAREA 0.00195671 ;
	END WENY[12]

	PIN WENY[13]
		USE SIGNAL ;
		DIRECTION OUTPUT ;
		SHAPE ABUTMENT ;
		PORT
			 LAYER M2 ;
			RECT 0.0098 17.8824 0.0481 17.9827 ;
			 LAYER M3 ;
			RECT 0.0098 17.8824 0.0481 17.9827 ;
			 LAYER V2 ;
			RECT 0.021 17.8953 0.0359 17.9078 ;
		END

		ANTENNADIFFAREA 0.00194719 ;
		ANTENNAPARTIALMETALAREA 0.00195671 ;
	END WENY[13]

	PIN WENY[14]
		USE SIGNAL ;
		DIRECTION OUTPUT ;
		SHAPE ABUTMENT ;
		PORT
			 LAYER M2 ;
			RECT 0.0098 19.1624 0.0481 19.2627 ;
			 LAYER M3 ;
			RECT 0.0098 19.1624 0.0481 19.2627 ;
			 LAYER V2 ;
			RECT 0.021 19.1753 0.0359 19.1878 ;
		END

		ANTENNADIFFAREA 0.00194719 ;
		ANTENNAPARTIALMETALAREA 0.00195671 ;
	END WENY[14]

	PIN WENY[15]
		USE SIGNAL ;
		DIRECTION OUTPUT ;
		SHAPE ABUTMENT ;
		PORT
			 LAYER M2 ;
			RECT 0.0098 20.4424 0.0481 20.5427 ;
			 LAYER M3 ;
			RECT 0.0098 20.4424 0.0481 20.5427 ;
			 LAYER V2 ;
			RECT 0.021 20.4553 0.0359 20.4678 ;
		END

		ANTENNADIFFAREA 0.00194719 ;
		ANTENNAPARTIALMETALAREA 0.00195671 ;
	END WENY[15]

	PIN WENY[16]
		USE SIGNAL ;
		DIRECTION OUTPUT ;
		SHAPE ABUTMENT ;
		PORT
			 LAYER M2 ;
			RECT 0.0098 21.7224 0.0481 21.8227 ;
			 LAYER M3 ;
			RECT 0.0098 21.7224 0.0481 21.8227 ;
			 LAYER V2 ;
			RECT 0.021 21.7353 0.0359 21.7478 ;
		END

		ANTENNADIFFAREA 0.00194719 ;
		ANTENNAPARTIALMETALAREA 0.00195671 ;
	END WENY[16]

	PIN WENY[17]
		USE SIGNAL ;
		DIRECTION OUTPUT ;
		SHAPE ABUTMENT ;
		PORT
			 LAYER M2 ;
			RECT 0.0098 23.0024 0.0481 23.1027 ;
			 LAYER M3 ;
			RECT 0.0098 23.0024 0.0481 23.1027 ;
			 LAYER V2 ;
			RECT 0.021 23.0153 0.0359 23.0278 ;
		END

		ANTENNADIFFAREA 0.00194719 ;
		ANTENNAPARTIALMETALAREA 0.00195671 ;
	END WENY[17]

	PIN WENY[18]
		USE SIGNAL ;
		DIRECTION OUTPUT ;
		SHAPE ABUTMENT ;
		PORT
			 LAYER M2 ;
			RECT 0.0098 24.2824 0.0481 24.3827 ;
			 LAYER M3 ;
			RECT 0.0098 24.2824 0.0481 24.3827 ;
			 LAYER V2 ;
			RECT 0.021 24.2953 0.0359 24.3078 ;
		END

		ANTENNADIFFAREA 0.00194719 ;
		ANTENNAPARTIALMETALAREA 0.00195671 ;
	END WENY[18]

	PIN WENY[19]
		USE SIGNAL ;
		DIRECTION OUTPUT ;
		SHAPE ABUTMENT ;
		PORT
			 LAYER M2 ;
			RECT 0.0098 25.5624 0.0481 25.6627 ;
			 LAYER M3 ;
			RECT 0.0098 25.5624 0.0481 25.6627 ;
			 LAYER V2 ;
			RECT 0.021 25.5753 0.0359 25.5878 ;
		END

		ANTENNADIFFAREA 0.00194719 ;
		ANTENNAPARTIALMETALAREA 0.00195671 ;
	END WENY[19]

	PIN WENY[1]
		USE SIGNAL ;
		DIRECTION OUTPUT ;
		SHAPE ABUTMENT ;
		PORT
			 LAYER M2 ;
			RECT 0.0098 2.5224 0.0481 2.6227 ;
			 LAYER M3 ;
			RECT 0.0098 2.5224 0.0481 2.6227 ;
			 LAYER V2 ;
			RECT 0.021 2.5353 0.0359 2.5478 ;
		END

		ANTENNADIFFAREA 0.00194719 ;
		ANTENNAPARTIALMETALAREA 0.00195671 ;
	END WENY[1]

	PIN WENY[20]
		USE SIGNAL ;
		DIRECTION OUTPUT ;
		SHAPE ABUTMENT ;
		PORT
			 LAYER M2 ;
			RECT 0.0098 26.8424 0.0481 26.9427 ;
			 LAYER M3 ;
			RECT 0.0098 26.8424 0.0481 26.9427 ;
			 LAYER V2 ;
			RECT 0.021 26.8553 0.0359 26.8678 ;
		END

		ANTENNADIFFAREA 0.00194719 ;
		ANTENNAPARTIALMETALAREA 0.00195671 ;
	END WENY[20]

	PIN WENY[21]
		USE SIGNAL ;
		DIRECTION OUTPUT ;
		SHAPE ABUTMENT ;
		PORT
			 LAYER M2 ;
			RECT 0.0098 28.1224 0.0481 28.2227 ;
			 LAYER M3 ;
			RECT 0.0098 28.1224 0.0481 28.2227 ;
			 LAYER V2 ;
			RECT 0.021 28.1353 0.0359 28.1478 ;
		END

		ANTENNADIFFAREA 0.00194719 ;
		ANTENNAPARTIALMETALAREA 0.00195671 ;
	END WENY[21]

	PIN WENY[22]
		USE SIGNAL ;
		DIRECTION OUTPUT ;
		SHAPE ABUTMENT ;
		PORT
			 LAYER M2 ;
			RECT 0.0098 29.4024 0.0481 29.5027 ;
			 LAYER M3 ;
			RECT 0.0098 29.4024 0.0481 29.5027 ;
			 LAYER V2 ;
			RECT 0.021 29.4153 0.0359 29.4278 ;
		END

		ANTENNADIFFAREA 0.00194719 ;
		ANTENNAPARTIALMETALAREA 0.00195671 ;
	END WENY[22]

	PIN WENY[23]
		USE SIGNAL ;
		DIRECTION OUTPUT ;
		SHAPE ABUTMENT ;
		PORT
			 LAYER M2 ;
			RECT 0.0098 30.6824 0.0481 30.7827 ;
			 LAYER M3 ;
			RECT 0.0098 30.6824 0.0481 30.7827 ;
			 LAYER V2 ;
			RECT 0.021 30.6953 0.0359 30.7078 ;
		END

		ANTENNADIFFAREA 0.00194719 ;
		ANTENNAPARTIALMETALAREA 0.00195671 ;
	END WENY[23]

	PIN WENY[24]
		USE SIGNAL ;
		DIRECTION OUTPUT ;
		SHAPE ABUTMENT ;
		PORT
			 LAYER M2 ;
			RECT 0.0098 39.6612 0.0481 39.7616 ;
			 LAYER M3 ;
			RECT 0.0098 39.6612 0.0481 39.7616 ;
			 LAYER V2 ;
			RECT 0.021 39.6741 0.0359 39.6867 ;
		END

		ANTENNADIFFAREA 0.00194719 ;
		ANTENNAPARTIALMETALAREA 0.00195671 ;
	END WENY[24]

	PIN WENY[25]
		USE SIGNAL ;
		DIRECTION OUTPUT ;
		SHAPE ABUTMENT ;
		PORT
			 LAYER M2 ;
			RECT 0.0098 40.9412 0.0481 41.0416 ;
			 LAYER M3 ;
			RECT 0.0098 40.9412 0.0481 41.0416 ;
			 LAYER V2 ;
			RECT 0.021 40.9541 0.0359 40.9667 ;
		END

		ANTENNADIFFAREA 0.00194719 ;
		ANTENNAPARTIALMETALAREA 0.00195671 ;
	END WENY[25]

	PIN WENY[26]
		USE SIGNAL ;
		DIRECTION OUTPUT ;
		SHAPE ABUTMENT ;
		PORT
			 LAYER M2 ;
			RECT 0.0098 42.2212 0.0481 42.3216 ;
			 LAYER M3 ;
			RECT 0.0098 42.2212 0.0481 42.3216 ;
			 LAYER V2 ;
			RECT 0.021 42.2341 0.0359 42.2467 ;
		END

		ANTENNADIFFAREA 0.00194719 ;
		ANTENNAPARTIALMETALAREA 0.00195671 ;
	END WENY[26]

	PIN WENY[27]
		USE SIGNAL ;
		DIRECTION OUTPUT ;
		SHAPE ABUTMENT ;
		PORT
			 LAYER M2 ;
			RECT 0.0098 43.5012 0.0481 43.6016 ;
			 LAYER M3 ;
			RECT 0.0098 43.5012 0.0481 43.6016 ;
			 LAYER V2 ;
			RECT 0.021 43.5141 0.0359 43.5267 ;
		END

		ANTENNADIFFAREA 0.00194719 ;
		ANTENNAPARTIALMETALAREA 0.00195671 ;
	END WENY[27]

	PIN WENY[28]
		USE SIGNAL ;
		DIRECTION OUTPUT ;
		SHAPE ABUTMENT ;
		PORT
			 LAYER M2 ;
			RECT 0.0098 44.7812 0.0481 44.8816 ;
			 LAYER M3 ;
			RECT 0.0098 44.7812 0.0481 44.8816 ;
			 LAYER V2 ;
			RECT 0.021 44.7941 0.0359 44.8067 ;
		END

		ANTENNADIFFAREA 0.00194719 ;
		ANTENNAPARTIALMETALAREA 0.00195671 ;
	END WENY[28]

	PIN WENY[29]
		USE SIGNAL ;
		DIRECTION OUTPUT ;
		SHAPE ABUTMENT ;
		PORT
			 LAYER M2 ;
			RECT 0.0098 46.0612 0.0481 46.1616 ;
			 LAYER M3 ;
			RECT 0.0098 46.0612 0.0481 46.1616 ;
			 LAYER V2 ;
			RECT 0.021 46.0741 0.0359 46.0867 ;
		END

		ANTENNADIFFAREA 0.00194719 ;
		ANTENNAPARTIALMETALAREA 0.00195671 ;
	END WENY[29]

	PIN WENY[2]
		USE SIGNAL ;
		DIRECTION OUTPUT ;
		SHAPE ABUTMENT ;
		PORT
			 LAYER M2 ;
			RECT 0.0098 3.8024 0.0481 3.9027 ;
			 LAYER M3 ;
			RECT 0.0098 3.8024 0.0481 3.9027 ;
			 LAYER V2 ;
			RECT 0.021 3.8153 0.0359 3.8278 ;
		END

		ANTENNADIFFAREA 0.00194719 ;
		ANTENNAPARTIALMETALAREA 0.00195671 ;
	END WENY[2]

	PIN WENY[30]
		USE SIGNAL ;
		DIRECTION OUTPUT ;
		SHAPE ABUTMENT ;
		PORT
			 LAYER M2 ;
			RECT 0.0098 47.3412 0.0481 47.4416 ;
			 LAYER M3 ;
			RECT 0.0098 47.3412 0.0481 47.4416 ;
			 LAYER V2 ;
			RECT 0.021 47.3541 0.0359 47.3667 ;
		END

		ANTENNADIFFAREA 0.00194719 ;
		ANTENNAPARTIALMETALAREA 0.00195671 ;
	END WENY[30]

	PIN WENY[31]
		USE SIGNAL ;
		DIRECTION OUTPUT ;
		SHAPE ABUTMENT ;
		PORT
			 LAYER M2 ;
			RECT 0.0098 48.6212 0.0481 48.7216 ;
			 LAYER M3 ;
			RECT 0.0098 48.6212 0.0481 48.7216 ;
			 LAYER V2 ;
			RECT 0.021 48.6341 0.0359 48.6467 ;
		END

		ANTENNADIFFAREA 0.00194719 ;
		ANTENNAPARTIALMETALAREA 0.00195671 ;
	END WENY[31]

	PIN WENY[32]
		USE SIGNAL ;
		DIRECTION OUTPUT ;
		SHAPE ABUTMENT ;
		PORT
			 LAYER M2 ;
			RECT 0.0098 49.9012 0.0481 50.0016 ;
			 LAYER M3 ;
			RECT 0.0098 49.9012 0.0481 50.0016 ;
			 LAYER V2 ;
			RECT 0.021 49.9141 0.0359 49.9267 ;
		END

		ANTENNADIFFAREA 0.00194719 ;
		ANTENNAPARTIALMETALAREA 0.00195671 ;
	END WENY[32]

	PIN WENY[33]
		USE SIGNAL ;
		DIRECTION OUTPUT ;
		SHAPE ABUTMENT ;
		PORT
			 LAYER M2 ;
			RECT 0.0098 51.1812 0.0481 51.2816 ;
			 LAYER M3 ;
			RECT 0.0098 51.1812 0.0481 51.2816 ;
			 LAYER V2 ;
			RECT 0.021 51.1941 0.0359 51.2067 ;
		END

		ANTENNADIFFAREA 0.00194719 ;
		ANTENNAPARTIALMETALAREA 0.00195671 ;
	END WENY[33]

	PIN WENY[34]
		USE SIGNAL ;
		DIRECTION OUTPUT ;
		SHAPE ABUTMENT ;
		PORT
			 LAYER M2 ;
			RECT 0.0098 52.4612 0.0481 52.5616 ;
			 LAYER M3 ;
			RECT 0.0098 52.4612 0.0481 52.5616 ;
			 LAYER V2 ;
			RECT 0.021 52.4741 0.0359 52.4867 ;
		END

		ANTENNADIFFAREA 0.00194719 ;
		ANTENNAPARTIALMETALAREA 0.00195671 ;
	END WENY[34]

	PIN WENY[35]
		USE SIGNAL ;
		DIRECTION OUTPUT ;
		SHAPE ABUTMENT ;
		PORT
			 LAYER M2 ;
			RECT 0.0098 53.7412 0.0481 53.8416 ;
			 LAYER M3 ;
			RECT 0.0098 53.7412 0.0481 53.8416 ;
			 LAYER V2 ;
			RECT 0.021 53.7541 0.0359 53.7667 ;
		END

		ANTENNADIFFAREA 0.00194719 ;
		ANTENNAPARTIALMETALAREA 0.00195671 ;
	END WENY[35]

	PIN WENY[36]
		USE SIGNAL ;
		DIRECTION OUTPUT ;
		SHAPE ABUTMENT ;
		PORT
			 LAYER M2 ;
			RECT 0.0098 55.0212 0.0481 55.1216 ;
			 LAYER M3 ;
			RECT 0.0098 55.0212 0.0481 55.1216 ;
			 LAYER V2 ;
			RECT 0.021 55.0341 0.0359 55.0467 ;
		END

		ANTENNADIFFAREA 0.00194719 ;
		ANTENNAPARTIALMETALAREA 0.00195671 ;
	END WENY[36]

	PIN WENY[37]
		USE SIGNAL ;
		DIRECTION OUTPUT ;
		SHAPE ABUTMENT ;
		PORT
			 LAYER M2 ;
			RECT 0.0098 56.3012 0.0481 56.4016 ;
			 LAYER M3 ;
			RECT 0.0098 56.3012 0.0481 56.4016 ;
			 LAYER V2 ;
			RECT 0.021 56.3141 0.0359 56.3267 ;
		END

		ANTENNADIFFAREA 0.00194719 ;
		ANTENNAPARTIALMETALAREA 0.00195671 ;
	END WENY[37]

	PIN WENY[38]
		USE SIGNAL ;
		DIRECTION OUTPUT ;
		SHAPE ABUTMENT ;
		PORT
			 LAYER M2 ;
			RECT 0.0098 57.4682 0.0481 57.5059 ;
			 LAYER M3 ;
			RECT 0.0098 57.4055 0.0481 57.5059 ;
			 LAYER V2 ;
			RECT 0.0215 57.4804 0.0364 57.4929 ;
		END

		ANTENNADIFFAREA 0.00194719 ;
		ANTENNAPARTIALMETALAREA 0.00195671 ;
	END WENY[38]

	PIN WENY[39]
		USE SIGNAL ;
		DIRECTION OUTPUT ;
		SHAPE ABUTMENT ;
		PORT
			 LAYER M2 ;
			RECT 0.0098 58.7482 0.0481 58.7859 ;
			 LAYER M3 ;
			RECT 0.0098 58.6855 0.0481 58.7859 ;
			 LAYER V2 ;
			RECT 0.0215 58.7604 0.0364 58.7729 ;
		END

		ANTENNADIFFAREA 0.00194719 ;
		ANTENNAPARTIALMETALAREA 0.00195671 ;
	END WENY[39]

	PIN WENY[3]
		USE SIGNAL ;
		DIRECTION OUTPUT ;
		SHAPE ABUTMENT ;
		PORT
			 LAYER M2 ;
			RECT 0.0098 5.0824 0.0481 5.1827 ;
			 LAYER M3 ;
			RECT 0.0098 5.0824 0.0481 5.1827 ;
			 LAYER V2 ;
			RECT 0.021 5.0953 0.0359 5.1078 ;
		END

		ANTENNADIFFAREA 0.00194719 ;
		ANTENNAPARTIALMETALAREA 0.00195671 ;
	END WENY[3]

	PIN WENY[40]
		USE SIGNAL ;
		DIRECTION OUTPUT ;
		SHAPE ABUTMENT ;
		PORT
			 LAYER M2 ;
			RECT 0.0714 60.0408 0.1097 60.0784 ;
			 LAYER M3 ;
			RECT 0.0714 60.0408 0.1097 60.1412 ;
			 LAYER V2 ;
			RECT 0.0831 60.0529 0.098 60.0655 ;
		END

		ANTENNADIFFAREA 0.00194719 ;
		ANTENNAPARTIALMETALAREA 0.00195671 ;
	END WENY[40]

	PIN WENY[41]
		USE SIGNAL ;
		DIRECTION OUTPUT ;
		SHAPE ABUTMENT ;
		PORT
			 LAYER M2 ;
			RECT 0.0098 61.3082 0.0481 61.3459 ;
			 LAYER M3 ;
			RECT 0.0098 61.2455 0.0481 61.3459 ;
			 LAYER V2 ;
			RECT 0.0215 61.3204 0.0364 61.3329 ;
		END

		ANTENNADIFFAREA 0.00194719 ;
		ANTENNAPARTIALMETALAREA 0.00195671 ;
	END WENY[41]

	PIN WENY[42]
		USE SIGNAL ;
		DIRECTION OUTPUT ;
		SHAPE ABUTMENT ;
		PORT
			 LAYER M2 ;
			RECT 0.0098 62.5882 0.0481 62.6259 ;
			 LAYER M3 ;
			RECT 0.0098 62.5255 0.0481 62.6259 ;
			 LAYER V2 ;
			RECT 0.0215 62.6004 0.0364 62.6129 ;
		END

		ANTENNADIFFAREA 0.00194719 ;
		ANTENNAPARTIALMETALAREA 0.00195671 ;
	END WENY[42]

	PIN WENY[43]
		USE SIGNAL ;
		DIRECTION OUTPUT ;
		SHAPE ABUTMENT ;
		PORT
			 LAYER M2 ;
			RECT 0.0714 63.9561 0.1097 63.9937 ;
			 LAYER M3 ;
			RECT 0.0714 63.9561 0.1097 64.0565 ;
			 LAYER V2 ;
			RECT 0.0831 63.9682 0.098 63.9808 ;
		END

		ANTENNADIFFAREA 0.00194719 ;
		ANTENNAPARTIALMETALAREA 0.00195671 ;
	END WENY[43]

	PIN WENY[44]
		USE SIGNAL ;
		DIRECTION OUTPUT ;
		SHAPE ABUTMENT ;
		PORT
			 LAYER M2 ;
			RECT 0.0098 65.2988 0.0481 65.3365 ;
			 LAYER M3 ;
			RECT 0.0098 65.2361 0.0481 65.3365 ;
			 LAYER V2 ;
			RECT 0.0215 65.311 0.0364 65.3235 ;
		END

		ANTENNADIFFAREA 0.00194719 ;
		ANTENNAPARTIALMETALAREA 0.00195671 ;
	END WENY[44]

	PIN WENY[45]
		USE SIGNAL ;
		DIRECTION OUTPUT ;
		SHAPE ABUTMENT ;
		PORT
			 LAYER M2 ;
			RECT 0.0098 66.4282 0.0481 66.4659 ;
			 LAYER M3 ;
			RECT 0.0098 66.3655 0.0481 66.4659 ;
			 LAYER V2 ;
			RECT 0.0215 66.4404 0.0364 66.4529 ;
		END

		ANTENNADIFFAREA 0.00194719 ;
		ANTENNAPARTIALMETALAREA 0.00195671 ;
	END WENY[45]

	PIN WENY[46]
		USE SIGNAL ;
		DIRECTION OUTPUT ;
		SHAPE ABUTMENT ;
		PORT
			 LAYER M2 ;
			RECT 0.0098 67.7082 0.0481 67.7459 ;
			 LAYER M3 ;
			RECT 0.0098 67.6455 0.0481 67.7459 ;
			 LAYER V2 ;
			RECT 0.0215 67.7204 0.0364 67.7329 ;
		END

		ANTENNADIFFAREA 0.00194719 ;
		ANTENNAPARTIALMETALAREA 0.00195671 ;
	END WENY[46]

	PIN WENY[47]
		USE SIGNAL ;
		DIRECTION OUTPUT ;
		SHAPE ABUTMENT ;
		PORT
			 LAYER M2 ;
			RECT 0.0714 69.0761 0.1097 69.1137 ;
			 LAYER M3 ;
			RECT 0.0714 69.0761 0.1097 69.1765 ;
			 LAYER V2 ;
			RECT 0.0831 69.0882 0.098 69.1008 ;
		END

		ANTENNADIFFAREA 0.00194719 ;
		ANTENNAPARTIALMETALAREA 0.00195671 ;
	END WENY[47]

	PIN WENY[48]
		USE SIGNAL ;
		DIRECTION OUTPUT ;
		SHAPE ABUTMENT ;
		PORT
			 LAYER M2 ;
			RECT 0.0714 69.9545 0.1097 69.9922 ;
			 LAYER M3 ;
			RECT 0.0714 69.8918 0.1097 69.9922 ;
			 LAYER V2 ;
			RECT 0.0831 69.9675 0.098 69.98 ;
		END

		ANTENNADIFFAREA 0.00194719 ;
		ANTENNAPARTIALMETALAREA 0.00195671 ;
	END WENY[48]

	PIN WENY[49]
		USE SIGNAL ;
		DIRECTION OUTPUT ;
		SHAPE ABUTMENT ;
		PORT
			 LAYER M2 ;
			RECT 0.0098 71.3224 0.0481 71.36 ;
			 LAYER M3 ;
			RECT 0.0098 71.3224 0.0481 71.4227 ;
			 LAYER V2 ;
			RECT 0.0215 71.3353 0.0364 71.3478 ;
		END

		ANTENNADIFFAREA 0.00194719 ;
		ANTENNAPARTIALMETALAREA 0.00195671 ;
	END WENY[49]

	PIN WENY[4]
		USE SIGNAL ;
		DIRECTION OUTPUT ;
		SHAPE ABUTMENT ;
		PORT
			 LAYER M2 ;
			RECT 0.0098 6.3624 0.0481 6.4627 ;
			 LAYER M3 ;
			RECT 0.0098 6.3624 0.0481 6.4627 ;
			 LAYER V2 ;
			RECT 0.021 6.3753 0.0359 6.3878 ;
		END

		ANTENNADIFFAREA 0.00194719 ;
		ANTENNAPARTIALMETALAREA 0.00195671 ;
	END WENY[4]

	PIN WENY[50]
		USE SIGNAL ;
		DIRECTION OUTPUT ;
		SHAPE ABUTMENT ;
		PORT
			 LAYER M2 ;
			RECT 0.0098 72.6024 0.0481 72.64 ;
			 LAYER M3 ;
			RECT 0.0098 72.6024 0.0481 72.7027 ;
			 LAYER V2 ;
			RECT 0.0215 72.6153 0.0364 72.6278 ;
		END

		ANTENNADIFFAREA 0.00194719 ;
		ANTENNAPARTIALMETALAREA 0.00195671 ;
	END WENY[50]

	PIN WENY[51]
		USE SIGNAL ;
		DIRECTION OUTPUT ;
		SHAPE ABUTMENT ;
		PORT
			 LAYER M2 ;
			RECT 0.0098 73.7318 0.0481 73.8322 ;
			 LAYER M3 ;
			RECT 0.0098 73.7318 0.0481 73.8322 ;
			 LAYER V2 ;
			RECT 0.021 73.8067 0.0359 73.8192 ;
		END

		ANTENNADIFFAREA 0.00194719 ;
		ANTENNAPARTIALMETALAREA 0.00195671 ;
	END WENY[51]

	PIN WENY[52]
		USE SIGNAL ;
		DIRECTION OUTPUT ;
		SHAPE ABUTMENT ;
		PORT
			 LAYER M2 ;
			RECT 0.0714 75.0745 0.1097 75.1122 ;
			 LAYER M3 ;
			RECT 0.0714 75.0118 0.1097 75.1122 ;
			 LAYER V2 ;
			RECT 0.0831 75.0875 0.098 75.1 ;
		END

		ANTENNADIFFAREA 0.00194719 ;
		ANTENNAPARTIALMETALAREA 0.00195671 ;
	END WENY[52]

	PIN WENY[53]
		USE SIGNAL ;
		DIRECTION OUTPUT ;
		SHAPE ABUTMENT ;
		PORT
			 LAYER M2 ;
			RECT 0.0098 76.4424 0.0481 76.48 ;
			 LAYER M3 ;
			RECT 0.0098 76.4424 0.0481 76.5427 ;
			 LAYER V2 ;
			RECT 0.0215 76.4553 0.0364 76.4678 ;
		END

		ANTENNADIFFAREA 0.00194719 ;
		ANTENNAPARTIALMETALAREA 0.00195671 ;
	END WENY[53]

	PIN WENY[54]
		USE SIGNAL ;
		DIRECTION OUTPUT ;
		SHAPE ABUTMENT ;
		PORT
			 LAYER M2 ;
			RECT 0.0098 77.7224 0.0481 77.76 ;
			 LAYER M3 ;
			RECT 0.0098 77.7224 0.0481 77.8227 ;
			 LAYER V2 ;
			RECT 0.0215 77.7353 0.0364 77.7478 ;
		END

		ANTENNADIFFAREA 0.00194719 ;
		ANTENNAPARTIALMETALAREA 0.00195671 ;
	END WENY[54]

	PIN WENY[55]
		USE SIGNAL ;
		DIRECTION OUTPUT ;
		SHAPE ABUTMENT ;
		PORT
			 LAYER M2 ;
			RECT 0.0098 78.9271 0.0481 79.0275 ;
			 LAYER M3 ;
			RECT 0.0098 78.9271 0.0481 79.0275 ;
			 LAYER V2 ;
			RECT 0.021 79.002 0.0359 79.0145 ;
		END

		ANTENNADIFFAREA 0.00194719 ;
		ANTENNAPARTIALMETALAREA 0.00195671 ;
	END WENY[55]

	PIN WENY[56]
		USE SIGNAL ;
		DIRECTION OUTPUT ;
		SHAPE ABUTMENT ;
		PORT
			 LAYER M2 ;
			RECT 0.0098 80.2824 0.0481 80.32 ;
			 LAYER M3 ;
			RECT 0.0098 80.2824 0.0481 80.3827 ;
			 LAYER V2 ;
			RECT 0.0215 80.2953 0.0364 80.3078 ;
		END

		ANTENNADIFFAREA 0.00194719 ;
		ANTENNAPARTIALMETALAREA 0.00195671 ;
	END WENY[56]

	PIN WENY[57]
		USE SIGNAL ;
		DIRECTION OUTPUT ;
		SHAPE ABUTMENT ;
		PORT
			 LAYER M2 ;
			RECT 0.0714 81.4745 0.1097 81.5122 ;
			 LAYER M3 ;
			RECT 0.0714 81.4118 0.1097 81.5122 ;
			 LAYER V2 ;
			RECT 0.0831 81.4875 0.098 81.5 ;
		END

		ANTENNADIFFAREA 0.00194719 ;
		ANTENNAPARTIALMETALAREA 0.00195671 ;
	END WENY[57]

	PIN WENY[58]
		USE SIGNAL ;
		DIRECTION OUTPUT ;
		SHAPE ABUTMENT ;
		PORT
			 LAYER M2 ;
			RECT 0.0098 82.6667 0.0481 82.7671 ;
			 LAYER M3 ;
			RECT 0.0098 82.6667 0.0481 82.7671 ;
			 LAYER V2 ;
			RECT 0.021 82.7416 0.0359 82.7541 ;
		END

		ANTENNADIFFAREA 0.00194719 ;
		ANTENNAPARTIALMETALAREA 0.00195671 ;
	END WENY[58]

	PIN WENY[59]
		USE SIGNAL ;
		DIRECTION OUTPUT ;
		SHAPE ABUTMENT ;
		PORT
			 LAYER M2 ;
			RECT 0.0098 83.9467 0.0481 84.0471 ;
			 LAYER M3 ;
			RECT 0.0098 83.9467 0.0481 84.0471 ;
			 LAYER V2 ;
			RECT 0.021 84.0216 0.0359 84.0341 ;
		END

		ANTENNADIFFAREA 0.00194719 ;
		ANTENNAPARTIALMETALAREA 0.00195671 ;
	END WENY[59]

	PIN WENY[5]
		USE SIGNAL ;
		DIRECTION OUTPUT ;
		SHAPE ABUTMENT ;
		PORT
			 LAYER M2 ;
			RECT 0.0098 7.6424 0.0481 7.7427 ;
			 LAYER M3 ;
			RECT 0.0098 7.6424 0.0481 7.7427 ;
			 LAYER V2 ;
			RECT 0.021 7.6553 0.0359 7.6678 ;
		END

		ANTENNADIFFAREA 0.00194719 ;
		ANTENNAPARTIALMETALAREA 0.00195671 ;
	END WENY[5]

	PIN WENY[60]
		USE SIGNAL ;
		DIRECTION OUTPUT ;
		SHAPE ABUTMENT ;
		PORT
			 LAYER M2 ;
			RECT 0.0098 85.2267 0.0481 85.3271 ;
			 LAYER M3 ;
			RECT 0.0098 85.2267 0.0481 85.3271 ;
			 LAYER V2 ;
			RECT 0.021 85.3016 0.0359 85.3141 ;
		END

		ANTENNADIFFAREA 0.00194719 ;
		ANTENNAPARTIALMETALAREA 0.00195671 ;
	END WENY[60]

	PIN WENY[61]
		USE SIGNAL ;
		DIRECTION OUTPUT ;
		SHAPE ABUTMENT ;
		PORT
			 LAYER M2 ;
			RECT 0.0098 86.5067 0.0481 86.6071 ;
			 LAYER M3 ;
			RECT 0.0098 86.5067 0.0481 86.6071 ;
			 LAYER V2 ;
			RECT 0.021 86.5816 0.0359 86.5941 ;
		END

		ANTENNADIFFAREA 0.00194719 ;
		ANTENNAPARTIALMETALAREA 0.00195671 ;
	END WENY[61]

	PIN WENY[62]
		USE SIGNAL ;
		DIRECTION OUTPUT ;
		SHAPE ABUTMENT ;
		PORT
			 LAYER M2 ;
			RECT 0.0098 87.7867 0.0481 87.8871 ;
			 LAYER M3 ;
			RECT 0.0098 87.7867 0.0481 87.8871 ;
			 LAYER V2 ;
			RECT 0.021 87.8616 0.0359 87.8741 ;
		END

		ANTENNADIFFAREA 0.00194719 ;
		ANTENNAPARTIALMETALAREA 0.00195671 ;
	END WENY[62]

	PIN WENY[63]
		USE SIGNAL ;
		DIRECTION OUTPUT ;
		SHAPE ABUTMENT ;
		PORT
			 LAYER M2 ;
			RECT 0.0098 89.0667 0.0481 89.1671 ;
			 LAYER M3 ;
			RECT 0.0098 89.0667 0.0481 89.1671 ;
			 LAYER V2 ;
			RECT 0.021 89.1416 0.0359 89.1541 ;
		END

		ANTENNADIFFAREA 0.00194719 ;
		ANTENNAPARTIALMETALAREA 0.00195671 ;
	END WENY[63]

	PIN WENY[64]
		USE SIGNAL ;
		DIRECTION OUTPUT ;
		SHAPE ABUTMENT ;
		PORT
			 LAYER M2 ;
			RECT 0.0098 90.3467 0.0481 90.4471 ;
			 LAYER M3 ;
			RECT 0.0098 90.3467 0.0481 90.4471 ;
			 LAYER V2 ;
			RECT 0.021 90.4216 0.0359 90.4341 ;
		END

		ANTENNADIFFAREA 0.00194719 ;
		ANTENNAPARTIALMETALAREA 0.00195671 ;
	END WENY[64]

	PIN WENY[65]
		USE SIGNAL ;
		DIRECTION OUTPUT ;
		SHAPE ABUTMENT ;
		PORT
			 LAYER M2 ;
			RECT 0.0098 91.6267 0.0481 91.7271 ;
			 LAYER M3 ;
			RECT 0.0098 91.6267 0.0481 91.7271 ;
			 LAYER V2 ;
			RECT 0.021 91.7016 0.0359 91.7141 ;
		END

		ANTENNADIFFAREA 0.00194719 ;
		ANTENNAPARTIALMETALAREA 0.00195671 ;
	END WENY[65]

	PIN WENY[66]
		USE SIGNAL ;
		DIRECTION OUTPUT ;
		SHAPE ABUTMENT ;
		PORT
			 LAYER M2 ;
			RECT 0.0098 92.9067 0.0481 93.0071 ;
			 LAYER M3 ;
			RECT 0.0098 92.9067 0.0481 93.0071 ;
			 LAYER V2 ;
			RECT 0.021 92.9816 0.0359 92.9941 ;
		END

		ANTENNADIFFAREA 0.00194719 ;
		ANTENNAPARTIALMETALAREA 0.00195671 ;
	END WENY[66]

	PIN WENY[67]
		USE SIGNAL ;
		DIRECTION OUTPUT ;
		SHAPE ABUTMENT ;
		PORT
			 LAYER M2 ;
			RECT 0.0098 94.1867 0.0481 94.2871 ;
			 LAYER M3 ;
			RECT 0.0098 94.1867 0.0481 94.2871 ;
			 LAYER V2 ;
			RECT 0.021 94.2616 0.0359 94.2741 ;
		END

		ANTENNADIFFAREA 0.00194719 ;
		ANTENNAPARTIALMETALAREA 0.00195671 ;
	END WENY[67]

	PIN WENY[68]
		USE SIGNAL ;
		DIRECTION OUTPUT ;
		SHAPE ABUTMENT ;
		PORT
			 LAYER M2 ;
			RECT 0.0098 95.4667 0.0481 95.5671 ;
			 LAYER M3 ;
			RECT 0.0098 95.4667 0.0481 95.5671 ;
			 LAYER V2 ;
			RECT 0.021 95.5416 0.0359 95.5541 ;
		END

		ANTENNADIFFAREA 0.00194719 ;
		ANTENNAPARTIALMETALAREA 0.00195671 ;
	END WENY[68]

	PIN WENY[69]
		USE SIGNAL ;
		DIRECTION OUTPUT ;
		SHAPE ABUTMENT ;
		PORT
			 LAYER M2 ;
			RECT 0.0098 96.7467 0.0481 96.8471 ;
			 LAYER M3 ;
			RECT 0.0098 96.7467 0.0481 96.8471 ;
			 LAYER V2 ;
			RECT 0.021 96.8216 0.0359 96.8341 ;
		END

		ANTENNADIFFAREA 0.00194719 ;
		ANTENNAPARTIALMETALAREA 0.00195671 ;
	END WENY[69]

	PIN WENY[6]
		USE SIGNAL ;
		DIRECTION OUTPUT ;
		SHAPE ABUTMENT ;
		PORT
			 LAYER M2 ;
			RECT 0.0098 8.9224 0.0481 9.0227 ;
			 LAYER M3 ;
			RECT 0.0098 8.9224 0.0481 9.0227 ;
			 LAYER V2 ;
			RECT 0.021 8.9353 0.0359 8.9478 ;
		END

		ANTENNADIFFAREA 0.00194719 ;
		ANTENNAPARTIALMETALAREA 0.00195671 ;
	END WENY[6]

	PIN WENY[70]
		USE SIGNAL ;
		DIRECTION OUTPUT ;
		SHAPE ABUTMENT ;
		PORT
			 LAYER M2 ;
			RECT 0.0098 98.0267 0.0481 98.1271 ;
			 LAYER M3 ;
			RECT 0.0098 98.0267 0.0481 98.1271 ;
			 LAYER V2 ;
			RECT 0.021 98.1016 0.0359 98.1141 ;
		END

		ANTENNADIFFAREA 0.00194719 ;
		ANTENNAPARTIALMETALAREA 0.00195671 ;
	END WENY[70]

	PIN WENY[71]
		USE SIGNAL ;
		DIRECTION OUTPUT ;
		SHAPE ABUTMENT ;
		PORT
			 LAYER M2 ;
			RECT 0.0098 99.3067 0.0481 99.4071 ;
			 LAYER M3 ;
			RECT 0.0098 99.3067 0.0481 99.4071 ;
			 LAYER V2 ;
			RECT 0.021 99.3816 0.0359 99.3941 ;
		END

		ANTENNADIFFAREA 0.00194719 ;
		ANTENNAPARTIALMETALAREA 0.00195671 ;
	END WENY[71]

	PIN WENY[72]
		USE SIGNAL ;
		DIRECTION OUTPUT ;
		SHAPE ABUTMENT ;
		PORT
			 LAYER M2 ;
			RECT 0.0098 108.2855 0.0481 108.3859 ;
			 LAYER M3 ;
			RECT 0.0098 108.2855 0.0481 108.3859 ;
			 LAYER V2 ;
			RECT 0.021 108.3604 0.0359 108.3729 ;
		END

		ANTENNADIFFAREA 0.00194719 ;
		ANTENNAPARTIALMETALAREA 0.00195671 ;
	END WENY[72]

	PIN WENY[73]
		USE SIGNAL ;
		DIRECTION OUTPUT ;
		SHAPE ABUTMENT ;
		PORT
			 LAYER M2 ;
			RECT 0.0098 109.5655 0.0481 109.6659 ;
			 LAYER M3 ;
			RECT 0.0098 109.5655 0.0481 109.6659 ;
			 LAYER V2 ;
			RECT 0.021 109.6404 0.0359 109.6529 ;
		END

		ANTENNADIFFAREA 0.00194719 ;
		ANTENNAPARTIALMETALAREA 0.00195671 ;
	END WENY[73]

	PIN WENY[74]
		USE SIGNAL ;
		DIRECTION OUTPUT ;
		SHAPE ABUTMENT ;
		PORT
			 LAYER M2 ;
			RECT 0.0098 110.8455 0.0481 110.9459 ;
			 LAYER M3 ;
			RECT 0.0098 110.8455 0.0481 110.9459 ;
			 LAYER V2 ;
			RECT 0.021 110.9204 0.0359 110.9329 ;
		END

		ANTENNADIFFAREA 0.00194719 ;
		ANTENNAPARTIALMETALAREA 0.00195671 ;
	END WENY[74]

	PIN WENY[75]
		USE SIGNAL ;
		DIRECTION OUTPUT ;
		SHAPE ABUTMENT ;
		PORT
			 LAYER M2 ;
			RECT 0.0098 112.1255 0.0481 112.2259 ;
			 LAYER M3 ;
			RECT 0.0098 112.1255 0.0481 112.2259 ;
			 LAYER V2 ;
			RECT 0.021 112.2004 0.0359 112.2129 ;
		END

		ANTENNADIFFAREA 0.00194719 ;
		ANTENNAPARTIALMETALAREA 0.00195671 ;
	END WENY[75]

	PIN WENY[76]
		USE SIGNAL ;
		DIRECTION OUTPUT ;
		SHAPE ABUTMENT ;
		PORT
			 LAYER M2 ;
			RECT 0.0098 113.4055 0.0481 113.5059 ;
			 LAYER M3 ;
			RECT 0.0098 113.4055 0.0481 113.5059 ;
			 LAYER V2 ;
			RECT 0.021 113.4804 0.0359 113.4929 ;
		END

		ANTENNADIFFAREA 0.00194719 ;
		ANTENNAPARTIALMETALAREA 0.00195671 ;
	END WENY[76]

	PIN WENY[77]
		USE SIGNAL ;
		DIRECTION OUTPUT ;
		SHAPE ABUTMENT ;
		PORT
			 LAYER M2 ;
			RECT 0.0098 114.6855 0.0481 114.7859 ;
			 LAYER M3 ;
			RECT 0.0098 114.6855 0.0481 114.7859 ;
			 LAYER V2 ;
			RECT 0.021 114.7604 0.0359 114.7729 ;
		END

		ANTENNADIFFAREA 0.00194719 ;
		ANTENNAPARTIALMETALAREA 0.00195671 ;
	END WENY[77]

	PIN WENY[78]
		USE SIGNAL ;
		DIRECTION OUTPUT ;
		SHAPE ABUTMENT ;
		PORT
			 LAYER M2 ;
			RECT 0.0098 115.9655 0.0481 116.0659 ;
			 LAYER M3 ;
			RECT 0.0098 115.9655 0.0481 116.0659 ;
			 LAYER V2 ;
			RECT 0.021 116.0404 0.0359 116.0529 ;
		END

		ANTENNADIFFAREA 0.00194719 ;
		ANTENNAPARTIALMETALAREA 0.00195671 ;
	END WENY[78]

	PIN WENY[79]
		USE SIGNAL ;
		DIRECTION OUTPUT ;
		SHAPE ABUTMENT ;
		PORT
			 LAYER M2 ;
			RECT 0.0098 117.2455 0.0481 117.3459 ;
			 LAYER M3 ;
			RECT 0.0098 117.2455 0.0481 117.3459 ;
			 LAYER V2 ;
			RECT 0.021 117.3204 0.0359 117.3329 ;
		END

		ANTENNADIFFAREA 0.00194719 ;
		ANTENNAPARTIALMETALAREA 0.00195671 ;
	END WENY[79]

	PIN WENY[7]
		USE SIGNAL ;
		DIRECTION OUTPUT ;
		SHAPE ABUTMENT ;
		PORT
			 LAYER M2 ;
			RECT 0.0098 10.2024 0.0481 10.3027 ;
			 LAYER M3 ;
			RECT 0.0098 10.2024 0.0481 10.3027 ;
			 LAYER V2 ;
			RECT 0.021 10.2153 0.0359 10.2278 ;
		END

		ANTENNADIFFAREA 0.00194719 ;
		ANTENNAPARTIALMETALAREA 0.00195671 ;
	END WENY[7]

	PIN WENY[80]
		USE SIGNAL ;
		DIRECTION OUTPUT ;
		SHAPE ABUTMENT ;
		PORT
			 LAYER M2 ;
			RECT 0.0098 118.5255 0.0481 118.6259 ;
			 LAYER M3 ;
			RECT 0.0098 118.5255 0.0481 118.6259 ;
			 LAYER V2 ;
			RECT 0.021 118.6004 0.0359 118.6129 ;
		END

		ANTENNADIFFAREA 0.00194719 ;
		ANTENNAPARTIALMETALAREA 0.00195671 ;
	END WENY[80]

	PIN WENY[81]
		USE SIGNAL ;
		DIRECTION OUTPUT ;
		SHAPE ABUTMENT ;
		PORT
			 LAYER M2 ;
			RECT 0.0098 119.8055 0.0481 119.9059 ;
			 LAYER M3 ;
			RECT 0.0098 119.8055 0.0481 119.9059 ;
			 LAYER V2 ;
			RECT 0.021 119.8804 0.0359 119.8929 ;
		END

		ANTENNADIFFAREA 0.00194719 ;
		ANTENNAPARTIALMETALAREA 0.00195671 ;
	END WENY[81]

	PIN WENY[82]
		USE SIGNAL ;
		DIRECTION OUTPUT ;
		SHAPE ABUTMENT ;
		PORT
			 LAYER M2 ;
			RECT 0.0098 121.0855 0.0481 121.1859 ;
			 LAYER M3 ;
			RECT 0.0098 121.0855 0.0481 121.1859 ;
			 LAYER V2 ;
			RECT 0.021 121.1604 0.0359 121.1729 ;
		END

		ANTENNADIFFAREA 0.00194719 ;
		ANTENNAPARTIALMETALAREA 0.00195671 ;
	END WENY[82]

	PIN WENY[83]
		USE SIGNAL ;
		DIRECTION OUTPUT ;
		SHAPE ABUTMENT ;
		PORT
			 LAYER M2 ;
			RECT 0.0098 122.3655 0.0481 122.4659 ;
			 LAYER M3 ;
			RECT 0.0098 122.3655 0.0481 122.4659 ;
			 LAYER V2 ;
			RECT 0.021 122.4404 0.0359 122.4529 ;
		END

		ANTENNADIFFAREA 0.00194719 ;
		ANTENNAPARTIALMETALAREA 0.00195671 ;
	END WENY[83]

	PIN WENY[84]
		USE SIGNAL ;
		DIRECTION OUTPUT ;
		SHAPE ABUTMENT ;
		PORT
			 LAYER M2 ;
			RECT 0.0098 123.6455 0.0481 123.7459 ;
			 LAYER M3 ;
			RECT 0.0098 123.6455 0.0481 123.7459 ;
			 LAYER V2 ;
			RECT 0.021 123.7204 0.0359 123.7329 ;
		END

		ANTENNADIFFAREA 0.00194719 ;
		ANTENNAPARTIALMETALAREA 0.00195671 ;
	END WENY[84]

	PIN WENY[85]
		USE SIGNAL ;
		DIRECTION OUTPUT ;
		SHAPE ABUTMENT ;
		PORT
			 LAYER M2 ;
			RECT 0.0098 124.9255 0.0481 125.0259 ;
			 LAYER M3 ;
			RECT 0.0098 124.9255 0.0481 125.0259 ;
			 LAYER V2 ;
			RECT 0.021 125.0004 0.0359 125.0129 ;
		END

		ANTENNADIFFAREA 0.00194719 ;
		ANTENNAPARTIALMETALAREA 0.00195671 ;
	END WENY[85]

	PIN WENY[86]
		USE SIGNAL ;
		DIRECTION OUTPUT ;
		SHAPE ABUTMENT ;
		PORT
			 LAYER M2 ;
			RECT 0.0098 126.2055 0.0481 126.3059 ;
			 LAYER M3 ;
			RECT 0.0098 126.2055 0.0481 126.3059 ;
			 LAYER V2 ;
			RECT 0.021 126.2804 0.0359 126.2929 ;
		END

		ANTENNADIFFAREA 0.00194719 ;
		ANTENNAPARTIALMETALAREA 0.00195671 ;
	END WENY[86]

	PIN WENY[87]
		USE SIGNAL ;
		DIRECTION OUTPUT ;
		SHAPE ABUTMENT ;
		PORT
			 LAYER M2 ;
			RECT 0.0098 127.4855 0.0481 127.5859 ;
			 LAYER M3 ;
			RECT 0.0098 127.4855 0.0481 127.5859 ;
			 LAYER V2 ;
			RECT 0.021 127.5604 0.0359 127.5729 ;
		END

		ANTENNADIFFAREA 0.00194719 ;
		ANTENNAPARTIALMETALAREA 0.00195671 ;
	END WENY[87]

	PIN WENY[88]
		USE SIGNAL ;
		DIRECTION OUTPUT ;
		SHAPE ABUTMENT ;
		PORT
			 LAYER M2 ;
			RECT 0.0098 128.7655 0.0481 128.8659 ;
			 LAYER M3 ;
			RECT 0.0098 128.7655 0.0481 128.8659 ;
			 LAYER V2 ;
			RECT 0.021 128.8404 0.0359 128.8529 ;
		END

		ANTENNADIFFAREA 0.00194719 ;
		ANTENNAPARTIALMETALAREA 0.00195671 ;
	END WENY[88]

	PIN WENY[89]
		USE SIGNAL ;
		DIRECTION OUTPUT ;
		SHAPE ABUTMENT ;
		PORT
			 LAYER M2 ;
			RECT 0.0098 130.0455 0.0481 130.1459 ;
			 LAYER M3 ;
			RECT 0.0098 130.0455 0.0481 130.1459 ;
			 LAYER V2 ;
			RECT 0.021 130.1204 0.0359 130.1329 ;
		END

		ANTENNADIFFAREA 0.00194719 ;
		ANTENNAPARTIALMETALAREA 0.00195671 ;
	END WENY[89]

	PIN WENY[8]
		USE SIGNAL ;
		DIRECTION OUTPUT ;
		SHAPE ABUTMENT ;
		PORT
			 LAYER M2 ;
			RECT 0.0098 11.4824 0.0481 11.5827 ;
			 LAYER M3 ;
			RECT 0.0098 11.4824 0.0481 11.5827 ;
			 LAYER V2 ;
			RECT 0.021 11.4953 0.0359 11.5078 ;
		END

		ANTENNADIFFAREA 0.00194719 ;
		ANTENNAPARTIALMETALAREA 0.00195671 ;
	END WENY[8]

	PIN WENY[90]
		USE SIGNAL ;
		DIRECTION OUTPUT ;
		SHAPE ABUTMENT ;
		PORT
			 LAYER M2 ;
			RECT 0.0098 131.3255 0.0481 131.4259 ;
			 LAYER M3 ;
			RECT 0.0098 131.3255 0.0481 131.4259 ;
			 LAYER V2 ;
			RECT 0.021 131.4004 0.0359 131.4129 ;
		END

		ANTENNADIFFAREA 0.00194719 ;
		ANTENNAPARTIALMETALAREA 0.00195671 ;
	END WENY[90]

	PIN WENY[91]
		USE SIGNAL ;
		DIRECTION OUTPUT ;
		SHAPE ABUTMENT ;
		PORT
			 LAYER M2 ;
			RECT 0.0098 132.6055 0.0481 132.7059 ;
			 LAYER M3 ;
			RECT 0.0098 132.6055 0.0481 132.7059 ;
			 LAYER V2 ;
			RECT 0.021 132.6804 0.0359 132.6929 ;
		END

		ANTENNADIFFAREA 0.00194719 ;
		ANTENNAPARTIALMETALAREA 0.00195671 ;
	END WENY[91]

	PIN WENY[92]
		USE SIGNAL ;
		DIRECTION OUTPUT ;
		SHAPE ABUTMENT ;
		PORT
			 LAYER M2 ;
			RECT 0.0098 133.8855 0.0481 133.9859 ;
			 LAYER M3 ;
			RECT 0.0098 133.8855 0.0481 133.9859 ;
			 LAYER V2 ;
			RECT 0.021 133.9604 0.0359 133.9729 ;
		END

		ANTENNADIFFAREA 0.00194719 ;
		ANTENNAPARTIALMETALAREA 0.00195671 ;
	END WENY[92]

	PIN WENY[93]
		USE SIGNAL ;
		DIRECTION OUTPUT ;
		SHAPE ABUTMENT ;
		PORT
			 LAYER M2 ;
			RECT 0.0098 135.1655 0.0481 135.2659 ;
			 LAYER M3 ;
			RECT 0.0098 135.1655 0.0481 135.2659 ;
			 LAYER V2 ;
			RECT 0.021 135.2404 0.0359 135.2529 ;
		END

		ANTENNADIFFAREA 0.00194719 ;
		ANTENNAPARTIALMETALAREA 0.00195671 ;
	END WENY[93]

	PIN WENY[94]
		USE SIGNAL ;
		DIRECTION OUTPUT ;
		SHAPE ABUTMENT ;
		PORT
			 LAYER M2 ;
			RECT 0.0098 136.4455 0.0481 136.5459 ;
			 LAYER M3 ;
			RECT 0.0098 136.4455 0.0481 136.5459 ;
			 LAYER V2 ;
			RECT 0.021 136.5204 0.0359 136.5329 ;
		END

		ANTENNADIFFAREA 0.00194719 ;
		ANTENNAPARTIALMETALAREA 0.00195671 ;
	END WENY[94]

	PIN WENY[95]
		USE SIGNAL ;
		DIRECTION OUTPUT ;
		SHAPE ABUTMENT ;
		PORT
			 LAYER M2 ;
			RECT 0.0098 137.7255 0.0481 137.8259 ;
			 LAYER M3 ;
			RECT 0.0098 137.7255 0.0481 137.8259 ;
			 LAYER V2 ;
			RECT 0.021 137.8004 0.0359 137.8129 ;
		END

		ANTENNADIFFAREA 0.00194719 ;
		ANTENNAPARTIALMETALAREA 0.00195671 ;
	END WENY[95]

	PIN WENY[9]
		USE SIGNAL ;
		DIRECTION OUTPUT ;
		SHAPE ABUTMENT ;
		PORT
			 LAYER M2 ;
			RECT 0.0098 12.7624 0.0481 12.8627 ;
			 LAYER M3 ;
			RECT 0.0098 12.7624 0.0481 12.8627 ;
			 LAYER V2 ;
			RECT 0.021 12.7753 0.0359 12.7878 ;
		END

		ANTENNADIFFAREA 0.00194719 ;
		ANTENNAPARTIALMETALAREA 0.00195671 ;
	END WENY[9]

	PIN WEN[0]
		USE SIGNAL ;
		DIRECTION INPUT ;
		SHAPE ABUTMENT ;
		PORT
			 LAYER M2 ;
			RECT 0.0714 1.029 0.1097 1.0667 ;
			 LAYER M3 ;
			RECT 0.0714 0.9663 0.1097 1.0667 ;
			 LAYER V2 ;
			RECT 0.0831 1.042 0.098 1.0545 ;
		END

		ANTENNAGATEAREA 0.00027817 ;
		ANTENNADIFFAREA 0.00194719 ;
		ANTENNAPARTIALMETALAREA 0.00195671 ;
	END WEN[0]

	PIN WEN[10]
		USE SIGNAL ;
		DIRECTION INPUT ;
		SHAPE ABUTMENT ;
		PORT
			 LAYER M2 ;
			RECT 0.0714 13.829 0.1097 13.8667 ;
			 LAYER M3 ;
			RECT 0.0714 13.7663 0.1097 13.8667 ;
			 LAYER V2 ;
			RECT 0.0831 13.842 0.098 13.8545 ;
		END

		ANTENNAGATEAREA 0.00027817 ;
		ANTENNADIFFAREA 0.00194719 ;
		ANTENNAPARTIALMETALAREA 0.00195671 ;
	END WEN[10]

	PIN WEN[11]
		USE SIGNAL ;
		DIRECTION INPUT ;
		SHAPE ABUTMENT ;
		PORT
			 LAYER M2 ;
			RECT 0.0714 15.109 0.1097 15.1467 ;
			 LAYER M3 ;
			RECT 0.0714 15.0463 0.1097 15.1467 ;
			 LAYER V2 ;
			RECT 0.0831 15.122 0.098 15.1345 ;
		END

		ANTENNAGATEAREA 0.00027817 ;
		ANTENNADIFFAREA 0.00194719 ;
		ANTENNAPARTIALMETALAREA 0.00195671 ;
	END WEN[11]

	PIN WEN[12]
		USE SIGNAL ;
		DIRECTION INPUT ;
		SHAPE ABUTMENT ;
		PORT
			 LAYER M2 ;
			RECT 0.0714 16.389 0.1097 16.4267 ;
			 LAYER M3 ;
			RECT 0.0714 16.3263 0.1097 16.4267 ;
			 LAYER V2 ;
			RECT 0.0831 16.402 0.098 16.4145 ;
		END

		ANTENNAGATEAREA 0.00027817 ;
		ANTENNADIFFAREA 0.00194719 ;
		ANTENNAPARTIALMETALAREA 0.00195671 ;
	END WEN[12]

	PIN WEN[13]
		USE SIGNAL ;
		DIRECTION INPUT ;
		SHAPE ABUTMENT ;
		PORT
			 LAYER M2 ;
			RECT 0.0714 17.669 0.1097 17.7067 ;
			 LAYER M3 ;
			RECT 0.0714 17.6063 0.1097 17.7067 ;
			 LAYER V2 ;
			RECT 0.0831 17.682 0.098 17.6945 ;
		END

		ANTENNAGATEAREA 0.00027817 ;
		ANTENNADIFFAREA 0.00194719 ;
		ANTENNAPARTIALMETALAREA 0.00195671 ;
	END WEN[13]

	PIN WEN[14]
		USE SIGNAL ;
		DIRECTION INPUT ;
		SHAPE ABUTMENT ;
		PORT
			 LAYER M2 ;
			RECT 0.0714 18.949 0.1097 18.9867 ;
			 LAYER M3 ;
			RECT 0.0714 18.8863 0.1097 18.9867 ;
			 LAYER V2 ;
			RECT 0.0831 18.962 0.098 18.9745 ;
		END

		ANTENNAGATEAREA 0.00027817 ;
		ANTENNADIFFAREA 0.00194719 ;
		ANTENNAPARTIALMETALAREA 0.00195671 ;
	END WEN[14]

	PIN WEN[15]
		USE SIGNAL ;
		DIRECTION INPUT ;
		SHAPE ABUTMENT ;
		PORT
			 LAYER M2 ;
			RECT 0.0714 20.229 0.1097 20.2667 ;
			 LAYER M3 ;
			RECT 0.0714 20.1663 0.1097 20.2667 ;
			 LAYER V2 ;
			RECT 0.0831 20.242 0.098 20.2545 ;
		END

		ANTENNAGATEAREA 0.00027817 ;
		ANTENNADIFFAREA 0.00194719 ;
		ANTENNAPARTIALMETALAREA 0.00195671 ;
	END WEN[15]

	PIN WEN[16]
		USE SIGNAL ;
		DIRECTION INPUT ;
		SHAPE ABUTMENT ;
		PORT
			 LAYER M2 ;
			RECT 0.0714 21.509 0.1097 21.5467 ;
			 LAYER M3 ;
			RECT 0.0714 21.4463 0.1097 21.5467 ;
			 LAYER V2 ;
			RECT 0.0831 21.522 0.098 21.5345 ;
		END

		ANTENNAGATEAREA 0.00027817 ;
		ANTENNADIFFAREA 0.00194719 ;
		ANTENNAPARTIALMETALAREA 0.00195671 ;
	END WEN[16]

	PIN WEN[17]
		USE SIGNAL ;
		DIRECTION INPUT ;
		SHAPE ABUTMENT ;
		PORT
			 LAYER M2 ;
			RECT 0.0714 22.789 0.1097 22.8267 ;
			 LAYER M3 ;
			RECT 0.0714 22.7263 0.1097 22.8267 ;
			 LAYER V2 ;
			RECT 0.0831 22.802 0.098 22.8145 ;
		END

		ANTENNAGATEAREA 0.00027817 ;
		ANTENNADIFFAREA 0.00194719 ;
		ANTENNAPARTIALMETALAREA 0.00195671 ;
	END WEN[17]

	PIN WEN[18]
		USE SIGNAL ;
		DIRECTION INPUT ;
		SHAPE ABUTMENT ;
		PORT
			 LAYER M2 ;
			RECT 0.0714 24.069 0.1097 24.1067 ;
			 LAYER M3 ;
			RECT 0.0714 24.0063 0.1097 24.1067 ;
			 LAYER V2 ;
			RECT 0.0831 24.082 0.098 24.0945 ;
		END

		ANTENNAGATEAREA 0.00027817 ;
		ANTENNADIFFAREA 0.00194719 ;
		ANTENNAPARTIALMETALAREA 0.00195671 ;
	END WEN[18]

	PIN WEN[19]
		USE SIGNAL ;
		DIRECTION INPUT ;
		SHAPE ABUTMENT ;
		PORT
			 LAYER M2 ;
			RECT 0.0714 25.349 0.1097 25.3867 ;
			 LAYER M3 ;
			RECT 0.0714 25.2863 0.1097 25.3867 ;
			 LAYER V2 ;
			RECT 0.0831 25.362 0.098 25.3745 ;
		END

		ANTENNAGATEAREA 0.00027817 ;
		ANTENNADIFFAREA 0.00194719 ;
		ANTENNAPARTIALMETALAREA 0.00195671 ;
	END WEN[19]

	PIN WEN[1]
		USE SIGNAL ;
		DIRECTION INPUT ;
		SHAPE ABUTMENT ;
		PORT
			 LAYER M2 ;
			RECT 0.0714 2.309 0.1097 2.3467 ;
			 LAYER M3 ;
			RECT 0.0714 2.2463 0.1097 2.3467 ;
			 LAYER V2 ;
			RECT 0.0831 2.322 0.098 2.3345 ;
		END

		ANTENNAGATEAREA 0.00027817 ;
		ANTENNADIFFAREA 0.00194719 ;
		ANTENNAPARTIALMETALAREA 0.00195671 ;
	END WEN[1]

	PIN WEN[20]
		USE SIGNAL ;
		DIRECTION INPUT ;
		SHAPE ABUTMENT ;
		PORT
			 LAYER M2 ;
			RECT 0.0714 26.629 0.1097 26.6667 ;
			 LAYER M3 ;
			RECT 0.0714 26.5663 0.1097 26.6667 ;
			 LAYER V2 ;
			RECT 0.0831 26.642 0.098 26.6545 ;
		END

		ANTENNAGATEAREA 0.00027817 ;
		ANTENNADIFFAREA 0.00194719 ;
		ANTENNAPARTIALMETALAREA 0.00195671 ;
	END WEN[20]

	PIN WEN[21]
		USE SIGNAL ;
		DIRECTION INPUT ;
		SHAPE ABUTMENT ;
		PORT
			 LAYER M2 ;
			RECT 0.0714 27.909 0.1097 27.9467 ;
			 LAYER M3 ;
			RECT 0.0714 27.8463 0.1097 27.9467 ;
			 LAYER V2 ;
			RECT 0.0831 27.922 0.098 27.9345 ;
		END

		ANTENNAGATEAREA 0.00027817 ;
		ANTENNADIFFAREA 0.00194719 ;
		ANTENNAPARTIALMETALAREA 0.00195671 ;
	END WEN[21]

	PIN WEN[22]
		USE SIGNAL ;
		DIRECTION INPUT ;
		SHAPE ABUTMENT ;
		PORT
			 LAYER M2 ;
			RECT 0.0714 29.189 0.1097 29.2267 ;
			 LAYER M3 ;
			RECT 0.0714 29.1263 0.1097 29.2267 ;
			 LAYER V2 ;
			RECT 0.0831 29.202 0.098 29.2145 ;
		END

		ANTENNAGATEAREA 0.00027817 ;
		ANTENNADIFFAREA 0.00194719 ;
		ANTENNAPARTIALMETALAREA 0.00195671 ;
	END WEN[22]

	PIN WEN[23]
		USE SIGNAL ;
		DIRECTION INPUT ;
		SHAPE ABUTMENT ;
		PORT
			 LAYER M2 ;
			RECT 0.0714 30.469 0.1097 30.5067 ;
			 LAYER M3 ;
			RECT 0.0714 30.4063 0.1097 30.5067 ;
			 LAYER V2 ;
			RECT 0.0831 30.482 0.098 30.4945 ;
		END

		ANTENNAGATEAREA 0.00027817 ;
		ANTENNADIFFAREA 0.00194719 ;
		ANTENNAPARTIALMETALAREA 0.00195671 ;
	END WEN[23]

	PIN WEN[24]
		USE SIGNAL ;
		DIRECTION INPUT ;
		SHAPE ABUTMENT ;
		PORT
			 LAYER M2 ;
			RECT 0.0714 39.4478 0.1097 39.4855 ;
			 LAYER M3 ;
			RECT 0.0714 39.3851 0.1097 39.4855 ;
			 LAYER V2 ;
			RECT 0.0831 39.4608 0.098 39.4733 ;
		END

		ANTENNAGATEAREA 0.00027817 ;
		ANTENNADIFFAREA 0.00194719 ;
		ANTENNAPARTIALMETALAREA 0.00195671 ;
	END WEN[24]

	PIN WEN[25]
		USE SIGNAL ;
		DIRECTION INPUT ;
		SHAPE ABUTMENT ;
		PORT
			 LAYER M2 ;
			RECT 0.0714 40.7278 0.1097 40.7655 ;
			 LAYER M3 ;
			RECT 0.0714 40.6651 0.1097 40.7655 ;
			 LAYER V2 ;
			RECT 0.0831 40.7408 0.098 40.7533 ;
		END

		ANTENNAGATEAREA 0.00027817 ;
		ANTENNADIFFAREA 0.00194719 ;
		ANTENNAPARTIALMETALAREA 0.00195671 ;
	END WEN[25]

	PIN WEN[26]
		USE SIGNAL ;
		DIRECTION INPUT ;
		SHAPE ABUTMENT ;
		PORT
			 LAYER M2 ;
			RECT 0.0714 42.0078 0.1097 42.0455 ;
			 LAYER M3 ;
			RECT 0.0714 41.9451 0.1097 42.0455 ;
			 LAYER V2 ;
			RECT 0.0831 42.0208 0.098 42.0333 ;
		END

		ANTENNAGATEAREA 0.00027817 ;
		ANTENNADIFFAREA 0.00194719 ;
		ANTENNAPARTIALMETALAREA 0.00195671 ;
	END WEN[26]

	PIN WEN[27]
		USE SIGNAL ;
		DIRECTION INPUT ;
		SHAPE ABUTMENT ;
		PORT
			 LAYER M2 ;
			RECT 0.0714 43.2878 0.1097 43.3255 ;
			 LAYER M3 ;
			RECT 0.0714 43.2251 0.1097 43.3255 ;
			 LAYER V2 ;
			RECT 0.0831 43.3008 0.098 43.3133 ;
		END

		ANTENNAGATEAREA 0.00027817 ;
		ANTENNADIFFAREA 0.00194719 ;
		ANTENNAPARTIALMETALAREA 0.00195671 ;
	END WEN[27]

	PIN WEN[28]
		USE SIGNAL ;
		DIRECTION INPUT ;
		SHAPE ABUTMENT ;
		PORT
			 LAYER M2 ;
			RECT 0.0714 44.5678 0.1097 44.6055 ;
			 LAYER M3 ;
			RECT 0.0714 44.5051 0.1097 44.6055 ;
			 LAYER V2 ;
			RECT 0.0831 44.5808 0.098 44.5933 ;
		END

		ANTENNAGATEAREA 0.00027817 ;
		ANTENNADIFFAREA 0.00194719 ;
		ANTENNAPARTIALMETALAREA 0.00195671 ;
	END WEN[28]

	PIN WEN[29]
		USE SIGNAL ;
		DIRECTION INPUT ;
		SHAPE ABUTMENT ;
		PORT
			 LAYER M2 ;
			RECT 0.0714 45.8478 0.1097 45.8855 ;
			 LAYER M3 ;
			RECT 0.0714 45.7851 0.1097 45.8855 ;
			 LAYER V2 ;
			RECT 0.0831 45.8608 0.098 45.8733 ;
		END

		ANTENNAGATEAREA 0.00027817 ;
		ANTENNADIFFAREA 0.00194719 ;
		ANTENNAPARTIALMETALAREA 0.00195671 ;
	END WEN[29]

	PIN WEN[2]
		USE SIGNAL ;
		DIRECTION INPUT ;
		SHAPE ABUTMENT ;
		PORT
			 LAYER M2 ;
			RECT 0.0714 3.589 0.1097 3.6267 ;
			 LAYER M3 ;
			RECT 0.0714 3.5263 0.1097 3.6267 ;
			 LAYER V2 ;
			RECT 0.0831 3.602 0.098 3.6145 ;
		END

		ANTENNAGATEAREA 0.00027817 ;
		ANTENNADIFFAREA 0.00194719 ;
		ANTENNAPARTIALMETALAREA 0.00195671 ;
	END WEN[2]

	PIN WEN[30]
		USE SIGNAL ;
		DIRECTION INPUT ;
		SHAPE ABUTMENT ;
		PORT
			 LAYER M2 ;
			RECT 0.0714 47.1278 0.1097 47.1655 ;
			 LAYER M3 ;
			RECT 0.0714 47.0651 0.1097 47.1655 ;
			 LAYER V2 ;
			RECT 0.0831 47.1408 0.098 47.1533 ;
		END

		ANTENNAGATEAREA 0.00027817 ;
		ANTENNADIFFAREA 0.00194719 ;
		ANTENNAPARTIALMETALAREA 0.00195671 ;
	END WEN[30]

	PIN WEN[31]
		USE SIGNAL ;
		DIRECTION INPUT ;
		SHAPE ABUTMENT ;
		PORT
			 LAYER M2 ;
			RECT 0.0714 48.4078 0.1097 48.4455 ;
			 LAYER M3 ;
			RECT 0.0714 48.3451 0.1097 48.4455 ;
			 LAYER V2 ;
			RECT 0.0831 48.4208 0.098 48.4333 ;
		END

		ANTENNAGATEAREA 0.00027817 ;
		ANTENNADIFFAREA 0.00194719 ;
		ANTENNAPARTIALMETALAREA 0.00195671 ;
	END WEN[31]

	PIN WEN[32]
		USE SIGNAL ;
		DIRECTION INPUT ;
		SHAPE ABUTMENT ;
		PORT
			 LAYER M2 ;
			RECT 0.0714 49.6878 0.1097 49.7255 ;
			 LAYER M3 ;
			RECT 0.0714 49.6251 0.1097 49.7255 ;
			 LAYER V2 ;
			RECT 0.0831 49.7008 0.098 49.7133 ;
		END

		ANTENNAGATEAREA 0.00027817 ;
		ANTENNADIFFAREA 0.00194719 ;
		ANTENNAPARTIALMETALAREA 0.00195671 ;
	END WEN[32]

	PIN WEN[33]
		USE SIGNAL ;
		DIRECTION INPUT ;
		SHAPE ABUTMENT ;
		PORT
			 LAYER M2 ;
			RECT 0.0714 50.9678 0.1097 51.0055 ;
			 LAYER M3 ;
			RECT 0.0714 50.9051 0.1097 51.0055 ;
			 LAYER V2 ;
			RECT 0.0831 50.9808 0.098 50.9933 ;
		END

		ANTENNAGATEAREA 0.00027817 ;
		ANTENNADIFFAREA 0.00194719 ;
		ANTENNAPARTIALMETALAREA 0.00195671 ;
	END WEN[33]

	PIN WEN[34]
		USE SIGNAL ;
		DIRECTION INPUT ;
		SHAPE ABUTMENT ;
		PORT
			 LAYER M2 ;
			RECT 0.0714 52.2478 0.1097 52.2855 ;
			 LAYER M3 ;
			RECT 0.0714 52.1851 0.1097 52.2855 ;
			 LAYER V2 ;
			RECT 0.0831 52.2608 0.098 52.2733 ;
		END

		ANTENNAGATEAREA 0.00027817 ;
		ANTENNADIFFAREA 0.00194719 ;
		ANTENNAPARTIALMETALAREA 0.00195671 ;
	END WEN[34]

	PIN WEN[35]
		USE SIGNAL ;
		DIRECTION INPUT ;
		SHAPE ABUTMENT ;
		PORT
			 LAYER M2 ;
			RECT 0.0714 53.5278 0.1097 53.5655 ;
			 LAYER M3 ;
			RECT 0.0714 53.4651 0.1097 53.5655 ;
			 LAYER V2 ;
			RECT 0.0831 53.5408 0.098 53.5533 ;
		END

		ANTENNAGATEAREA 0.00027817 ;
		ANTENNADIFFAREA 0.00194719 ;
		ANTENNAPARTIALMETALAREA 0.00195671 ;
	END WEN[35]

	PIN WEN[36]
		USE SIGNAL ;
		DIRECTION INPUT ;
		SHAPE ABUTMENT ;
		PORT
			 LAYER M2 ;
			RECT 0.0714 54.8078 0.1097 54.8455 ;
			 LAYER M3 ;
			RECT 0.0714 54.7451 0.1097 54.8455 ;
			 LAYER V2 ;
			RECT 0.0831 54.8208 0.098 54.8333 ;
		END

		ANTENNAGATEAREA 0.00027817 ;
		ANTENNADIFFAREA 0.00194719 ;
		ANTENNAPARTIALMETALAREA 0.00195671 ;
	END WEN[36]

	PIN WEN[37]
		USE SIGNAL ;
		DIRECTION INPUT ;
		SHAPE ABUTMENT ;
		PORT
			 LAYER M2 ;
			RECT 0.0714 56.0878 0.1097 56.1255 ;
			 LAYER M3 ;
			RECT 0.0714 56.0251 0.1097 56.1255 ;
			 LAYER V2 ;
			RECT 0.0831 56.1008 0.098 56.1133 ;
		END

		ANTENNAGATEAREA 0.00027817 ;
		ANTENNADIFFAREA 0.00194719 ;
		ANTENNAPARTIALMETALAREA 0.00195671 ;
	END WEN[37]

	PIN WEN[38]
		USE SIGNAL ;
		DIRECTION INPUT ;
		SHAPE ABUTMENT ;
		PORT
			 LAYER M2 ;
			RECT 0.0714 57.7067 0.1097 57.7443 ;
			RECT 0.0714 57.7067 0.1097 57.7443 ;
			 LAYER M3 ;
			RECT 0.0714 57.7067 0.1097 57.8071 ;
			RECT 0.0714 57.7067 0.1097 57.8071 ;
			 LAYER V2 ;
			RECT 0.0831 57.7188 0.098 57.7314 ;
		END

		ANTENNAGATEAREA 0.00027817 ;
		ANTENNADIFFAREA 0.00194719 ;
		ANTENNAPARTIALMETALAREA 0.00195671 ;
	END WEN[38]

	PIN WEN[39]
		USE SIGNAL ;
		DIRECTION INPUT ;
		SHAPE ABUTMENT ;
		PORT
			 LAYER M2 ;
			RECT 0.0098 59.2753 0.0481 59.3129 ;
			 LAYER M3 ;
			RECT 0.0098 59.2125 0.0481 59.3129 ;
			 LAYER V2 ;
			RECT 0.0215 59.2875 0.0364 59.3 ;
		END

		ANTENNAGATEAREA 0.00027817 ;
		ANTENNADIFFAREA 0.00194719 ;
		ANTENNAPARTIALMETALAREA 0.00195671 ;
	END WEN[39]

	PIN WEN[3]
		USE SIGNAL ;
		DIRECTION INPUT ;
		SHAPE ABUTMENT ;
		PORT
			 LAYER M2 ;
			RECT 0.0714 4.869 0.1097 4.9067 ;
			 LAYER M3 ;
			RECT 0.0714 4.8063 0.1097 4.9067 ;
			 LAYER V2 ;
			RECT 0.0831 4.882 0.098 4.8945 ;
		END

		ANTENNAGATEAREA 0.00027817 ;
		ANTENNADIFFAREA 0.00194719 ;
		ANTENNAPARTIALMETALAREA 0.00195671 ;
	END WEN[3]

	PIN WEN[40]
		USE SIGNAL ;
		DIRECTION INPUT ;
		SHAPE ABUTMENT ;
		PORT
			 LAYER M2 ;
			RECT 0.0714 60.1914 0.1097 60.229 ;
			 LAYER M3 ;
			RECT 0.0714 60.1914 0.1097 60.2918 ;
			 LAYER V2 ;
			RECT 0.0831 60.2035 0.098 60.2161 ;
		END

		ANTENNAGATEAREA 0.00027817 ;
		ANTENNADIFFAREA 0.00194719 ;
		ANTENNAPARTIALMETALAREA 0.00195671 ;
	END WEN[40]

	PIN WEN[41]
		USE SIGNAL ;
		DIRECTION INPUT ;
		SHAPE ABUTMENT ;
		PORT
			 LAYER M2 ;
			RECT 0.0714 61.4714 0.1097 61.509 ;
			 LAYER M3 ;
			RECT 0.0714 61.4714 0.1097 61.5718 ;
			 LAYER V2 ;
			RECT 0.0831 61.4835 0.098 61.4961 ;
		END

		ANTENNAGATEAREA 0.00027817 ;
		ANTENNADIFFAREA 0.00194719 ;
		ANTENNAPARTIALMETALAREA 0.00195671 ;
	END WEN[41]

	PIN WEN[42]
		USE SIGNAL ;
		DIRECTION INPUT ;
		SHAPE ABUTMENT ;
		PORT
			 LAYER M2 ;
			RECT 0.0714 62.8267 0.1097 62.8643 ;
			 LAYER M3 ;
			RECT 0.0714 62.8267 0.1097 62.9271 ;
			 LAYER V2 ;
			RECT 0.0831 62.8388 0.098 62.8514 ;
		END

		ANTENNAGATEAREA 0.00027817 ;
		ANTENNADIFFAREA 0.00194719 ;
		ANTENNAPARTIALMETALAREA 0.00195671 ;
	END WEN[42]

	PIN WEN[43]
		USE SIGNAL ;
		DIRECTION INPUT ;
		SHAPE ABUTMENT ;
		PORT
			 LAYER M2 ;
			RECT 0.0714 64.2573 0.1097 64.2949 ;
			 LAYER M3 ;
			RECT 0.0714 64.2573 0.1097 64.3576 ;
			 LAYER V2 ;
			RECT 0.0831 64.2694 0.098 64.282 ;
		END

		ANTENNAGATEAREA 0.00027817 ;
		ANTENNADIFFAREA 0.00194719 ;
		ANTENNAPARTIALMETALAREA 0.00195671 ;
	END WEN[43]

	PIN WEN[44]
		USE SIGNAL ;
		DIRECTION INPUT ;
		SHAPE ABUTMENT ;
		PORT
			 LAYER M2 ;
			RECT 0.0714 65.5373 0.1097 65.5749 ;
			 LAYER M3 ;
			RECT 0.0714 65.5373 0.1097 65.6376 ;
			 LAYER V2 ;
			RECT 0.0831 65.5494 0.098 65.562 ;
		END

		ANTENNAGATEAREA 0.00027817 ;
		ANTENNADIFFAREA 0.00194719 ;
		ANTENNAPARTIALMETALAREA 0.00195671 ;
	END WEN[44]

	PIN WEN[45]
		USE SIGNAL ;
		DIRECTION INPUT ;
		SHAPE ABUTMENT ;
		PORT
			 LAYER M2 ;
			RECT 0.0714 66.5914 0.1097 66.629 ;
			 LAYER M3 ;
			RECT 0.0714 66.5914 0.1097 66.6918 ;
			 LAYER V2 ;
			RECT 0.0831 66.6035 0.098 66.6161 ;
		END

		ANTENNAGATEAREA 0.00027817 ;
		ANTENNADIFFAREA 0.00194719 ;
		ANTENNAPARTIALMETALAREA 0.00195671 ;
	END WEN[45]

	PIN WEN[46]
		USE SIGNAL ;
		DIRECTION INPUT ;
		SHAPE ABUTMENT ;
		PORT
			 LAYER M2 ;
			RECT 0.0714 67.9467 0.1097 67.9843 ;
			 LAYER M3 ;
			RECT 0.0714 67.9467 0.1097 68.0471 ;
			 LAYER V2 ;
			RECT 0.0831 67.9588 0.098 67.9714 ;
		END

		ANTENNAGATEAREA 0.00027817 ;
		ANTENNADIFFAREA 0.00194719 ;
		ANTENNAPARTIALMETALAREA 0.00195671 ;
	END WEN[46]

	PIN WEN[47]
		USE SIGNAL ;
		DIRECTION INPUT ;
		SHAPE ABUTMENT ;
		PORT
			 LAYER M2 ;
			RECT 0.0098 69.1388 0.0481 69.1765 ;
			 LAYER M3 ;
			RECT 0.0098 69.0761 0.0481 69.1765 ;
			 LAYER V2 ;
			RECT 0.0215 69.151 0.0364 69.1635 ;
		END

		ANTENNAGATEAREA 0.00027817 ;
		ANTENNADIFFAREA 0.00194719 ;
		ANTENNAPARTIALMETALAREA 0.00195671 ;
	END WEN[47]

	PIN WEN[48]
		USE SIGNAL ;
		DIRECTION INPUT ;
		SHAPE ABUTMENT ;
		PORT
			 LAYER M2 ;
			RECT 0.0098 69.8918 0.0481 69.9294 ;
			 LAYER M3 ;
			RECT 0.0098 69.8918 0.0481 69.9922 ;
			 LAYER V2 ;
			RECT 0.0215 69.9047 0.0364 69.9173 ;
		END

		ANTENNAGATEAREA 0.00027817 ;
		ANTENNADIFFAREA 0.00194719 ;
		ANTENNAPARTIALMETALAREA 0.00195671 ;
	END WEN[48]

	PIN WEN[49]
		USE SIGNAL ;
		DIRECTION INPUT ;
		SHAPE ABUTMENT ;
		PORT
			 LAYER M2 ;
			RECT 0.0714 71.0839 0.1097 71.1216 ;
			 LAYER M3 ;
			RECT 0.0714 71.0212 0.1097 71.1216 ;
			 LAYER V2 ;
			RECT 0.0831 71.0969 0.098 71.1094 ;
		END

		ANTENNAGATEAREA 0.00027817 ;
		ANTENNADIFFAREA 0.00194719 ;
		ANTENNAPARTIALMETALAREA 0.00195671 ;
	END WEN[49]

	PIN WEN[4]
		USE SIGNAL ;
		DIRECTION INPUT ;
		SHAPE ABUTMENT ;
		PORT
			 LAYER M2 ;
			RECT 0.0714 6.149 0.1097 6.1867 ;
			 LAYER M3 ;
			RECT 0.0714 6.0863 0.1097 6.1867 ;
			 LAYER V2 ;
			RECT 0.0831 6.162 0.098 6.1745 ;
		END

		ANTENNAGATEAREA 0.00027817 ;
		ANTENNADIFFAREA 0.00194719 ;
		ANTENNAPARTIALMETALAREA 0.00195671 ;
	END WEN[4]

	PIN WEN[50]
		USE SIGNAL ;
		DIRECTION INPUT ;
		SHAPE ABUTMENT ;
		PORT
			 LAYER M2 ;
			RECT 0.0714 72.4392 0.1097 72.4769 ;
			 LAYER M3 ;
			RECT 0.0714 72.3765 0.1097 72.4769 ;
			 LAYER V2 ;
			RECT 0.0831 72.4522 0.098 72.4647 ;
		END

		ANTENNAGATEAREA 0.00027817 ;
		ANTENNADIFFAREA 0.00194719 ;
		ANTENNAPARTIALMETALAREA 0.00195671 ;
	END WEN[50]

	PIN WEN[51]
		USE SIGNAL ;
		DIRECTION INPUT ;
		SHAPE ABUTMENT ;
		PORT
			 LAYER M2 ;
			RECT 0.0098 73.5059 0.0481 73.5435 ;
			 LAYER M3 ;
			RECT 0.0098 73.5059 0.0481 73.6063 ;
			 LAYER V2 ;
			RECT 0.0215 73.5188 0.0364 73.5314 ;
		END

		ANTENNAGATEAREA 0.00027817 ;
		ANTENNADIFFAREA 0.00194719 ;
		ANTENNAPARTIALMETALAREA 0.00195671 ;
	END WEN[51]

	PIN WEN[52]
		USE SIGNAL ;
		DIRECTION INPUT ;
		SHAPE ABUTMENT ;
		PORT
			 LAYER M2 ;
			RECT 0.0714 74.7733 0.1097 74.811 ;
			 LAYER M3 ;
			RECT 0.0714 74.7106 0.1097 74.811 ;
			 LAYER V2 ;
			RECT 0.0831 74.7863 0.098 74.7988 ;
		END

		ANTENNAGATEAREA 0.00027817 ;
		ANTENNADIFFAREA 0.00194719 ;
		ANTENNAPARTIALMETALAREA 0.00195671 ;
	END WEN[52]

	PIN WEN[53]
		USE SIGNAL ;
		DIRECTION INPUT ;
		SHAPE ABUTMENT ;
		PORT
			 LAYER M2 ;
			RECT 0.0714 76.2039 0.1097 76.2416 ;
			 LAYER M3 ;
			RECT 0.0714 76.1412 0.1097 76.2416 ;
			 LAYER V2 ;
			RECT 0.0831 76.2169 0.098 76.2294 ;
		END

		ANTENNAGATEAREA 0.00027817 ;
		ANTENNADIFFAREA 0.00194719 ;
		ANTENNAPARTIALMETALAREA 0.00195671 ;
	END WEN[53]

	PIN WEN[54]
		USE SIGNAL ;
		DIRECTION INPUT ;
		SHAPE ABUTMENT ;
		PORT
			 LAYER M2 ;
			RECT 0.0714 77.5592 0.1097 77.5969 ;
			 LAYER M3 ;
			RECT 0.0714 77.4965 0.1097 77.5969 ;
			 LAYER V2 ;
			RECT 0.0831 77.5722 0.098 77.5847 ;
		END

		ANTENNAGATEAREA 0.00027817 ;
		ANTENNADIFFAREA 0.00194719 ;
		ANTENNAPARTIALMETALAREA 0.00195671 ;
	END WEN[54]

	PIN WEN[55]
		USE SIGNAL ;
		DIRECTION INPUT ;
		SHAPE ABUTMENT ;
		PORT
			 LAYER M2 ;
			RECT 0.0714 78.8392 0.1097 78.8769 ;
			 LAYER M3 ;
			RECT 0.0714 78.7765 0.1097 78.8769 ;
			 LAYER V2 ;
			RECT 0.0831 78.8522 0.098 78.8647 ;
		END

		ANTENNAGATEAREA 0.00027817 ;
		ANTENNADIFFAREA 0.00194719 ;
		ANTENNAPARTIALMETALAREA 0.00195671 ;
	END WEN[55]

	PIN WEN[56]
		USE SIGNAL ;
		DIRECTION INPUT ;
		SHAPE ABUTMENT ;
		PORT
			 LAYER M2 ;
			RECT 0.0098 79.68 0.0481 79.7804 ;
			 LAYER M3 ;
			RECT 0.0098 79.68 0.0481 79.7804 ;
			 LAYER V2 ;
			RECT 0.021 79.7549 0.0359 79.7675 ;
		END

		ANTENNAGATEAREA 0.00027817 ;
		ANTENNADIFFAREA 0.00194719 ;
		ANTENNAPARTIALMETALAREA 0.00195671 ;
	END WEN[56]

	PIN WEN[57]
		USE SIGNAL ;
		DIRECTION INPUT ;
		SHAPE ABUTMENT ;
		PORT
			 LAYER M2 ;
			RECT 0.0714 81.3239 0.1097 81.3616 ;
			 LAYER M3 ;
			RECT 0.0714 81.2612 0.1097 81.3616 ;
			 LAYER V2 ;
			RECT 0.0831 81.3369 0.098 81.3494 ;
		END

		ANTENNAGATEAREA 0.00027817 ;
		ANTENNADIFFAREA 0.00194719 ;
		ANTENNAPARTIALMETALAREA 0.00195671 ;
	END WEN[57]

	PIN WEN[58]
		USE SIGNAL ;
		DIRECTION INPUT ;
		SHAPE ABUTMENT ;
		PORT
			 LAYER M2 ;
			RECT 0.0714 82.9427 0.1097 82.9804 ;
			 LAYER M3 ;
			RECT 0.0714 82.9427 0.1097 83.0431 ;
			 LAYER V2 ;
			RECT 0.0831 82.9549 0.098 82.9675 ;
		END

		ANTENNAGATEAREA 0.00027817 ;
		ANTENNADIFFAREA 0.00194719 ;
		ANTENNAPARTIALMETALAREA 0.00195671 ;
	END WEN[58]

	PIN WEN[59]
		USE SIGNAL ;
		DIRECTION INPUT ;
		SHAPE ABUTMENT ;
		PORT
			 LAYER M2 ;
			RECT 0.0714 84.2227 0.1097 84.2604 ;
			 LAYER M3 ;
			RECT 0.0714 84.2227 0.1097 84.3231 ;
			 LAYER V2 ;
			RECT 0.0831 84.2349 0.098 84.2475 ;
		END

		ANTENNAGATEAREA 0.00027817 ;
		ANTENNADIFFAREA 0.00194719 ;
		ANTENNAPARTIALMETALAREA 0.00195671 ;
	END WEN[59]

	PIN WEN[5]
		USE SIGNAL ;
		DIRECTION INPUT ;
		SHAPE ABUTMENT ;
		PORT
			 LAYER M2 ;
			RECT 0.0714 7.429 0.1097 7.4667 ;
			 LAYER M3 ;
			RECT 0.0714 7.3663 0.1097 7.4667 ;
			 LAYER V2 ;
			RECT 0.0831 7.442 0.098 7.4545 ;
		END

		ANTENNAGATEAREA 0.00027817 ;
		ANTENNADIFFAREA 0.00194719 ;
		ANTENNAPARTIALMETALAREA 0.00195671 ;
	END WEN[5]

	PIN WEN[60]
		USE SIGNAL ;
		DIRECTION INPUT ;
		SHAPE ABUTMENT ;
		PORT
			 LAYER M2 ;
			RECT 0.0714 85.5027 0.1097 85.5404 ;
			 LAYER M3 ;
			RECT 0.0714 85.5027 0.1097 85.6031 ;
			 LAYER V2 ;
			RECT 0.0831 85.5149 0.098 85.5275 ;
		END

		ANTENNAGATEAREA 0.00027817 ;
		ANTENNADIFFAREA 0.00194719 ;
		ANTENNAPARTIALMETALAREA 0.00195671 ;
	END WEN[60]

	PIN WEN[61]
		USE SIGNAL ;
		DIRECTION INPUT ;
		SHAPE ABUTMENT ;
		PORT
			 LAYER M2 ;
			RECT 0.0714 86.7827 0.1097 86.8204 ;
			 LAYER M3 ;
			RECT 0.0714 86.7827 0.1097 86.8831 ;
			 LAYER V2 ;
			RECT 0.0831 86.7949 0.098 86.8075 ;
		END

		ANTENNAGATEAREA 0.00027817 ;
		ANTENNADIFFAREA 0.00194719 ;
		ANTENNAPARTIALMETALAREA 0.00195671 ;
	END WEN[61]

	PIN WEN[62]
		USE SIGNAL ;
		DIRECTION INPUT ;
		SHAPE ABUTMENT ;
		PORT
			 LAYER M2 ;
			RECT 0.0714 88.0627 0.1097 88.1004 ;
			 LAYER M3 ;
			RECT 0.0714 88.0627 0.1097 88.1631 ;
			 LAYER V2 ;
			RECT 0.0831 88.0749 0.098 88.0875 ;
		END

		ANTENNAGATEAREA 0.00027817 ;
		ANTENNADIFFAREA 0.00194719 ;
		ANTENNAPARTIALMETALAREA 0.00195671 ;
	END WEN[62]

	PIN WEN[63]
		USE SIGNAL ;
		DIRECTION INPUT ;
		SHAPE ABUTMENT ;
		PORT
			 LAYER M2 ;
			RECT 0.0714 89.3427 0.1097 89.3804 ;
			 LAYER M3 ;
			RECT 0.0714 89.3427 0.1097 89.4431 ;
			 LAYER V2 ;
			RECT 0.0831 89.3549 0.098 89.3675 ;
		END

		ANTENNAGATEAREA 0.00027817 ;
		ANTENNADIFFAREA 0.00194719 ;
		ANTENNAPARTIALMETALAREA 0.00195671 ;
	END WEN[63]

	PIN WEN[64]
		USE SIGNAL ;
		DIRECTION INPUT ;
		SHAPE ABUTMENT ;
		PORT
			 LAYER M2 ;
			RECT 0.0714 90.6227 0.1097 90.6604 ;
			 LAYER M3 ;
			RECT 0.0714 90.6227 0.1097 90.7231 ;
			 LAYER V2 ;
			RECT 0.0831 90.6349 0.098 90.6475 ;
		END

		ANTENNAGATEAREA 0.00027817 ;
		ANTENNADIFFAREA 0.00194719 ;
		ANTENNAPARTIALMETALAREA 0.00195671 ;
	END WEN[64]

	PIN WEN[65]
		USE SIGNAL ;
		DIRECTION INPUT ;
		SHAPE ABUTMENT ;
		PORT
			 LAYER M2 ;
			RECT 0.0714 91.9027 0.1097 91.9404 ;
			 LAYER M3 ;
			RECT 0.0714 91.9027 0.1097 92.0031 ;
			 LAYER V2 ;
			RECT 0.0831 91.9149 0.098 91.9275 ;
		END

		ANTENNAGATEAREA 0.00027817 ;
		ANTENNADIFFAREA 0.00194719 ;
		ANTENNAPARTIALMETALAREA 0.00195671 ;
	END WEN[65]

	PIN WEN[66]
		USE SIGNAL ;
		DIRECTION INPUT ;
		SHAPE ABUTMENT ;
		PORT
			 LAYER M2 ;
			RECT 0.0714 93.1827 0.1097 93.2204 ;
			 LAYER M3 ;
			RECT 0.0714 93.1827 0.1097 93.2831 ;
			 LAYER V2 ;
			RECT 0.0831 93.1949 0.098 93.2075 ;
		END

		ANTENNAGATEAREA 0.00027817 ;
		ANTENNADIFFAREA 0.00194719 ;
		ANTENNAPARTIALMETALAREA 0.00195671 ;
	END WEN[66]

	PIN WEN[67]
		USE SIGNAL ;
		DIRECTION INPUT ;
		SHAPE ABUTMENT ;
		PORT
			 LAYER M2 ;
			RECT 0.0714 94.4627 0.1097 94.5004 ;
			 LAYER M3 ;
			RECT 0.0714 94.4627 0.1097 94.5631 ;
			 LAYER V2 ;
			RECT 0.0831 94.4749 0.098 94.4875 ;
		END

		ANTENNAGATEAREA 0.00027817 ;
		ANTENNADIFFAREA 0.00194719 ;
		ANTENNAPARTIALMETALAREA 0.00195671 ;
	END WEN[67]

	PIN WEN[68]
		USE SIGNAL ;
		DIRECTION INPUT ;
		SHAPE ABUTMENT ;
		PORT
			 LAYER M2 ;
			RECT 0.0714 95.7427 0.1097 95.7804 ;
			 LAYER M3 ;
			RECT 0.0714 95.7427 0.1097 95.8431 ;
			 LAYER V2 ;
			RECT 0.0831 95.7549 0.098 95.7675 ;
		END

		ANTENNAGATEAREA 0.00027817 ;
		ANTENNADIFFAREA 0.00194719 ;
		ANTENNAPARTIALMETALAREA 0.00195671 ;
	END WEN[68]

	PIN WEN[69]
		USE SIGNAL ;
		DIRECTION INPUT ;
		SHAPE ABUTMENT ;
		PORT
			 LAYER M2 ;
			RECT 0.0714 97.0227 0.1097 97.0604 ;
			 LAYER M3 ;
			RECT 0.0714 97.0227 0.1097 97.1231 ;
			 LAYER V2 ;
			RECT 0.0831 97.0349 0.098 97.0475 ;
		END

		ANTENNAGATEAREA 0.00027817 ;
		ANTENNADIFFAREA 0.00194719 ;
		ANTENNAPARTIALMETALAREA 0.00195671 ;
	END WEN[69]

	PIN WEN[6]
		USE SIGNAL ;
		DIRECTION INPUT ;
		SHAPE ABUTMENT ;
		PORT
			 LAYER M2 ;
			RECT 0.0714 8.709 0.1097 8.7467 ;
			 LAYER M3 ;
			RECT 0.0714 8.6463 0.1097 8.7467 ;
			 LAYER V2 ;
			RECT 0.0831 8.722 0.098 8.7345 ;
		END

		ANTENNAGATEAREA 0.00027817 ;
		ANTENNADIFFAREA 0.00194719 ;
		ANTENNAPARTIALMETALAREA 0.00195671 ;
	END WEN[6]

	PIN WEN[70]
		USE SIGNAL ;
		DIRECTION INPUT ;
		SHAPE ABUTMENT ;
		PORT
			 LAYER M2 ;
			RECT 0.0714 98.3027 0.1097 98.3404 ;
			 LAYER M3 ;
			RECT 0.0714 98.3027 0.1097 98.4031 ;
			 LAYER V2 ;
			RECT 0.0831 98.3149 0.098 98.3275 ;
		END

		ANTENNAGATEAREA 0.00027817 ;
		ANTENNADIFFAREA 0.00194719 ;
		ANTENNAPARTIALMETALAREA 0.00195671 ;
	END WEN[70]

	PIN WEN[71]
		USE SIGNAL ;
		DIRECTION INPUT ;
		SHAPE ABUTMENT ;
		PORT
			 LAYER M2 ;
			RECT 0.0714 99.5827 0.1097 99.6204 ;
			 LAYER M3 ;
			RECT 0.0714 99.5827 0.1097 99.6831 ;
			 LAYER V2 ;
			RECT 0.0831 99.5949 0.098 99.6075 ;
		END

		ANTENNAGATEAREA 0.00027817 ;
		ANTENNADIFFAREA 0.00194719 ;
		ANTENNAPARTIALMETALAREA 0.00195671 ;
	END WEN[71]

	PIN WEN[72]
		USE SIGNAL ;
		DIRECTION INPUT ;
		SHAPE ABUTMENT ;
		PORT
			 LAYER M2 ;
			RECT 0.0714 108.5616 0.1097 108.5992 ;
			 LAYER M3 ;
			RECT 0.0714 108.5616 0.1097 108.662 ;
			 LAYER V2 ;
			RECT 0.0831 108.5737 0.098 108.5863 ;
		END

		ANTENNAGATEAREA 0.00027817 ;
		ANTENNADIFFAREA 0.00194719 ;
		ANTENNAPARTIALMETALAREA 0.00195671 ;
	END WEN[72]

	PIN WEN[73]
		USE SIGNAL ;
		DIRECTION INPUT ;
		SHAPE ABUTMENT ;
		PORT
			 LAYER M2 ;
			RECT 0.0714 109.8416 0.1097 109.8792 ;
			 LAYER M3 ;
			RECT 0.0714 109.8416 0.1097 109.942 ;
			 LAYER V2 ;
			RECT 0.0831 109.8537 0.098 109.8663 ;
		END

		ANTENNAGATEAREA 0.00027817 ;
		ANTENNADIFFAREA 0.00194719 ;
		ANTENNAPARTIALMETALAREA 0.00195671 ;
	END WEN[73]

	PIN WEN[74]
		USE SIGNAL ;
		DIRECTION INPUT ;
		SHAPE ABUTMENT ;
		PORT
			 LAYER M2 ;
			RECT 0.0714 111.1216 0.1097 111.1592 ;
			 LAYER M3 ;
			RECT 0.0714 111.1216 0.1097 111.222 ;
			 LAYER V2 ;
			RECT 0.0831 111.1337 0.098 111.1463 ;
		END

		ANTENNAGATEAREA 0.00027817 ;
		ANTENNADIFFAREA 0.00194719 ;
		ANTENNAPARTIALMETALAREA 0.00195671 ;
	END WEN[74]

	PIN WEN[75]
		USE SIGNAL ;
		DIRECTION INPUT ;
		SHAPE ABUTMENT ;
		PORT
			 LAYER M2 ;
			RECT 0.0714 112.4016 0.1097 112.4392 ;
			 LAYER M3 ;
			RECT 0.0714 112.4016 0.1097 112.502 ;
			 LAYER V2 ;
			RECT 0.0831 112.4137 0.098 112.4263 ;
		END

		ANTENNAGATEAREA 0.00027817 ;
		ANTENNADIFFAREA 0.00194719 ;
		ANTENNAPARTIALMETALAREA 0.00195671 ;
	END WEN[75]

	PIN WEN[76]
		USE SIGNAL ;
		DIRECTION INPUT ;
		SHAPE ABUTMENT ;
		PORT
			 LAYER M2 ;
			RECT 0.0714 113.6816 0.1097 113.7192 ;
			 LAYER M3 ;
			RECT 0.0714 113.6816 0.1097 113.782 ;
			 LAYER V2 ;
			RECT 0.0831 113.6937 0.098 113.7063 ;
		END

		ANTENNAGATEAREA 0.00027817 ;
		ANTENNADIFFAREA 0.00194719 ;
		ANTENNAPARTIALMETALAREA 0.00195671 ;
	END WEN[76]

	PIN WEN[77]
		USE SIGNAL ;
		DIRECTION INPUT ;
		SHAPE ABUTMENT ;
		PORT
			 LAYER M2 ;
			RECT 0.0714 114.9616 0.1097 114.9992 ;
			 LAYER M3 ;
			RECT 0.0714 114.9616 0.1097 115.062 ;
			 LAYER V2 ;
			RECT 0.0831 114.9737 0.098 114.9863 ;
		END

		ANTENNAGATEAREA 0.00027817 ;
		ANTENNADIFFAREA 0.00194719 ;
		ANTENNAPARTIALMETALAREA 0.00195671 ;
	END WEN[77]

	PIN WEN[78]
		USE SIGNAL ;
		DIRECTION INPUT ;
		SHAPE ABUTMENT ;
		PORT
			 LAYER M2 ;
			RECT 0.0714 116.2416 0.1097 116.2792 ;
			 LAYER M3 ;
			RECT 0.0714 116.2416 0.1097 116.342 ;
			 LAYER V2 ;
			RECT 0.0831 116.2537 0.098 116.2663 ;
		END

		ANTENNAGATEAREA 0.00027817 ;
		ANTENNADIFFAREA 0.00194719 ;
		ANTENNAPARTIALMETALAREA 0.00195671 ;
	END WEN[78]

	PIN WEN[79]
		USE SIGNAL ;
		DIRECTION INPUT ;
		SHAPE ABUTMENT ;
		PORT
			 LAYER M2 ;
			RECT 0.0714 117.5216 0.1097 117.5592 ;
			 LAYER M3 ;
			RECT 0.0714 117.5216 0.1097 117.622 ;
			 LAYER V2 ;
			RECT 0.0831 117.5337 0.098 117.5463 ;
		END

		ANTENNAGATEAREA 0.00027817 ;
		ANTENNADIFFAREA 0.00194719 ;
		ANTENNAPARTIALMETALAREA 0.00195671 ;
	END WEN[79]

	PIN WEN[7]
		USE SIGNAL ;
		DIRECTION INPUT ;
		SHAPE ABUTMENT ;
		PORT
			 LAYER M2 ;
			RECT 0.0714 9.989 0.1097 10.0267 ;
			 LAYER M3 ;
			RECT 0.0714 9.9263 0.1097 10.0267 ;
			 LAYER V2 ;
			RECT 0.0831 10.002 0.098 10.0145 ;
		END

		ANTENNAGATEAREA 0.00027817 ;
		ANTENNADIFFAREA 0.00194719 ;
		ANTENNAPARTIALMETALAREA 0.00195671 ;
	END WEN[7]

	PIN WEN[80]
		USE SIGNAL ;
		DIRECTION INPUT ;
		SHAPE ABUTMENT ;
		PORT
			 LAYER M2 ;
			RECT 0.0714 118.8016 0.1097 118.8392 ;
			 LAYER M3 ;
			RECT 0.0714 118.8016 0.1097 118.902 ;
			 LAYER V2 ;
			RECT 0.0831 118.8137 0.098 118.8263 ;
		END

		ANTENNAGATEAREA 0.00027817 ;
		ANTENNADIFFAREA 0.00194719 ;
		ANTENNAPARTIALMETALAREA 0.00195671 ;
	END WEN[80]

	PIN WEN[81]
		USE SIGNAL ;
		DIRECTION INPUT ;
		SHAPE ABUTMENT ;
		PORT
			 LAYER M2 ;
			RECT 0.0714 120.0816 0.1097 120.1192 ;
			 LAYER M3 ;
			RECT 0.0714 120.0816 0.1097 120.182 ;
			 LAYER V2 ;
			RECT 0.0831 120.0937 0.098 120.1063 ;
		END

		ANTENNAGATEAREA 0.00027817 ;
		ANTENNADIFFAREA 0.00194719 ;
		ANTENNAPARTIALMETALAREA 0.00195671 ;
	END WEN[81]

	PIN WEN[82]
		USE SIGNAL ;
		DIRECTION INPUT ;
		SHAPE ABUTMENT ;
		PORT
			 LAYER M2 ;
			RECT 0.0714 121.3616 0.1097 121.3992 ;
			 LAYER M3 ;
			RECT 0.0714 121.3616 0.1097 121.462 ;
			 LAYER V2 ;
			RECT 0.0831 121.3737 0.098 121.3863 ;
		END

		ANTENNAGATEAREA 0.00027817 ;
		ANTENNADIFFAREA 0.00194719 ;
		ANTENNAPARTIALMETALAREA 0.00195671 ;
	END WEN[82]

	PIN WEN[83]
		USE SIGNAL ;
		DIRECTION INPUT ;
		SHAPE ABUTMENT ;
		PORT
			 LAYER M2 ;
			RECT 0.0714 122.6416 0.1097 122.6792 ;
			 LAYER M3 ;
			RECT 0.0714 122.6416 0.1097 122.742 ;
			 LAYER V2 ;
			RECT 0.0831 122.6537 0.098 122.6663 ;
		END

		ANTENNAGATEAREA 0.00027817 ;
		ANTENNADIFFAREA 0.00194719 ;
		ANTENNAPARTIALMETALAREA 0.00195671 ;
	END WEN[83]

	PIN WEN[84]
		USE SIGNAL ;
		DIRECTION INPUT ;
		SHAPE ABUTMENT ;
		PORT
			 LAYER M2 ;
			RECT 0.0714 123.9216 0.1097 123.9592 ;
			 LAYER M3 ;
			RECT 0.0714 123.9216 0.1097 124.022 ;
			 LAYER V2 ;
			RECT 0.0831 123.9337 0.098 123.9463 ;
		END

		ANTENNAGATEAREA 0.00027817 ;
		ANTENNADIFFAREA 0.00194719 ;
		ANTENNAPARTIALMETALAREA 0.00195671 ;
	END WEN[84]

	PIN WEN[85]
		USE SIGNAL ;
		DIRECTION INPUT ;
		SHAPE ABUTMENT ;
		PORT
			 LAYER M2 ;
			RECT 0.0714 125.2016 0.1097 125.2392 ;
			 LAYER M3 ;
			RECT 0.0714 125.2016 0.1097 125.302 ;
			 LAYER V2 ;
			RECT 0.0831 125.2137 0.098 125.2263 ;
		END

		ANTENNAGATEAREA 0.00027817 ;
		ANTENNADIFFAREA 0.00194719 ;
		ANTENNAPARTIALMETALAREA 0.00195671 ;
	END WEN[85]

	PIN WEN[86]
		USE SIGNAL ;
		DIRECTION INPUT ;
		SHAPE ABUTMENT ;
		PORT
			 LAYER M2 ;
			RECT 0.0714 126.4816 0.1097 126.5192 ;
			 LAYER M3 ;
			RECT 0.0714 126.4816 0.1097 126.582 ;
			 LAYER V2 ;
			RECT 0.0831 126.4937 0.098 126.5063 ;
		END

		ANTENNAGATEAREA 0.00027817 ;
		ANTENNADIFFAREA 0.00194719 ;
		ANTENNAPARTIALMETALAREA 0.00195671 ;
	END WEN[86]

	PIN WEN[87]
		USE SIGNAL ;
		DIRECTION INPUT ;
		SHAPE ABUTMENT ;
		PORT
			 LAYER M2 ;
			RECT 0.0714 127.7616 0.1097 127.7992 ;
			 LAYER M3 ;
			RECT 0.0714 127.7616 0.1097 127.862 ;
			 LAYER V2 ;
			RECT 0.0831 127.7737 0.098 127.7863 ;
		END

		ANTENNAGATEAREA 0.00027817 ;
		ANTENNADIFFAREA 0.00194719 ;
		ANTENNAPARTIALMETALAREA 0.00195671 ;
	END WEN[87]

	PIN WEN[88]
		USE SIGNAL ;
		DIRECTION INPUT ;
		SHAPE ABUTMENT ;
		PORT
			 LAYER M2 ;
			RECT 0.0714 129.0416 0.1097 129.0792 ;
			 LAYER M3 ;
			RECT 0.0714 129.0416 0.1097 129.142 ;
			 LAYER V2 ;
			RECT 0.0831 129.0537 0.098 129.0663 ;
		END

		ANTENNAGATEAREA 0.00027817 ;
		ANTENNADIFFAREA 0.00194719 ;
		ANTENNAPARTIALMETALAREA 0.00195671 ;
	END WEN[88]

	PIN WEN[89]
		USE SIGNAL ;
		DIRECTION INPUT ;
		SHAPE ABUTMENT ;
		PORT
			 LAYER M2 ;
			RECT 0.0714 130.3216 0.1097 130.3592 ;
			 LAYER M3 ;
			RECT 0.0714 130.3216 0.1097 130.422 ;
			 LAYER V2 ;
			RECT 0.0831 130.3337 0.098 130.3463 ;
		END

		ANTENNAGATEAREA 0.00027817 ;
		ANTENNADIFFAREA 0.00194719 ;
		ANTENNAPARTIALMETALAREA 0.00195671 ;
	END WEN[89]

	PIN WEN[8]
		USE SIGNAL ;
		DIRECTION INPUT ;
		SHAPE ABUTMENT ;
		PORT
			 LAYER M2 ;
			RECT 0.0714 11.269 0.1097 11.3067 ;
			 LAYER M3 ;
			RECT 0.0714 11.2063 0.1097 11.3067 ;
			 LAYER V2 ;
			RECT 0.0831 11.282 0.098 11.2945 ;
		END

		ANTENNAGATEAREA 0.00027817 ;
		ANTENNADIFFAREA 0.00194719 ;
		ANTENNAPARTIALMETALAREA 0.00195671 ;
	END WEN[8]

	PIN WEN[90]
		USE SIGNAL ;
		DIRECTION INPUT ;
		SHAPE ABUTMENT ;
		PORT
			 LAYER M2 ;
			RECT 0.0714 131.6016 0.1097 131.6392 ;
			 LAYER M3 ;
			RECT 0.0714 131.6016 0.1097 131.702 ;
			 LAYER V2 ;
			RECT 0.0831 131.6137 0.098 131.6263 ;
		END

		ANTENNAGATEAREA 0.00027817 ;
		ANTENNADIFFAREA 0.00194719 ;
		ANTENNAPARTIALMETALAREA 0.00195671 ;
	END WEN[90]

	PIN WEN[91]
		USE SIGNAL ;
		DIRECTION INPUT ;
		SHAPE ABUTMENT ;
		PORT
			 LAYER M2 ;
			RECT 0.0714 132.8816 0.1097 132.9192 ;
			 LAYER M3 ;
			RECT 0.0714 132.8816 0.1097 132.982 ;
			 LAYER V2 ;
			RECT 0.0831 132.8937 0.098 132.9063 ;
		END

		ANTENNAGATEAREA 0.00027817 ;
		ANTENNADIFFAREA 0.00194719 ;
		ANTENNAPARTIALMETALAREA 0.00195671 ;
	END WEN[91]

	PIN WEN[92]
		USE SIGNAL ;
		DIRECTION INPUT ;
		SHAPE ABUTMENT ;
		PORT
			 LAYER M2 ;
			RECT 0.0714 134.1616 0.1097 134.1992 ;
			 LAYER M3 ;
			RECT 0.0714 134.1616 0.1097 134.262 ;
			 LAYER V2 ;
			RECT 0.0831 134.1737 0.098 134.1863 ;
		END

		ANTENNAGATEAREA 0.00027817 ;
		ANTENNADIFFAREA 0.00194719 ;
		ANTENNAPARTIALMETALAREA 0.00195671 ;
	END WEN[92]

	PIN WEN[93]
		USE SIGNAL ;
		DIRECTION INPUT ;
		SHAPE ABUTMENT ;
		PORT
			 LAYER M2 ;
			RECT 0.0714 135.4416 0.1097 135.4792 ;
			 LAYER M3 ;
			RECT 0.0714 135.4416 0.1097 135.542 ;
			 LAYER V2 ;
			RECT 0.0831 135.4537 0.098 135.4663 ;
		END

		ANTENNAGATEAREA 0.00027817 ;
		ANTENNADIFFAREA 0.00194719 ;
		ANTENNAPARTIALMETALAREA 0.00195671 ;
	END WEN[93]

	PIN WEN[94]
		USE SIGNAL ;
		DIRECTION INPUT ;
		SHAPE ABUTMENT ;
		PORT
			 LAYER M2 ;
			RECT 0.0714 136.7216 0.1097 136.7592 ;
			 LAYER M3 ;
			RECT 0.0714 136.7216 0.1097 136.822 ;
			 LAYER V2 ;
			RECT 0.0831 136.7337 0.098 136.7463 ;
		END

		ANTENNAGATEAREA 0.00027817 ;
		ANTENNADIFFAREA 0.00194719 ;
		ANTENNAPARTIALMETALAREA 0.00195671 ;
	END WEN[94]

	PIN WEN[95]
		USE SIGNAL ;
		DIRECTION INPUT ;
		SHAPE ABUTMENT ;
		PORT
			 LAYER M2 ;
			RECT 0.0714 138.0016 0.1097 138.0392 ;
			 LAYER M3 ;
			RECT 0.0714 138.0016 0.1097 138.102 ;
			 LAYER V2 ;
			RECT 0.0831 138.0137 0.098 138.0263 ;
		END

		ANTENNAGATEAREA 0.00027817 ;
		ANTENNADIFFAREA 0.00194719 ;
		ANTENNAPARTIALMETALAREA 0.00195671 ;
	END WEN[95]

	PIN WEN[9]
		USE SIGNAL ;
		DIRECTION INPUT ;
		SHAPE ABUTMENT ;
		PORT
			 LAYER M2 ;
			RECT 0.0714 12.549 0.1097 12.5867 ;
			 LAYER M3 ;
			RECT 0.0714 12.4863 0.1097 12.5867 ;
			 LAYER V2 ;
			RECT 0.0831 12.562 0.098 12.5745 ;
		END

		ANTENNAGATEAREA 0.00027817 ;
		ANTENNADIFFAREA 0.00194719 ;
		ANTENNAPARTIALMETALAREA 0.00195671 ;
	END WEN[9]

	OBS
		 LAYER M1 SPACING 0.012 ;
		RECT 0 0 23.961 139.0682 ;
		 LAYER M2 SPACING 0.012 ;
		RECT 0.133 0 23.961 139.0682 ;
		RECT 0 0 0.133 0.0439 ;
		RECT 0 0.182 0.133 0.9475 ;
		RECT 0.0714 1.0918 0.133 1.2235 ;
		RECT 0 1.211 0.133 1.2235 ;
		RECT 0.0714 1.2235 0.133 1.349 ;
		RECT 0 1.4871 0.133 2.2275 ;
		RECT 0.0714 2.3718 0.133 2.5035 ;
		RECT 0 2.491 0.133 2.5035 ;
		RECT 0.0714 2.5035 0.133 2.629 ;
		RECT 0 2.7671 0.133 3.5075 ;
		RECT 0.0714 3.6518 0.133 3.7835 ;
		RECT 0 3.771 0.133 3.7835 ;
		RECT 0.0714 3.7835 0.133 3.909 ;
		RECT 0 4.0471 0.133 4.7875 ;
		RECT 0.0714 4.9318 0.133 5.0635 ;
		RECT 0 5.051 0.133 5.0635 ;
		RECT 0.0714 5.0635 0.133 5.189 ;
		RECT 0 5.3271 0.133 6.0675 ;
		RECT 0.0714 6.2118 0.133 6.3435 ;
		RECT 0 6.331 0.133 6.3435 ;
		RECT 0.0714 6.3435 0.133 6.469 ;
		RECT 0 6.6071 0.133 7.3475 ;
		RECT 0.0714 7.4918 0.133 7.6235 ;
		RECT 0 7.611 0.133 7.6235 ;
		RECT 0.0714 7.6235 0.133 7.749 ;
		RECT 0 7.8871 0.133 8.6275 ;
		RECT 0.0714 8.7718 0.133 8.9035 ;
		RECT 0 8.891 0.133 8.9035 ;
		RECT 0.0714 8.9035 0.133 9.029 ;
		RECT 0 9.1671 0.133 9.9075 ;
		RECT 0.0714 10.0518 0.133 10.1835 ;
		RECT 0 10.171 0.133 10.1835 ;
		RECT 0.0714 10.1835 0.133 10.309 ;
		RECT 0 10.4471 0.133 11.1875 ;
		RECT 0.0714 11.3318 0.133 11.4635 ;
		RECT 0 11.451 0.133 11.4635 ;
		RECT 0.0714 11.4635 0.133 11.589 ;
		RECT 0 11.7271 0.133 12.4675 ;
		RECT 0.0714 12.6118 0.133 12.7435 ;
		RECT 0 12.731 0.133 12.7435 ;
		RECT 0.0714 12.7435 0.133 12.869 ;
		RECT 0 13.0071 0.133 13.7475 ;
		RECT 0.0714 13.8918 0.133 14.0235 ;
		RECT 0 14.011 0.133 14.0235 ;
		RECT 0.0714 14.0235 0.133 14.149 ;
		RECT 0 14.2871 0.133 15.0275 ;
		RECT 0.0714 15.1718 0.133 15.3035 ;
		RECT 0 15.291 0.133 15.3035 ;
		RECT 0.0714 15.3035 0.133 15.429 ;
		RECT 0 15.5671 0.133 16.3075 ;
		RECT 0.0714 16.4518 0.133 16.5835 ;
		RECT 0 16.571 0.133 16.5835 ;
		RECT 0.0714 16.5835 0.133 16.709 ;
		RECT 0 16.8471 0.133 17.5875 ;
		RECT 0.0714 17.7318 0.133 17.8635 ;
		RECT 0 17.851 0.133 17.8635 ;
		RECT 0.0714 17.8635 0.133 17.989 ;
		RECT 0 18.1271 0.133 18.8675 ;
		RECT 0.0714 19.0118 0.133 19.1435 ;
		RECT 0 19.131 0.133 19.1435 ;
		RECT 0.0714 19.1435 0.133 19.269 ;
		RECT 0 19.4071 0.133 20.1475 ;
		RECT 0.0714 20.2918 0.133 20.4235 ;
		RECT 0 20.411 0.133 20.4235 ;
		RECT 0.0714 20.4235 0.133 20.549 ;
		RECT 0 20.6871 0.133 21.4275 ;
		RECT 0.0714 21.5718 0.133 21.7035 ;
		RECT 0 21.691 0.133 21.7035 ;
		RECT 0.0714 21.7035 0.133 21.829 ;
		RECT 0 21.9671 0.133 22.7075 ;
		RECT 0.0714 22.8518 0.133 22.9835 ;
		RECT 0 22.971 0.133 22.9835 ;
		RECT 0.0714 22.9835 0.133 23.109 ;
		RECT 0 23.2471 0.133 23.9875 ;
		RECT 0.0714 24.1318 0.133 24.2635 ;
		RECT 0 24.251 0.133 24.2635 ;
		RECT 0.0714 24.2635 0.133 24.389 ;
		RECT 0 24.5271 0.133 25.2675 ;
		RECT 0.0714 25.4118 0.133 25.5435 ;
		RECT 0 25.531 0.133 25.5435 ;
		RECT 0.0714 25.5435 0.133 25.669 ;
		RECT 0 25.8071 0.133 26.5475 ;
		RECT 0.0714 26.6918 0.133 26.8235 ;
		RECT 0 26.811 0.133 26.8235 ;
		RECT 0.0714 26.8235 0.133 26.949 ;
		RECT 0 27.0871 0.133 27.8275 ;
		RECT 0.0714 27.9718 0.133 28.1035 ;
		RECT 0 28.091 0.133 28.1035 ;
		RECT 0.0714 28.1035 0.133 28.229 ;
		RECT 0 28.3671 0.133 29.1075 ;
		RECT 0.0714 29.2518 0.133 29.3835 ;
		RECT 0 29.371 0.133 29.3835 ;
		RECT 0.0714 29.3835 0.133 29.509 ;
		RECT 0 29.6471 0.133 30.3875 ;
		RECT 0.0714 30.5318 0.133 30.6635 ;
		RECT 0 30.651 0.133 30.6635 ;
		RECT 0.0714 30.6635 0.133 30.789 ;
		RECT 0 30.9271 0.133 39.3663 ;
		RECT 0.0714 39.5106 0.133 39.6424 ;
		RECT 0 39.6298 0.133 39.6424 ;
		RECT 0.0714 39.6424 0.133 39.7678 ;
		RECT 0 39.9059 0.133 40.6463 ;
		RECT 0.0714 40.7906 0.133 40.9224 ;
		RECT 0 40.9098 0.133 40.9224 ;
		RECT 0.0714 40.9224 0.133 41.0478 ;
		RECT 0 41.1859 0.133 41.9263 ;
		RECT 0.0714 42.0706 0.133 42.2024 ;
		RECT 0 42.1898 0.133 42.2024 ;
		RECT 0.0714 42.2024 0.133 42.3278 ;
		RECT 0 42.4659 0.133 43.2063 ;
		RECT 0.0714 43.3506 0.133 43.4824 ;
		RECT 0 43.4698 0.133 43.4824 ;
		RECT 0.0714 43.4824 0.133 43.6078 ;
		RECT 0 43.7459 0.133 44.4863 ;
		RECT 0.0714 44.6306 0.133 44.7624 ;
		RECT 0 44.7498 0.133 44.7624 ;
		RECT 0.0714 44.7624 0.133 44.8878 ;
		RECT 0 45.0259 0.133 45.7663 ;
		RECT 0.0714 45.9106 0.133 46.0424 ;
		RECT 0 46.0298 0.133 46.0424 ;
		RECT 0.0714 46.0424 0.133 46.1678 ;
		RECT 0 46.3059 0.133 47.0463 ;
		RECT 0.0714 47.1906 0.133 47.3224 ;
		RECT 0 47.3098 0.133 47.3224 ;
		RECT 0.0714 47.3224 0.133 47.4478 ;
		RECT 0 47.5859 0.133 48.3263 ;
		RECT 0.0714 48.4706 0.133 48.6024 ;
		RECT 0 48.5898 0.133 48.6024 ;
		RECT 0.0714 48.6024 0.133 48.7278 ;
		RECT 0 48.8659 0.133 49.6063 ;
		RECT 0.0714 49.7506 0.133 49.8824 ;
		RECT 0 49.8698 0.133 49.8824 ;
		RECT 0.0714 49.8824 0.133 50.0078 ;
		RECT 0 50.1459 0.133 50.8863 ;
		RECT 0.0714 51.0306 0.133 51.1624 ;
		RECT 0 51.1498 0.133 51.1624 ;
		RECT 0.0714 51.1624 0.133 51.2878 ;
		RECT 0 51.4259 0.133 52.1663 ;
		RECT 0.0714 52.3106 0.133 52.4424 ;
		RECT 0 52.4298 0.133 52.4424 ;
		RECT 0.0714 52.4424 0.133 52.5678 ;
		RECT 0 52.7059 0.133 53.4463 ;
		RECT 0.0714 53.5906 0.133 53.7224 ;
		RECT 0 53.7098 0.133 53.7224 ;
		RECT 0.0714 53.7224 0.133 53.8478 ;
		RECT 0 53.9859 0.133 54.7263 ;
		RECT 0.0714 54.8706 0.133 55.0024 ;
		RECT 0 54.9898 0.133 55.0024 ;
		RECT 0.0714 55.0024 0.133 55.1278 ;
		RECT 0 55.2659 0.133 56.0063 ;
		RECT 0.0714 56.1506 0.133 56.2824 ;
		RECT 0 56.2698 0.133 56.2824 ;
		RECT 0.0714 56.2824 0.133 56.4078 ;
		RECT 0 56.5459 0.133 56.6337 ;
		RECT 0 56.7718 0.133 57.2361 ;
		RECT 0 57.3741 0.133 57.3867 ;
		RECT 0 57.5247 0.133 57.6878 ;
		RECT 0 57.8259 0.133 58.0643 ;
		RECT 0.0714 58.0643 0.133 58.5161 ;
		RECT 0 58.2024 0.133 58.5161 ;
		RECT 0 58.6541 0.133 58.6667 ;
		RECT 0 58.8047 0.133 58.8925 ;
		RECT 0 59.0306 0.133 59.0431 ;
		RECT 0 59.1812 0.133 59.1937 ;
		RECT 0 59.3318 0.133 59.3443 ;
		RECT 0 59.4824 0.133 59.6455 ;
		RECT 0 59.7835 0.133 59.8714 ;
		RECT 0 60.0094 0.133 60.022 ;
		RECT 0 60.16 0.133 60.1725 ;
		RECT 0 60.3106 0.133 60.3231 ;
		RECT 0 60.4612 0.133 60.4737 ;
		RECT 0.0714 60.4737 0.133 60.8502 ;
		RECT 0 60.6118 0.133 60.8502 ;
		RECT 0.0714 60.8502 0.133 61.0761 ;
		RECT 0 60.9882 0.133 61.0761 ;
		RECT 0 61.2141 0.133 61.2267 ;
		RECT 0 61.3647 0.133 61.4525 ;
		RECT 0 61.5906 0.133 61.6784 ;
		RECT 0 61.8165 0.133 61.829 ;
		RECT 0.0714 61.829 0.133 62.3561 ;
		RECT 0 61.9671 0.133 62.3561 ;
		RECT 0 62.4941 0.133 62.5067 ;
		RECT 0 62.6447 0.133 62.6573 ;
		RECT 0 62.7953 0.133 62.8078 ;
		RECT 0 62.9459 0.133 63.0337 ;
		RECT 0 63.1718 0.133 63.6361 ;
		RECT 0 63.7741 0.133 63.7867 ;
		RECT 0 63.9247 0.133 63.9373 ;
		RECT 0 64.0753 0.133 64.0878 ;
		RECT 0 64.2259 0.133 64.2384 ;
		RECT 0 64.3765 0.133 64.389 ;
		RECT 0 64.5271 0.133 64.9161 ;
		RECT 0 65.0541 0.133 65.0667 ;
		RECT 0 65.2047 0.133 65.2173 ;
		RECT 0 65.3553 0.133 65.3678 ;
		RECT 0 65.5059 0.133 65.5184 ;
		RECT 0 65.6565 0.133 66.1961 ;
		RECT 0 66.3341 0.133 66.3467 ;
		RECT 0 66.4847 0.133 66.5725 ;
		RECT 0 66.7106 0.133 67.4761 ;
		RECT 0 67.6141 0.133 67.6267 ;
		RECT 0 67.7647 0.133 67.9278 ;
		RECT 0 68.0659 0.133 68.1537 ;
		RECT 0 68.2918 0.133 68.3796 ;
		RECT 0 68.5176 0.133 68.6055 ;
		RECT 0.0714 68.6055 0.133 68.7561 ;
		RECT 0 68.7435 0.133 68.7561 ;
		RECT 0 68.8941 0.133 68.9067 ;
		RECT 0 69.0447 0.133 69.0573 ;
		RECT 0 69.1953 0.133 69.2078 ;
		RECT 0 69.3459 0.133 69.7224 ;
		RECT 0 69.8604 0.133 69.8729 ;
		RECT 0 70.011 0.133 70.0235 ;
		RECT 0 70.1616 0.133 70.1741 ;
		RECT 0 70.3122 0.133 70.5506 ;
		RECT 0 70.6886 0.133 70.7765 ;
		RECT 0 70.9145 0.133 71.0024 ;
		RECT 0 71.1404 0.133 71.3035 ;
		RECT 0 71.4416 0.133 71.4541 ;
		RECT 0 71.5922 0.133 71.7553 ;
		RECT 0.0714 71.7553 0.133 72.0565 ;
		RECT 0 71.8933 0.133 72.0565 ;
		RECT 0.0714 72.0565 0.133 72.2071 ;
		RECT 0 72.1945 0.133 72.2071 ;
		RECT 0 72.3451 0.133 72.3576 ;
		RECT 0 72.4957 0.133 72.5835 ;
		RECT 0 72.7216 0.133 72.7341 ;
		RECT 0 72.8722 0.133 73.1106 ;
		RECT 0.0714 73.1106 0.133 73.3365 ;
		RECT 0 73.2486 0.133 73.3365 ;
		RECT 0 73.4745 0.133 73.4871 ;
		RECT 0 73.6251 0.133 73.7129 ;
		RECT 0.0714 73.7129 0.133 73.8635 ;
		RECT 0 73.851 0.133 73.8635 ;
		RECT 0.0714 73.8635 0.133 74.0141 ;
		RECT 0 74.0016 0.133 74.0141 ;
		RECT 0 74.1522 0.133 74.5412 ;
		RECT 0 74.6792 0.133 74.6918 ;
		RECT 0 74.8298 0.133 74.8424 ;
		RECT 0 74.9804 0.133 74.9929 ;
		RECT 0 75.131 0.133 75.1435 ;
		RECT 0 75.2816 0.133 75.2941 ;
		RECT 0 75.4322 0.133 75.8965 ;
		RECT 0 76.0345 0.133 76.1224 ;
		RECT 0 76.2604 0.133 76.2729 ;
		RECT 0.0714 76.2729 0.133 76.4235 ;
		RECT 0 76.411 0.133 76.4235 ;
		RECT 0 76.5616 0.133 76.5741 ;
		RECT 0 76.7122 0.133 77.2518 ;
		RECT 0.0714 77.2518 0.133 77.4776 ;
		RECT 0 77.3898 0.133 77.4776 ;
		RECT 0 77.6157 0.133 77.7035 ;
		RECT 0 77.8416 0.133 77.8541 ;
		RECT 0 77.9922 0.133 78.7576 ;
		RECT 0 78.8957 0.133 78.9082 ;
		RECT 0.0714 78.9082 0.133 79.0588 ;
		RECT 0 79.0463 0.133 79.0588 ;
		RECT 0 79.1969 0.133 79.2847 ;
		RECT 0 79.4227 0.133 79.6612 ;
		RECT 0.0714 79.6612 0.133 79.8871 ;
		RECT 0 79.7992 0.133 79.8871 ;
		RECT 0.0714 79.8871 0.133 80.2635 ;
		RECT 0 80.0251 0.133 80.2635 ;
		RECT 0 80.4016 0.133 80.4141 ;
		RECT 0 80.5522 0.133 80.7906 ;
		RECT 0 80.9286 0.133 81.2424 ;
		RECT 0 81.3804 0.133 81.3929 ;
		RECT 0 81.531 0.133 81.5435 ;
		RECT 0 81.6816 0.133 81.6941 ;
		RECT 0 81.8322 0.133 82.2965 ;
		RECT 0 82.4345 0.133 82.5224 ;
		RECT 0.0714 82.6667 0.133 82.7984 ;
		RECT 0 82.7859 0.133 82.7984 ;
		RECT 0.0714 82.7984 0.133 82.9239 ;
		RECT 0 83.062 0.133 83.8024 ;
		RECT 0.0714 83.9467 0.133 84.0784 ;
		RECT 0 84.0659 0.133 84.0784 ;
		RECT 0.0714 84.0784 0.133 84.2039 ;
		RECT 0 84.342 0.133 85.0824 ;
		RECT 0.0714 85.2267 0.133 85.3584 ;
		RECT 0 85.3459 0.133 85.3584 ;
		RECT 0.0714 85.3584 0.133 85.4839 ;
		RECT 0 85.622 0.133 86.3624 ;
		RECT 0.0714 86.5067 0.133 86.6384 ;
		RECT 0 86.6259 0.133 86.6384 ;
		RECT 0.0714 86.6384 0.133 86.7639 ;
		RECT 0 86.902 0.133 87.6424 ;
		RECT 0.0714 87.7867 0.133 87.9184 ;
		RECT 0 87.9059 0.133 87.9184 ;
		RECT 0.0714 87.9184 0.133 88.0439 ;
		RECT 0 88.182 0.133 88.9224 ;
		RECT 0.0714 89.0667 0.133 89.1984 ;
		RECT 0 89.1859 0.133 89.1984 ;
		RECT 0.0714 89.1984 0.133 89.3239 ;
		RECT 0 89.462 0.133 90.2024 ;
		RECT 0.0714 90.3467 0.133 90.4784 ;
		RECT 0 90.4659 0.133 90.4784 ;
		RECT 0.0714 90.4784 0.133 90.6039 ;
		RECT 0 90.742 0.133 91.4824 ;
		RECT 0.0714 91.6267 0.133 91.7584 ;
		RECT 0 91.7459 0.133 91.7584 ;
		RECT 0.0714 91.7584 0.133 91.8839 ;
		RECT 0 92.022 0.133 92.7624 ;
		RECT 0.0714 92.9067 0.133 93.0384 ;
		RECT 0 93.0259 0.133 93.0384 ;
		RECT 0.0714 93.0384 0.133 93.1639 ;
		RECT 0 93.302 0.133 94.0424 ;
		RECT 0.0714 94.1867 0.133 94.3184 ;
		RECT 0 94.3059 0.133 94.3184 ;
		RECT 0.0714 94.3184 0.133 94.4439 ;
		RECT 0 94.582 0.133 95.3224 ;
		RECT 0.0714 95.4667 0.133 95.5984 ;
		RECT 0 95.5859 0.133 95.5984 ;
		RECT 0.0714 95.5984 0.133 95.7239 ;
		RECT 0 95.862 0.133 96.6024 ;
		RECT 0.0714 96.7467 0.133 96.8784 ;
		RECT 0 96.8659 0.133 96.8784 ;
		RECT 0.0714 96.8784 0.133 97.0039 ;
		RECT 0 97.142 0.133 97.8824 ;
		RECT 0.0714 98.0267 0.133 98.1584 ;
		RECT 0 98.1459 0.133 98.1584 ;
		RECT 0.0714 98.1584 0.133 98.2839 ;
		RECT 0 98.422 0.133 99.1624 ;
		RECT 0.0714 99.3067 0.133 99.4384 ;
		RECT 0 99.4259 0.133 99.4384 ;
		RECT 0.0714 99.4384 0.133 99.5639 ;
		RECT 0 99.702 0.133 108.1412 ;
		RECT 0.0714 108.2855 0.133 108.4173 ;
		RECT 0 108.4047 0.133 108.4173 ;
		RECT 0.0714 108.4173 0.133 108.5427 ;
		RECT 0 108.6808 0.133 109.4212 ;
		RECT 0.0714 109.5655 0.133 109.6973 ;
		RECT 0 109.6847 0.133 109.6973 ;
		RECT 0.0714 109.6973 0.133 109.8227 ;
		RECT 0 109.9608 0.133 110.7012 ;
		RECT 0.0714 110.8455 0.133 110.9773 ;
		RECT 0 110.9647 0.133 110.9773 ;
		RECT 0.0714 110.9773 0.133 111.1027 ;
		RECT 0 111.2408 0.133 111.9812 ;
		RECT 0.0714 112.1255 0.133 112.2573 ;
		RECT 0 112.2447 0.133 112.2573 ;
		RECT 0.0714 112.2573 0.133 112.3827 ;
		RECT 0 112.5208 0.133 113.2612 ;
		RECT 0.0714 113.4055 0.133 113.5373 ;
		RECT 0 113.5247 0.133 113.5373 ;
		RECT 0.0714 113.5373 0.133 113.6627 ;
		RECT 0 113.8008 0.133 114.5412 ;
		RECT 0.0714 114.6855 0.133 114.8173 ;
		RECT 0 114.8047 0.133 114.8173 ;
		RECT 0.0714 114.8173 0.133 114.9427 ;
		RECT 0 115.0808 0.133 115.8212 ;
		RECT 0.0714 115.9655 0.133 116.0973 ;
		RECT 0 116.0847 0.133 116.0973 ;
		RECT 0.0714 116.0973 0.133 116.2227 ;
		RECT 0 116.3608 0.133 117.1012 ;
		RECT 0.0714 117.2455 0.133 117.3773 ;
		RECT 0 117.3647 0.133 117.3773 ;
		RECT 0.0714 117.3773 0.133 117.5027 ;
		RECT 0 117.6408 0.133 118.3812 ;
		RECT 0.0714 118.5255 0.133 118.6573 ;
		RECT 0 118.6447 0.133 118.6573 ;
		RECT 0.0714 118.6573 0.133 118.7827 ;
		RECT 0 118.9208 0.133 119.6612 ;
		RECT 0.0714 119.8055 0.133 119.9373 ;
		RECT 0 119.9247 0.133 119.9373 ;
		RECT 0.0714 119.9373 0.133 120.0627 ;
		RECT 0 120.2008 0.133 120.9412 ;
		RECT 0.0714 121.0855 0.133 121.2173 ;
		RECT 0 121.2047 0.133 121.2173 ;
		RECT 0.0714 121.2173 0.133 121.3427 ;
		RECT 0 121.4808 0.133 122.2212 ;
		RECT 0.0714 122.3655 0.133 122.4973 ;
		RECT 0 122.4847 0.133 122.4973 ;
		RECT 0.0714 122.4973 0.133 122.6227 ;
		RECT 0 122.7608 0.133 123.5012 ;
		RECT 0.0714 123.6455 0.133 123.7773 ;
		RECT 0 123.7647 0.133 123.7773 ;
		RECT 0.0714 123.7773 0.133 123.9027 ;
		RECT 0 124.0408 0.133 124.7812 ;
		RECT 0.0714 124.9255 0.133 125.0573 ;
		RECT 0 125.0447 0.133 125.0573 ;
		RECT 0.0714 125.0573 0.133 125.1827 ;
		RECT 0 125.3208 0.133 126.0612 ;
		RECT 0.0714 126.2055 0.133 126.3373 ;
		RECT 0 126.3247 0.133 126.3373 ;
		RECT 0.0714 126.3373 0.133 126.4627 ;
		RECT 0 126.6008 0.133 127.3412 ;
		RECT 0.0714 127.4855 0.133 127.6173 ;
		RECT 0 127.6047 0.133 127.6173 ;
		RECT 0.0714 127.6173 0.133 127.7427 ;
		RECT 0 127.8808 0.133 128.6212 ;
		RECT 0.0714 128.7655 0.133 128.8973 ;
		RECT 0 128.8847 0.133 128.8973 ;
		RECT 0.0714 128.8973 0.133 129.0227 ;
		RECT 0 129.1608 0.133 129.9012 ;
		RECT 0.0714 130.0455 0.133 130.1773 ;
		RECT 0 130.1647 0.133 130.1773 ;
		RECT 0.0714 130.1773 0.133 130.3027 ;
		RECT 0 130.4408 0.133 131.1812 ;
		RECT 0.0714 131.3255 0.133 131.4573 ;
		RECT 0 131.4447 0.133 131.4573 ;
		RECT 0.0714 131.4573 0.133 131.5827 ;
		RECT 0 131.7208 0.133 132.4612 ;
		RECT 0.0714 132.6055 0.133 132.7373 ;
		RECT 0 132.7247 0.133 132.7373 ;
		RECT 0.0714 132.7373 0.133 132.8627 ;
		RECT 0 133.0008 0.133 133.7412 ;
		RECT 0.0714 133.8855 0.133 134.0173 ;
		RECT 0 134.0047 0.133 134.0173 ;
		RECT 0.0714 134.0173 0.133 134.1427 ;
		RECT 0 134.2808 0.133 135.0212 ;
		RECT 0.0714 135.1655 0.133 135.2973 ;
		RECT 0 135.2847 0.133 135.2973 ;
		RECT 0.0714 135.2973 0.133 135.4227 ;
		RECT 0 135.5608 0.133 136.3012 ;
		RECT 0.0714 136.4455 0.133 136.5773 ;
		RECT 0 136.5647 0.133 136.5773 ;
		RECT 0.0714 136.5773 0.133 136.7027 ;
		RECT 0 136.8408 0.133 137.5812 ;
		RECT 0.0714 137.7255 0.133 137.8573 ;
		RECT 0 137.8447 0.133 137.8573 ;
		RECT 0.0714 137.8573 0.133 137.9827 ;
		RECT 0 138.1208 0.133 138.8863 ;
		RECT 0 139.0243 0.133 139.0682 ;
		 LAYER M2 ;
		RECT 0.0098 31.2094 0.0481 31.3098 ;
		RECT 0.0098 31.6612 0.0481 31.7616 ;
		RECT 0.0098 37.509 0.0481 37.6094 ;
		RECT 0.0098 37.9106 0.0481 38.011 ;
		RECT 0.0098 60.4047 0.0481 60.4424 ;
		RECT 0.0098 63.8682 0.0481 63.9059 ;
		RECT 0.0098 64.0188 0.0481 64.0565 ;
		RECT 0.0714 64.1067 0.1097 64.1443 ;
		RECT 0.0098 65.1482 0.0481 65.1859 ;
		RECT 0.0714 65.2361 0.1097 65.2737 ;
		RECT 0.0714 65.3867 0.1097 65.4243 ;
		RECT 0.0098 65.6 0.0481 65.6376 ;
		RECT 0.0098 31.8133 0.0481 31.9137 ;
		RECT 0.0098 65.6878 0.0481 65.7882 ;
		RECT 0.0098 65.8384 0.0481 65.9388 ;
		RECT 0.0098 66.742 0.0481 66.8424 ;
		RECT 0.0098 66.8925 0.0481 66.9929 ;
		RECT 0.0098 67.1937 0.0481 67.2941 ;
		RECT 0.0098 0.1255 0.0481 0.1631 ;
		RECT 0.0098 107.7584 0.0481 107.8588 ;
		RECT 0.0098 107.3067 0.0481 107.4071 ;
		RECT 0.0098 107.1545 0.0481 107.2549 ;
		RECT 0.0098 106.9051 0.0481 107.0055 ;
		RECT 0.0098 32.0627 0.0481 32.1631 ;
		RECT 0.0098 106.3529 0.0481 106.4533 ;
		RECT 0.0098 104.7969 0.0481 104.8973 ;
		RECT 0.0098 103.7678 0.0481 103.8682 ;
		RECT 0.0098 103.4416 0.0481 103.542 ;
		RECT 0.0098 103.04 0.0481 103.1404 ;
		RECT 0.0098 101.9608 0.0481 102.0612 ;
		RECT 0.0098 101.6345 0.0481 101.7349 ;
		RECT 0.0098 101.4588 0.0481 101.5592 ;
		RECT 0.0098 101.0573 0.0481 101.1576 ;
		RECT 0.0098 82.0141 0.0481 82.1145 ;
		RECT 0.0098 32.6149 0.0481 32.7153 ;
		RECT 0.0098 81.8635 0.0481 81.9639 ;
		RECT 0.0098 81.5624 0.0481 81.6 ;
		RECT 0.0098 80.8094 0.0481 80.8471 ;
		RECT 0.0098 72.2259 0.0481 72.2635 ;
		RECT 0.0714 71.2345 0.1097 71.2722 ;
		RECT 0.0098 71.1718 0.0481 71.2094 ;
		RECT 0.0098 70.7953 0.0481 70.8329 ;
		RECT 0.0098 70.5694 0.0481 70.6071 ;
		RECT 0.0714 70.4063 0.1097 70.4439 ;
		RECT 0.0098 70.3435 0.0481 70.3812 ;
		RECT 0.0098 35.2 0.0481 35.3004 ;
		RECT 0.0098 138.9051 0.0481 138.9427 ;
		RECT 0.0098 35.5263 0.0481 35.6267 ;
		RECT 0.0098 35.9278 0.0481 36.0282 ;
		RECT 0.0098 37.0071 0.0481 37.1075 ;
		RECT 0.0098 37.3333 0.0481 37.4337 ;
		 LAYER M2 SPACING 0.012 ;
		RECT 0.0098 31.2094 0.0481 31.3098 ;
		RECT 0.0098 31.6612 0.0481 31.7616 ;
		RECT 0.0098 37.509 0.0481 37.6094 ;
		RECT 0.0098 37.9106 0.0481 38.011 ;
		RECT 0.0098 60.4047 0.0481 60.4424 ;
		RECT 0.0098 63.8682 0.0481 63.9059 ;
		RECT 0.0098 64.0188 0.0481 64.0565 ;
		RECT 0.0714 64.1067 0.1097 64.1443 ;
		RECT 0.0098 65.1482 0.0481 65.1859 ;
		RECT 0.0714 65.2361 0.1097 65.2737 ;
		RECT 0.0714 65.3867 0.1097 65.4243 ;
		RECT 0.0098 65.6 0.0481 65.6376 ;
		RECT 0.0098 31.8133 0.0481 31.9137 ;
		RECT 0.0098 65.6878 0.0481 65.7882 ;
		RECT 0.0098 65.8384 0.0481 65.9388 ;
		RECT 0.0098 66.742 0.0481 66.8424 ;
		RECT 0.0098 66.8925 0.0481 66.9929 ;
		RECT 0.0098 67.1937 0.0481 67.2941 ;
		RECT 0.0098 0.1255 0.0481 0.1631 ;
		RECT 0.0098 107.7584 0.0481 107.8588 ;
		RECT 0.0098 107.3067 0.0481 107.4071 ;
		RECT 0.0098 107.1545 0.0481 107.2549 ;
		RECT 0.0098 106.9051 0.0481 107.0055 ;
		RECT 0.0098 32.0627 0.0481 32.1631 ;
		RECT 0.0098 106.3529 0.0481 106.4533 ;
		RECT 0.0098 104.7969 0.0481 104.8973 ;
		RECT 0.0098 103.7678 0.0481 103.8682 ;
		RECT 0.0098 103.4416 0.0481 103.542 ;
		RECT 0.0098 103.04 0.0481 103.1404 ;
		RECT 0.0098 101.9608 0.0481 102.0612 ;
		RECT 0.0098 101.6345 0.0481 101.7349 ;
		RECT 0.0098 101.4588 0.0481 101.5592 ;
		RECT 0.0098 101.0573 0.0481 101.1576 ;
		RECT 0.0098 82.0141 0.0481 82.1145 ;
		RECT 0.0098 32.6149 0.0481 32.7153 ;
		RECT 0.0098 81.8635 0.0481 81.9639 ;
		RECT 0.0098 81.5624 0.0481 81.6 ;
		RECT 0.0098 80.8094 0.0481 80.8471 ;
		RECT 0.0098 72.2259 0.0481 72.2635 ;
		RECT 0.0714 71.2345 0.1097 71.2722 ;
		RECT 0.0098 71.1718 0.0481 71.2094 ;
		RECT 0.0098 70.7953 0.0481 70.8329 ;
		RECT 0.0098 70.5694 0.0481 70.6071 ;
		RECT 0.0714 70.4063 0.1097 70.4439 ;
		RECT 0.0098 70.3435 0.0481 70.3812 ;
		RECT 0.0098 35.2 0.0481 35.3004 ;
		RECT 0.0098 138.9051 0.0481 138.9427 ;
		RECT 0.0098 35.5263 0.0481 35.6267 ;
		RECT 0.0098 35.9278 0.0481 36.0282 ;
		RECT 0.0098 37.0071 0.0481 37.1075 ;
		RECT 0.0098 37.3333 0.0481 37.4337 ;
		 LAYER M3 SPACING 0.012 ;
		RECT 0.133 0 23.961 139.0682 ;
		RECT 0 0 0.133 0.0439 ;
		RECT 0 0.182 0.133 0.9475 ;
		RECT 0.0714 1.0918 0.133 1.2235 ;
		RECT 0 1.211 0.133 1.2235 ;
		RECT 0.0714 1.2235 0.133 1.349 ;
		RECT 0 1.4871 0.133 2.2275 ;
		RECT 0.0714 2.3718 0.133 2.5035 ;
		RECT 0 2.491 0.133 2.5035 ;
		RECT 0.0714 2.5035 0.133 2.629 ;
		RECT 0 2.7671 0.133 3.5075 ;
		RECT 0.0714 3.6518 0.133 3.7835 ;
		RECT 0 3.771 0.133 3.7835 ;
		RECT 0.0714 3.7835 0.133 3.909 ;
		RECT 0 4.0471 0.133 4.7875 ;
		RECT 0.0714 4.9318 0.133 5.0635 ;
		RECT 0 5.051 0.133 5.0635 ;
		RECT 0.0714 5.0635 0.133 5.189 ;
		RECT 0 5.3271 0.133 6.0675 ;
		RECT 0.0714 6.2118 0.133 6.3435 ;
		RECT 0 6.331 0.133 6.3435 ;
		RECT 0.0714 6.3435 0.133 6.469 ;
		RECT 0 6.6071 0.133 7.3475 ;
		RECT 0.0714 7.4918 0.133 7.6235 ;
		RECT 0 7.611 0.133 7.6235 ;
		RECT 0.0714 7.6235 0.133 7.749 ;
		RECT 0 7.8871 0.133 8.6275 ;
		RECT 0.0714 8.7718 0.133 8.9035 ;
		RECT 0 8.891 0.133 8.9035 ;
		RECT 0.0714 8.9035 0.133 9.029 ;
		RECT 0 9.1671 0.133 9.9075 ;
		RECT 0.0714 10.0518 0.133 10.1835 ;
		RECT 0 10.171 0.133 10.1835 ;
		RECT 0.0714 10.1835 0.133 10.309 ;
		RECT 0 10.4471 0.133 11.1875 ;
		RECT 0.0714 11.3318 0.133 11.4635 ;
		RECT 0 11.451 0.133 11.4635 ;
		RECT 0.0714 11.4635 0.133 11.589 ;
		RECT 0 11.7271 0.133 12.4675 ;
		RECT 0.0714 12.6118 0.133 12.7435 ;
		RECT 0 12.731 0.133 12.7435 ;
		RECT 0.0714 12.7435 0.133 12.869 ;
		RECT 0 13.0071 0.133 13.7475 ;
		RECT 0.0714 13.8918 0.133 14.0235 ;
		RECT 0 14.011 0.133 14.0235 ;
		RECT 0.0714 14.0235 0.133 14.149 ;
		RECT 0 14.2871 0.133 15.0275 ;
		RECT 0.0714 15.1718 0.133 15.3035 ;
		RECT 0 15.291 0.133 15.3035 ;
		RECT 0.0714 15.3035 0.133 15.429 ;
		RECT 0 15.5671 0.133 16.3075 ;
		RECT 0.0714 16.4518 0.133 16.5835 ;
		RECT 0 16.571 0.133 16.5835 ;
		RECT 0.0714 16.5835 0.133 16.709 ;
		RECT 0 16.8471 0.133 17.5875 ;
		RECT 0.0714 17.7318 0.133 17.8635 ;
		RECT 0 17.851 0.133 17.8635 ;
		RECT 0.0714 17.8635 0.133 17.989 ;
		RECT 0 18.1271 0.133 18.8675 ;
		RECT 0.0714 19.0118 0.133 19.1435 ;
		RECT 0 19.131 0.133 19.1435 ;
		RECT 0.0714 19.1435 0.133 19.269 ;
		RECT 0 19.4071 0.133 20.1475 ;
		RECT 0.0714 20.2918 0.133 20.4235 ;
		RECT 0 20.411 0.133 20.4235 ;
		RECT 0.0714 20.4235 0.133 20.549 ;
		RECT 0 20.6871 0.133 21.4275 ;
		RECT 0.0714 21.5718 0.133 21.7035 ;
		RECT 0 21.691 0.133 21.7035 ;
		RECT 0.0714 21.7035 0.133 21.829 ;
		RECT 0 21.9671 0.133 22.7075 ;
		RECT 0.0714 22.8518 0.133 22.9835 ;
		RECT 0 22.971 0.133 22.9835 ;
		RECT 0.0714 22.9835 0.133 23.109 ;
		RECT 0 23.2471 0.133 23.9875 ;
		RECT 0.0714 24.1318 0.133 24.2635 ;
		RECT 0 24.251 0.133 24.2635 ;
		RECT 0.0714 24.2635 0.133 24.389 ;
		RECT 0 24.5271 0.133 25.2675 ;
		RECT 0.0714 25.4118 0.133 25.5435 ;
		RECT 0 25.531 0.133 25.5435 ;
		RECT 0.0714 25.5435 0.133 25.669 ;
		RECT 0 25.8071 0.133 26.5475 ;
		RECT 0.0714 26.6918 0.133 26.8235 ;
		RECT 0 26.811 0.133 26.8235 ;
		RECT 0.0714 26.8235 0.133 26.949 ;
		RECT 0 27.0871 0.133 27.8275 ;
		RECT 0.0714 27.9718 0.133 28.1035 ;
		RECT 0 28.091 0.133 28.1035 ;
		RECT 0.0714 28.1035 0.133 28.229 ;
		RECT 0 28.3671 0.133 29.1075 ;
		RECT 0.0714 29.2518 0.133 29.3835 ;
		RECT 0 29.371 0.133 29.3835 ;
		RECT 0.0714 29.3835 0.133 29.509 ;
		RECT 0 29.6471 0.133 30.3875 ;
		RECT 0.0714 30.5318 0.133 30.6635 ;
		RECT 0 30.651 0.133 30.6635 ;
		RECT 0.0714 30.6635 0.133 30.789 ;
		RECT 0 30.9271 0.133 39.3663 ;
		RECT 0.0714 39.5106 0.133 39.6424 ;
		RECT 0 39.6298 0.133 39.6424 ;
		RECT 0.0714 39.6424 0.133 39.7678 ;
		RECT 0 39.9059 0.133 40.6463 ;
		RECT 0.0714 40.7906 0.133 40.9224 ;
		RECT 0 40.9098 0.133 40.9224 ;
		RECT 0.0714 40.9224 0.133 41.0478 ;
		RECT 0 41.1859 0.133 41.9263 ;
		RECT 0.0714 42.0706 0.133 42.2024 ;
		RECT 0 42.1898 0.133 42.2024 ;
		RECT 0.0714 42.2024 0.133 42.3278 ;
		RECT 0 42.4659 0.133 43.2063 ;
		RECT 0.0714 43.3506 0.133 43.4824 ;
		RECT 0 43.4698 0.133 43.4824 ;
		RECT 0.0714 43.4824 0.133 43.6078 ;
		RECT 0 43.7459 0.133 44.4863 ;
		RECT 0.0714 44.6306 0.133 44.7624 ;
		RECT 0 44.7498 0.133 44.7624 ;
		RECT 0.0714 44.7624 0.133 44.8878 ;
		RECT 0 45.0259 0.133 45.7663 ;
		RECT 0.0714 45.9106 0.133 46.0424 ;
		RECT 0 46.0298 0.133 46.0424 ;
		RECT 0.0714 46.0424 0.133 46.1678 ;
		RECT 0 46.3059 0.133 47.0463 ;
		RECT 0.0714 47.1906 0.133 47.3224 ;
		RECT 0 47.3098 0.133 47.3224 ;
		RECT 0.0714 47.3224 0.133 47.4478 ;
		RECT 0 47.5859 0.133 48.3263 ;
		RECT 0.0714 48.4706 0.133 48.6024 ;
		RECT 0 48.5898 0.133 48.6024 ;
		RECT 0.0714 48.6024 0.133 48.7278 ;
		RECT 0 48.8659 0.133 49.6063 ;
		RECT 0.0714 49.7506 0.133 49.8824 ;
		RECT 0 49.8698 0.133 49.8824 ;
		RECT 0.0714 49.8824 0.133 50.0078 ;
		RECT 0 50.1459 0.133 50.8863 ;
		RECT 0.0714 51.0306 0.133 51.1624 ;
		RECT 0 51.1498 0.133 51.1624 ;
		RECT 0.0714 51.1624 0.133 51.2878 ;
		RECT 0 51.4259 0.133 52.1663 ;
		RECT 0.0714 52.3106 0.133 52.4424 ;
		RECT 0 52.4298 0.133 52.4424 ;
		RECT 0.0714 52.4424 0.133 52.5678 ;
		RECT 0 52.7059 0.133 53.4463 ;
		RECT 0.0714 53.5906 0.133 53.7224 ;
		RECT 0 53.7098 0.133 53.7224 ;
		RECT 0.0714 53.7224 0.133 53.8478 ;
		RECT 0 53.9859 0.133 54.7263 ;
		RECT 0.0714 54.8706 0.133 55.0024 ;
		RECT 0 54.9898 0.133 55.0024 ;
		RECT 0.0714 55.0024 0.133 55.1278 ;
		RECT 0 55.2659 0.133 56.0063 ;
		RECT 0.0714 56.1506 0.133 56.2824 ;
		RECT 0 56.2698 0.133 56.2824 ;
		RECT 0.0714 56.2824 0.133 56.4078 ;
		RECT 0 56.5459 0.133 56.6337 ;
		RECT 0 56.7718 0.133 57.2361 ;
		RECT 0 57.3741 0.133 57.3867 ;
		RECT 0 57.5247 0.133 57.6878 ;
		RECT 0 57.8259 0.133 58.0643 ;
		RECT 0.0714 58.0643 0.133 58.5161 ;
		RECT 0 58.2024 0.133 58.5161 ;
		RECT 0 58.6541 0.133 58.6667 ;
		RECT 0 58.8047 0.133 58.8925 ;
		RECT 0 59.0306 0.133 59.0431 ;
		RECT 0 59.1812 0.133 59.1937 ;
		RECT 0 59.3318 0.133 59.3443 ;
		RECT 0 59.4824 0.133 59.6455 ;
		RECT 0 59.7835 0.133 59.8714 ;
		RECT 0 60.0094 0.133 60.022 ;
		RECT 0 60.16 0.133 60.1725 ;
		RECT 0 60.3106 0.133 60.3231 ;
		RECT 0 60.4612 0.133 60.4737 ;
		RECT 0.0714 60.4737 0.133 60.8502 ;
		RECT 0 60.6118 0.133 60.8502 ;
		RECT 0.0714 60.8502 0.133 61.0761 ;
		RECT 0 60.9882 0.133 61.0761 ;
		RECT 0 61.2141 0.133 61.2267 ;
		RECT 0 61.3647 0.133 61.4525 ;
		RECT 0 61.5906 0.133 61.6784 ;
		RECT 0 61.8165 0.133 61.829 ;
		RECT 0.0714 61.829 0.133 62.3561 ;
		RECT 0 61.9671 0.133 62.3561 ;
		RECT 0 62.4941 0.133 62.5067 ;
		RECT 0 62.6447 0.133 62.6573 ;
		RECT 0 62.7953 0.133 62.8078 ;
		RECT 0 62.9459 0.133 63.0337 ;
		RECT 0 63.1718 0.133 63.6361 ;
		RECT 0 63.7741 0.133 63.7867 ;
		RECT 0 63.9247 0.133 63.9373 ;
		RECT 0 64.0753 0.133 64.0878 ;
		RECT 0 64.2259 0.133 64.2384 ;
		RECT 0 64.3765 0.133 64.389 ;
		RECT 0 64.5271 0.133 64.9161 ;
		RECT 0 65.0541 0.133 65.0667 ;
		RECT 0 65.2047 0.133 65.2173 ;
		RECT 0 65.3553 0.133 65.3678 ;
		RECT 0 65.5059 0.133 65.5184 ;
		RECT 0 65.6565 0.133 66.1961 ;
		RECT 0 66.3341 0.133 66.3467 ;
		RECT 0 66.4847 0.133 66.5725 ;
		RECT 0 66.7106 0.133 67.4761 ;
		RECT 0 67.6141 0.133 67.6267 ;
		RECT 0 67.7647 0.133 67.9278 ;
		RECT 0 68.0659 0.133 68.1537 ;
		RECT 0 68.2918 0.133 68.3796 ;
		RECT 0 68.5176 0.133 68.6055 ;
		RECT 0.0714 68.6055 0.133 68.7561 ;
		RECT 0 68.7435 0.133 68.7561 ;
		RECT 0 68.8941 0.133 68.9067 ;
		RECT 0 69.0447 0.133 69.0573 ;
		RECT 0 69.1953 0.133 69.2078 ;
		RECT 0 69.3459 0.133 69.7224 ;
		RECT 0 69.8604 0.133 69.8729 ;
		RECT 0 70.011 0.133 70.0235 ;
		RECT 0 70.1616 0.133 70.1741 ;
		RECT 0 70.3122 0.133 70.5506 ;
		RECT 0 70.6886 0.133 70.7765 ;
		RECT 0 70.9145 0.133 71.0024 ;
		RECT 0 71.1404 0.133 71.3035 ;
		RECT 0 71.4416 0.133 71.4541 ;
		RECT 0 71.5922 0.133 71.7553 ;
		RECT 0.0714 71.7553 0.133 72.0565 ;
		RECT 0 71.8933 0.133 72.0565 ;
		RECT 0.0714 72.0565 0.133 72.2071 ;
		RECT 0 72.1945 0.133 72.2071 ;
		RECT 0 72.3451 0.133 72.3576 ;
		RECT 0 72.4957 0.133 72.5835 ;
		RECT 0 72.7216 0.133 72.7341 ;
		RECT 0 72.8722 0.133 73.1106 ;
		RECT 0.0714 73.1106 0.133 73.3365 ;
		RECT 0 73.2486 0.133 73.3365 ;
		RECT 0 73.4745 0.133 73.4871 ;
		RECT 0 73.6251 0.133 73.7129 ;
		RECT 0.0714 73.7129 0.133 73.8635 ;
		RECT 0 73.851 0.133 73.8635 ;
		RECT 0.0714 73.8635 0.133 74.0141 ;
		RECT 0 74.0016 0.133 74.0141 ;
		RECT 0 74.1522 0.133 74.5412 ;
		RECT 0 74.6792 0.133 74.6918 ;
		RECT 0 74.8298 0.133 74.8424 ;
		RECT 0 74.9804 0.133 74.9929 ;
		RECT 0 75.131 0.133 75.1435 ;
		RECT 0 75.2816 0.133 75.2941 ;
		RECT 0 75.4322 0.133 75.8965 ;
		RECT 0 76.0345 0.133 76.1224 ;
		RECT 0 76.2604 0.133 76.2729 ;
		RECT 0.0714 76.2729 0.133 76.4235 ;
		RECT 0 76.411 0.133 76.4235 ;
		RECT 0 76.5616 0.133 76.5741 ;
		RECT 0 76.7122 0.133 77.2518 ;
		RECT 0.0714 77.2518 0.133 77.4776 ;
		RECT 0 77.3898 0.133 77.4776 ;
		RECT 0 77.6157 0.133 77.7035 ;
		RECT 0 77.8416 0.133 77.8541 ;
		RECT 0 77.9922 0.133 78.7576 ;
		RECT 0 78.8957 0.133 78.9082 ;
		RECT 0.0714 78.9082 0.133 79.0588 ;
		RECT 0 79.0463 0.133 79.0588 ;
		RECT 0 79.1969 0.133 79.2847 ;
		RECT 0 79.4227 0.133 79.6612 ;
		RECT 0.0714 79.6612 0.133 79.8871 ;
		RECT 0 79.7992 0.133 79.8871 ;
		RECT 0.0714 79.8871 0.133 80.2635 ;
		RECT 0 80.0251 0.133 80.2635 ;
		RECT 0 80.4016 0.133 80.4141 ;
		RECT 0 80.5522 0.133 80.7906 ;
		RECT 0 80.9286 0.133 81.2424 ;
		RECT 0 81.3804 0.133 81.3929 ;
		RECT 0 81.531 0.133 81.5435 ;
		RECT 0 81.6816 0.133 81.6941 ;
		RECT 0 81.8322 0.133 82.2965 ;
		RECT 0 82.4345 0.133 82.5224 ;
		RECT 0.0714 82.6667 0.133 82.7984 ;
		RECT 0 82.7859 0.133 82.7984 ;
		RECT 0.0714 82.7984 0.133 82.9239 ;
		RECT 0 83.062 0.133 83.8024 ;
		RECT 0.0714 83.9467 0.133 84.0784 ;
		RECT 0 84.0659 0.133 84.0784 ;
		RECT 0.0714 84.0784 0.133 84.2039 ;
		RECT 0 84.342 0.133 85.0824 ;
		RECT 0.0714 85.2267 0.133 85.3584 ;
		RECT 0 85.3459 0.133 85.3584 ;
		RECT 0.0714 85.3584 0.133 85.4839 ;
		RECT 0 85.622 0.133 86.3624 ;
		RECT 0.0714 86.5067 0.133 86.6384 ;
		RECT 0 86.6259 0.133 86.6384 ;
		RECT 0.0714 86.6384 0.133 86.7639 ;
		RECT 0 86.902 0.133 87.6424 ;
		RECT 0.0714 87.7867 0.133 87.9184 ;
		RECT 0 87.9059 0.133 87.9184 ;
		RECT 0.0714 87.9184 0.133 88.0439 ;
		RECT 0 88.182 0.133 88.9224 ;
		RECT 0.0714 89.0667 0.133 89.1984 ;
		RECT 0 89.1859 0.133 89.1984 ;
		RECT 0.0714 89.1984 0.133 89.3239 ;
		RECT 0 89.462 0.133 90.2024 ;
		RECT 0.0714 90.3467 0.133 90.4784 ;
		RECT 0 90.4659 0.133 90.4784 ;
		RECT 0.0714 90.4784 0.133 90.6039 ;
		RECT 0 90.742 0.133 91.4824 ;
		RECT 0.0714 91.6267 0.133 91.7584 ;
		RECT 0 91.7459 0.133 91.7584 ;
		RECT 0.0714 91.7584 0.133 91.8839 ;
		RECT 0 92.022 0.133 92.7624 ;
		RECT 0.0714 92.9067 0.133 93.0384 ;
		RECT 0 93.0259 0.133 93.0384 ;
		RECT 0.0714 93.0384 0.133 93.1639 ;
		RECT 0 93.302 0.133 94.0424 ;
		RECT 0.0714 94.1867 0.133 94.3184 ;
		RECT 0 94.3059 0.133 94.3184 ;
		RECT 0.0714 94.3184 0.133 94.4439 ;
		RECT 0 94.582 0.133 95.3224 ;
		RECT 0.0714 95.4667 0.133 95.5984 ;
		RECT 0 95.5859 0.133 95.5984 ;
		RECT 0.0714 95.5984 0.133 95.7239 ;
		RECT 0 95.862 0.133 96.6024 ;
		RECT 0.0714 96.7467 0.133 96.8784 ;
		RECT 0 96.8659 0.133 96.8784 ;
		RECT 0.0714 96.8784 0.133 97.0039 ;
		RECT 0 97.142 0.133 97.8824 ;
		RECT 0.0714 98.0267 0.133 98.1584 ;
		RECT 0 98.1459 0.133 98.1584 ;
		RECT 0.0714 98.1584 0.133 98.2839 ;
		RECT 0 98.422 0.133 99.1624 ;
		RECT 0.0714 99.3067 0.133 99.4384 ;
		RECT 0 99.4259 0.133 99.4384 ;
		RECT 0.0714 99.4384 0.133 99.5639 ;
		RECT 0 99.702 0.133 108.1412 ;
		RECT 0.0714 108.2855 0.133 108.4173 ;
		RECT 0 108.4047 0.133 108.4173 ;
		RECT 0.0714 108.4173 0.133 108.5427 ;
		RECT 0 108.6808 0.133 109.4212 ;
		RECT 0.0714 109.5655 0.133 109.6973 ;
		RECT 0 109.6847 0.133 109.6973 ;
		RECT 0.0714 109.6973 0.133 109.8227 ;
		RECT 0 109.9608 0.133 110.7012 ;
		RECT 0.0714 110.8455 0.133 110.9773 ;
		RECT 0 110.9647 0.133 110.9773 ;
		RECT 0.0714 110.9773 0.133 111.1027 ;
		RECT 0 111.2408 0.133 111.9812 ;
		RECT 0.0714 112.1255 0.133 112.2573 ;
		RECT 0 112.2447 0.133 112.2573 ;
		RECT 0.0714 112.2573 0.133 112.3827 ;
		RECT 0 112.5208 0.133 113.2612 ;
		RECT 0.0714 113.4055 0.133 113.5373 ;
		RECT 0 113.5247 0.133 113.5373 ;
		RECT 0.0714 113.5373 0.133 113.6627 ;
		RECT 0 113.8008 0.133 114.5412 ;
		RECT 0.0714 114.6855 0.133 114.8173 ;
		RECT 0 114.8047 0.133 114.8173 ;
		RECT 0.0714 114.8173 0.133 114.9427 ;
		RECT 0 115.0808 0.133 115.8212 ;
		RECT 0.0714 115.9655 0.133 116.0973 ;
		RECT 0 116.0847 0.133 116.0973 ;
		RECT 0.0714 116.0973 0.133 116.2227 ;
		RECT 0 116.3608 0.133 117.1012 ;
		RECT 0.0714 117.2455 0.133 117.3773 ;
		RECT 0 117.3647 0.133 117.3773 ;
		RECT 0.0714 117.3773 0.133 117.5027 ;
		RECT 0 117.6408 0.133 118.3812 ;
		RECT 0.0714 118.5255 0.133 118.6573 ;
		RECT 0 118.6447 0.133 118.6573 ;
		RECT 0.0714 118.6573 0.133 118.7827 ;
		RECT 0 118.9208 0.133 119.6612 ;
		RECT 0.0714 119.8055 0.133 119.9373 ;
		RECT 0 119.9247 0.133 119.9373 ;
		RECT 0.0714 119.9373 0.133 120.0627 ;
		RECT 0 120.2008 0.133 120.9412 ;
		RECT 0.0714 121.0855 0.133 121.2173 ;
		RECT 0 121.2047 0.133 121.2173 ;
		RECT 0.0714 121.2173 0.133 121.3427 ;
		RECT 0 121.4808 0.133 122.2212 ;
		RECT 0.0714 122.3655 0.133 122.4973 ;
		RECT 0 122.4847 0.133 122.4973 ;
		RECT 0.0714 122.4973 0.133 122.6227 ;
		RECT 0 122.7608 0.133 123.5012 ;
		RECT 0.0714 123.6455 0.133 123.7773 ;
		RECT 0 123.7647 0.133 123.7773 ;
		RECT 0.0714 123.7773 0.133 123.9027 ;
		RECT 0 124.0408 0.133 124.7812 ;
		RECT 0.0714 124.9255 0.133 125.0573 ;
		RECT 0 125.0447 0.133 125.0573 ;
		RECT 0.0714 125.0573 0.133 125.1827 ;
		RECT 0 125.3208 0.133 126.0612 ;
		RECT 0.0714 126.2055 0.133 126.3373 ;
		RECT 0 126.3247 0.133 126.3373 ;
		RECT 0.0714 126.3373 0.133 126.4627 ;
		RECT 0 126.6008 0.133 127.3412 ;
		RECT 0.0714 127.4855 0.133 127.6173 ;
		RECT 0 127.6047 0.133 127.6173 ;
		RECT 0.0714 127.6173 0.133 127.7427 ;
		RECT 0 127.8808 0.133 128.6212 ;
		RECT 0.0714 128.7655 0.133 128.8973 ;
		RECT 0 128.8847 0.133 128.8973 ;
		RECT 0.0714 128.8973 0.133 129.0227 ;
		RECT 0 129.1608 0.133 129.9012 ;
		RECT 0.0714 130.0455 0.133 130.1773 ;
		RECT 0 130.1647 0.133 130.1773 ;
		RECT 0.0714 130.1773 0.133 130.3027 ;
		RECT 0 130.4408 0.133 131.1812 ;
		RECT 0.0714 131.3255 0.133 131.4573 ;
		RECT 0 131.4447 0.133 131.4573 ;
		RECT 0.0714 131.4573 0.133 131.5827 ;
		RECT 0 131.7208 0.133 132.4612 ;
		RECT 0.0714 132.6055 0.133 132.7373 ;
		RECT 0 132.7247 0.133 132.7373 ;
		RECT 0.0714 132.7373 0.133 132.8627 ;
		RECT 0 133.0008 0.133 133.7412 ;
		RECT 0.0714 133.8855 0.133 134.0173 ;
		RECT 0 134.0047 0.133 134.0173 ;
		RECT 0.0714 134.0173 0.133 134.1427 ;
		RECT 0 134.2808 0.133 135.0212 ;
		RECT 0.0714 135.1655 0.133 135.2973 ;
		RECT 0 135.2847 0.133 135.2973 ;
		RECT 0.0714 135.2973 0.133 135.4227 ;
		RECT 0 135.5608 0.133 136.3012 ;
		RECT 0.0714 136.4455 0.133 136.5773 ;
		RECT 0 136.5647 0.133 136.5773 ;
		RECT 0.0714 136.5773 0.133 136.7027 ;
		RECT 0 136.8408 0.133 137.5812 ;
		RECT 0.0714 137.7255 0.133 137.8573 ;
		RECT 0 137.8447 0.133 137.8573 ;
		RECT 0.0714 137.8573 0.133 137.9827 ;
		RECT 0 138.1208 0.133 138.8863 ;
		RECT 0 139.0243 0.133 139.0682 ;
		 LAYER M3 ;
		RECT 0.0714 70.3435 0.1097 70.4439 ;
		RECT 0.0098 138.9051 0.0481 139.0055 ;
		RECT 0.0098 31.2094 0.0481 31.3098 ;
		RECT 0.0098 31.6612 0.0481 31.7616 ;
		RECT 0.0098 31.8133 0.0481 31.9137 ;
		RECT 0.0098 32.0627 0.0481 32.1631 ;
		RECT 0.0098 32.6149 0.0481 32.7153 ;
		RECT 0.0098 35.2 0.0481 35.3004 ;
		RECT 0.0098 35.5263 0.0481 35.6267 ;
		RECT 0.0098 35.9278 0.0481 36.0282 ;
		RECT 0.0098 37.0071 0.0481 37.1075 ;
		RECT 0.0098 37.3333 0.0481 37.4337 ;
		RECT 0.0098 37.509 0.0481 37.6094 ;
		RECT 0.0098 37.9106 0.0481 38.011 ;
		RECT 0.0098 60.342 0.0481 60.4424 ;
		RECT 0.0098 63.8055 0.0481 63.9059 ;
		RECT 0.0098 63.9561 0.0481 64.0565 ;
		RECT 0.0714 64.1067 0.1097 64.2071 ;
		RECT 0.0098 65.0855 0.0481 65.1859 ;
		RECT 0.0714 65.2361 0.1097 65.3365 ;
		RECT 0.0714 65.3867 0.1097 65.4871 ;
		RECT 0.0098 65.5373 0.0481 65.6376 ;
		RECT 0.0098 65.6878 0.0481 65.7882 ;
		RECT 0.0098 65.8384 0.0481 65.9388 ;
		RECT 0.0098 66.742 0.0481 66.8424 ;
		RECT 0.0098 66.8925 0.0481 66.9929 ;
		RECT 0.0098 67.1937 0.0481 67.2941 ;
		RECT 0.0098 0.0627 0.0481 0.1631 ;
		RECT 0.0098 107.7584 0.0481 107.8588 ;
		RECT 0.0098 107.3067 0.0481 107.4071 ;
		RECT 0.0098 107.1545 0.0481 107.2549 ;
		RECT 0.0098 106.9051 0.0481 107.0055 ;
		RECT 0.0098 106.3529 0.0481 106.4533 ;
		RECT 0.0098 104.7969 0.0481 104.8973 ;
		RECT 0.0098 103.7678 0.0481 103.8682 ;
		RECT 0.0098 103.4416 0.0481 103.542 ;
		RECT 0.0098 103.04 0.0481 103.1404 ;
		RECT 0.0098 101.9608 0.0481 102.0612 ;
		RECT 0.0098 101.6345 0.0481 101.7349 ;
		RECT 0.0098 101.4588 0.0481 101.5592 ;
		RECT 0.0098 101.0573 0.0481 101.1576 ;
		RECT 0.0098 82.0141 0.0481 82.1145 ;
		RECT 0.0098 81.8635 0.0481 81.9639 ;
		RECT 0.0098 81.5624 0.0481 81.6627 ;
		RECT 0.0098 80.8094 0.0481 80.9098 ;
		RECT 0.0098 72.2259 0.0481 72.3263 ;
		RECT 0.0098 71.1718 0.0481 71.2722 ;
		RECT 0.0714 71.1718 0.1097 71.2722 ;
		RECT 0.0098 70.7953 0.0481 70.8957 ;
		RECT 0.0098 70.5694 0.0481 70.6698 ;
		RECT 0.0098 70.3435 0.0481 70.4439 ;
		 LAYER M3 SPACING 0.012 ;
		RECT 0.0714 70.3435 0.1097 70.4439 ;
		RECT 0.0098 138.9051 0.0481 139.0055 ;
		RECT 0.0098 31.2094 0.0481 31.3098 ;
		RECT 0.0098 31.6612 0.0481 31.7616 ;
		RECT 0.0098 31.8133 0.0481 31.9137 ;
		RECT 0.0098 32.0627 0.0481 32.1631 ;
		RECT 0.0098 32.6149 0.0481 32.7153 ;
		RECT 0.0098 35.2 0.0481 35.3004 ;
		RECT 0.0098 35.5263 0.0481 35.6267 ;
		RECT 0.0098 35.9278 0.0481 36.0282 ;
		RECT 0.0098 37.0071 0.0481 37.1075 ;
		RECT 0.0098 37.3333 0.0481 37.4337 ;
		RECT 0.0098 37.509 0.0481 37.6094 ;
		RECT 0.0098 37.9106 0.0481 38.011 ;
		RECT 0.0098 60.342 0.0481 60.4424 ;
		RECT 0.0098 63.8055 0.0481 63.9059 ;
		RECT 0.0098 63.9561 0.0481 64.0565 ;
		RECT 0.0714 64.1067 0.1097 64.2071 ;
		RECT 0.0098 65.0855 0.0481 65.1859 ;
		RECT 0.0714 65.2361 0.1097 65.3365 ;
		RECT 0.0714 65.3867 0.1097 65.4871 ;
		RECT 0.0098 65.5373 0.0481 65.6376 ;
		RECT 0.0098 65.6878 0.0481 65.7882 ;
		RECT 0.0098 65.8384 0.0481 65.9388 ;
		RECT 0.0098 66.742 0.0481 66.8424 ;
		RECT 0.0098 66.8925 0.0481 66.9929 ;
		RECT 0.0098 67.1937 0.0481 67.2941 ;
		RECT 0.0098 0.0627 0.0481 0.1631 ;
		RECT 0.0098 107.7584 0.0481 107.8588 ;
		RECT 0.0098 107.3067 0.0481 107.4071 ;
		RECT 0.0098 107.1545 0.0481 107.2549 ;
		RECT 0.0098 106.9051 0.0481 107.0055 ;
		RECT 0.0098 106.3529 0.0481 106.4533 ;
		RECT 0.0098 104.7969 0.0481 104.8973 ;
		RECT 0.0098 103.7678 0.0481 103.8682 ;
		RECT 0.0098 103.4416 0.0481 103.542 ;
		RECT 0.0098 103.04 0.0481 103.1404 ;
		RECT 0.0098 101.9608 0.0481 102.0612 ;
		RECT 0.0098 101.6345 0.0481 101.7349 ;
		RECT 0.0098 101.4588 0.0481 101.5592 ;
		RECT 0.0098 101.0573 0.0481 101.1576 ;
		RECT 0.0098 82.0141 0.0481 82.1145 ;
		RECT 0.0098 81.8635 0.0481 81.9639 ;
		RECT 0.0098 81.5624 0.0481 81.6627 ;
		RECT 0.0098 80.8094 0.0481 80.9098 ;
		RECT 0.0098 72.2259 0.0481 72.3263 ;
		RECT 0.0098 71.1718 0.0481 71.2722 ;
		RECT 0.0714 71.1718 0.1097 71.2722 ;
		RECT 0.0098 70.7953 0.0481 70.8957 ;
		RECT 0.0098 70.5694 0.0481 70.6698 ;
		RECT 0.0098 70.3435 0.0481 70.4439 ;
		 LAYER M4 SPACING 0.018 ;
		RECT 0.2105 0.3286 23.814 0.5302 ;
		RECT 23.814 0.3286 23.961 0.5302 ;
		RECT 0.2105 0.64 23.814 0.7631 ;
		RECT 23.814 0.64 23.961 0.7631 ;
		RECT 0.2105 0.9686 23.814 1.1702 ;
		RECT 23.814 0.9686 23.961 1.1702 ;
		RECT 0.2105 1.28 23.814 1.4031 ;
		RECT 23.814 1.28 23.961 1.4031 ;
		RECT 0.2105 1.6086 23.814 1.8102 ;
		RECT 23.814 1.6086 23.961 1.8102 ;
		RECT 0.2105 1.92 23.814 2.0431 ;
		RECT 23.814 1.92 23.961 2.0431 ;
		RECT 0.2105 2.2486 23.814 2.4502 ;
		RECT 23.814 2.2486 23.961 2.4502 ;
		RECT 0.2105 2.56 23.814 2.6831 ;
		RECT 23.814 2.56 23.961 2.6831 ;
		RECT 0.2105 2.8886 23.814 3.0902 ;
		RECT 23.814 2.8886 23.961 3.0902 ;
		RECT 0.2105 3.2 23.814 3.3231 ;
		RECT 23.814 3.2 23.961 3.3231 ;
		RECT 0.2105 3.5286 23.814 3.7302 ;
		RECT 23.814 3.5286 23.961 3.7302 ;
		RECT 0.2105 3.84 23.814 3.9631 ;
		RECT 23.814 3.84 23.961 3.9631 ;
		RECT 0.2105 4.1686 23.814 4.3702 ;
		RECT 23.814 4.1686 23.961 4.3702 ;
		RECT 0.2105 4.48 23.814 4.6031 ;
		RECT 23.814 4.48 23.961 4.6031 ;
		RECT 0.2105 4.8086 23.814 5.0102 ;
		RECT 23.814 4.8086 23.961 5.0102 ;
		RECT 0.2105 5.12 23.814 5.2431 ;
		RECT 23.814 5.12 23.961 5.2431 ;
		RECT 0.2105 5.4486 23.814 5.6502 ;
		RECT 23.814 5.4486 23.961 5.6502 ;
		RECT 0.2105 5.76 23.814 5.8831 ;
		RECT 23.814 5.76 23.961 5.8831 ;
		RECT 0.2105 6.0886 23.814 6.2902 ;
		RECT 23.814 6.0886 23.961 6.2902 ;
		RECT 0.2105 6.4 23.814 6.5231 ;
		RECT 23.814 6.4 23.961 6.5231 ;
		RECT 0.2105 6.7286 23.814 6.9302 ;
		RECT 23.814 6.7286 23.961 6.9302 ;
		RECT 0.2105 7.04 23.814 7.1631 ;
		RECT 23.814 7.04 23.961 7.1631 ;
		RECT 0.2105 7.3686 23.814 7.5702 ;
		RECT 23.814 7.3686 23.961 7.5702 ;
		RECT 0.2105 7.68 23.814 7.8031 ;
		RECT 23.814 7.68 23.961 7.8031 ;
		RECT 0.2105 8.0086 23.814 8.2102 ;
		RECT 23.814 8.0086 23.961 8.2102 ;
		RECT 0.2105 8.32 23.814 8.4431 ;
		RECT 23.814 8.32 23.961 8.4431 ;
		RECT 0.2105 8.6486 23.814 8.8502 ;
		RECT 23.814 8.6486 23.961 8.8502 ;
		RECT 0.2105 8.96 23.814 9.0831 ;
		RECT 23.814 8.96 23.961 9.0831 ;
		RECT 0.2105 9.2886 23.814 9.4902 ;
		RECT 23.814 9.2886 23.961 9.4902 ;
		RECT 0.2105 9.6 23.814 9.7231 ;
		RECT 23.814 9.6 23.961 9.7231 ;
		RECT 0.2105 9.9286 23.814 10.1302 ;
		RECT 23.814 9.9286 23.961 10.1302 ;
		RECT 0.2105 10.24 23.814 10.3631 ;
		RECT 23.814 10.24 23.961 10.3631 ;
		RECT 0.2105 10.5686 23.814 10.7702 ;
		RECT 23.814 10.5686 23.961 10.7702 ;
		RECT 0.2105 10.88 23.814 11.0031 ;
		RECT 23.814 10.88 23.961 11.0031 ;
		RECT 0.2105 11.2086 23.814 11.4102 ;
		RECT 23.814 11.2086 23.961 11.4102 ;
		RECT 0.2105 11.52 23.814 11.6431 ;
		RECT 23.814 11.52 23.961 11.6431 ;
		RECT 0.2105 11.8486 23.814 12.0502 ;
		RECT 23.814 11.8486 23.961 12.0502 ;
		RECT 0.2105 12.16 23.814 12.2831 ;
		RECT 23.814 12.16 23.961 12.2831 ;
		RECT 0.2105 12.4886 23.814 12.6902 ;
		RECT 23.814 12.4886 23.961 12.6902 ;
		RECT 0.2105 12.8 23.814 12.9231 ;
		RECT 23.814 12.8 23.961 12.9231 ;
		RECT 0.2105 13.1286 23.814 13.3302 ;
		RECT 23.814 13.1286 23.961 13.3302 ;
		RECT 0.2105 13.44 23.814 13.5631 ;
		RECT 23.814 13.44 23.961 13.5631 ;
		RECT 0.2105 13.7686 23.814 13.9702 ;
		RECT 23.814 13.7686 23.961 13.9702 ;
		RECT 0.2105 14.08 23.814 14.2031 ;
		RECT 23.814 14.08 23.961 14.2031 ;
		RECT 0.2105 14.4086 23.814 14.6102 ;
		RECT 23.814 14.4086 23.961 14.6102 ;
		RECT 0.2105 14.72 23.814 14.8431 ;
		RECT 23.814 14.72 23.961 14.8431 ;
		RECT 0.2105 15.0486 23.814 15.2502 ;
		RECT 23.814 15.0486 23.961 15.2502 ;
		RECT 0.2105 15.36 23.814 15.4831 ;
		RECT 23.814 15.36 23.961 15.4831 ;
		RECT 0.2105 15.6886 23.814 15.8902 ;
		RECT 23.814 15.6886 23.961 15.8902 ;
		RECT 0.2105 16 23.814 16.1231 ;
		RECT 23.814 16 23.961 16.1231 ;
		RECT 0.2105 16.3286 23.814 16.5302 ;
		RECT 23.814 16.3286 23.961 16.5302 ;
		RECT 0.2105 16.64 23.814 16.7631 ;
		RECT 23.814 16.64 23.961 16.7631 ;
		RECT 0.2105 16.9686 23.814 17.1702 ;
		RECT 23.814 16.9686 23.961 17.1702 ;
		RECT 0.2105 17.28 23.814 17.4031 ;
		RECT 23.814 17.28 23.961 17.4031 ;
		RECT 0.2105 17.6086 23.814 17.8102 ;
		RECT 23.814 17.6086 23.961 17.8102 ;
		RECT 0.2105 17.92 23.814 18.0431 ;
		RECT 23.814 17.92 23.961 18.0431 ;
		RECT 0.2105 18.2486 23.814 18.4502 ;
		RECT 23.814 18.2486 23.961 18.4502 ;
		RECT 0.2105 18.56 23.814 18.6831 ;
		RECT 23.814 18.56 23.961 18.6831 ;
		RECT 0.2105 18.8886 23.814 19.0902 ;
		RECT 23.814 18.8886 23.961 19.0902 ;
		RECT 0.2105 19.2 23.814 19.3231 ;
		RECT 23.814 19.2 23.961 19.3231 ;
		RECT 0.2105 19.5286 23.814 19.7302 ;
		RECT 23.814 19.5286 23.961 19.7302 ;
		RECT 0.2105 19.84 23.814 19.9631 ;
		RECT 23.814 19.84 23.961 19.9631 ;
		RECT 0.2105 20.1686 23.814 20.3702 ;
		RECT 23.814 20.1686 23.961 20.3702 ;
		RECT 0.2105 20.48 23.814 20.6031 ;
		RECT 23.814 20.48 23.961 20.6031 ;
		RECT 0.2105 20.8086 23.814 21.0102 ;
		RECT 23.814 20.8086 23.961 21.0102 ;
		RECT 0.2105 21.12 23.814 21.2431 ;
		RECT 23.814 21.12 23.961 21.2431 ;
		RECT 0.2105 21.4486 23.814 21.6502 ;
		RECT 23.814 21.4486 23.961 21.6502 ;
		RECT 0.2105 21.76 23.814 21.8831 ;
		RECT 23.814 21.76 23.961 21.8831 ;
		RECT 0.2105 22.0886 23.814 22.2902 ;
		RECT 23.814 22.0886 23.961 22.2902 ;
		RECT 0.2105 22.4 23.814 22.5231 ;
		RECT 23.814 22.4 23.961 22.5231 ;
		RECT 0.2105 22.7286 23.814 22.9302 ;
		RECT 23.814 22.7286 23.961 22.9302 ;
		RECT 0.2105 23.04 23.814 23.1631 ;
		RECT 23.814 23.04 23.961 23.1631 ;
		RECT 0.2105 23.3686 23.814 23.5702 ;
		RECT 23.814 23.3686 23.961 23.5702 ;
		RECT 0.2105 23.68 23.814 23.8031 ;
		RECT 23.814 23.68 23.961 23.8031 ;
		RECT 0.2105 24.0086 23.814 24.2102 ;
		RECT 23.814 24.0086 23.961 24.2102 ;
		RECT 0.2105 24.32 23.814 24.4431 ;
		RECT 23.814 24.32 23.961 24.4431 ;
		RECT 0.2105 24.6486 23.814 24.8502 ;
		RECT 23.814 24.6486 23.961 24.8502 ;
		RECT 0.2105 24.96 23.814 25.0831 ;
		RECT 23.814 24.96 23.961 25.0831 ;
		RECT 0.2105 25.2886 23.814 25.4902 ;
		RECT 23.814 25.2886 23.961 25.4902 ;
		RECT 0.2105 25.6 23.814 25.7231 ;
		RECT 23.814 25.6 23.961 25.7231 ;
		RECT 0.2105 25.9286 23.814 26.1302 ;
		RECT 23.814 25.9286 23.961 26.1302 ;
		RECT 0.2105 26.24 23.814 26.3631 ;
		RECT 23.814 26.24 23.961 26.3631 ;
		RECT 0.2105 26.5686 23.814 26.7702 ;
		RECT 23.814 26.5686 23.961 26.7702 ;
		RECT 0.2105 26.88 23.814 27.0031 ;
		RECT 23.814 26.88 23.961 27.0031 ;
		RECT 0.2105 27.2086 23.814 27.4102 ;
		RECT 23.814 27.2086 23.961 27.4102 ;
		RECT 0.2105 27.52 23.814 27.6431 ;
		RECT 23.814 27.52 23.961 27.6431 ;
		RECT 0.2105 27.8486 23.814 28.0502 ;
		RECT 23.814 27.8486 23.961 28.0502 ;
		RECT 0.2105 28.16 23.814 28.2831 ;
		RECT 23.814 28.16 23.961 28.2831 ;
		RECT 0.2105 28.4886 23.814 28.6902 ;
		RECT 23.814 28.4886 23.961 28.6902 ;
		RECT 0.2105 28.8 23.814 28.9231 ;
		RECT 23.814 28.8 23.961 28.9231 ;
		RECT 0.2105 29.1286 23.814 29.3302 ;
		RECT 23.814 29.1286 23.961 29.3302 ;
		RECT 0.2105 29.44 23.814 29.5631 ;
		RECT 23.814 29.44 23.961 29.5631 ;
		RECT 0.2105 29.7686 23.814 29.9702 ;
		RECT 23.814 29.7686 23.961 29.9702 ;
		RECT 0.2105 30.08 23.814 30.2031 ;
		RECT 23.814 30.08 23.961 30.2031 ;
		RECT 0.2105 30.4086 23.814 30.6102 ;
		RECT 23.814 30.4086 23.961 30.6102 ;
		RECT 0.2105 30.72 23.814 30.8431 ;
		RECT 23.814 30.72 23.961 30.8431 ;
		RECT 0.2105 31.3067 23.814 31.5561 ;
		RECT 23.814 31.3067 23.961 31.5561 ;
		RECT 0.2105 32.0361 23.814 32.3749 ;
		RECT 23.814 32.0361 23.961 32.3749 ;
		RECT 0.2105 32.5631 23.814 32.902 ;
		RECT 23.814 32.5631 23.961 32.902 ;
		RECT 0.2105 33.0902 23.814 33.429 ;
		RECT 23.814 33.0902 23.961 33.429 ;
		RECT 0.2105 33.6173 23.814 33.9561 ;
		RECT 23.814 33.6173 23.961 33.9561 ;
		RECT 0.2105 34.1443 23.814 35.0102 ;
		RECT 23.814 34.1443 23.961 35.0102 ;
		RECT 0.2105 35.1984 23.814 36.0643 ;
		RECT 23.814 35.1984 23.961 36.0643 ;
		RECT 0.2105 36.2525 23.814 36.5914 ;
		RECT 23.814 36.2525 23.961 36.5914 ;
		RECT 0.2105 36.7796 23.814 37.1184 ;
		RECT 23.814 36.7796 23.961 37.1184 ;
		RECT 0.2105 37.3067 23.814 37.6455 ;
		RECT 23.814 37.3067 23.961 37.6455 ;
		RECT 0.2105 38.2039 23.814 38.4443 ;
		RECT 23.814 38.2039 23.961 38.4443 ;
		RECT 0.2105 38.7475 23.814 38.949 ;
		RECT 23.814 38.7475 23.961 38.949 ;
		RECT 0.2105 39.0588 23.814 39.182 ;
		RECT 23.814 39.0588 23.961 39.182 ;
		RECT 0.2105 39.3875 23.814 39.589 ;
		RECT 23.814 39.3875 23.961 39.589 ;
		RECT 0.2105 39.6988 23.814 39.822 ;
		RECT 23.814 39.6988 23.961 39.822 ;
		RECT 0.2105 40.0275 23.814 40.229 ;
		RECT 23.814 40.0275 23.961 40.229 ;
		RECT 0.2105 40.3388 23.814 40.462 ;
		RECT 23.814 40.3388 23.961 40.462 ;
		RECT 0.2105 40.6675 23.814 40.869 ;
		RECT 23.814 40.6675 23.961 40.869 ;
		RECT 0.2105 40.9788 23.814 41.102 ;
		RECT 23.814 40.9788 23.961 41.102 ;
		RECT 0.2105 41.3075 23.814 41.509 ;
		RECT 23.814 41.3075 23.961 41.509 ;
		RECT 0.2105 41.6188 23.814 41.742 ;
		RECT 23.814 41.6188 23.961 41.742 ;
		RECT 0.2105 41.9475 23.814 42.149 ;
		RECT 23.814 41.9475 23.961 42.149 ;
		RECT 0.2105 42.2588 23.814 42.382 ;
		RECT 23.814 42.2588 23.961 42.382 ;
		RECT 0.2105 42.5875 23.814 42.789 ;
		RECT 23.814 42.5875 23.961 42.789 ;
		RECT 0.2105 42.8988 23.814 43.022 ;
		RECT 23.814 42.8988 23.961 43.022 ;
		RECT 0.2105 43.2275 23.814 43.429 ;
		RECT 23.814 43.2275 23.961 43.429 ;
		RECT 0.2105 43.5388 23.814 43.662 ;
		RECT 23.814 43.5388 23.961 43.662 ;
		RECT 0.2105 43.8675 23.814 44.069 ;
		RECT 23.814 43.8675 23.961 44.069 ;
		RECT 0.2105 44.1788 23.814 44.302 ;
		RECT 23.814 44.1788 23.961 44.302 ;
		RECT 0.2105 44.5075 23.814 44.709 ;
		RECT 23.814 44.5075 23.961 44.709 ;
		RECT 0.2105 44.8188 23.814 44.942 ;
		RECT 23.814 44.8188 23.961 44.942 ;
		RECT 0.2105 45.1475 23.814 45.349 ;
		RECT 23.814 45.1475 23.961 45.349 ;
		RECT 0.2105 45.4588 23.814 45.582 ;
		RECT 23.814 45.4588 23.961 45.582 ;
		RECT 0.2105 45.7875 23.814 45.989 ;
		RECT 23.814 45.7875 23.961 45.989 ;
		RECT 0.2105 46.0988 23.814 46.222 ;
		RECT 23.814 46.0988 23.961 46.222 ;
		RECT 0.2105 46.4275 23.814 46.629 ;
		RECT 23.814 46.4275 23.961 46.629 ;
		RECT 0.2105 46.7388 23.814 46.862 ;
		RECT 23.814 46.7388 23.961 46.862 ;
		RECT 0.2105 47.0675 23.814 47.269 ;
		RECT 23.814 47.0675 23.961 47.269 ;
		RECT 0.2105 47.3788 23.814 47.502 ;
		RECT 23.814 47.3788 23.961 47.502 ;
		RECT 0.2105 47.7075 23.814 47.909 ;
		RECT 23.814 47.7075 23.961 47.909 ;
		RECT 0.2105 48.0188 23.814 48.142 ;
		RECT 23.814 48.0188 23.961 48.142 ;
		RECT 0.2105 48.3475 23.814 48.549 ;
		RECT 23.814 48.3475 23.961 48.549 ;
		RECT 0.2105 48.6588 23.814 48.782 ;
		RECT 23.814 48.6588 23.961 48.782 ;
		RECT 0.2105 48.9875 23.814 49.189 ;
		RECT 23.814 48.9875 23.961 49.189 ;
		RECT 0.2105 49.2988 23.814 49.422 ;
		RECT 23.814 49.2988 23.961 49.422 ;
		RECT 0.2105 49.6275 23.814 49.829 ;
		RECT 23.814 49.6275 23.961 49.829 ;
		RECT 0.2105 49.9388 23.814 50.062 ;
		RECT 23.814 49.9388 23.961 50.062 ;
		RECT 0.2105 50.2675 23.814 50.469 ;
		RECT 23.814 50.2675 23.961 50.469 ;
		RECT 0.2105 50.5788 23.814 50.702 ;
		RECT 23.814 50.5788 23.961 50.702 ;
		RECT 0.2105 50.9075 23.814 51.109 ;
		RECT 23.814 50.9075 23.961 51.109 ;
		RECT 0.2105 51.2188 23.814 51.342 ;
		RECT 23.814 51.2188 23.961 51.342 ;
		RECT 0.2105 51.5475 23.814 51.749 ;
		RECT 23.814 51.5475 23.961 51.749 ;
		RECT 0.2105 51.8588 23.814 51.982 ;
		RECT 23.814 51.8588 23.961 51.982 ;
		RECT 0.2105 52.1875 23.814 52.389 ;
		RECT 23.814 52.1875 23.961 52.389 ;
		RECT 0.2105 52.4988 23.814 52.622 ;
		RECT 23.814 52.4988 23.961 52.622 ;
		RECT 0.2105 52.8275 23.814 53.029 ;
		RECT 23.814 52.8275 23.961 53.029 ;
		RECT 0.2105 53.1388 23.814 53.262 ;
		RECT 23.814 53.1388 23.961 53.262 ;
		RECT 0.2105 53.4675 23.814 53.669 ;
		RECT 23.814 53.4675 23.961 53.669 ;
		RECT 0.2105 53.7788 23.814 53.902 ;
		RECT 23.814 53.7788 23.961 53.902 ;
		RECT 0.2105 54.1075 23.814 54.309 ;
		RECT 23.814 54.1075 23.961 54.309 ;
		RECT 0.2105 54.4188 23.814 54.542 ;
		RECT 23.814 54.4188 23.961 54.542 ;
		RECT 0.2105 54.7475 23.814 54.949 ;
		RECT 23.814 54.7475 23.961 54.949 ;
		RECT 0.2105 55.0588 23.814 55.182 ;
		RECT 23.814 55.0588 23.961 55.182 ;
		RECT 0.2105 55.3875 23.814 55.589 ;
		RECT 23.814 55.3875 23.961 55.589 ;
		RECT 0.2105 55.6988 23.814 55.822 ;
		RECT 23.814 55.6988 23.961 55.822 ;
		RECT 0.2105 56.0275 23.814 56.229 ;
		RECT 23.814 56.0275 23.961 56.229 ;
		RECT 0.2105 56.3388 23.814 56.462 ;
		RECT 23.814 56.3388 23.961 56.462 ;
		RECT 0.2105 56.6675 23.814 56.869 ;
		RECT 23.814 56.6675 23.961 56.869 ;
		RECT 0.2105 56.9788 23.814 57.102 ;
		RECT 23.814 56.9788 23.961 57.102 ;
		RECT 0.2105 57.3075 23.814 57.509 ;
		RECT 23.814 57.3075 23.961 57.509 ;
		RECT 0.2105 57.6188 23.814 57.742 ;
		RECT 23.814 57.6188 23.961 57.742 ;
		RECT 0.2105 57.9475 23.814 58.149 ;
		RECT 23.814 57.9475 23.961 58.149 ;
		RECT 0.2105 58.2588 23.814 58.382 ;
		RECT 23.814 58.2588 23.961 58.382 ;
		RECT 0.2105 58.5875 23.814 58.789 ;
		RECT 23.814 58.5875 23.961 58.789 ;
		RECT 0.2105 58.8988 23.814 59.022 ;
		RECT 23.814 58.8988 23.961 59.022 ;
		RECT 0.2105 59.2275 23.814 59.429 ;
		RECT 23.814 59.2275 23.961 59.429 ;
		RECT 0.2105 59.5388 23.814 59.662 ;
		RECT 23.814 59.5388 23.961 59.662 ;
		RECT 0.2105 59.8675 23.814 60.069 ;
		RECT 23.814 59.8675 23.961 60.069 ;
		RECT 0.2105 60.1788 23.814 60.302 ;
		RECT 23.814 60.1788 23.961 60.302 ;
		RECT 0.2105 60.5075 23.814 60.709 ;
		RECT 23.814 60.5075 23.961 60.709 ;
		RECT 0.2105 60.8188 23.814 60.942 ;
		RECT 23.814 60.8188 23.961 60.942 ;
		RECT 0.2105 61.1475 23.814 61.349 ;
		RECT 23.814 61.1475 23.961 61.349 ;
		RECT 0.2105 61.4588 23.814 61.582 ;
		RECT 23.814 61.4588 23.961 61.582 ;
		RECT 0.2105 61.7875 23.814 61.989 ;
		RECT 23.814 61.7875 23.961 61.989 ;
		RECT 0.2105 62.0988 23.814 62.222 ;
		RECT 23.814 62.0988 23.961 62.222 ;
		RECT 0.2105 62.4275 23.814 62.629 ;
		RECT 23.814 62.4275 23.961 62.629 ;
		RECT 0.2105 62.7388 23.814 62.862 ;
		RECT 23.814 62.7388 23.961 62.862 ;
		RECT 0.2105 63.0675 23.814 63.269 ;
		RECT 23.814 63.0675 23.961 63.269 ;
		RECT 0.2105 63.3788 23.814 63.502 ;
		RECT 23.814 63.3788 23.961 63.502 ;
		RECT 0.2105 63.7075 23.814 63.909 ;
		RECT 23.814 63.7075 23.961 63.909 ;
		RECT 0.2105 64.0188 23.814 64.142 ;
		RECT 23.814 64.0188 23.961 64.142 ;
		RECT 0.2105 64.3475 23.814 64.549 ;
		RECT 23.814 64.3475 23.961 64.549 ;
		RECT 0.2105 64.6588 23.814 64.782 ;
		RECT 23.814 64.6588 23.961 64.782 ;
		RECT 0.2105 64.9875 23.814 65.189 ;
		RECT 23.814 64.9875 23.961 65.189 ;
		RECT 0.2105 65.2988 23.814 65.422 ;
		RECT 23.814 65.2988 23.961 65.422 ;
		RECT 0.2105 65.6275 23.814 65.829 ;
		RECT 23.814 65.6275 23.961 65.829 ;
		RECT 0.2105 65.9388 23.814 66.062 ;
		RECT 23.814 65.9388 23.961 66.062 ;
		RECT 0.2105 66.2675 23.814 66.469 ;
		RECT 23.814 66.2675 23.961 66.469 ;
		RECT 0.2105 66.5788 23.814 66.702 ;
		RECT 23.814 66.5788 23.961 66.702 ;
		RECT 0.2105 66.9075 23.814 67.109 ;
		RECT 23.814 66.9075 23.961 67.109 ;
		RECT 0.2105 67.2188 23.814 67.342 ;
		RECT 23.814 67.2188 23.961 67.342 ;
		RECT 0.2105 67.5475 23.814 67.749 ;
		RECT 23.814 67.5475 23.961 67.749 ;
		RECT 0.2105 67.8588 23.814 67.982 ;
		RECT 23.814 67.8588 23.961 67.982 ;
		RECT 0.2105 68.1875 23.814 68.389 ;
		RECT 23.814 68.1875 23.961 68.389 ;
		RECT 0.2105 68.4988 23.814 68.622 ;
		RECT 23.814 68.4988 23.961 68.622 ;
		RECT 0.2105 68.8275 23.814 69.029 ;
		RECT 23.814 68.8275 23.961 69.029 ;
		RECT 0.2105 69.1388 23.814 69.262 ;
		RECT 23.814 69.1388 23.961 69.262 ;
		RECT 0.2105 69.8063 23.814 69.9294 ;
		RECT 23.814 69.8063 23.961 69.9294 ;
		RECT 0.2105 70.0392 23.814 70.2408 ;
		RECT 23.814 70.0392 23.961 70.2408 ;
		RECT 0.2105 70.4463 23.814 70.5694 ;
		RECT 23.814 70.4463 23.961 70.5694 ;
		RECT 0.2105 70.6792 23.814 70.8808 ;
		RECT 23.814 70.6792 23.961 70.8808 ;
		RECT 0.2105 71.0863 23.814 71.2094 ;
		RECT 23.814 71.0863 23.961 71.2094 ;
		RECT 0.2105 71.3192 23.814 71.5208 ;
		RECT 23.814 71.3192 23.961 71.5208 ;
		RECT 0.2105 71.7263 23.814 71.8494 ;
		RECT 23.814 71.7263 23.961 71.8494 ;
		RECT 0.2105 71.9592 23.814 72.1608 ;
		RECT 23.814 71.9592 23.961 72.1608 ;
		RECT 0.2105 72.3663 23.814 72.4894 ;
		RECT 23.814 72.3663 23.961 72.4894 ;
		RECT 0.2105 72.5992 23.814 72.8008 ;
		RECT 23.814 72.5992 23.961 72.8008 ;
		RECT 0.2105 73.0063 23.814 73.1294 ;
		RECT 23.814 73.0063 23.961 73.1294 ;
		RECT 0.2105 73.2392 23.814 73.4408 ;
		RECT 23.814 73.2392 23.961 73.4408 ;
		RECT 0.2105 73.6463 23.814 73.7694 ;
		RECT 23.814 73.6463 23.961 73.7694 ;
		RECT 0.2105 73.8792 23.814 74.0808 ;
		RECT 23.814 73.8792 23.961 74.0808 ;
		RECT 0.2105 74.2863 23.814 74.4094 ;
		RECT 23.814 74.2863 23.961 74.4094 ;
		RECT 0.2105 74.5192 23.814 74.7208 ;
		RECT 23.814 74.5192 23.961 74.7208 ;
		RECT 0.2105 74.9263 23.814 75.0494 ;
		RECT 23.814 74.9263 23.961 75.0494 ;
		RECT 0.2105 75.1592 23.814 75.3608 ;
		RECT 23.814 75.1592 23.961 75.3608 ;
		RECT 0.2105 75.5663 23.814 75.6894 ;
		RECT 23.814 75.5663 23.961 75.6894 ;
		RECT 0.2105 75.7992 23.814 76.0008 ;
		RECT 23.814 75.7992 23.961 76.0008 ;
		RECT 0.2105 76.2063 23.814 76.3294 ;
		RECT 23.814 76.2063 23.961 76.3294 ;
		RECT 0.2105 76.4392 23.814 76.6408 ;
		RECT 23.814 76.4392 23.961 76.6408 ;
		RECT 0.2105 76.8463 23.814 76.9694 ;
		RECT 23.814 76.8463 23.961 76.9694 ;
		RECT 0.2105 77.0792 23.814 77.2808 ;
		RECT 23.814 77.0792 23.961 77.2808 ;
		RECT 0.2105 77.4863 23.814 77.6094 ;
		RECT 23.814 77.4863 23.961 77.6094 ;
		RECT 0.2105 77.7192 23.814 77.9208 ;
		RECT 23.814 77.7192 23.961 77.9208 ;
		RECT 0.2105 78.1263 23.814 78.2494 ;
		RECT 23.814 78.1263 23.961 78.2494 ;
		RECT 0.2105 78.3592 23.814 78.5608 ;
		RECT 23.814 78.3592 23.961 78.5608 ;
		RECT 0.2105 78.7663 23.814 78.8894 ;
		RECT 23.814 78.7663 23.961 78.8894 ;
		RECT 0.2105 78.9992 23.814 79.2008 ;
		RECT 23.814 78.9992 23.961 79.2008 ;
		RECT 0.2105 79.4063 23.814 79.5294 ;
		RECT 23.814 79.4063 23.961 79.5294 ;
		RECT 0.2105 79.6392 23.814 79.8408 ;
		RECT 23.814 79.6392 23.961 79.8408 ;
		RECT 0.2105 80.0463 23.814 80.1694 ;
		RECT 23.814 80.0463 23.961 80.1694 ;
		RECT 0.2105 80.2792 23.814 80.4808 ;
		RECT 23.814 80.2792 23.961 80.4808 ;
		RECT 0.2105 80.6863 23.814 80.8094 ;
		RECT 23.814 80.6863 23.961 80.8094 ;
		RECT 0.2105 80.9192 23.814 81.1208 ;
		RECT 23.814 80.9192 23.961 81.1208 ;
		RECT 0.2105 81.3263 23.814 81.4494 ;
		RECT 23.814 81.3263 23.961 81.4494 ;
		RECT 0.2105 81.5592 23.814 81.7608 ;
		RECT 23.814 81.5592 23.961 81.7608 ;
		RECT 0.2105 81.9663 23.814 82.0894 ;
		RECT 23.814 81.9663 23.961 82.0894 ;
		RECT 0.2105 82.1992 23.814 82.4008 ;
		RECT 23.814 82.1992 23.961 82.4008 ;
		RECT 0.2105 82.6063 23.814 82.7294 ;
		RECT 23.814 82.6063 23.961 82.7294 ;
		RECT 0.2105 82.8392 23.814 83.0408 ;
		RECT 23.814 82.8392 23.961 83.0408 ;
		RECT 0.2105 83.2463 23.814 83.3694 ;
		RECT 23.814 83.2463 23.961 83.3694 ;
		RECT 0.2105 83.4792 23.814 83.6808 ;
		RECT 23.814 83.4792 23.961 83.6808 ;
		RECT 0.2105 83.8863 23.814 84.0094 ;
		RECT 23.814 83.8863 23.961 84.0094 ;
		RECT 0.2105 84.1192 23.814 84.3208 ;
		RECT 23.814 84.1192 23.961 84.3208 ;
		RECT 0.2105 84.5263 23.814 84.6494 ;
		RECT 23.814 84.5263 23.961 84.6494 ;
		RECT 0.2105 84.7592 23.814 84.9608 ;
		RECT 23.814 84.7592 23.961 84.9608 ;
		RECT 0.2105 85.1663 23.814 85.2894 ;
		RECT 23.814 85.1663 23.961 85.2894 ;
		RECT 0.2105 85.3992 23.814 85.6008 ;
		RECT 23.814 85.3992 23.961 85.6008 ;
		RECT 0.2105 85.8063 23.814 85.9294 ;
		RECT 23.814 85.8063 23.961 85.9294 ;
		RECT 0.2105 86.0392 23.814 86.2408 ;
		RECT 23.814 86.0392 23.961 86.2408 ;
		RECT 0.2105 86.4463 23.814 86.5694 ;
		RECT 23.814 86.4463 23.961 86.5694 ;
		RECT 0.2105 86.6792 23.814 86.8808 ;
		RECT 23.814 86.6792 23.961 86.8808 ;
		RECT 0.2105 87.0863 23.814 87.2094 ;
		RECT 23.814 87.0863 23.961 87.2094 ;
		RECT 0.2105 87.3192 23.814 87.5208 ;
		RECT 23.814 87.3192 23.961 87.5208 ;
		RECT 0.2105 87.7263 23.814 87.8494 ;
		RECT 23.814 87.7263 23.961 87.8494 ;
		RECT 0.2105 87.9592 23.814 88.1608 ;
		RECT 23.814 87.9592 23.961 88.1608 ;
		RECT 0.2105 88.3663 23.814 88.4894 ;
		RECT 23.814 88.3663 23.961 88.4894 ;
		RECT 0.2105 88.5992 23.814 88.8008 ;
		RECT 23.814 88.5992 23.961 88.8008 ;
		RECT 0.2105 89.0063 23.814 89.1294 ;
		RECT 23.814 89.0063 23.961 89.1294 ;
		RECT 0.2105 89.2392 23.814 89.4408 ;
		RECT 23.814 89.2392 23.961 89.4408 ;
		RECT 0.2105 89.6463 23.814 89.7694 ;
		RECT 23.814 89.6463 23.961 89.7694 ;
		RECT 0.2105 89.8792 23.814 90.0808 ;
		RECT 23.814 89.8792 23.961 90.0808 ;
		RECT 0.2105 90.2863 23.814 90.4094 ;
		RECT 23.814 90.2863 23.961 90.4094 ;
		RECT 0.2105 90.5192 23.814 90.7208 ;
		RECT 23.814 90.5192 23.961 90.7208 ;
		RECT 0.2105 90.9263 23.814 91.0494 ;
		RECT 23.814 90.9263 23.961 91.0494 ;
		RECT 0.2105 91.1592 23.814 91.3608 ;
		RECT 23.814 91.1592 23.961 91.3608 ;
		RECT 0.2105 91.5663 23.814 91.6894 ;
		RECT 23.814 91.5663 23.961 91.6894 ;
		RECT 0.2105 91.7992 23.814 92.0008 ;
		RECT 23.814 91.7992 23.961 92.0008 ;
		RECT 0.2105 92.2063 23.814 92.3294 ;
		RECT 23.814 92.2063 23.961 92.3294 ;
		RECT 0.2105 92.4392 23.814 92.6408 ;
		RECT 23.814 92.4392 23.961 92.6408 ;
		RECT 0.2105 92.8463 23.814 92.9694 ;
		RECT 23.814 92.8463 23.961 92.9694 ;
		RECT 0.2105 93.0792 23.814 93.2808 ;
		RECT 23.814 93.0792 23.961 93.2808 ;
		RECT 0.2105 93.4863 23.814 93.6094 ;
		RECT 23.814 93.4863 23.961 93.6094 ;
		RECT 0.2105 93.7192 23.814 93.9208 ;
		RECT 23.814 93.7192 23.961 93.9208 ;
		RECT 0.2105 94.1263 23.814 94.2494 ;
		RECT 23.814 94.1263 23.961 94.2494 ;
		RECT 0.2105 94.3592 23.814 94.5608 ;
		RECT 23.814 94.3592 23.961 94.5608 ;
		RECT 0.2105 94.7663 23.814 94.8894 ;
		RECT 23.814 94.7663 23.961 94.8894 ;
		RECT 0.2105 94.9992 23.814 95.2008 ;
		RECT 23.814 94.9992 23.961 95.2008 ;
		RECT 0.2105 95.4063 23.814 95.5294 ;
		RECT 23.814 95.4063 23.961 95.5294 ;
		RECT 0.2105 95.6392 23.814 95.8408 ;
		RECT 23.814 95.6392 23.961 95.8408 ;
		RECT 0.2105 96.0463 23.814 96.1694 ;
		RECT 23.814 96.0463 23.961 96.1694 ;
		RECT 0.2105 96.2792 23.814 96.4808 ;
		RECT 23.814 96.2792 23.961 96.4808 ;
		RECT 0.2105 96.6863 23.814 96.8094 ;
		RECT 23.814 96.6863 23.961 96.8094 ;
		RECT 0.2105 96.9192 23.814 97.1208 ;
		RECT 23.814 96.9192 23.961 97.1208 ;
		RECT 0.2105 97.3263 23.814 97.4494 ;
		RECT 23.814 97.3263 23.961 97.4494 ;
		RECT 0.2105 97.5592 23.814 97.7608 ;
		RECT 23.814 97.5592 23.961 97.7608 ;
		RECT 0.2105 97.9663 23.814 98.0894 ;
		RECT 23.814 97.9663 23.961 98.0894 ;
		RECT 0.2105 98.1992 23.814 98.4008 ;
		RECT 23.814 98.1992 23.961 98.4008 ;
		RECT 0.2105 98.6063 23.814 98.7294 ;
		RECT 23.814 98.6063 23.961 98.7294 ;
		RECT 0.2105 98.8392 23.814 99.0408 ;
		RECT 23.814 98.8392 23.961 99.0408 ;
		RECT 0.2105 99.2463 23.814 99.3694 ;
		RECT 23.814 99.2463 23.961 99.3694 ;
		RECT 0.2105 99.4792 23.814 99.6808 ;
		RECT 23.814 99.4792 23.961 99.6808 ;
		RECT 0.2105 99.8863 23.814 100.0094 ;
		RECT 23.814 99.8863 23.961 100.0094 ;
		RECT 0.2105 100.1192 23.814 100.3208 ;
		RECT 23.814 100.1192 23.961 100.3208 ;
		RECT 0.2105 100.6239 23.814 100.8643 ;
		RECT 23.814 100.6239 23.961 100.8643 ;
		RECT 0.2105 101.4227 23.814 101.7616 ;
		RECT 23.814 101.4227 23.961 101.7616 ;
		RECT 0.2105 101.9498 23.814 102.2886 ;
		RECT 23.814 101.9498 23.961 102.2886 ;
		RECT 0.2105 102.4769 23.814 102.8157 ;
		RECT 23.814 102.4769 23.961 102.8157 ;
		RECT 0.2105 103.0039 23.814 103.8698 ;
		RECT 23.814 103.0039 23.961 103.8698 ;
		RECT 0.2105 104.058 23.814 104.9239 ;
		RECT 23.814 104.058 23.961 104.9239 ;
		RECT 0.2105 105.1122 23.814 105.451 ;
		RECT 23.814 105.1122 23.961 105.451 ;
		RECT 0.2105 105.6392 23.814 105.978 ;
		RECT 23.814 105.6392 23.961 105.978 ;
		RECT 0.2105 106.1663 23.814 106.5051 ;
		RECT 23.814 106.1663 23.961 106.5051 ;
		RECT 0.2105 106.6933 23.814 107.0322 ;
		RECT 23.814 106.6933 23.961 107.0322 ;
		RECT 0.2105 107.5122 23.814 107.7616 ;
		RECT 23.814 107.5122 23.961 107.7616 ;
		RECT 0.2105 108.2251 23.814 108.3482 ;
		RECT 23.814 108.2251 23.961 108.3482 ;
		RECT 0.2105 108.458 23.814 108.6596 ;
		RECT 23.814 108.458 23.961 108.6596 ;
		RECT 0.2105 108.8651 23.814 108.9882 ;
		RECT 23.814 108.8651 23.961 108.9882 ;
		RECT 0.2105 109.098 23.814 109.2996 ;
		RECT 23.814 109.098 23.961 109.2996 ;
		RECT 0.2105 109.5051 23.814 109.6282 ;
		RECT 23.814 109.5051 23.961 109.6282 ;
		RECT 0.2105 109.738 23.814 109.9396 ;
		RECT 23.814 109.738 23.961 109.9396 ;
		RECT 0.2105 110.1451 23.814 110.2682 ;
		RECT 23.814 110.1451 23.961 110.2682 ;
		RECT 0.2105 110.378 23.814 110.5796 ;
		RECT 23.814 110.378 23.961 110.5796 ;
		RECT 0.2105 110.7851 23.814 110.9082 ;
		RECT 23.814 110.7851 23.961 110.9082 ;
		RECT 0.2105 111.018 23.814 111.2196 ;
		RECT 23.814 111.018 23.961 111.2196 ;
		RECT 0.2105 111.4251 23.814 111.5482 ;
		RECT 23.814 111.4251 23.961 111.5482 ;
		RECT 0.2105 111.658 23.814 111.8596 ;
		RECT 23.814 111.658 23.961 111.8596 ;
		RECT 0.2105 112.0651 23.814 112.1882 ;
		RECT 23.814 112.0651 23.961 112.1882 ;
		RECT 0.2105 112.298 23.814 112.4996 ;
		RECT 23.814 112.298 23.961 112.4996 ;
		RECT 0.2105 112.7051 23.814 112.8282 ;
		RECT 23.814 112.7051 23.961 112.8282 ;
		RECT 0.2105 112.938 23.814 113.1396 ;
		RECT 23.814 112.938 23.961 113.1396 ;
		RECT 0.2105 113.3451 23.814 113.4682 ;
		RECT 23.814 113.3451 23.961 113.4682 ;
		RECT 0.2105 113.578 23.814 113.7796 ;
		RECT 23.814 113.578 23.961 113.7796 ;
		RECT 0.2105 113.9851 23.814 114.1082 ;
		RECT 23.814 113.9851 23.961 114.1082 ;
		RECT 0.2105 114.218 23.814 114.4196 ;
		RECT 23.814 114.218 23.961 114.4196 ;
		RECT 0.2105 114.6251 23.814 114.7482 ;
		RECT 23.814 114.6251 23.961 114.7482 ;
		RECT 0.2105 114.858 23.814 115.0596 ;
		RECT 23.814 114.858 23.961 115.0596 ;
		RECT 0.2105 115.2651 23.814 115.3882 ;
		RECT 23.814 115.2651 23.961 115.3882 ;
		RECT 0.2105 115.498 23.814 115.6996 ;
		RECT 23.814 115.498 23.961 115.6996 ;
		RECT 0.2105 115.9051 23.814 116.0282 ;
		RECT 23.814 115.9051 23.961 116.0282 ;
		RECT 0.2105 116.138 23.814 116.3396 ;
		RECT 23.814 116.138 23.961 116.3396 ;
		RECT 0.2105 116.5451 23.814 116.6682 ;
		RECT 23.814 116.5451 23.961 116.6682 ;
		RECT 0.2105 116.778 23.814 116.9796 ;
		RECT 23.814 116.778 23.961 116.9796 ;
		RECT 0.2105 117.1851 23.814 117.3082 ;
		RECT 23.814 117.1851 23.961 117.3082 ;
		RECT 0.2105 117.418 23.814 117.6196 ;
		RECT 23.814 117.418 23.961 117.6196 ;
		RECT 0.2105 117.8251 23.814 117.9482 ;
		RECT 23.814 117.8251 23.961 117.9482 ;
		RECT 0.2105 118.058 23.814 118.2596 ;
		RECT 23.814 118.058 23.961 118.2596 ;
		RECT 0.2105 118.4651 23.814 118.5882 ;
		RECT 23.814 118.4651 23.961 118.5882 ;
		RECT 0.2105 118.698 23.814 118.8996 ;
		RECT 23.814 118.698 23.961 118.8996 ;
		RECT 0.2105 119.1051 23.814 119.2282 ;
		RECT 23.814 119.1051 23.961 119.2282 ;
		RECT 0.2105 119.338 23.814 119.5396 ;
		RECT 23.814 119.338 23.961 119.5396 ;
		RECT 0.2105 119.7451 23.814 119.8682 ;
		RECT 23.814 119.7451 23.961 119.8682 ;
		RECT 0.2105 119.978 23.814 120.1796 ;
		RECT 23.814 119.978 23.961 120.1796 ;
		RECT 0.2105 120.3851 23.814 120.5082 ;
		RECT 23.814 120.3851 23.961 120.5082 ;
		RECT 0.2105 120.618 23.814 120.8196 ;
		RECT 23.814 120.618 23.961 120.8196 ;
		RECT 0.2105 121.0251 23.814 121.1482 ;
		RECT 23.814 121.0251 23.961 121.1482 ;
		RECT 0.2105 121.258 23.814 121.4596 ;
		RECT 23.814 121.258 23.961 121.4596 ;
		RECT 0.2105 121.6651 23.814 121.7882 ;
		RECT 23.814 121.6651 23.961 121.7882 ;
		RECT 0.2105 121.898 23.814 122.0996 ;
		RECT 23.814 121.898 23.961 122.0996 ;
		RECT 0.2105 122.3051 23.814 122.4282 ;
		RECT 23.814 122.3051 23.961 122.4282 ;
		RECT 0.2105 122.538 23.814 122.7396 ;
		RECT 23.814 122.538 23.961 122.7396 ;
		RECT 0.2105 122.9451 23.814 123.0682 ;
		RECT 23.814 122.9451 23.961 123.0682 ;
		RECT 0.2105 123.178 23.814 123.3796 ;
		RECT 23.814 123.178 23.961 123.3796 ;
		RECT 0.2105 123.5851 23.814 123.7082 ;
		RECT 23.814 123.5851 23.961 123.7082 ;
		RECT 0.2105 123.818 23.814 124.0196 ;
		RECT 23.814 123.818 23.961 124.0196 ;
		RECT 0.2105 124.2251 23.814 124.3482 ;
		RECT 23.814 124.2251 23.961 124.3482 ;
		RECT 0.2105 124.458 23.814 124.6596 ;
		RECT 23.814 124.458 23.961 124.6596 ;
		RECT 0.2105 124.8651 23.814 124.9882 ;
		RECT 23.814 124.8651 23.961 124.9882 ;
		RECT 0.2105 125.098 23.814 125.2996 ;
		RECT 23.814 125.098 23.961 125.2996 ;
		RECT 0.2105 125.5051 23.814 125.6282 ;
		RECT 23.814 125.5051 23.961 125.6282 ;
		RECT 0.2105 125.738 23.814 125.9396 ;
		RECT 23.814 125.738 23.961 125.9396 ;
		RECT 0.2105 126.1451 23.814 126.2682 ;
		RECT 23.814 126.1451 23.961 126.2682 ;
		RECT 0.2105 126.378 23.814 126.5796 ;
		RECT 23.814 126.378 23.961 126.5796 ;
		RECT 0.2105 126.7851 23.814 126.9082 ;
		RECT 23.814 126.7851 23.961 126.9082 ;
		RECT 0.2105 127.018 23.814 127.2196 ;
		RECT 23.814 127.018 23.961 127.2196 ;
		RECT 0.2105 127.4251 23.814 127.5482 ;
		RECT 23.814 127.4251 23.961 127.5482 ;
		RECT 0.2105 127.658 23.814 127.8596 ;
		RECT 23.814 127.658 23.961 127.8596 ;
		RECT 0.2105 128.0651 23.814 128.1882 ;
		RECT 23.814 128.0651 23.961 128.1882 ;
		RECT 0.2105 128.298 23.814 128.4996 ;
		RECT 23.814 128.298 23.961 128.4996 ;
		RECT 0.2105 128.7051 23.814 128.8282 ;
		RECT 23.814 128.7051 23.961 128.8282 ;
		RECT 0.2105 128.938 23.814 129.1396 ;
		RECT 23.814 128.938 23.961 129.1396 ;
		RECT 0.2105 129.3451 23.814 129.4682 ;
		RECT 23.814 129.3451 23.961 129.4682 ;
		RECT 0.2105 129.578 23.814 129.7796 ;
		RECT 23.814 129.578 23.961 129.7796 ;
		RECT 0.2105 129.9851 23.814 130.1082 ;
		RECT 23.814 129.9851 23.961 130.1082 ;
		RECT 0.2105 130.218 23.814 130.4196 ;
		RECT 23.814 130.218 23.961 130.4196 ;
		RECT 0.2105 130.6251 23.814 130.7482 ;
		RECT 23.814 130.6251 23.961 130.7482 ;
		RECT 0.2105 130.858 23.814 131.0596 ;
		RECT 23.814 130.858 23.961 131.0596 ;
		RECT 0.2105 131.2651 23.814 131.3882 ;
		RECT 23.814 131.2651 23.961 131.3882 ;
		RECT 0.2105 131.498 23.814 131.6996 ;
		RECT 23.814 131.498 23.961 131.6996 ;
		RECT 0.2105 131.9051 23.814 132.0282 ;
		RECT 23.814 131.9051 23.961 132.0282 ;
		RECT 0.2105 132.138 23.814 132.3396 ;
		RECT 23.814 132.138 23.961 132.3396 ;
		RECT 0.2105 132.5451 23.814 132.6682 ;
		RECT 23.814 132.5451 23.961 132.6682 ;
		RECT 0.2105 132.778 23.814 132.9796 ;
		RECT 23.814 132.778 23.961 132.9796 ;
		RECT 0.2105 133.1851 23.814 133.3082 ;
		RECT 23.814 133.1851 23.961 133.3082 ;
		RECT 0.2105 133.418 23.814 133.6196 ;
		RECT 23.814 133.418 23.961 133.6196 ;
		RECT 0.2105 133.8251 23.814 133.9482 ;
		RECT 23.814 133.8251 23.961 133.9482 ;
		RECT 0.2105 134.058 23.814 134.2596 ;
		RECT 23.814 134.058 23.961 134.2596 ;
		RECT 0.2105 134.4651 23.814 134.5882 ;
		RECT 23.814 134.4651 23.961 134.5882 ;
		RECT 0.2105 134.698 23.814 134.8996 ;
		RECT 23.814 134.698 23.961 134.8996 ;
		RECT 0.2105 135.1051 23.814 135.2282 ;
		RECT 23.814 135.1051 23.961 135.2282 ;
		RECT 0.2105 135.338 23.814 135.5396 ;
		RECT 23.814 135.338 23.961 135.5396 ;
		RECT 0.2105 135.7451 23.814 135.8682 ;
		RECT 23.814 135.7451 23.961 135.8682 ;
		RECT 0.2105 135.978 23.814 136.1796 ;
		RECT 23.814 135.978 23.961 136.1796 ;
		RECT 0.2105 136.3851 23.814 136.5082 ;
		RECT 23.814 136.3851 23.961 136.5082 ;
		RECT 0.2105 136.618 23.814 136.8196 ;
		RECT 23.814 136.618 23.961 136.8196 ;
		RECT 0.2105 137.0251 23.814 137.1482 ;
		RECT 23.814 137.0251 23.961 137.1482 ;
		RECT 0.2105 137.258 23.814 137.4596 ;
		RECT 23.814 137.258 23.961 137.4596 ;
		RECT 0.2105 137.6651 23.814 137.7882 ;
		RECT 23.814 137.6651 23.961 137.7882 ;
		RECT 0.2105 137.898 23.814 138.0996 ;
		RECT 23.814 137.898 23.961 138.0996 ;
		RECT 0.2105 138.3051 23.814 138.4282 ;
		RECT 23.814 138.3051 23.961 138.4282 ;
		RECT 0.2105 138.538 23.814 138.7396 ;
		RECT 23.814 138.538 23.961 138.7396 ;
		 LAYER M4 ;
		RECT 0.2105 0 23.814 0.022 ;
		RECT 23.814 0 23.961 0.022 ;
		RECT 0.2105 31.7443 23.814 31.7694 ;
		RECT 23.814 31.7443 23.961 31.7694 ;
		RECT 0.2105 37.9906 23.814 38.0157 ;
		RECT 23.814 37.9906 23.961 38.0157 ;
		RECT 0.2105 101.0525 23.814 101.0776 ;
		RECT 23.814 101.0525 23.961 101.0776 ;
		RECT 0.2105 107.2988 23.814 107.3239 ;
		RECT 23.814 107.2988 23.961 107.3239 ;
		RECT 0.2105 139.0463 23.814 139.0682 ;
		RECT 23.814 139.0463 23.961 139.0682 ;
		 LAYER M4 SPACING 0.018 ;
		RECT 0.2105 0 23.814 0.022 ;
		RECT 23.814 0 23.961 0.022 ;
		RECT 0.2105 31.7443 23.814 31.7694 ;
		RECT 23.814 31.7443 23.961 31.7694 ;
		RECT 0.2105 37.9906 23.814 38.0157 ;
		RECT 23.814 37.9906 23.961 38.0157 ;
		RECT 0.2105 101.0525 23.814 101.0776 ;
		RECT 23.814 101.0525 23.961 101.0776 ;
		RECT 0.2105 107.2988 23.814 107.3239 ;
		RECT 23.814 107.2988 23.961 107.3239 ;
		RECT 0.2105 139.0463 23.814 139.0682 ;
		RECT 23.814 139.0463 23.961 139.0682 ;
		 LAYER V1 SPACING 0 ;
		RECT 0 0 23.961 139.0682 ;
		 LAYER V2 SPACING 0 ;
		RECT 0.1097 0 23.961 139.0682 ;
		RECT 0 0 0.1097 0.0627 ;
		RECT 0 0.1631 0.1097 0.9663 ;
		RECT 0 1.0667 0.1097 1.0918 ;
		RECT 0 1.1922 0.1097 1.2424 ;
		RECT 0 1.3427 0.1097 1.3678 ;
		RECT 0 1.4682 0.1097 2.2463 ;
		RECT 0 2.3467 0.1097 2.3718 ;
		RECT 0 2.4722 0.1097 2.5224 ;
		RECT 0 2.6227 0.1097 2.6478 ;
		RECT 0 2.7482 0.1097 3.5263 ;
		RECT 0 3.6267 0.1097 3.6518 ;
		RECT 0 3.7522 0.1097 3.8024 ;
		RECT 0 3.9027 0.1097 3.9278 ;
		RECT 0 4.0282 0.1097 4.8063 ;
		RECT 0 4.9067 0.1097 4.9318 ;
		RECT 0 5.0322 0.1097 5.0824 ;
		RECT 0 5.1827 0.1097 5.2078 ;
		RECT 0 5.3082 0.1097 6.0863 ;
		RECT 0 6.1867 0.1097 6.2118 ;
		RECT 0 6.3122 0.1097 6.3624 ;
		RECT 0 6.4627 0.1097 6.4878 ;
		RECT 0 6.5882 0.1097 7.3663 ;
		RECT 0 7.4667 0.1097 7.4918 ;
		RECT 0 7.5922 0.1097 7.6424 ;
		RECT 0 7.7427 0.1097 7.7678 ;
		RECT 0 7.8682 0.1097 8.6463 ;
		RECT 0 8.7467 0.1097 8.7718 ;
		RECT 0 8.8722 0.1097 8.9224 ;
		RECT 0 9.0227 0.1097 9.0478 ;
		RECT 0 9.1482 0.1097 9.9263 ;
		RECT 0 10.0267 0.1097 10.0518 ;
		RECT 0 10.1522 0.1097 10.2024 ;
		RECT 0 10.3027 0.1097 10.3278 ;
		RECT 0 10.4282 0.1097 11.2063 ;
		RECT 0 11.3067 0.1097 11.3318 ;
		RECT 0 11.4322 0.1097 11.4824 ;
		RECT 0 11.5827 0.1097 11.6078 ;
		RECT 0 11.7082 0.1097 12.4863 ;
		RECT 0 12.5867 0.1097 12.6118 ;
		RECT 0 12.7122 0.1097 12.7624 ;
		RECT 0 12.8627 0.1097 12.8878 ;
		RECT 0 12.9882 0.1097 13.7663 ;
		RECT 0 13.8667 0.1097 13.8918 ;
		RECT 0 13.9922 0.1097 14.0424 ;
		RECT 0 14.1427 0.1097 14.1678 ;
		RECT 0 14.2682 0.1097 15.0463 ;
		RECT 0 15.1467 0.1097 15.1718 ;
		RECT 0 15.2722 0.1097 15.3224 ;
		RECT 0 15.4227 0.1097 15.4478 ;
		RECT 0 15.5482 0.1097 16.3263 ;
		RECT 0 16.4267 0.1097 16.4518 ;
		RECT 0 16.5522 0.1097 16.6024 ;
		RECT 0 16.7027 0.1097 16.7278 ;
		RECT 0 16.8282 0.1097 17.6063 ;
		RECT 0 17.7067 0.1097 17.7318 ;
		RECT 0 17.8322 0.1097 17.8824 ;
		RECT 0 17.9827 0.1097 18.0078 ;
		RECT 0 18.1082 0.1097 18.8863 ;
		RECT 0 18.9867 0.1097 19.0118 ;
		RECT 0 19.1122 0.1097 19.1624 ;
		RECT 0 19.2627 0.1097 19.2878 ;
		RECT 0 19.3882 0.1097 20.1663 ;
		RECT 0 20.2667 0.1097 20.2918 ;
		RECT 0 20.3922 0.1097 20.4424 ;
		RECT 0 20.5427 0.1097 20.5678 ;
		RECT 0 20.6682 0.1097 21.4463 ;
		RECT 0 21.5467 0.1097 21.5718 ;
		RECT 0 21.6722 0.1097 21.7224 ;
		RECT 0 21.8227 0.1097 21.8478 ;
		RECT 0 21.9482 0.1097 22.7263 ;
		RECT 0 22.8267 0.1097 22.8518 ;
		RECT 0 22.9522 0.1097 23.0024 ;
		RECT 0 23.1027 0.1097 23.1278 ;
		RECT 0 23.2282 0.1097 24.0063 ;
		RECT 0 24.1067 0.1097 24.1318 ;
		RECT 0 24.2322 0.1097 24.2824 ;
		RECT 0 24.3827 0.1097 24.4078 ;
		RECT 0 24.5082 0.1097 25.2863 ;
		RECT 0 25.3867 0.1097 25.4118 ;
		RECT 0 25.5122 0.1097 25.5624 ;
		RECT 0 25.6627 0.1097 25.6878 ;
		RECT 0 25.7882 0.1097 26.5663 ;
		RECT 0 26.6667 0.1097 26.6918 ;
		RECT 0 26.7922 0.1097 26.8424 ;
		RECT 0 26.9427 0.1097 26.9678 ;
		RECT 0 27.0682 0.1097 27.8463 ;
		RECT 0 27.9467 0.1097 27.9718 ;
		RECT 0 28.0722 0.1097 28.1224 ;
		RECT 0 28.2227 0.1097 28.2478 ;
		RECT 0 28.3482 0.1097 29.1263 ;
		RECT 0 29.2267 0.1097 29.2518 ;
		RECT 0 29.3522 0.1097 29.4024 ;
		RECT 0 29.5027 0.1097 29.5278 ;
		RECT 0 29.6282 0.1097 30.4063 ;
		RECT 0 30.5067 0.1097 30.5318 ;
		RECT 0 30.6322 0.1097 30.6824 ;
		RECT 0 30.7827 0.1097 30.8078 ;
		RECT 0 30.9082 0.1097 39.3851 ;
		RECT 0 39.4855 0.1097 39.5106 ;
		RECT 0 39.611 0.1097 39.6612 ;
		RECT 0 39.7616 0.1097 39.7867 ;
		RECT 0 39.8871 0.1097 40.6651 ;
		RECT 0 40.7655 0.1097 40.7906 ;
		RECT 0 40.891 0.1097 40.9412 ;
		RECT 0 41.0416 0.1097 41.0667 ;
		RECT 0 41.1671 0.1097 41.9451 ;
		RECT 0 42.0455 0.1097 42.0706 ;
		RECT 0 42.171 0.1097 42.2212 ;
		RECT 0 42.3216 0.1097 42.3467 ;
		RECT 0 42.4471 0.1097 43.2251 ;
		RECT 0 43.3255 0.1097 43.3506 ;
		RECT 0 43.451 0.1097 43.5012 ;
		RECT 0 43.6016 0.1097 43.6267 ;
		RECT 0 43.7271 0.1097 44.5051 ;
		RECT 0 44.6055 0.1097 44.6306 ;
		RECT 0 44.731 0.1097 44.7812 ;
		RECT 0 44.8816 0.1097 44.9067 ;
		RECT 0 45.0071 0.1097 45.7851 ;
		RECT 0 45.8855 0.1097 45.9106 ;
		RECT 0 46.011 0.1097 46.0612 ;
		RECT 0 46.1616 0.1097 46.1867 ;
		RECT 0 46.2871 0.1097 47.0651 ;
		RECT 0 47.1655 0.1097 47.1906 ;
		RECT 0 47.291 0.1097 47.3412 ;
		RECT 0 47.4416 0.1097 47.4667 ;
		RECT 0 47.5671 0.1097 48.3451 ;
		RECT 0 48.4455 0.1097 48.4706 ;
		RECT 0 48.571 0.1097 48.6212 ;
		RECT 0 48.7216 0.1097 48.7467 ;
		RECT 0 48.8471 0.1097 49.6251 ;
		RECT 0 49.7255 0.1097 49.7506 ;
		RECT 0 49.851 0.1097 49.9012 ;
		RECT 0 50.0016 0.1097 50.0267 ;
		RECT 0 50.1271 0.1097 50.9051 ;
		RECT 0 51.0055 0.1097 51.0306 ;
		RECT 0 51.131 0.1097 51.1812 ;
		RECT 0 51.2816 0.1097 51.3067 ;
		RECT 0 51.4071 0.1097 52.1851 ;
		RECT 0 52.2855 0.1097 52.3106 ;
		RECT 0 52.411 0.1097 52.4612 ;
		RECT 0 52.5616 0.1097 52.5867 ;
		RECT 0 52.6871 0.1097 53.4651 ;
		RECT 0 53.5655 0.1097 53.5906 ;
		RECT 0 53.691 0.1097 53.7412 ;
		RECT 0 53.8416 0.1097 53.8667 ;
		RECT 0 53.9671 0.1097 54.7451 ;
		RECT 0 54.8455 0.1097 54.8706 ;
		RECT 0 54.971 0.1097 55.0212 ;
		RECT 0 55.1216 0.1097 55.1467 ;
		RECT 0 55.2471 0.1097 56.0251 ;
		RECT 0 56.1255 0.1097 56.1506 ;
		RECT 0 56.251 0.1097 56.3012 ;
		RECT 0 56.4016 0.1097 56.4267 ;
		RECT 0 56.5271 0.1097 56.6525 ;
		RECT 0 56.7529 0.1097 57.2549 ;
		RECT 0 57.3553 0.1097 57.4055 ;
		RECT 0 57.5059 0.1097 57.7067 ;
		RECT 0 57.8071 0.1097 58.0831 ;
		RECT 0 58.1835 0.1097 58.5349 ;
		RECT 0 58.6353 0.1097 58.6855 ;
		RECT 0 58.7859 0.1097 58.9114 ;
		RECT 0 59.0118 0.1097 59.062 ;
		RECT 0 59.1624 0.1097 59.2125 ;
		RECT 0 59.3129 0.1097 59.3631 ;
		RECT 0 59.4635 0.1097 59.6643 ;
		RECT 0 59.7647 0.1097 59.8902 ;
		RECT 0 59.9906 0.1097 60.0408 ;
		RECT 0 60.1412 0.1097 60.1914 ;
		RECT 0 60.2918 0.1097 60.342 ;
		RECT 0 60.4424 0.1097 60.4925 ;
		RECT 0 60.5929 0.1097 60.869 ;
		RECT 0 60.9694 0.1097 61.0949 ;
		RECT 0 61.1953 0.1097 61.2455 ;
		RECT 0 61.3459 0.1097 61.4714 ;
		RECT 0 61.5718 0.1097 61.6973 ;
		RECT 0 61.7976 0.1097 61.8478 ;
		RECT 0 61.9482 0.1097 62.3749 ;
		RECT 0 62.4753 0.1097 62.5255 ;
		RECT 0 62.6259 0.1097 62.6761 ;
		RECT 0 62.7765 0.1097 62.8267 ;
		RECT 0 62.9271 0.1097 63.0525 ;
		RECT 0 63.1529 0.1097 63.6549 ;
		RECT 0 63.7553 0.1097 63.8055 ;
		RECT 0 63.9059 0.1097 63.9561 ;
		RECT 0 64.0565 0.1097 64.1067 ;
		RECT 0 64.2071 0.1097 64.2573 ;
		RECT 0 64.3576 0.1097 64.4078 ;
		RECT 0 64.5082 0.1097 64.9349 ;
		RECT 0 65.0353 0.1097 65.0855 ;
		RECT 0 65.1859 0.1097 65.2361 ;
		RECT 0 65.3365 0.1097 65.3867 ;
		RECT 0 65.4871 0.1097 65.5373 ;
		RECT 0 65.6376 0.1097 66.2149 ;
		RECT 0 66.3153 0.1097 66.3655 ;
		RECT 0 66.4659 0.1097 66.5914 ;
		RECT 0 66.6918 0.1097 67.4949 ;
		RECT 0 67.5953 0.1097 67.6455 ;
		RECT 0 67.7459 0.1097 67.9467 ;
		RECT 0 68.0471 0.1097 68.1725 ;
		RECT 0 68.2729 0.1097 68.3984 ;
		RECT 0 68.4988 0.1097 68.6243 ;
		RECT 0 68.7247 0.1097 68.7749 ;
		RECT 0 68.8753 0.1097 68.9255 ;
		RECT 0 69.0259 0.1097 69.0761 ;
		RECT 0 69.1765 0.1097 69.2267 ;
		RECT 0 69.3271 0.1097 69.7412 ;
		RECT 0 69.8416 0.1097 69.8918 ;
		RECT 0 69.9922 0.1097 70.0424 ;
		RECT 0 70.1427 0.1097 70.1929 ;
		RECT 0 70.2933 0.1097 70.5694 ;
		RECT 0 70.6698 0.1097 70.7953 ;
		RECT 0 70.8957 0.1097 71.0212 ;
		RECT 0 71.1216 0.1097 71.3224 ;
		RECT 0 71.4227 0.1097 71.4729 ;
		RECT 0 71.5733 0.1097 71.7741 ;
		RECT 0 71.8745 0.1097 72.0753 ;
		RECT 0 72.1757 0.1097 72.2259 ;
		RECT 0 72.3263 0.1097 72.3765 ;
		RECT 0 72.4769 0.1097 72.6024 ;
		RECT 0 72.7027 0.1097 72.7529 ;
		RECT 0 72.8533 0.1097 73.1294 ;
		RECT 0 73.2298 0.1097 73.3553 ;
		RECT 0 73.4557 0.1097 73.5059 ;
		RECT 0 73.6063 0.1097 73.7318 ;
		RECT 0 73.8322 0.1097 73.8824 ;
		RECT 0 73.9827 0.1097 74.0329 ;
		RECT 0 74.1333 0.1097 74.56 ;
		RECT 0 74.6604 0.1097 74.7106 ;
		RECT 0 74.811 0.1097 74.8612 ;
		RECT 0 74.9616 0.1097 75.0118 ;
		RECT 0 75.1122 0.1097 75.1624 ;
		RECT 0 75.2627 0.1097 75.3129 ;
		RECT 0 75.4133 0.1097 75.9153 ;
		RECT 0 76.0157 0.1097 76.1412 ;
		RECT 0 76.2416 0.1097 76.2918 ;
		RECT 0 76.3922 0.1097 76.4424 ;
		RECT 0 76.5427 0.1097 76.5929 ;
		RECT 0 76.6933 0.1097 77.2706 ;
		RECT 0 77.371 0.1097 77.4965 ;
		RECT 0 77.5969 0.1097 77.7224 ;
		RECT 0 77.8227 0.1097 77.8729 ;
		RECT 0 77.9733 0.1097 78.7765 ;
		RECT 0 78.8769 0.1097 78.9271 ;
		RECT 0 79.0275 0.1097 79.0776 ;
		RECT 0 79.178 0.1097 79.3035 ;
		RECT 0 79.4039 0.1097 79.68 ;
		RECT 0 79.7804 0.1097 79.9059 ;
		RECT 0 80.0063 0.1097 80.2824 ;
		RECT 0 80.3827 0.1097 80.4329 ;
		RECT 0 80.5333 0.1097 80.8094 ;
		RECT 0 80.9098 0.1097 81.2612 ;
		RECT 0 81.3616 0.1097 81.4118 ;
		RECT 0 81.5122 0.1097 81.5624 ;
		RECT 0 81.6627 0.1097 81.7129 ;
		RECT 0 81.8133 0.1097 82.3153 ;
		RECT 0 82.4157 0.1097 82.5412 ;
		RECT 0 82.6416 0.1097 82.6667 ;
		RECT 0 82.7671 0.1097 82.8173 ;
		RECT 0 82.9176 0.1097 82.9427 ;
		RECT 0 83.0431 0.1097 83.8212 ;
		RECT 0 83.9216 0.1097 83.9467 ;
		RECT 0 84.0471 0.1097 84.0973 ;
		RECT 0 84.1976 0.1097 84.2227 ;
		RECT 0 84.3231 0.1097 85.1012 ;
		RECT 0 85.2016 0.1097 85.2267 ;
		RECT 0 85.3271 0.1097 85.3773 ;
		RECT 0 85.4776 0.1097 85.5027 ;
		RECT 0 85.6031 0.1097 86.3812 ;
		RECT 0 86.4816 0.1097 86.5067 ;
		RECT 0 86.6071 0.1097 86.6573 ;
		RECT 0 86.7576 0.1097 86.7827 ;
		RECT 0 86.8831 0.1097 87.6612 ;
		RECT 0 87.7616 0.1097 87.7867 ;
		RECT 0 87.8871 0.1097 87.9373 ;
		RECT 0 88.0376 0.1097 88.0627 ;
		RECT 0 88.1631 0.1097 88.9412 ;
		RECT 0 89.0416 0.1097 89.0667 ;
		RECT 0 89.1671 0.1097 89.2173 ;
		RECT 0 89.3176 0.1097 89.3427 ;
		RECT 0 89.4431 0.1097 90.2212 ;
		RECT 0 90.3216 0.1097 90.3467 ;
		RECT 0 90.4471 0.1097 90.4973 ;
		RECT 0 90.5976 0.1097 90.6227 ;
		RECT 0 90.7231 0.1097 91.5012 ;
		RECT 0 91.6016 0.1097 91.6267 ;
		RECT 0 91.7271 0.1097 91.7773 ;
		RECT 0 91.8776 0.1097 91.9027 ;
		RECT 0 92.0031 0.1097 92.7812 ;
		RECT 0 92.8816 0.1097 92.9067 ;
		RECT 0 93.0071 0.1097 93.0573 ;
		RECT 0 93.1576 0.1097 93.1827 ;
		RECT 0 93.2831 0.1097 94.0612 ;
		RECT 0 94.1616 0.1097 94.1867 ;
		RECT 0 94.2871 0.1097 94.3373 ;
		RECT 0 94.4376 0.1097 94.4627 ;
		RECT 0 94.5631 0.1097 95.3412 ;
		RECT 0 95.4416 0.1097 95.4667 ;
		RECT 0 95.5671 0.1097 95.6173 ;
		RECT 0 95.7176 0.1097 95.7427 ;
		RECT 0 95.8431 0.1097 96.6212 ;
		RECT 0 96.7216 0.1097 96.7467 ;
		RECT 0 96.8471 0.1097 96.8973 ;
		RECT 0 96.9976 0.1097 97.0227 ;
		RECT 0 97.1231 0.1097 97.9012 ;
		RECT 0 98.0016 0.1097 98.0267 ;
		RECT 0 98.1271 0.1097 98.1773 ;
		RECT 0 98.2776 0.1097 98.3027 ;
		RECT 0 98.4031 0.1097 99.1812 ;
		RECT 0 99.2816 0.1097 99.3067 ;
		RECT 0 99.4071 0.1097 99.4573 ;
		RECT 0 99.5576 0.1097 99.5827 ;
		RECT 0 99.6831 0.1097 108.16 ;
		RECT 0 108.2604 0.1097 108.2855 ;
		RECT 0 108.3859 0.1097 108.4361 ;
		RECT 0 108.5365 0.1097 108.5616 ;
		RECT 0 108.662 0.1097 109.44 ;
		RECT 0 109.5404 0.1097 109.5655 ;
		RECT 0 109.6659 0.1097 109.7161 ;
		RECT 0 109.8165 0.1097 109.8416 ;
		RECT 0 109.942 0.1097 110.72 ;
		RECT 0 110.8204 0.1097 110.8455 ;
		RECT 0 110.9459 0.1097 110.9961 ;
		RECT 0 111.0965 0.1097 111.1216 ;
		RECT 0 111.222 0.1097 112 ;
		RECT 0 112.1004 0.1097 112.1255 ;
		RECT 0 112.2259 0.1097 112.2761 ;
		RECT 0 112.3765 0.1097 112.4016 ;
		RECT 0 112.502 0.1097 113.28 ;
		RECT 0 113.3804 0.1097 113.4055 ;
		RECT 0 113.5059 0.1097 113.5561 ;
		RECT 0 113.6565 0.1097 113.6816 ;
		RECT 0 113.782 0.1097 114.56 ;
		RECT 0 114.6604 0.1097 114.6855 ;
		RECT 0 114.7859 0.1097 114.8361 ;
		RECT 0 114.9365 0.1097 114.9616 ;
		RECT 0 115.062 0.1097 115.84 ;
		RECT 0 115.9404 0.1097 115.9655 ;
		RECT 0 116.0659 0.1097 116.1161 ;
		RECT 0 116.2165 0.1097 116.2416 ;
		RECT 0 116.342 0.1097 117.12 ;
		RECT 0 117.2204 0.1097 117.2455 ;
		RECT 0 117.3459 0.1097 117.3961 ;
		RECT 0 117.4965 0.1097 117.5216 ;
		RECT 0 117.622 0.1097 118.4 ;
		RECT 0 118.5004 0.1097 118.5255 ;
		RECT 0 118.6259 0.1097 118.6761 ;
		RECT 0 118.7765 0.1097 118.8016 ;
		RECT 0 118.902 0.1097 119.68 ;
		RECT 0 119.7804 0.1097 119.8055 ;
		RECT 0 119.9059 0.1097 119.9561 ;
		RECT 0 120.0565 0.1097 120.0816 ;
		RECT 0 120.182 0.1097 120.96 ;
		RECT 0 121.0604 0.1097 121.0855 ;
		RECT 0 121.1859 0.1097 121.2361 ;
		RECT 0 121.3365 0.1097 121.3616 ;
		RECT 0 121.462 0.1097 122.24 ;
		RECT 0 122.3404 0.1097 122.3655 ;
		RECT 0 122.4659 0.1097 122.5161 ;
		RECT 0 122.6165 0.1097 122.6416 ;
		RECT 0 122.742 0.1097 123.52 ;
		RECT 0 123.6204 0.1097 123.6455 ;
		RECT 0 123.7459 0.1097 123.7961 ;
		RECT 0 123.8965 0.1097 123.9216 ;
		RECT 0 124.022 0.1097 124.8 ;
		RECT 0 124.9004 0.1097 124.9255 ;
		RECT 0 125.0259 0.1097 125.0761 ;
		RECT 0 125.1765 0.1097 125.2016 ;
		RECT 0 125.302 0.1097 126.08 ;
		RECT 0 126.1804 0.1097 126.2055 ;
		RECT 0 126.3059 0.1097 126.3561 ;
		RECT 0 126.4565 0.1097 126.4816 ;
		RECT 0 126.582 0.1097 127.36 ;
		RECT 0 127.4604 0.1097 127.4855 ;
		RECT 0 127.5859 0.1097 127.6361 ;
		RECT 0 127.7365 0.1097 127.7616 ;
		RECT 0 127.862 0.1097 128.64 ;
		RECT 0 128.7404 0.1097 128.7655 ;
		RECT 0 128.8659 0.1097 128.9161 ;
		RECT 0 129.0165 0.1097 129.0416 ;
		RECT 0 129.142 0.1097 129.92 ;
		RECT 0 130.0204 0.1097 130.0455 ;
		RECT 0 130.1459 0.1097 130.1961 ;
		RECT 0 130.2965 0.1097 130.3216 ;
		RECT 0 130.422 0.1097 131.2 ;
		RECT 0 131.3004 0.1097 131.3255 ;
		RECT 0 131.4259 0.1097 131.4761 ;
		RECT 0 131.5765 0.1097 131.6016 ;
		RECT 0 131.702 0.1097 132.48 ;
		RECT 0 132.5804 0.1097 132.6055 ;
		RECT 0 132.7059 0.1097 132.7561 ;
		RECT 0 132.8565 0.1097 132.8816 ;
		RECT 0 132.982 0.1097 133.76 ;
		RECT 0 133.8604 0.1097 133.8855 ;
		RECT 0 133.9859 0.1097 134.0361 ;
		RECT 0 134.1365 0.1097 134.1616 ;
		RECT 0 134.262 0.1097 135.04 ;
		RECT 0 135.1404 0.1097 135.1655 ;
		RECT 0 135.2659 0.1097 135.3161 ;
		RECT 0 135.4165 0.1097 135.4416 ;
		RECT 0 135.542 0.1097 136.32 ;
		RECT 0 136.4204 0.1097 136.4455 ;
		RECT 0 136.5459 0.1097 136.5961 ;
		RECT 0 136.6965 0.1097 136.7216 ;
		RECT 0 136.822 0.1097 137.6 ;
		RECT 0 137.7004 0.1097 137.7255 ;
		RECT 0 137.8259 0.1097 137.8761 ;
		RECT 0 137.9765 0.1097 138.0016 ;
		RECT 0 138.102 0.1097 138.9051 ;
		RECT 0 139.0055 0.1097 139.0682 ;
		 LAYER V2 ;
		RECT 0.0481 1.0918 0.1097 1.2424 ;
		RECT 0.0481 1.2424 0.1097 1.3678 ;
		RECT 0.0481 2.3718 0.1097 2.5224 ;
		RECT 0.0481 2.5224 0.1097 2.6478 ;
		RECT 0.0481 3.6518 0.1097 3.8024 ;
		RECT 0.0481 3.8024 0.1097 3.9278 ;
		RECT 0.0481 4.9318 0.1097 5.0824 ;
		RECT 0.0481 5.0824 0.1097 5.2078 ;
		RECT 0.0481 6.2118 0.1097 6.3624 ;
		RECT 0.0481 6.3624 0.1097 6.4878 ;
		RECT 0.0481 7.4918 0.1097 7.6424 ;
		RECT 0.0481 7.6424 0.1097 7.7678 ;
		RECT 0.0481 8.7718 0.1097 8.9224 ;
		RECT 0.0481 8.9224 0.1097 9.0478 ;
		RECT 0.0481 10.0518 0.1097 10.2024 ;
		RECT 0.0481 10.2024 0.1097 10.3278 ;
		RECT 0.0481 11.3318 0.1097 11.4824 ;
		RECT 0.0481 11.4824 0.1097 11.6078 ;
		RECT 0.0481 12.6118 0.1097 12.7624 ;
		RECT 0.0481 12.7624 0.1097 12.8878 ;
		RECT 0.0481 13.8918 0.1097 14.0424 ;
		RECT 0.0481 14.0424 0.1097 14.1678 ;
		RECT 0.0481 15.1718 0.1097 15.3224 ;
		RECT 0.0481 15.3224 0.1097 15.4478 ;
		RECT 0.0481 16.4518 0.1097 16.6024 ;
		RECT 0.0481 16.6024 0.1097 16.7278 ;
		RECT 0.0481 17.7318 0.1097 17.8824 ;
		RECT 0.0481 17.8824 0.1097 18.0078 ;
		RECT 0.0481 19.0118 0.1097 19.1624 ;
		RECT 0.0481 19.1624 0.1097 19.2878 ;
		RECT 0.0481 20.2918 0.1097 20.4424 ;
		RECT 0.0481 20.4424 0.1097 20.5678 ;
		RECT 0.0481 21.5718 0.1097 21.7224 ;
		RECT 0.0481 21.7224 0.1097 21.8478 ;
		RECT 0.0481 22.8518 0.1097 23.0024 ;
		RECT 0.0481 23.0024 0.1097 23.1278 ;
		RECT 0.0481 24.1318 0.1097 24.2824 ;
		RECT 0.0481 24.2824 0.1097 24.4078 ;
		RECT 0.0481 25.4118 0.1097 25.5624 ;
		RECT 0.0481 25.5624 0.1097 25.6878 ;
		RECT 0.0481 26.6918 0.1097 26.8424 ;
		RECT 0.0481 26.8424 0.1097 26.9678 ;
		RECT 0.0481 27.9718 0.1097 28.1224 ;
		RECT 0.0481 28.1224 0.1097 28.2478 ;
		RECT 0.0481 29.2518 0.1097 29.4024 ;
		RECT 0.0481 29.4024 0.1097 29.5278 ;
		RECT 0.0481 30.5318 0.1097 30.6824 ;
		RECT 0.0481 30.6824 0.1097 30.8078 ;
		RECT 0.0481 39.5106 0.1097 39.6612 ;
		RECT 0.0481 39.6612 0.1097 39.7867 ;
		RECT 0.0481 40.7906 0.1097 40.9412 ;
		RECT 0.0481 40.9412 0.1097 41.0667 ;
		RECT 0.0481 42.0706 0.1097 42.2212 ;
		RECT 0.0481 42.2212 0.1097 42.3467 ;
		RECT 0.0481 43.3506 0.1097 43.5012 ;
		RECT 0.0481 43.5012 0.1097 43.6267 ;
		RECT 0.0481 44.6306 0.1097 44.7812 ;
		RECT 0.0481 44.7812 0.1097 44.9067 ;
		RECT 0.0481 45.9106 0.1097 46.0612 ;
		RECT 0.0481 46.0612 0.1097 46.1867 ;
		RECT 0.0481 47.1906 0.1097 47.3412 ;
		RECT 0.0481 47.3412 0.1097 47.4667 ;
		RECT 0.0481 48.4706 0.1097 48.6212 ;
		RECT 0.0481 48.6212 0.1097 48.7467 ;
		RECT 0.0481 49.7506 0.1097 49.9012 ;
		RECT 0.0481 49.9012 0.1097 50.0267 ;
		RECT 0.0481 51.0306 0.1097 51.1812 ;
		RECT 0.0481 51.1812 0.1097 51.3067 ;
		RECT 0.0481 52.3106 0.1097 52.4612 ;
		RECT 0.0481 52.4612 0.1097 52.5867 ;
		RECT 0.0481 53.5906 0.1097 53.7412 ;
		RECT 0.0481 53.7412 0.1097 53.8667 ;
		RECT 0.0481 54.8706 0.1097 55.0212 ;
		RECT 0.0481 55.0212 0.1097 55.1467 ;
		RECT 0.0481 56.1506 0.1097 56.3012 ;
		RECT 0.0481 56.3012 0.1097 56.4267 ;
		RECT 0.0481 58.0831 0.1097 58.5349 ;
		RECT 0.0481 60.4925 0.1097 60.869 ;
		RECT 0.0481 60.869 0.1097 61.0949 ;
		RECT 0.0481 61.8478 0.1097 62.3749 ;
		RECT 0.0481 68.6243 0.1097 68.7749 ;
		RECT 0.0481 71.7741 0.1097 72.0753 ;
		RECT 0.0481 72.0753 0.1097 72.2259 ;
		RECT 0.0481 73.1294 0.1097 73.3553 ;
		RECT 0.0481 73.7318 0.1097 73.8824 ;
		RECT 0.0481 73.8824 0.1097 74.0329 ;
		RECT 0.0481 76.2918 0.1097 76.4424 ;
		RECT 0.0481 77.2706 0.1097 77.4965 ;
		RECT 0.0481 78.9271 0.1097 79.0776 ;
		RECT 0.0481 79.68 0.1097 79.9059 ;
		RECT 0.0481 79.9059 0.1097 80.2824 ;
		RECT 0.0481 82.6667 0.1097 82.8173 ;
		RECT 0.0481 82.8173 0.1097 82.9427 ;
		RECT 0.0481 83.9467 0.1097 84.0973 ;
		RECT 0.0481 84.0973 0.1097 84.2227 ;
		RECT 0.0481 85.2267 0.1097 85.3773 ;
		RECT 0.0481 85.3773 0.1097 85.5027 ;
		RECT 0.0481 86.5067 0.1097 86.6573 ;
		RECT 0.0481 86.6573 0.1097 86.7827 ;
		RECT 0.0481 87.7867 0.1097 87.9373 ;
		RECT 0.0481 87.9373 0.1097 88.0627 ;
		RECT 0.0481 89.0667 0.1097 89.2173 ;
		RECT 0.0481 89.2173 0.1097 89.3427 ;
		RECT 0.0481 90.3467 0.1097 90.4973 ;
		RECT 0.0481 90.4973 0.1097 90.6227 ;
		RECT 0.0481 91.6267 0.1097 91.7773 ;
		RECT 0.0481 91.7773 0.1097 91.9027 ;
		RECT 0.0481 92.9067 0.1097 93.0573 ;
		RECT 0.0481 93.0573 0.1097 93.1827 ;
		RECT 0.0481 94.1867 0.1097 94.3373 ;
		RECT 0.0481 94.3373 0.1097 94.4627 ;
		RECT 0.0481 95.4667 0.1097 95.6173 ;
		RECT 0.0481 95.6173 0.1097 95.7427 ;
		RECT 0.0481 96.7467 0.1097 96.8973 ;
		RECT 0.0481 96.8973 0.1097 97.0227 ;
		RECT 0.0481 98.0267 0.1097 98.1773 ;
		RECT 0.0481 98.1773 0.1097 98.3027 ;
		RECT 0.0481 99.3067 0.1097 99.4573 ;
		RECT 0.0481 99.4573 0.1097 99.5827 ;
		RECT 0.0481 108.2855 0.1097 108.4361 ;
		RECT 0.0481 108.4361 0.1097 108.5616 ;
		RECT 0.0481 109.5655 0.1097 109.7161 ;
		RECT 0.0481 109.7161 0.1097 109.8416 ;
		RECT 0.0481 110.8455 0.1097 110.9961 ;
		RECT 0.0481 110.9961 0.1097 111.1216 ;
		RECT 0.0481 112.1255 0.1097 112.2761 ;
		RECT 0.0481 112.2761 0.1097 112.4016 ;
		RECT 0.0481 113.4055 0.1097 113.5561 ;
		RECT 0.0481 113.5561 0.1097 113.6816 ;
		RECT 0.0481 114.6855 0.1097 114.8361 ;
		RECT 0.0481 114.8361 0.1097 114.9616 ;
		RECT 0.0481 115.9655 0.1097 116.1161 ;
		RECT 0.0481 116.1161 0.1097 116.2416 ;
		RECT 0.0481 117.2455 0.1097 117.3961 ;
		RECT 0.0481 117.3961 0.1097 117.5216 ;
		RECT 0.0481 118.5255 0.1097 118.6761 ;
		RECT 0.0481 118.6761 0.1097 118.8016 ;
		RECT 0.0481 119.8055 0.1097 119.9561 ;
		RECT 0.0481 119.9561 0.1097 120.0816 ;
		RECT 0.0481 121.0855 0.1097 121.2361 ;
		RECT 0.0481 121.2361 0.1097 121.3616 ;
		RECT 0.0481 122.3655 0.1097 122.5161 ;
		RECT 0.0481 122.5161 0.1097 122.6416 ;
		RECT 0.0481 123.6455 0.1097 123.7961 ;
		RECT 0.0481 123.7961 0.1097 123.9216 ;
		RECT 0.0481 124.9255 0.1097 125.0761 ;
		RECT 0.0481 125.0761 0.1097 125.2016 ;
		RECT 0.0481 126.2055 0.1097 126.3561 ;
		RECT 0.0481 126.3561 0.1097 126.4816 ;
		RECT 0.0481 127.4855 0.1097 127.6361 ;
		RECT 0.0481 127.6361 0.1097 127.7616 ;
		RECT 0.0481 128.7655 0.1097 128.9161 ;
		RECT 0.0481 128.9161 0.1097 129.0416 ;
		RECT 0.0481 130.0455 0.1097 130.1961 ;
		RECT 0.0481 130.1961 0.1097 130.3216 ;
		RECT 0.0481 131.3255 0.1097 131.4761 ;
		RECT 0.0481 131.4761 0.1097 131.6016 ;
		RECT 0.0481 132.6055 0.1097 132.7561 ;
		RECT 0.0481 132.7561 0.1097 132.8816 ;
		RECT 0.0481 133.8855 0.1097 134.0361 ;
		RECT 0.0481 134.0361 0.1097 134.1616 ;
		RECT 0.0481 135.1655 0.1097 135.3161 ;
		RECT 0.0481 135.3161 0.1097 135.4416 ;
		RECT 0.0481 136.4455 0.1097 136.5961 ;
		RECT 0.0481 136.5961 0.1097 136.7216 ;
		RECT 0.0481 137.7255 0.1097 137.8761 ;
		RECT 0.0481 137.8761 0.1097 138.0016 ;
		RECT 0.021 31.2843 0.0359 31.2969 ;
		RECT 0.021 31.7361 0.0359 31.7486 ;
		RECT 0.021 31.8263 0.0359 31.8388 ;
		RECT 0.021 32.1376 0.0359 32.1502 ;
		RECT 0.021 32.6898 0.0359 32.7024 ;
		RECT 0.021 35.2749 0.0359 35.2875 ;
		RECT 0.021 35.6012 0.0359 35.6137 ;
		RECT 0.021 36.0027 0.0359 36.0153 ;
		RECT 0.021 37.082 0.0359 37.0945 ;
		RECT 0.021 37.4082 0.0359 37.4208 ;
		RECT 0.021 37.5839 0.0359 37.5965 ;
		RECT 0.021 37.9855 0.0359 37.998 ;
		RECT 0.0215 60.4169 0.0364 60.4294 ;
		RECT 0.0215 63.8804 0.0364 63.8929 ;
		RECT 0.0215 64.031 0.0364 64.0435 ;
		RECT 0.0831 64.1188 0.098 64.1314 ;
		RECT 0.0215 65.1604 0.0364 65.1729 ;
		RECT 0.0831 65.2482 0.098 65.2608 ;
		RECT 0.0831 65.3988 0.098 65.4114 ;
		RECT 0.0215 65.6122 0.0364 65.6247 ;
		RECT 0.021 65.7008 0.0359 65.7133 ;
		RECT 0.021 65.8514 0.0359 65.8639 ;
		RECT 0.021 66.7549 0.0359 66.7675 ;
		RECT 0.021 66.9055 0.0359 66.918 ;
		RECT 0.021 67.2067 0.0359 67.2192 ;
		RECT 0.0215 0.1376 0.0364 0.1502 ;
		RECT 0.021 107.7714 0.0359 107.7839 ;
		RECT 0.021 107.3196 0.0359 107.3322 ;
		RECT 0.021 107.2294 0.0359 107.242 ;
		RECT 0.021 106.918 0.0359 106.9306 ;
		RECT 0.021 106.3659 0.0359 106.3784 ;
		RECT 0.021 104.8098 0.0359 104.8224 ;
		RECT 0.021 103.7808 0.0359 103.7933 ;
		RECT 0.021 103.4545 0.0359 103.4671 ;
		RECT 0.021 103.0529 0.0359 103.0655 ;
		RECT 0.021 101.9737 0.0359 101.9863 ;
		RECT 0.021 101.6475 0.0359 101.66 ;
		RECT 0.021 101.4718 0.0359 101.4843 ;
		RECT 0.021 101.0702 0.0359 101.0827 ;
		RECT 0.021 82.089 0.0359 82.1016 ;
		RECT 0.021 81.9384 0.0359 81.951 ;
		RECT 0.0215 81.5753 0.0364 81.5878 ;
		RECT 0.0215 80.8224 0.0364 80.8349 ;
		RECT 0.0215 72.2388 0.0364 72.2514 ;
		RECT 0.0831 71.2475 0.098 71.26 ;
		RECT 0.0215 71.1847 0.0364 71.1973 ;
		RECT 0.0215 70.8082 0.0364 70.8208 ;
		RECT 0.0215 70.5824 0.0364 70.5949 ;
		RECT 0.0831 70.4192 0.098 70.4318 ;
		RECT 0.0215 70.3565 0.0364 70.369 ;
		RECT 0.0215 138.918 0.0364 138.9306 ;
		 LAYER V2 SPACING 0 ;
		RECT 0.0481 1.0918 0.1097 1.2424 ;
		RECT 0.0481 1.2424 0.1097 1.3678 ;
		RECT 0.0481 2.3718 0.1097 2.5224 ;
		RECT 0.0481 2.5224 0.1097 2.6478 ;
		RECT 0.0481 3.6518 0.1097 3.8024 ;
		RECT 0.0481 3.8024 0.1097 3.9278 ;
		RECT 0.0481 4.9318 0.1097 5.0824 ;
		RECT 0.0481 5.0824 0.1097 5.2078 ;
		RECT 0.0481 6.2118 0.1097 6.3624 ;
		RECT 0.0481 6.3624 0.1097 6.4878 ;
		RECT 0.0481 7.4918 0.1097 7.6424 ;
		RECT 0.0481 7.6424 0.1097 7.7678 ;
		RECT 0.0481 8.7718 0.1097 8.9224 ;
		RECT 0.0481 8.9224 0.1097 9.0478 ;
		RECT 0.0481 10.0518 0.1097 10.2024 ;
		RECT 0.0481 10.2024 0.1097 10.3278 ;
		RECT 0.0481 11.3318 0.1097 11.4824 ;
		RECT 0.0481 11.4824 0.1097 11.6078 ;
		RECT 0.0481 12.6118 0.1097 12.7624 ;
		RECT 0.0481 12.7624 0.1097 12.8878 ;
		RECT 0.0481 13.8918 0.1097 14.0424 ;
		RECT 0.0481 14.0424 0.1097 14.1678 ;
		RECT 0.0481 15.1718 0.1097 15.3224 ;
		RECT 0.0481 15.3224 0.1097 15.4478 ;
		RECT 0.0481 16.4518 0.1097 16.6024 ;
		RECT 0.0481 16.6024 0.1097 16.7278 ;
		RECT 0.0481 17.7318 0.1097 17.8824 ;
		RECT 0.0481 17.8824 0.1097 18.0078 ;
		RECT 0.0481 19.0118 0.1097 19.1624 ;
		RECT 0.0481 19.1624 0.1097 19.2878 ;
		RECT 0.0481 20.2918 0.1097 20.4424 ;
		RECT 0.0481 20.4424 0.1097 20.5678 ;
		RECT 0.0481 21.5718 0.1097 21.7224 ;
		RECT 0.0481 21.7224 0.1097 21.8478 ;
		RECT 0.0481 22.8518 0.1097 23.0024 ;
		RECT 0.0481 23.0024 0.1097 23.1278 ;
		RECT 0.0481 24.1318 0.1097 24.2824 ;
		RECT 0.0481 24.2824 0.1097 24.4078 ;
		RECT 0.0481 25.4118 0.1097 25.5624 ;
		RECT 0.0481 25.5624 0.1097 25.6878 ;
		RECT 0.0481 26.6918 0.1097 26.8424 ;
		RECT 0.0481 26.8424 0.1097 26.9678 ;
		RECT 0.0481 27.9718 0.1097 28.1224 ;
		RECT 0.0481 28.1224 0.1097 28.2478 ;
		RECT 0.0481 29.2518 0.1097 29.4024 ;
		RECT 0.0481 29.4024 0.1097 29.5278 ;
		RECT 0.0481 30.5318 0.1097 30.6824 ;
		RECT 0.0481 30.6824 0.1097 30.8078 ;
		RECT 0.0481 39.5106 0.1097 39.6612 ;
		RECT 0.0481 39.6612 0.1097 39.7867 ;
		RECT 0.0481 40.7906 0.1097 40.9412 ;
		RECT 0.0481 40.9412 0.1097 41.0667 ;
		RECT 0.0481 42.0706 0.1097 42.2212 ;
		RECT 0.0481 42.2212 0.1097 42.3467 ;
		RECT 0.0481 43.3506 0.1097 43.5012 ;
		RECT 0.0481 43.5012 0.1097 43.6267 ;
		RECT 0.0481 44.6306 0.1097 44.7812 ;
		RECT 0.0481 44.7812 0.1097 44.9067 ;
		RECT 0.0481 45.9106 0.1097 46.0612 ;
		RECT 0.0481 46.0612 0.1097 46.1867 ;
		RECT 0.0481 47.1906 0.1097 47.3412 ;
		RECT 0.0481 47.3412 0.1097 47.4667 ;
		RECT 0.0481 48.4706 0.1097 48.6212 ;
		RECT 0.0481 48.6212 0.1097 48.7467 ;
		RECT 0.0481 49.7506 0.1097 49.9012 ;
		RECT 0.0481 49.9012 0.1097 50.0267 ;
		RECT 0.0481 51.0306 0.1097 51.1812 ;
		RECT 0.0481 51.1812 0.1097 51.3067 ;
		RECT 0.0481 52.3106 0.1097 52.4612 ;
		RECT 0.0481 52.4612 0.1097 52.5867 ;
		RECT 0.0481 53.5906 0.1097 53.7412 ;
		RECT 0.0481 53.7412 0.1097 53.8667 ;
		RECT 0.0481 54.8706 0.1097 55.0212 ;
		RECT 0.0481 55.0212 0.1097 55.1467 ;
		RECT 0.0481 56.1506 0.1097 56.3012 ;
		RECT 0.0481 56.3012 0.1097 56.4267 ;
		RECT 0.0481 58.0831 0.1097 58.5349 ;
		RECT 0.0481 60.4925 0.1097 60.869 ;
		RECT 0.0481 60.869 0.1097 61.0949 ;
		RECT 0.0481 61.8478 0.1097 62.3749 ;
		RECT 0.0481 68.6243 0.1097 68.7749 ;
		RECT 0.0481 71.7741 0.1097 72.0753 ;
		RECT 0.0481 72.0753 0.1097 72.2259 ;
		RECT 0.0481 73.1294 0.1097 73.3553 ;
		RECT 0.0481 73.7318 0.1097 73.8824 ;
		RECT 0.0481 73.8824 0.1097 74.0329 ;
		RECT 0.0481 76.2918 0.1097 76.4424 ;
		RECT 0.0481 77.2706 0.1097 77.4965 ;
		RECT 0.0481 78.9271 0.1097 79.0776 ;
		RECT 0.0481 79.68 0.1097 79.9059 ;
		RECT 0.0481 79.9059 0.1097 80.2824 ;
		RECT 0.0481 82.6667 0.1097 82.8173 ;
		RECT 0.0481 82.8173 0.1097 82.9427 ;
		RECT 0.0481 83.9467 0.1097 84.0973 ;
		RECT 0.0481 84.0973 0.1097 84.2227 ;
		RECT 0.0481 85.2267 0.1097 85.3773 ;
		RECT 0.0481 85.3773 0.1097 85.5027 ;
		RECT 0.0481 86.5067 0.1097 86.6573 ;
		RECT 0.0481 86.6573 0.1097 86.7827 ;
		RECT 0.0481 87.7867 0.1097 87.9373 ;
		RECT 0.0481 87.9373 0.1097 88.0627 ;
		RECT 0.0481 89.0667 0.1097 89.2173 ;
		RECT 0.0481 89.2173 0.1097 89.3427 ;
		RECT 0.0481 90.3467 0.1097 90.4973 ;
		RECT 0.0481 90.4973 0.1097 90.6227 ;
		RECT 0.0481 91.6267 0.1097 91.7773 ;
		RECT 0.0481 91.7773 0.1097 91.9027 ;
		RECT 0.0481 92.9067 0.1097 93.0573 ;
		RECT 0.0481 93.0573 0.1097 93.1827 ;
		RECT 0.0481 94.1867 0.1097 94.3373 ;
		RECT 0.0481 94.3373 0.1097 94.4627 ;
		RECT 0.0481 95.4667 0.1097 95.6173 ;
		RECT 0.0481 95.6173 0.1097 95.7427 ;
		RECT 0.0481 96.7467 0.1097 96.8973 ;
		RECT 0.0481 96.8973 0.1097 97.0227 ;
		RECT 0.0481 98.0267 0.1097 98.1773 ;
		RECT 0.0481 98.1773 0.1097 98.3027 ;
		RECT 0.0481 99.3067 0.1097 99.4573 ;
		RECT 0.0481 99.4573 0.1097 99.5827 ;
		RECT 0.0481 108.2855 0.1097 108.4361 ;
		RECT 0.0481 108.4361 0.1097 108.5616 ;
		RECT 0.0481 109.5655 0.1097 109.7161 ;
		RECT 0.0481 109.7161 0.1097 109.8416 ;
		RECT 0.0481 110.8455 0.1097 110.9961 ;
		RECT 0.0481 110.9961 0.1097 111.1216 ;
		RECT 0.0481 112.1255 0.1097 112.2761 ;
		RECT 0.0481 112.2761 0.1097 112.4016 ;
		RECT 0.0481 113.4055 0.1097 113.5561 ;
		RECT 0.0481 113.5561 0.1097 113.6816 ;
		RECT 0.0481 114.6855 0.1097 114.8361 ;
		RECT 0.0481 114.8361 0.1097 114.9616 ;
		RECT 0.0481 115.9655 0.1097 116.1161 ;
		RECT 0.0481 116.1161 0.1097 116.2416 ;
		RECT 0.0481 117.2455 0.1097 117.3961 ;
		RECT 0.0481 117.3961 0.1097 117.5216 ;
		RECT 0.0481 118.5255 0.1097 118.6761 ;
		RECT 0.0481 118.6761 0.1097 118.8016 ;
		RECT 0.0481 119.8055 0.1097 119.9561 ;
		RECT 0.0481 119.9561 0.1097 120.0816 ;
		RECT 0.0481 121.0855 0.1097 121.2361 ;
		RECT 0.0481 121.2361 0.1097 121.3616 ;
		RECT 0.0481 122.3655 0.1097 122.5161 ;
		RECT 0.0481 122.5161 0.1097 122.6416 ;
		RECT 0.0481 123.6455 0.1097 123.7961 ;
		RECT 0.0481 123.7961 0.1097 123.9216 ;
		RECT 0.0481 124.9255 0.1097 125.0761 ;
		RECT 0.0481 125.0761 0.1097 125.2016 ;
		RECT 0.0481 126.2055 0.1097 126.3561 ;
		RECT 0.0481 126.3561 0.1097 126.4816 ;
		RECT 0.0481 127.4855 0.1097 127.6361 ;
		RECT 0.0481 127.6361 0.1097 127.7616 ;
		RECT 0.0481 128.7655 0.1097 128.9161 ;
		RECT 0.0481 128.9161 0.1097 129.0416 ;
		RECT 0.0481 130.0455 0.1097 130.1961 ;
		RECT 0.0481 130.1961 0.1097 130.3216 ;
		RECT 0.0481 131.3255 0.1097 131.4761 ;
		RECT 0.0481 131.4761 0.1097 131.6016 ;
		RECT 0.0481 132.6055 0.1097 132.7561 ;
		RECT 0.0481 132.7561 0.1097 132.8816 ;
		RECT 0.0481 133.8855 0.1097 134.0361 ;
		RECT 0.0481 134.0361 0.1097 134.1616 ;
		RECT 0.0481 135.1655 0.1097 135.3161 ;
		RECT 0.0481 135.3161 0.1097 135.4416 ;
		RECT 0.0481 136.4455 0.1097 136.5961 ;
		RECT 0.0481 136.5961 0.1097 136.7216 ;
		RECT 0.0481 137.7255 0.1097 137.8761 ;
		RECT 0.0481 137.8761 0.1097 138.0016 ;
		RECT 0.021 31.2843 0.0359 31.2969 ;
		RECT 0.021 31.7361 0.0359 31.7486 ;
		RECT 0.021 31.8263 0.0359 31.8388 ;
		RECT 0.021 32.1376 0.0359 32.1502 ;
		RECT 0.021 32.6898 0.0359 32.7024 ;
		RECT 0.021 35.2749 0.0359 35.2875 ;
		RECT 0.021 35.6012 0.0359 35.6137 ;
		RECT 0.021 36.0027 0.0359 36.0153 ;
		RECT 0.021 37.082 0.0359 37.0945 ;
		RECT 0.021 37.4082 0.0359 37.4208 ;
		RECT 0.021 37.5839 0.0359 37.5965 ;
		RECT 0.021 37.9855 0.0359 37.998 ;
		RECT 0.0215 60.4169 0.0364 60.4294 ;
		RECT 0.0215 63.8804 0.0364 63.8929 ;
		RECT 0.0215 64.031 0.0364 64.0435 ;
		RECT 0.0831 64.1188 0.098 64.1314 ;
		RECT 0.0215 65.1604 0.0364 65.1729 ;
		RECT 0.0831 65.2482 0.098 65.2608 ;
		RECT 0.0831 65.3988 0.098 65.4114 ;
		RECT 0.0215 65.6122 0.0364 65.6247 ;
		RECT 0.021 65.7008 0.0359 65.7133 ;
		RECT 0.021 65.8514 0.0359 65.8639 ;
		RECT 0.021 66.7549 0.0359 66.7675 ;
		RECT 0.021 66.9055 0.0359 66.918 ;
		RECT 0.021 67.2067 0.0359 67.2192 ;
		RECT 0.0215 0.1376 0.0364 0.1502 ;
		RECT 0.021 107.7714 0.0359 107.7839 ;
		RECT 0.021 107.3196 0.0359 107.3322 ;
		RECT 0.021 107.2294 0.0359 107.242 ;
		RECT 0.021 106.918 0.0359 106.9306 ;
		RECT 0.021 106.3659 0.0359 106.3784 ;
		RECT 0.021 104.8098 0.0359 104.8224 ;
		RECT 0.021 103.7808 0.0359 103.7933 ;
		RECT 0.021 103.4545 0.0359 103.4671 ;
		RECT 0.021 103.0529 0.0359 103.0655 ;
		RECT 0.021 101.9737 0.0359 101.9863 ;
		RECT 0.021 101.6475 0.0359 101.66 ;
		RECT 0.021 101.4718 0.0359 101.4843 ;
		RECT 0.021 101.0702 0.0359 101.0827 ;
		RECT 0.021 82.089 0.0359 82.1016 ;
		RECT 0.021 81.9384 0.0359 81.951 ;
		RECT 0.0215 81.5753 0.0364 81.5878 ;
		RECT 0.0215 80.8224 0.0364 80.8349 ;
		RECT 0.0215 72.2388 0.0364 72.2514 ;
		RECT 0.0831 71.2475 0.098 71.26 ;
		RECT 0.0215 71.1847 0.0364 71.1973 ;
		RECT 0.0215 70.8082 0.0364 70.8208 ;
		RECT 0.0215 70.5824 0.0364 70.5949 ;
		RECT 0.0831 70.4192 0.098 70.4318 ;
		RECT 0.0215 70.3565 0.0364 70.369 ;
		RECT 0.0215 138.918 0.0364 138.9306 ;
	END

END HD_1024X96M8B2

END LIBRARY

